VERSION 5.8 ;
BUSBITCHARS "[]" ;
DIVIDERCHAR "/" ;
UNITS
    DATABASE MICRONS 1000 ;
END UNITS

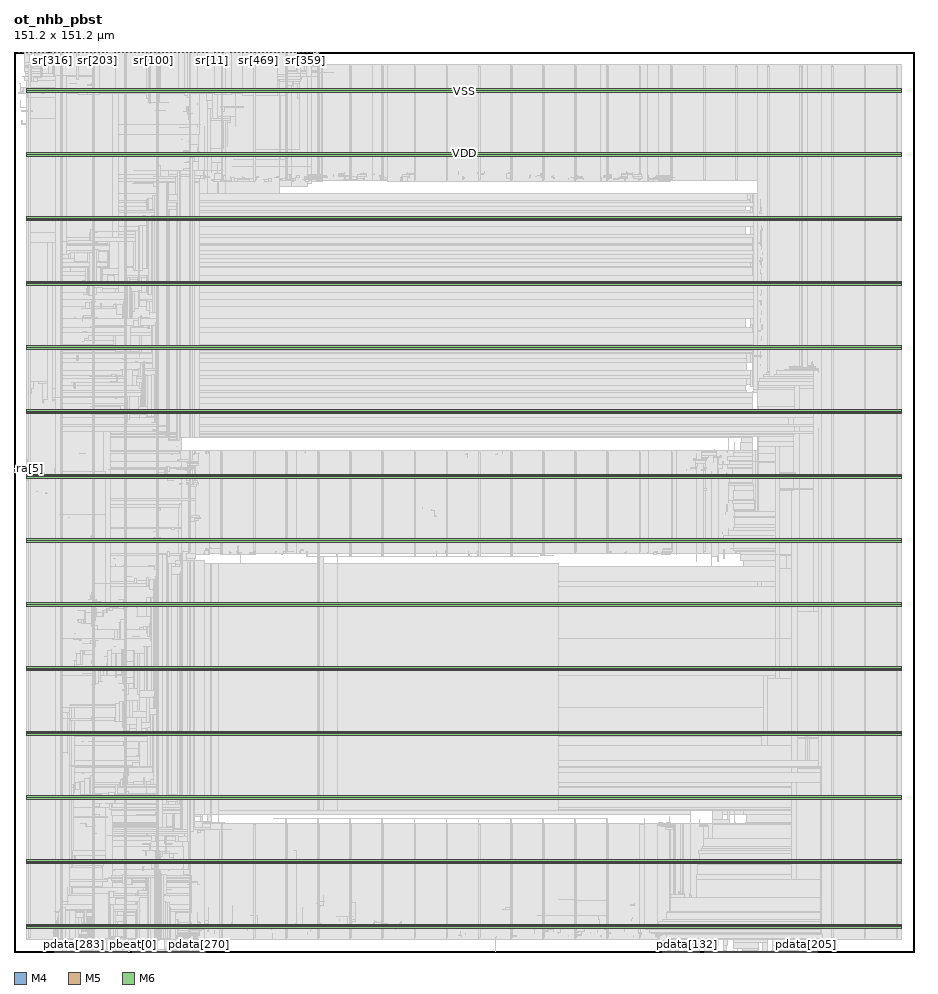
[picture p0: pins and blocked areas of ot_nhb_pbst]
MACRO ot_nhb_pbst
  FOREIGN ot_nhb_pbst 0 0 ;
  CLASS BLOCK ;
  SIZE 151.2 BY 151.2 ;
  PIN clk
    DIRECTION INPUT ;
    USE SIGNAL ;
    PORT
      LAYER M4 ;
        RECT  0 80.592 0.084 80.616 ;
    END
  END clk
  PIN pbeat[0]
    DIRECTION INPUT ;
    USE SIGNAL ;
    PORT
      LAYER M5 ;
        RECT  19.92 0 19.944 0.084 ;
    END
  END pbeat[0]
  PIN pbeat[1]
    DIRECTION INPUT ;
    USE SIGNAL ;
    PORT
      LAYER M5 ;
        RECT  20.016 0 20.04 0.084 ;
    END
  END pbeat[1]
  PIN pbeat[2]
    DIRECTION INPUT ;
    USE SIGNAL ;
    PORT
      LAYER M5 ;
        RECT  20.112 0 20.136 0.084 ;
    END
  END pbeat[2]
  PIN pbeat[3]
    DIRECTION INPUT ;
    USE SIGNAL ;
    PORT
      LAYER M5 ;
        RECT  20.208 0 20.232 0.084 ;
    END
  END pbeat[3]
  PIN pbeat[4]
    DIRECTION INPUT ;
    USE SIGNAL ;
    PORT
      LAYER M5 ;
        RECT  20.304 0 20.328 0.084 ;
    END
  END pbeat[4]
  PIN pbeat[5]
    DIRECTION INPUT ;
    USE SIGNAL ;
    PORT
      LAYER M5 ;
        RECT  20.4 0 20.424 0.084 ;
    END
  END pbeat[5]
  PIN pdata[0]
    DIRECTION INPUT ;
    USE SIGNAL ;
    PORT
      LAYER M5 ;
        RECT  20.496 0 20.52 0.084 ;
    END
  END pdata[0]
  PIN pdata[100]
    DIRECTION INPUT ;
    USE SIGNAL ;
    PORT
      LAYER M5 ;
        RECT  23.952 0 23.976 0.084 ;
    END
  END pdata[100]
  PIN pdata[101]
    DIRECTION INPUT ;
    USE SIGNAL ;
    PORT
      LAYER M5 ;
        RECT  24.048 0 24.072 0.084 ;
    END
  END pdata[101]
  PIN pdata[102]
    DIRECTION INPUT ;
    USE SIGNAL ;
    PORT
      LAYER M5 ;
        RECT  24.144 0 24.168 0.084 ;
    END
  END pdata[102]
  PIN pdata[103]
    DIRECTION INPUT ;
    USE SIGNAL ;
    PORT
      LAYER M5 ;
        RECT  24.24 0 24.264 0.084 ;
    END
  END pdata[103]
  PIN pdata[104]
    DIRECTION INPUT ;
    USE SIGNAL ;
    PORT
      LAYER M5 ;
        RECT  24.336 0 24.36 0.084 ;
    END
  END pdata[104]
  PIN pdata[105]
    DIRECTION INPUT ;
    USE SIGNAL ;
    PORT
      LAYER M5 ;
        RECT  24.432 0 24.456 0.084 ;
    END
  END pdata[105]
  PIN pdata[106]
    DIRECTION INPUT ;
    USE SIGNAL ;
    PORT
      LAYER M5 ;
        RECT  24.528 0 24.552 0.084 ;
    END
  END pdata[106]
  PIN pdata[107]
    DIRECTION INPUT ;
    USE SIGNAL ;
    PORT
      LAYER M5 ;
        RECT  24.624 0 24.648 0.084 ;
    END
  END pdata[107]
  PIN pdata[108]
    DIRECTION INPUT ;
    USE SIGNAL ;
    PORT
      LAYER M5 ;
        RECT  24.72 0 24.744 0.084 ;
    END
  END pdata[108]
  PIN pdata[109]
    DIRECTION INPUT ;
    USE SIGNAL ;
    PORT
      LAYER M5 ;
        RECT  24.816 0 24.84 0.084 ;
    END
  END pdata[109]
  PIN pdata[10]
    DIRECTION INPUT ;
    USE SIGNAL ;
    PORT
      LAYER M5 ;
        RECT  21.456 0 21.48 0.084 ;
    END
  END pdata[10]
  PIN pdata[110]
    DIRECTION INPUT ;
    USE SIGNAL ;
    PORT
      LAYER M5 ;
        RECT  24.912 0 24.936 0.084 ;
    END
  END pdata[110]
  PIN pdata[111]
    DIRECTION INPUT ;
    USE SIGNAL ;
    PORT
      LAYER M5 ;
        RECT  25.008 0 25.032 0.084 ;
    END
  END pdata[111]
  PIN pdata[112]
    DIRECTION INPUT ;
    USE SIGNAL ;
    PORT
      LAYER M5 ;
        RECT  25.104 0 25.128 0.084 ;
    END
  END pdata[112]
  PIN pdata[113]
    DIRECTION INPUT ;
    USE SIGNAL ;
    PORT
      LAYER M5 ;
        RECT  25.2 0 25.224 0.084 ;
    END
  END pdata[113]
  PIN pdata[114]
    DIRECTION INPUT ;
    USE SIGNAL ;
    PORT
      LAYER M5 ;
        RECT  25.296 0 25.32 0.084 ;
    END
  END pdata[114]
  PIN pdata[115]
    DIRECTION INPUT ;
    USE SIGNAL ;
    PORT
      LAYER M5 ;
        RECT  25.392 0 25.416 0.084 ;
    END
  END pdata[115]
  PIN pdata[116]
    DIRECTION INPUT ;
    USE SIGNAL ;
    PORT
      LAYER M5 ;
        RECT  25.488 0 25.512 0.084 ;
    END
  END pdata[116]
  PIN pdata[117]
    DIRECTION INPUT ;
    USE SIGNAL ;
    PORT
      LAYER M5 ;
        RECT  25.584 0 25.608 0.084 ;
    END
  END pdata[117]
  PIN pdata[118]
    DIRECTION INPUT ;
    USE SIGNAL ;
    PORT
      LAYER M5 ;
        RECT  25.68 0 25.704 0.084 ;
    END
  END pdata[118]
  PIN pdata[119]
    DIRECTION INPUT ;
    USE SIGNAL ;
    PORT
      LAYER M5 ;
        RECT  25.776 0 25.8 0.084 ;
    END
  END pdata[119]
  PIN pdata[11]
    DIRECTION INPUT ;
    USE SIGNAL ;
    PORT
      LAYER M5 ;
        RECT  21.552 0 21.576 0.084 ;
    END
  END pdata[11]
  PIN pdata[120]
    DIRECTION INPUT ;
    USE SIGNAL ;
    PORT
      LAYER M5 ;
        RECT  25.872 0 25.896 0.084 ;
    END
  END pdata[120]
  PIN pdata[121]
    DIRECTION INPUT ;
    USE SIGNAL ;
    PORT
      LAYER M5 ;
        RECT  25.968 0 25.992 0.084 ;
    END
  END pdata[121]
  PIN pdata[122]
    DIRECTION INPUT ;
    USE SIGNAL ;
    PORT
      LAYER M5 ;
        RECT  112.08 0 112.104 0.084 ;
    END
  END pdata[122]
  PIN pdata[123]
    DIRECTION INPUT ;
    USE SIGNAL ;
    PORT
      LAYER M5 ;
        RECT  112.176 0 112.2 0.084 ;
    END
  END pdata[123]
  PIN pdata[124]
    DIRECTION INPUT ;
    USE SIGNAL ;
    PORT
      LAYER M5 ;
        RECT  112.272 0 112.296 0.084 ;
    END
  END pdata[124]
  PIN pdata[125]
    DIRECTION INPUT ;
    USE SIGNAL ;
    PORT
      LAYER M5 ;
        RECT  112.368 0 112.392 0.084 ;
    END
  END pdata[125]
  PIN pdata[126]
    DIRECTION INPUT ;
    USE SIGNAL ;
    PORT
      LAYER M5 ;
        RECT  112.464 0 112.488 0.084 ;
    END
  END pdata[126]
  PIN pdata[127]
    DIRECTION INPUT ;
    USE SIGNAL ;
    PORT
      LAYER M5 ;
        RECT  112.56 0 112.584 0.084 ;
    END
  END pdata[127]
  PIN pdata[128]
    DIRECTION INPUT ;
    USE SIGNAL ;
    PORT
      LAYER M5 ;
        RECT  112.656 0 112.68 0.084 ;
    END
  END pdata[128]
  PIN pdata[129]
    DIRECTION INPUT ;
    USE SIGNAL ;
    PORT
      LAYER M5 ;
        RECT  112.752 0 112.776 0.084 ;
    END
  END pdata[129]
  PIN pdata[12]
    DIRECTION INPUT ;
    USE SIGNAL ;
    PORT
      LAYER M5 ;
        RECT  21.648 0 21.672 0.084 ;
    END
  END pdata[12]
  PIN pdata[130]
    DIRECTION INPUT ;
    USE SIGNAL ;
    PORT
      LAYER M5 ;
        RECT  112.848 0 112.872 0.084 ;
    END
  END pdata[130]
  PIN pdata[131]
    DIRECTION INPUT ;
    USE SIGNAL ;
    PORT
      LAYER M5 ;
        RECT  112.944 0 112.968 0.084 ;
    END
  END pdata[131]
  PIN pdata[132]
    DIRECTION INPUT ;
    USE SIGNAL ;
    PORT
      LAYER M5 ;
        RECT  113.04 0 113.064 0.084 ;
    END
  END pdata[132]
  PIN pdata[133]
    DIRECTION INPUT ;
    USE SIGNAL ;
    PORT
      LAYER M5 ;
        RECT  113.136 0 113.16 0.084 ;
    END
  END pdata[133]
  PIN pdata[134]
    DIRECTION INPUT ;
    USE SIGNAL ;
    PORT
      LAYER M5 ;
        RECT  113.232 0 113.256 0.084 ;
    END
  END pdata[134]
  PIN pdata[135]
    DIRECTION INPUT ;
    USE SIGNAL ;
    PORT
      LAYER M5 ;
        RECT  113.328 0 113.352 0.084 ;
    END
  END pdata[135]
  PIN pdata[136]
    DIRECTION INPUT ;
    USE SIGNAL ;
    PORT
      LAYER M5 ;
        RECT  113.424 0 113.448 0.084 ;
    END
  END pdata[136]
  PIN pdata[137]
    DIRECTION INPUT ;
    USE SIGNAL ;
    PORT
      LAYER M5 ;
        RECT  113.52 0 113.544 0.084 ;
    END
  END pdata[137]
  PIN pdata[138]
    DIRECTION INPUT ;
    USE SIGNAL ;
    PORT
      LAYER M5 ;
        RECT  113.616 0 113.64 0.084 ;
    END
  END pdata[138]
  PIN pdata[139]
    DIRECTION INPUT ;
    USE SIGNAL ;
    PORT
      LAYER M5 ;
        RECT  113.712 0 113.736 0.084 ;
    END
  END pdata[139]
  PIN pdata[13]
    DIRECTION INPUT ;
    USE SIGNAL ;
    PORT
      LAYER M5 ;
        RECT  21.744 0 21.768 0.084 ;
    END
  END pdata[13]
  PIN pdata[140]
    DIRECTION INPUT ;
    USE SIGNAL ;
    PORT
      LAYER M5 ;
        RECT  113.808 0 113.832 0.084 ;
    END
  END pdata[140]
  PIN pdata[141]
    DIRECTION INPUT ;
    USE SIGNAL ;
    PORT
      LAYER M5 ;
        RECT  113.904 0 113.928 0.084 ;
    END
  END pdata[141]
  PIN pdata[142]
    DIRECTION INPUT ;
    USE SIGNAL ;
    PORT
      LAYER M5 ;
        RECT  114 0 114.024 0.084 ;
    END
  END pdata[142]
  PIN pdata[143]
    DIRECTION INPUT ;
    USE SIGNAL ;
    PORT
      LAYER M5 ;
        RECT  114.096 0 114.12 0.084 ;
    END
  END pdata[143]
  PIN pdata[144]
    DIRECTION INPUT ;
    USE SIGNAL ;
    PORT
      LAYER M5 ;
        RECT  114.192 0 114.216 0.084 ;
    END
  END pdata[144]
  PIN pdata[145]
    DIRECTION INPUT ;
    USE SIGNAL ;
    PORT
      LAYER M5 ;
        RECT  114.288 0 114.312 0.084 ;
    END
  END pdata[145]
  PIN pdata[146]
    DIRECTION INPUT ;
    USE SIGNAL ;
    PORT
      LAYER M5 ;
        RECT  114.384 0 114.408 0.084 ;
    END
  END pdata[146]
  PIN pdata[147]
    DIRECTION INPUT ;
    USE SIGNAL ;
    PORT
      LAYER M5 ;
        RECT  114.48 0 114.504 0.084 ;
    END
  END pdata[147]
  PIN pdata[148]
    DIRECTION INPUT ;
    USE SIGNAL ;
    PORT
      LAYER M5 ;
        RECT  114.576 0 114.6 0.084 ;
    END
  END pdata[148]
  PIN pdata[149]
    DIRECTION INPUT ;
    USE SIGNAL ;
    PORT
      LAYER M5 ;
        RECT  114.672 0 114.696 0.084 ;
    END
  END pdata[149]
  PIN pdata[14]
    DIRECTION INPUT ;
    USE SIGNAL ;
    PORT
      LAYER M5 ;
        RECT  21.84 0 21.864 0.084 ;
    END
  END pdata[14]
  PIN pdata[150]
    DIRECTION INPUT ;
    USE SIGNAL ;
    PORT
      LAYER M5 ;
        RECT  114.768 0 114.792 0.084 ;
    END
  END pdata[150]
  PIN pdata[151]
    DIRECTION INPUT ;
    USE SIGNAL ;
    PORT
      LAYER M5 ;
        RECT  114.864 0 114.888 0.084 ;
    END
  END pdata[151]
  PIN pdata[152]
    DIRECTION INPUT ;
    USE SIGNAL ;
    PORT
      LAYER M5 ;
        RECT  114.96 0 114.984 0.084 ;
    END
  END pdata[152]
  PIN pdata[153]
    DIRECTION INPUT ;
    USE SIGNAL ;
    PORT
      LAYER M5 ;
        RECT  115.056 0 115.08 0.084 ;
    END
  END pdata[153]
  PIN pdata[154]
    DIRECTION INPUT ;
    USE SIGNAL ;
    PORT
      LAYER M5 ;
        RECT  118.992 0 119.016 0.084 ;
    END
  END pdata[154]
  PIN pdata[155]
    DIRECTION INPUT ;
    USE SIGNAL ;
    PORT
      LAYER M5 ;
        RECT  119.088 0 119.112 0.084 ;
    END
  END pdata[155]
  PIN pdata[156]
    DIRECTION INPUT ;
    USE SIGNAL ;
    PORT
      LAYER M5 ;
        RECT  119.184 0 119.208 0.084 ;
    END
  END pdata[156]
  PIN pdata[157]
    DIRECTION INPUT ;
    USE SIGNAL ;
    PORT
      LAYER M5 ;
        RECT  119.28 0 119.304 0.084 ;
    END
  END pdata[157]
  PIN pdata[158]
    DIRECTION INPUT ;
    USE SIGNAL ;
    PORT
      LAYER M5 ;
        RECT  119.376 0 119.4 0.084 ;
    END
  END pdata[158]
  PIN pdata[159]
    DIRECTION INPUT ;
    USE SIGNAL ;
    PORT
      LAYER M5 ;
        RECT  119.472 0 119.496 0.084 ;
    END
  END pdata[159]
  PIN pdata[15]
    DIRECTION INPUT ;
    USE SIGNAL ;
    PORT
      LAYER M5 ;
        RECT  21.936 0 21.96 0.084 ;
    END
  END pdata[15]
  PIN pdata[160]
    DIRECTION INPUT ;
    USE SIGNAL ;
    PORT
      LAYER M5 ;
        RECT  119.568 0 119.592 0.084 ;
    END
  END pdata[160]
  PIN pdata[161]
    DIRECTION INPUT ;
    USE SIGNAL ;
    PORT
      LAYER M5 ;
        RECT  119.664 0 119.688 0.084 ;
    END
  END pdata[161]
  PIN pdata[162]
    DIRECTION INPUT ;
    USE SIGNAL ;
    PORT
      LAYER M5 ;
        RECT  119.76 0 119.784 0.084 ;
    END
  END pdata[162]
  PIN pdata[163]
    DIRECTION INPUT ;
    USE SIGNAL ;
    PORT
      LAYER M5 ;
        RECT  119.856 0 119.88 0.084 ;
    END
  END pdata[163]
  PIN pdata[164]
    DIRECTION INPUT ;
    USE SIGNAL ;
    PORT
      LAYER M5 ;
        RECT  119.952 0 119.976 0.084 ;
    END
  END pdata[164]
  PIN pdata[165]
    DIRECTION INPUT ;
    USE SIGNAL ;
    PORT
      LAYER M5 ;
        RECT  120.048 0 120.072 0.084 ;
    END
  END pdata[165]
  PIN pdata[166]
    DIRECTION INPUT ;
    USE SIGNAL ;
    PORT
      LAYER M5 ;
        RECT  120.144 0 120.168 0.084 ;
    END
  END pdata[166]
  PIN pdata[167]
    DIRECTION INPUT ;
    USE SIGNAL ;
    PORT
      LAYER M5 ;
        RECT  120.24 0 120.264 0.084 ;
    END
  END pdata[167]
  PIN pdata[168]
    DIRECTION INPUT ;
    USE SIGNAL ;
    PORT
      LAYER M5 ;
        RECT  120.336 0 120.36 0.084 ;
    END
  END pdata[168]
  PIN pdata[169]
    DIRECTION INPUT ;
    USE SIGNAL ;
    PORT
      LAYER M5 ;
        RECT  120.432 0 120.456 0.084 ;
    END
  END pdata[169]
  PIN pdata[16]
    DIRECTION INPUT ;
    USE SIGNAL ;
    PORT
      LAYER M5 ;
        RECT  22.032 0 22.056 0.084 ;
    END
  END pdata[16]
  PIN pdata[170]
    DIRECTION INPUT ;
    USE SIGNAL ;
    PORT
      LAYER M5 ;
        RECT  120.528 0 120.552 0.084 ;
    END
  END pdata[170]
  PIN pdata[171]
    DIRECTION INPUT ;
    USE SIGNAL ;
    PORT
      LAYER M5 ;
        RECT  120.624 0 120.648 0.084 ;
    END
  END pdata[171]
  PIN pdata[172]
    DIRECTION INPUT ;
    USE SIGNAL ;
    PORT
      LAYER M5 ;
        RECT  120.72 0 120.744 0.084 ;
    END
  END pdata[172]
  PIN pdata[173]
    DIRECTION INPUT ;
    USE SIGNAL ;
    PORT
      LAYER M5 ;
        RECT  120.816 0 120.84 0.084 ;
    END
  END pdata[173]
  PIN pdata[174]
    DIRECTION INPUT ;
    USE SIGNAL ;
    PORT
      LAYER M5 ;
        RECT  120.912 0 120.936 0.084 ;
    END
  END pdata[174]
  PIN pdata[175]
    DIRECTION INPUT ;
    USE SIGNAL ;
    PORT
      LAYER M5 ;
        RECT  121.008 0 121.032 0.084 ;
    END
  END pdata[175]
  PIN pdata[176]
    DIRECTION INPUT ;
    USE SIGNAL ;
    PORT
      LAYER M5 ;
        RECT  121.104 0 121.128 0.084 ;
    END
  END pdata[176]
  PIN pdata[177]
    DIRECTION INPUT ;
    USE SIGNAL ;
    PORT
      LAYER M5 ;
        RECT  121.2 0 121.224 0.084 ;
    END
  END pdata[177]
  PIN pdata[178]
    DIRECTION INPUT ;
    USE SIGNAL ;
    PORT
      LAYER M5 ;
        RECT  121.296 0 121.32 0.084 ;
    END
  END pdata[178]
  PIN pdata[179]
    DIRECTION INPUT ;
    USE SIGNAL ;
    PORT
      LAYER M5 ;
        RECT  121.392 0 121.416 0.084 ;
    END
  END pdata[179]
  PIN pdata[17]
    DIRECTION INPUT ;
    USE SIGNAL ;
    PORT
      LAYER M5 ;
        RECT  22.128 0 22.152 0.084 ;
    END
  END pdata[17]
  PIN pdata[180]
    DIRECTION INPUT ;
    USE SIGNAL ;
    PORT
      LAYER M5 ;
        RECT  121.488 0 121.512 0.084 ;
    END
  END pdata[180]
  PIN pdata[181]
    DIRECTION INPUT ;
    USE SIGNAL ;
    PORT
      LAYER M5 ;
        RECT  121.584 0 121.608 0.084 ;
    END
  END pdata[181]
  PIN pdata[182]
    DIRECTION INPUT ;
    USE SIGNAL ;
    PORT
      LAYER M5 ;
        RECT  121.68 0 121.704 0.084 ;
    END
  END pdata[182]
  PIN pdata[183]
    DIRECTION INPUT ;
    USE SIGNAL ;
    PORT
      LAYER M5 ;
        RECT  121.776 0 121.8 0.084 ;
    END
  END pdata[183]
  PIN pdata[184]
    DIRECTION INPUT ;
    USE SIGNAL ;
    PORT
      LAYER M5 ;
        RECT  121.872 0 121.896 0.084 ;
    END
  END pdata[184]
  PIN pdata[185]
    DIRECTION INPUT ;
    USE SIGNAL ;
    PORT
      LAYER M5 ;
        RECT  121.968 0 121.992 0.084 ;
    END
  END pdata[185]
  PIN pdata[186]
    DIRECTION INPUT ;
    USE SIGNAL ;
    PORT
      LAYER M5 ;
        RECT  131.28 0 131.304 0.084 ;
    END
  END pdata[186]
  PIN pdata[187]
    DIRECTION INPUT ;
    USE SIGNAL ;
    PORT
      LAYER M5 ;
        RECT  131.376 0 131.4 0.084 ;
    END
  END pdata[187]
  PIN pdata[188]
    DIRECTION INPUT ;
    USE SIGNAL ;
    PORT
      LAYER M5 ;
        RECT  131.472 0 131.496 0.084 ;
    END
  END pdata[188]
  PIN pdata[189]
    DIRECTION INPUT ;
    USE SIGNAL ;
    PORT
      LAYER M5 ;
        RECT  131.568 0 131.592 0.084 ;
    END
  END pdata[189]
  PIN pdata[18]
    DIRECTION INPUT ;
    USE SIGNAL ;
    PORT
      LAYER M5 ;
        RECT  22.224 0 22.248 0.084 ;
    END
  END pdata[18]
  PIN pdata[190]
    DIRECTION INPUT ;
    USE SIGNAL ;
    PORT
      LAYER M5 ;
        RECT  131.664 0 131.688 0.084 ;
    END
  END pdata[190]
  PIN pdata[191]
    DIRECTION INPUT ;
    USE SIGNAL ;
    PORT
      LAYER M5 ;
        RECT  131.76 0 131.784 0.084 ;
    END
  END pdata[191]
  PIN pdata[192]
    DIRECTION INPUT ;
    USE SIGNAL ;
    PORT
      LAYER M5 ;
        RECT  131.856 0 131.88 0.084 ;
    END
  END pdata[192]
  PIN pdata[193]
    DIRECTION INPUT ;
    USE SIGNAL ;
    PORT
      LAYER M5 ;
        RECT  131.952 0 131.976 0.084 ;
    END
  END pdata[193]
  PIN pdata[194]
    DIRECTION INPUT ;
    USE SIGNAL ;
    PORT
      LAYER M5 ;
        RECT  132.048 0 132.072 0.084 ;
    END
  END pdata[194]
  PIN pdata[195]
    DIRECTION INPUT ;
    USE SIGNAL ;
    PORT
      LAYER M5 ;
        RECT  132.144 0 132.168 0.084 ;
    END
  END pdata[195]
  PIN pdata[196]
    DIRECTION INPUT ;
    USE SIGNAL ;
    PORT
      LAYER M5 ;
        RECT  132.24 0 132.264 0.084 ;
    END
  END pdata[196]
  PIN pdata[197]
    DIRECTION INPUT ;
    USE SIGNAL ;
    PORT
      LAYER M5 ;
        RECT  132.336 0 132.36 0.084 ;
    END
  END pdata[197]
  PIN pdata[198]
    DIRECTION INPUT ;
    USE SIGNAL ;
    PORT
      LAYER M5 ;
        RECT  132.432 0 132.456 0.084 ;
    END
  END pdata[198]
  PIN pdata[199]
    DIRECTION INPUT ;
    USE SIGNAL ;
    PORT
      LAYER M5 ;
        RECT  132.528 0 132.552 0.084 ;
    END
  END pdata[199]
  PIN pdata[19]
    DIRECTION INPUT ;
    USE SIGNAL ;
    PORT
      LAYER M5 ;
        RECT  22.32 0 22.344 0.084 ;
    END
  END pdata[19]
  PIN pdata[1]
    DIRECTION INPUT ;
    USE SIGNAL ;
    PORT
      LAYER M5 ;
        RECT  20.592 0 20.616 0.084 ;
    END
  END pdata[1]
  PIN pdata[200]
    DIRECTION INPUT ;
    USE SIGNAL ;
    PORT
      LAYER M5 ;
        RECT  132.624 0 132.648 0.084 ;
    END
  END pdata[200]
  PIN pdata[201]
    DIRECTION INPUT ;
    USE SIGNAL ;
    PORT
      LAYER M5 ;
        RECT  132.72 0 132.744 0.084 ;
    END
  END pdata[201]
  PIN pdata[202]
    DIRECTION INPUT ;
    USE SIGNAL ;
    PORT
      LAYER M5 ;
        RECT  132.816 0 132.84 0.084 ;
    END
  END pdata[202]
  PIN pdata[203]
    DIRECTION INPUT ;
    USE SIGNAL ;
    PORT
      LAYER M5 ;
        RECT  132.912 0 132.936 0.084 ;
    END
  END pdata[203]
  PIN pdata[204]
    DIRECTION INPUT ;
    USE SIGNAL ;
    PORT
      LAYER M5 ;
        RECT  133.008 0 133.032 0.084 ;
    END
  END pdata[204]
  PIN pdata[205]
    DIRECTION INPUT ;
    USE SIGNAL ;
    PORT
      LAYER M5 ;
        RECT  133.104 0 133.128 0.084 ;
    END
  END pdata[205]
  PIN pdata[206]
    DIRECTION INPUT ;
    USE SIGNAL ;
    PORT
      LAYER M5 ;
        RECT  133.2 0 133.224 0.084 ;
    END
  END pdata[206]
  PIN pdata[207]
    DIRECTION INPUT ;
    USE SIGNAL ;
    PORT
      LAYER M5 ;
        RECT  133.296 0 133.32 0.084 ;
    END
  END pdata[207]
  PIN pdata[208]
    DIRECTION INPUT ;
    USE SIGNAL ;
    PORT
      LAYER M5 ;
        RECT  133.392 0 133.416 0.084 ;
    END
  END pdata[208]
  PIN pdata[209]
    DIRECTION INPUT ;
    USE SIGNAL ;
    PORT
      LAYER M5 ;
        RECT  133.488 0 133.512 0.084 ;
    END
  END pdata[209]
  PIN pdata[20]
    DIRECTION INPUT ;
    USE SIGNAL ;
    PORT
      LAYER M5 ;
        RECT  22.416 0 22.44 0.084 ;
    END
  END pdata[20]
  PIN pdata[210]
    DIRECTION INPUT ;
    USE SIGNAL ;
    PORT
      LAYER M5 ;
        RECT  133.584 0 133.608 0.084 ;
    END
  END pdata[210]
  PIN pdata[211]
    DIRECTION INPUT ;
    USE SIGNAL ;
    PORT
      LAYER M5 ;
        RECT  133.68 0 133.704 0.084 ;
    END
  END pdata[211]
  PIN pdata[212]
    DIRECTION INPUT ;
    USE SIGNAL ;
    PORT
      LAYER M5 ;
        RECT  133.776 0 133.8 0.084 ;
    END
  END pdata[212]
  PIN pdata[213]
    DIRECTION INPUT ;
    USE SIGNAL ;
    PORT
      LAYER M5 ;
        RECT  133.872 0 133.896 0.084 ;
    END
  END pdata[213]
  PIN pdata[214]
    DIRECTION INPUT ;
    USE SIGNAL ;
    PORT
      LAYER M5 ;
        RECT  133.968 0 133.992 0.084 ;
    END
  END pdata[214]
  PIN pdata[215]
    DIRECTION INPUT ;
    USE SIGNAL ;
    PORT
      LAYER M5 ;
        RECT  134.064 0 134.088 0.084 ;
    END
  END pdata[215]
  PIN pdata[216]
    DIRECTION INPUT ;
    USE SIGNAL ;
    PORT
      LAYER M5 ;
        RECT  134.16 0 134.184 0.084 ;
    END
  END pdata[216]
  PIN pdata[217]
    DIRECTION INPUT ;
    USE SIGNAL ;
    PORT
      LAYER M5 ;
        RECT  134.256 0 134.28 0.084 ;
    END
  END pdata[217]
  PIN pdata[218]
    DIRECTION INPUT ;
    USE SIGNAL ;
    PORT
      LAYER M5 ;
        RECT  125.136 0 125.16 0.084 ;
    END
  END pdata[218]
  PIN pdata[219]
    DIRECTION INPUT ;
    USE SIGNAL ;
    PORT
      LAYER M5 ;
        RECT  125.232 0 125.256 0.084 ;
    END
  END pdata[219]
  PIN pdata[21]
    DIRECTION INPUT ;
    USE SIGNAL ;
    PORT
      LAYER M5 ;
        RECT  22.512 0 22.536 0.084 ;
    END
  END pdata[21]
  PIN pdata[220]
    DIRECTION INPUT ;
    USE SIGNAL ;
    PORT
      LAYER M5 ;
        RECT  125.328 0 125.352 0.084 ;
    END
  END pdata[220]
  PIN pdata[221]
    DIRECTION INPUT ;
    USE SIGNAL ;
    PORT
      LAYER M5 ;
        RECT  125.424 0 125.448 0.084 ;
    END
  END pdata[221]
  PIN pdata[222]
    DIRECTION INPUT ;
    USE SIGNAL ;
    PORT
      LAYER M5 ;
        RECT  125.52 0 125.544 0.084 ;
    END
  END pdata[222]
  PIN pdata[223]
    DIRECTION INPUT ;
    USE SIGNAL ;
    PORT
      LAYER M5 ;
        RECT  125.616 0 125.64 0.084 ;
    END
  END pdata[223]
  PIN pdata[224]
    DIRECTION INPUT ;
    USE SIGNAL ;
    PORT
      LAYER M5 ;
        RECT  125.712 0 125.736 0.084 ;
    END
  END pdata[224]
  PIN pdata[225]
    DIRECTION INPUT ;
    USE SIGNAL ;
    PORT
      LAYER M5 ;
        RECT  125.808 0 125.832 0.084 ;
    END
  END pdata[225]
  PIN pdata[226]
    DIRECTION INPUT ;
    USE SIGNAL ;
    PORT
      LAYER M5 ;
        RECT  125.904 0 125.928 0.084 ;
    END
  END pdata[226]
  PIN pdata[227]
    DIRECTION INPUT ;
    USE SIGNAL ;
    PORT
      LAYER M5 ;
        RECT  126 0 126.024 0.084 ;
    END
  END pdata[227]
  PIN pdata[228]
    DIRECTION INPUT ;
    USE SIGNAL ;
    PORT
      LAYER M5 ;
        RECT  126.096 0 126.12 0.084 ;
    END
  END pdata[228]
  PIN pdata[229]
    DIRECTION INPUT ;
    USE SIGNAL ;
    PORT
      LAYER M5 ;
        RECT  126.192 0 126.216 0.084 ;
    END
  END pdata[229]
  PIN pdata[22]
    DIRECTION INPUT ;
    USE SIGNAL ;
    PORT
      LAYER M5 ;
        RECT  22.608 0 22.632 0.084 ;
    END
  END pdata[22]
  PIN pdata[230]
    DIRECTION INPUT ;
    USE SIGNAL ;
    PORT
      LAYER M5 ;
        RECT  126.288 0 126.312 0.084 ;
    END
  END pdata[230]
  PIN pdata[231]
    DIRECTION INPUT ;
    USE SIGNAL ;
    PORT
      LAYER M5 ;
        RECT  126.384 0 126.408 0.084 ;
    END
  END pdata[231]
  PIN pdata[232]
    DIRECTION INPUT ;
    USE SIGNAL ;
    PORT
      LAYER M5 ;
        RECT  126.48 0 126.504 0.084 ;
    END
  END pdata[232]
  PIN pdata[233]
    DIRECTION INPUT ;
    USE SIGNAL ;
    PORT
      LAYER M5 ;
        RECT  126.576 0 126.6 0.084 ;
    END
  END pdata[233]
  PIN pdata[234]
    DIRECTION INPUT ;
    USE SIGNAL ;
    PORT
      LAYER M5 ;
        RECT  126.672 0 126.696 0.084 ;
    END
  END pdata[234]
  PIN pdata[235]
    DIRECTION INPUT ;
    USE SIGNAL ;
    PORT
      LAYER M5 ;
        RECT  126.768 0 126.792 0.084 ;
    END
  END pdata[235]
  PIN pdata[236]
    DIRECTION INPUT ;
    USE SIGNAL ;
    PORT
      LAYER M5 ;
        RECT  126.864 0 126.888 0.084 ;
    END
  END pdata[236]
  PIN pdata[237]
    DIRECTION INPUT ;
    USE SIGNAL ;
    PORT
      LAYER M5 ;
        RECT  126.96 0 126.984 0.084 ;
    END
  END pdata[237]
  PIN pdata[238]
    DIRECTION INPUT ;
    USE SIGNAL ;
    PORT
      LAYER M5 ;
        RECT  127.056 0 127.08 0.084 ;
    END
  END pdata[238]
  PIN pdata[239]
    DIRECTION INPUT ;
    USE SIGNAL ;
    PORT
      LAYER M5 ;
        RECT  127.152 0 127.176 0.084 ;
    END
  END pdata[239]
  PIN pdata[23]
    DIRECTION INPUT ;
    USE SIGNAL ;
    PORT
      LAYER M5 ;
        RECT  22.704 0 22.728 0.084 ;
    END
  END pdata[23]
  PIN pdata[240]
    DIRECTION INPUT ;
    USE SIGNAL ;
    PORT
      LAYER M5 ;
        RECT  127.248 0 127.272 0.084 ;
    END
  END pdata[240]
  PIN pdata[241]
    DIRECTION INPUT ;
    USE SIGNAL ;
    PORT
      LAYER M5 ;
        RECT  127.344 0 127.368 0.084 ;
    END
  END pdata[241]
  PIN pdata[242]
    DIRECTION INPUT ;
    USE SIGNAL ;
    PORT
      LAYER M5 ;
        RECT  127.44 0 127.464 0.084 ;
    END
  END pdata[242]
  PIN pdata[243]
    DIRECTION INPUT ;
    USE SIGNAL ;
    PORT
      LAYER M5 ;
        RECT  127.536 0 127.56 0.084 ;
    END
  END pdata[243]
  PIN pdata[244]
    DIRECTION INPUT ;
    USE SIGNAL ;
    PORT
      LAYER M5 ;
        RECT  127.632 0 127.656 0.084 ;
    END
  END pdata[244]
  PIN pdata[245]
    DIRECTION INPUT ;
    USE SIGNAL ;
    PORT
      LAYER M5 ;
        RECT  127.728 0 127.752 0.084 ;
    END
  END pdata[245]
  PIN pdata[246]
    DIRECTION INPUT ;
    USE SIGNAL ;
    PORT
      LAYER M5 ;
        RECT  127.824 0 127.848 0.084 ;
    END
  END pdata[246]
  PIN pdata[247]
    DIRECTION INPUT ;
    USE SIGNAL ;
    PORT
      LAYER M5 ;
        RECT  127.92 0 127.944 0.084 ;
    END
  END pdata[247]
  PIN pdata[248]
    DIRECTION INPUT ;
    USE SIGNAL ;
    PORT
      LAYER M5 ;
        RECT  128.016 0 128.04 0.084 ;
    END
  END pdata[248]
  PIN pdata[249]
    DIRECTION INPUT ;
    USE SIGNAL ;
    PORT
      LAYER M5 ;
        RECT  128.112 0 128.136 0.084 ;
    END
  END pdata[249]
  PIN pdata[24]
    DIRECTION INPUT ;
    USE SIGNAL ;
    PORT
      LAYER M5 ;
        RECT  22.8 0 22.824 0.084 ;
    END
  END pdata[24]
  PIN pdata[250]
    DIRECTION INPUT ;
    USE SIGNAL ;
    PORT
      LAYER M5 ;
        RECT  29.136 0 29.16 0.084 ;
    END
  END pdata[250]
  PIN pdata[251]
    DIRECTION INPUT ;
    USE SIGNAL ;
    PORT
      LAYER M5 ;
        RECT  29.232 0 29.256 0.084 ;
    END
  END pdata[251]
  PIN pdata[252]
    DIRECTION INPUT ;
    USE SIGNAL ;
    PORT
      LAYER M5 ;
        RECT  29.328 0 29.352 0.084 ;
    END
  END pdata[252]
  PIN pdata[253]
    DIRECTION INPUT ;
    USE SIGNAL ;
    PORT
      LAYER M5 ;
        RECT  29.424 0 29.448 0.084 ;
    END
  END pdata[253]
  PIN pdata[254]
    DIRECTION INPUT ;
    USE SIGNAL ;
    PORT
      LAYER M5 ;
        RECT  29.52 0 29.544 0.084 ;
    END
  END pdata[254]
  PIN pdata[255]
    DIRECTION INPUT ;
    USE SIGNAL ;
    PORT
      LAYER M5 ;
        RECT  29.616 0 29.64 0.084 ;
    END
  END pdata[255]
  PIN pdata[256]
    DIRECTION INPUT ;
    USE SIGNAL ;
    PORT
      LAYER M5 ;
        RECT  29.712 0 29.736 0.084 ;
    END
  END pdata[256]
  PIN pdata[257]
    DIRECTION INPUT ;
    USE SIGNAL ;
    PORT
      LAYER M5 ;
        RECT  29.808 0 29.832 0.084 ;
    END
  END pdata[257]
  PIN pdata[258]
    DIRECTION INPUT ;
    USE SIGNAL ;
    PORT
      LAYER M5 ;
        RECT  29.904 0 29.928 0.084 ;
    END
  END pdata[258]
  PIN pdata[259]
    DIRECTION INPUT ;
    USE SIGNAL ;
    PORT
      LAYER M5 ;
        RECT  30 0 30.024 0.084 ;
    END
  END pdata[259]
  PIN pdata[25]
    DIRECTION INPUT ;
    USE SIGNAL ;
    PORT
      LAYER M5 ;
        RECT  22.896 0 22.92 0.084 ;
    END
  END pdata[25]
  PIN pdata[260]
    DIRECTION INPUT ;
    USE SIGNAL ;
    PORT
      LAYER M5 ;
        RECT  30.096 0 30.12 0.084 ;
    END
  END pdata[260]
  PIN pdata[261]
    DIRECTION INPUT ;
    USE SIGNAL ;
    PORT
      LAYER M5 ;
        RECT  30.192 0 30.216 0.084 ;
    END
  END pdata[261]
  PIN pdata[262]
    DIRECTION INPUT ;
    USE SIGNAL ;
    PORT
      LAYER M5 ;
        RECT  30.288 0 30.312 0.084 ;
    END
  END pdata[262]
  PIN pdata[263]
    DIRECTION INPUT ;
    USE SIGNAL ;
    PORT
      LAYER M5 ;
        RECT  30.384 0 30.408 0.084 ;
    END
  END pdata[263]
  PIN pdata[264]
    DIRECTION INPUT ;
    USE SIGNAL ;
    PORT
      LAYER M5 ;
        RECT  30.48 0 30.504 0.084 ;
    END
  END pdata[264]
  PIN pdata[265]
    DIRECTION INPUT ;
    USE SIGNAL ;
    PORT
      LAYER M5 ;
        RECT  30.576 0 30.6 0.084 ;
    END
  END pdata[265]
  PIN pdata[266]
    DIRECTION INPUT ;
    USE SIGNAL ;
    PORT
      LAYER M5 ;
        RECT  30.672 0 30.696 0.084 ;
    END
  END pdata[266]
  PIN pdata[267]
    DIRECTION INPUT ;
    USE SIGNAL ;
    PORT
      LAYER M5 ;
        RECT  30.768 0 30.792 0.084 ;
    END
  END pdata[267]
  PIN pdata[268]
    DIRECTION INPUT ;
    USE SIGNAL ;
    PORT
      LAYER M5 ;
        RECT  30.864 0 30.888 0.084 ;
    END
  END pdata[268]
  PIN pdata[269]
    DIRECTION INPUT ;
    USE SIGNAL ;
    PORT
      LAYER M5 ;
        RECT  30.96 0 30.984 0.084 ;
    END
  END pdata[269]
  PIN pdata[26]
    DIRECTION INPUT ;
    USE SIGNAL ;
    PORT
      LAYER M5 ;
        RECT  13.008 0 13.032 0.084 ;
    END
  END pdata[26]
  PIN pdata[270]
    DIRECTION INPUT ;
    USE SIGNAL ;
    PORT
      LAYER M5 ;
        RECT  31.056 0 31.08 0.084 ;
    END
  END pdata[270]
  PIN pdata[271]
    DIRECTION INPUT ;
    USE SIGNAL ;
    PORT
      LAYER M5 ;
        RECT  31.152 0 31.176 0.084 ;
    END
  END pdata[271]
  PIN pdata[272]
    DIRECTION INPUT ;
    USE SIGNAL ;
    PORT
      LAYER M5 ;
        RECT  31.248 0 31.272 0.084 ;
    END
  END pdata[272]
  PIN pdata[273]
    DIRECTION INPUT ;
    USE SIGNAL ;
    PORT
      LAYER M5 ;
        RECT  31.344 0 31.368 0.084 ;
    END
  END pdata[273]
  PIN pdata[274]
    DIRECTION INPUT ;
    USE SIGNAL ;
    PORT
      LAYER M5 ;
        RECT  31.44 0 31.464 0.084 ;
    END
  END pdata[274]
  PIN pdata[275]
    DIRECTION INPUT ;
    USE SIGNAL ;
    PORT
      LAYER M5 ;
        RECT  31.536 0 31.56 0.084 ;
    END
  END pdata[275]
  PIN pdata[276]
    DIRECTION INPUT ;
    USE SIGNAL ;
    PORT
      LAYER M5 ;
        RECT  31.632 0 31.656 0.084 ;
    END
  END pdata[276]
  PIN pdata[277]
    DIRECTION INPUT ;
    USE SIGNAL ;
    PORT
      LAYER M5 ;
        RECT  31.728 0 31.752 0.084 ;
    END
  END pdata[277]
  PIN pdata[278]
    DIRECTION INPUT ;
    USE SIGNAL ;
    PORT
      LAYER M5 ;
        RECT  31.824 0 31.848 0.084 ;
    END
  END pdata[278]
  PIN pdata[279]
    DIRECTION INPUT ;
    USE SIGNAL ;
    PORT
      LAYER M5 ;
        RECT  31.92 0 31.944 0.084 ;
    END
  END pdata[279]
  PIN pdata[27]
    DIRECTION INPUT ;
    USE SIGNAL ;
    PORT
      LAYER M5 ;
        RECT  13.104 0 13.128 0.084 ;
    END
  END pdata[27]
  PIN pdata[280]
    DIRECTION INPUT ;
    USE SIGNAL ;
    PORT
      LAYER M5 ;
        RECT  32.016 0 32.04 0.084 ;
    END
  END pdata[280]
  PIN pdata[281]
    DIRECTION INPUT ;
    USE SIGNAL ;
    PORT
      LAYER M5 ;
        RECT  32.112 0 32.136 0.084 ;
    END
  END pdata[281]
  PIN pdata[282]
    DIRECTION INPUT ;
    USE SIGNAL ;
    PORT
      LAYER M5 ;
        RECT  9.936 0 9.96 0.084 ;
    END
  END pdata[282]
  PIN pdata[283]
    DIRECTION INPUT ;
    USE SIGNAL ;
    PORT
      LAYER M5 ;
        RECT  10.032 0 10.056 0.084 ;
    END
  END pdata[283]
  PIN pdata[284]
    DIRECTION INPUT ;
    USE SIGNAL ;
    PORT
      LAYER M5 ;
        RECT  10.128 0 10.152 0.084 ;
    END
  END pdata[284]
  PIN pdata[285]
    DIRECTION INPUT ;
    USE SIGNAL ;
    PORT
      LAYER M5 ;
        RECT  10.224 0 10.248 0.084 ;
    END
  END pdata[285]
  PIN pdata[286]
    DIRECTION INPUT ;
    USE SIGNAL ;
    PORT
      LAYER M5 ;
        RECT  10.32 0 10.344 0.084 ;
    END
  END pdata[286]
  PIN pdata[287]
    DIRECTION INPUT ;
    USE SIGNAL ;
    PORT
      LAYER M5 ;
        RECT  10.416 0 10.44 0.084 ;
    END
  END pdata[287]
  PIN pdata[288]
    DIRECTION INPUT ;
    USE SIGNAL ;
    PORT
      LAYER M5 ;
        RECT  10.512 0 10.536 0.084 ;
    END
  END pdata[288]
  PIN pdata[289]
    DIRECTION INPUT ;
    USE SIGNAL ;
    PORT
      LAYER M5 ;
        RECT  10.608 0 10.632 0.084 ;
    END
  END pdata[289]
  PIN pdata[28]
    DIRECTION INPUT ;
    USE SIGNAL ;
    PORT
      LAYER M5 ;
        RECT  13.2 0 13.224 0.084 ;
    END
  END pdata[28]
  PIN pdata[290]
    DIRECTION INPUT ;
    USE SIGNAL ;
    PORT
      LAYER M5 ;
        RECT  10.704 0 10.728 0.084 ;
    END
  END pdata[290]
  PIN pdata[291]
    DIRECTION INPUT ;
    USE SIGNAL ;
    PORT
      LAYER M5 ;
        RECT  10.8 0 10.824 0.084 ;
    END
  END pdata[291]
  PIN pdata[292]
    DIRECTION INPUT ;
    USE SIGNAL ;
    PORT
      LAYER M5 ;
        RECT  10.896 0 10.92 0.084 ;
    END
  END pdata[292]
  PIN pdata[293]
    DIRECTION INPUT ;
    USE SIGNAL ;
    PORT
      LAYER M5 ;
        RECT  10.992 0 11.016 0.084 ;
    END
  END pdata[293]
  PIN pdata[294]
    DIRECTION INPUT ;
    USE SIGNAL ;
    PORT
      LAYER M5 ;
        RECT  11.088 0 11.112 0.084 ;
    END
  END pdata[294]
  PIN pdata[295]
    DIRECTION INPUT ;
    USE SIGNAL ;
    PORT
      LAYER M5 ;
        RECT  11.184 0 11.208 0.084 ;
    END
  END pdata[295]
  PIN pdata[296]
    DIRECTION INPUT ;
    USE SIGNAL ;
    PORT
      LAYER M5 ;
        RECT  11.28 0 11.304 0.084 ;
    END
  END pdata[296]
  PIN pdata[297]
    DIRECTION INPUT ;
    USE SIGNAL ;
    PORT
      LAYER M5 ;
        RECT  11.376 0 11.4 0.084 ;
    END
  END pdata[297]
  PIN pdata[298]
    DIRECTION INPUT ;
    USE SIGNAL ;
    PORT
      LAYER M5 ;
        RECT  11.472 0 11.496 0.084 ;
    END
  END pdata[298]
  PIN pdata[299]
    DIRECTION INPUT ;
    USE SIGNAL ;
    PORT
      LAYER M5 ;
        RECT  11.568 0 11.592 0.084 ;
    END
  END pdata[299]
  PIN pdata[29]
    DIRECTION INPUT ;
    USE SIGNAL ;
    PORT
      LAYER M5 ;
        RECT  13.296 0 13.32 0.084 ;
    END
  END pdata[29]
  PIN pdata[2]
    DIRECTION INPUT ;
    USE SIGNAL ;
    PORT
      LAYER M5 ;
        RECT  20.688 0 20.712 0.084 ;
    END
  END pdata[2]
  PIN pdata[300]
    DIRECTION INPUT ;
    USE SIGNAL ;
    PORT
      LAYER M5 ;
        RECT  11.664 0 11.688 0.084 ;
    END
  END pdata[300]
  PIN pdata[301]
    DIRECTION INPUT ;
    USE SIGNAL ;
    PORT
      LAYER M5 ;
        RECT  11.76 0 11.784 0.084 ;
    END
  END pdata[301]
  PIN pdata[302]
    DIRECTION INPUT ;
    USE SIGNAL ;
    PORT
      LAYER M5 ;
        RECT  11.856 0 11.88 0.084 ;
    END
  END pdata[302]
  PIN pdata[303]
    DIRECTION INPUT ;
    USE SIGNAL ;
    PORT
      LAYER M5 ;
        RECT  11.952 0 11.976 0.084 ;
    END
  END pdata[303]
  PIN pdata[304]
    DIRECTION INPUT ;
    USE SIGNAL ;
    PORT
      LAYER M5 ;
        RECT  12.048 0 12.072 0.084 ;
    END
  END pdata[304]
  PIN pdata[305]
    DIRECTION INPUT ;
    USE SIGNAL ;
    PORT
      LAYER M5 ;
        RECT  12.144 0 12.168 0.084 ;
    END
  END pdata[305]
  PIN pdata[306]
    DIRECTION INPUT ;
    USE SIGNAL ;
    PORT
      LAYER M5 ;
        RECT  12.24 0 12.264 0.084 ;
    END
  END pdata[306]
  PIN pdata[307]
    DIRECTION INPUT ;
    USE SIGNAL ;
    PORT
      LAYER M5 ;
        RECT  12.336 0 12.36 0.084 ;
    END
  END pdata[307]
  PIN pdata[308]
    DIRECTION INPUT ;
    USE SIGNAL ;
    PORT
      LAYER M5 ;
        RECT  12.432 0 12.456 0.084 ;
    END
  END pdata[308]
  PIN pdata[309]
    DIRECTION INPUT ;
    USE SIGNAL ;
    PORT
      LAYER M5 ;
        RECT  12.528 0 12.552 0.084 ;
    END
  END pdata[309]
  PIN pdata[30]
    DIRECTION INPUT ;
    USE SIGNAL ;
    PORT
      LAYER M5 ;
        RECT  13.392 0 13.416 0.084 ;
    END
  END pdata[30]
  PIN pdata[310]
    DIRECTION INPUT ;
    USE SIGNAL ;
    PORT
      LAYER M5 ;
        RECT  12.624 0 12.648 0.084 ;
    END
  END pdata[310]
  PIN pdata[311]
    DIRECTION INPUT ;
    USE SIGNAL ;
    PORT
      LAYER M5 ;
        RECT  12.72 0 12.744 0.084 ;
    END
  END pdata[311]
  PIN pdata[312]
    DIRECTION INPUT ;
    USE SIGNAL ;
    PORT
      LAYER M5 ;
        RECT  12.816 0 12.84 0.084 ;
    END
  END pdata[312]
  PIN pdata[313]
    DIRECTION INPUT ;
    USE SIGNAL ;
    PORT
      LAYER M5 ;
        RECT  12.912 0 12.936 0.084 ;
    END
  END pdata[313]
  PIN pdata[314]
    DIRECTION INPUT ;
    USE SIGNAL ;
    PORT
      LAYER M5 ;
        RECT  16.08 0 16.104 0.084 ;
    END
  END pdata[314]
  PIN pdata[315]
    DIRECTION INPUT ;
    USE SIGNAL ;
    PORT
      LAYER M5 ;
        RECT  16.176 0 16.2 0.084 ;
    END
  END pdata[315]
  PIN pdata[316]
    DIRECTION INPUT ;
    USE SIGNAL ;
    PORT
      LAYER M5 ;
        RECT  16.272 0 16.296 0.084 ;
    END
  END pdata[316]
  PIN pdata[317]
    DIRECTION INPUT ;
    USE SIGNAL ;
    PORT
      LAYER M5 ;
        RECT  16.368 0 16.392 0.084 ;
    END
  END pdata[317]
  PIN pdata[318]
    DIRECTION INPUT ;
    USE SIGNAL ;
    PORT
      LAYER M5 ;
        RECT  16.464 0 16.488 0.084 ;
    END
  END pdata[318]
  PIN pdata[319]
    DIRECTION INPUT ;
    USE SIGNAL ;
    PORT
      LAYER M5 ;
        RECT  16.56 0 16.584 0.084 ;
    END
  END pdata[319]
  PIN pdata[31]
    DIRECTION INPUT ;
    USE SIGNAL ;
    PORT
      LAYER M5 ;
        RECT  13.488 0 13.512 0.084 ;
    END
  END pdata[31]
  PIN pdata[320]
    DIRECTION INPUT ;
    USE SIGNAL ;
    PORT
      LAYER M5 ;
        RECT  16.656 0 16.68 0.084 ;
    END
  END pdata[320]
  PIN pdata[321]
    DIRECTION INPUT ;
    USE SIGNAL ;
    PORT
      LAYER M5 ;
        RECT  16.752 0 16.776 0.084 ;
    END
  END pdata[321]
  PIN pdata[322]
    DIRECTION INPUT ;
    USE SIGNAL ;
    PORT
      LAYER M5 ;
        RECT  16.848 0 16.872 0.084 ;
    END
  END pdata[322]
  PIN pdata[323]
    DIRECTION INPUT ;
    USE SIGNAL ;
    PORT
      LAYER M5 ;
        RECT  16.944 0 16.968 0.084 ;
    END
  END pdata[323]
  PIN pdata[324]
    DIRECTION INPUT ;
    USE SIGNAL ;
    PORT
      LAYER M5 ;
        RECT  17.04 0 17.064 0.084 ;
    END
  END pdata[324]
  PIN pdata[325]
    DIRECTION INPUT ;
    USE SIGNAL ;
    PORT
      LAYER M5 ;
        RECT  17.136 0 17.16 0.084 ;
    END
  END pdata[325]
  PIN pdata[326]
    DIRECTION INPUT ;
    USE SIGNAL ;
    PORT
      LAYER M5 ;
        RECT  17.232 0 17.256 0.084 ;
    END
  END pdata[326]
  PIN pdata[327]
    DIRECTION INPUT ;
    USE SIGNAL ;
    PORT
      LAYER M5 ;
        RECT  17.328 0 17.352 0.084 ;
    END
  END pdata[327]
  PIN pdata[328]
    DIRECTION INPUT ;
    USE SIGNAL ;
    PORT
      LAYER M5 ;
        RECT  17.424 0 17.448 0.084 ;
    END
  END pdata[328]
  PIN pdata[329]
    DIRECTION INPUT ;
    USE SIGNAL ;
    PORT
      LAYER M5 ;
        RECT  17.52 0 17.544 0.084 ;
    END
  END pdata[329]
  PIN pdata[32]
    DIRECTION INPUT ;
    USE SIGNAL ;
    PORT
      LAYER M5 ;
        RECT  13.584 0 13.608 0.084 ;
    END
  END pdata[32]
  PIN pdata[330]
    DIRECTION INPUT ;
    USE SIGNAL ;
    PORT
      LAYER M5 ;
        RECT  17.616 0 17.64 0.084 ;
    END
  END pdata[330]
  PIN pdata[331]
    DIRECTION INPUT ;
    USE SIGNAL ;
    PORT
      LAYER M5 ;
        RECT  17.712 0 17.736 0.084 ;
    END
  END pdata[331]
  PIN pdata[332]
    DIRECTION INPUT ;
    USE SIGNAL ;
    PORT
      LAYER M5 ;
        RECT  17.808 0 17.832 0.084 ;
    END
  END pdata[332]
  PIN pdata[333]
    DIRECTION INPUT ;
    USE SIGNAL ;
    PORT
      LAYER M5 ;
        RECT  17.904 0 17.928 0.084 ;
    END
  END pdata[333]
  PIN pdata[334]
    DIRECTION INPUT ;
    USE SIGNAL ;
    PORT
      LAYER M5 ;
        RECT  18 0 18.024 0.084 ;
    END
  END pdata[334]
  PIN pdata[335]
    DIRECTION INPUT ;
    USE SIGNAL ;
    PORT
      LAYER M5 ;
        RECT  18.096 0 18.12 0.084 ;
    END
  END pdata[335]
  PIN pdata[336]
    DIRECTION INPUT ;
    USE SIGNAL ;
    PORT
      LAYER M5 ;
        RECT  18.192 0 18.216 0.084 ;
    END
  END pdata[336]
  PIN pdata[337]
    DIRECTION INPUT ;
    USE SIGNAL ;
    PORT
      LAYER M5 ;
        RECT  18.288 0 18.312 0.084 ;
    END
  END pdata[337]
  PIN pdata[338]
    DIRECTION INPUT ;
    USE SIGNAL ;
    PORT
      LAYER M5 ;
        RECT  18.384 0 18.408 0.084 ;
    END
  END pdata[338]
  PIN pdata[339]
    DIRECTION INPUT ;
    USE SIGNAL ;
    PORT
      LAYER M5 ;
        RECT  18.48 0 18.504 0.084 ;
    END
  END pdata[339]
  PIN pdata[33]
    DIRECTION INPUT ;
    USE SIGNAL ;
    PORT
      LAYER M5 ;
        RECT  13.68 0 13.704 0.084 ;
    END
  END pdata[33]
  PIN pdata[340]
    DIRECTION INPUT ;
    USE SIGNAL ;
    PORT
      LAYER M5 ;
        RECT  18.576 0 18.6 0.084 ;
    END
  END pdata[340]
  PIN pdata[341]
    DIRECTION INPUT ;
    USE SIGNAL ;
    PORT
      LAYER M5 ;
        RECT  18.672 0 18.696 0.084 ;
    END
  END pdata[341]
  PIN pdata[342]
    DIRECTION INPUT ;
    USE SIGNAL ;
    PORT
      LAYER M5 ;
        RECT  18.768 0 18.792 0.084 ;
    END
  END pdata[342]
  PIN pdata[343]
    DIRECTION INPUT ;
    USE SIGNAL ;
    PORT
      LAYER M5 ;
        RECT  18.864 0 18.888 0.084 ;
    END
  END pdata[343]
  PIN pdata[344]
    DIRECTION INPUT ;
    USE SIGNAL ;
    PORT
      LAYER M5 ;
        RECT  18.96 0 18.984 0.084 ;
    END
  END pdata[344]
  PIN pdata[345]
    DIRECTION INPUT ;
    USE SIGNAL ;
    PORT
      LAYER M5 ;
        RECT  19.056 0 19.08 0.084 ;
    END
  END pdata[345]
  PIN pdata[346]
    DIRECTION INPUT ;
    USE SIGNAL ;
    PORT
      LAYER M5 ;
        RECT  26.064 0 26.088 0.084 ;
    END
  END pdata[346]
  PIN pdata[347]
    DIRECTION INPUT ;
    USE SIGNAL ;
    PORT
      LAYER M5 ;
        RECT  26.16 0 26.184 0.084 ;
    END
  END pdata[347]
  PIN pdata[348]
    DIRECTION INPUT ;
    USE SIGNAL ;
    PORT
      LAYER M5 ;
        RECT  26.256 0 26.28 0.084 ;
    END
  END pdata[348]
  PIN pdata[349]
    DIRECTION INPUT ;
    USE SIGNAL ;
    PORT
      LAYER M5 ;
        RECT  26.352 0 26.376 0.084 ;
    END
  END pdata[349]
  PIN pdata[34]
    DIRECTION INPUT ;
    USE SIGNAL ;
    PORT
      LAYER M5 ;
        RECT  13.776 0 13.8 0.084 ;
    END
  END pdata[34]
  PIN pdata[350]
    DIRECTION INPUT ;
    USE SIGNAL ;
    PORT
      LAYER M5 ;
        RECT  26.448 0 26.472 0.084 ;
    END
  END pdata[350]
  PIN pdata[351]
    DIRECTION INPUT ;
    USE SIGNAL ;
    PORT
      LAYER M5 ;
        RECT  26.544 0 26.568 0.084 ;
    END
  END pdata[351]
  PIN pdata[352]
    DIRECTION INPUT ;
    USE SIGNAL ;
    PORT
      LAYER M5 ;
        RECT  26.64 0 26.664 0.084 ;
    END
  END pdata[352]
  PIN pdata[353]
    DIRECTION INPUT ;
    USE SIGNAL ;
    PORT
      LAYER M5 ;
        RECT  26.736 0 26.76 0.084 ;
    END
  END pdata[353]
  PIN pdata[354]
    DIRECTION INPUT ;
    USE SIGNAL ;
    PORT
      LAYER M5 ;
        RECT  26.832 0 26.856 0.084 ;
    END
  END pdata[354]
  PIN pdata[355]
    DIRECTION INPUT ;
    USE SIGNAL ;
    PORT
      LAYER M5 ;
        RECT  26.928 0 26.952 0.084 ;
    END
  END pdata[355]
  PIN pdata[356]
    DIRECTION INPUT ;
    USE SIGNAL ;
    PORT
      LAYER M5 ;
        RECT  27.024 0 27.048 0.084 ;
    END
  END pdata[356]
  PIN pdata[357]
    DIRECTION INPUT ;
    USE SIGNAL ;
    PORT
      LAYER M5 ;
        RECT  27.12 0 27.144 0.084 ;
    END
  END pdata[357]
  PIN pdata[358]
    DIRECTION INPUT ;
    USE SIGNAL ;
    PORT
      LAYER M5 ;
        RECT  27.216 0 27.24 0.084 ;
    END
  END pdata[358]
  PIN pdata[359]
    DIRECTION INPUT ;
    USE SIGNAL ;
    PORT
      LAYER M5 ;
        RECT  27.312 0 27.336 0.084 ;
    END
  END pdata[359]
  PIN pdata[35]
    DIRECTION INPUT ;
    USE SIGNAL ;
    PORT
      LAYER M5 ;
        RECT  13.872 0 13.896 0.084 ;
    END
  END pdata[35]
  PIN pdata[360]
    DIRECTION INPUT ;
    USE SIGNAL ;
    PORT
      LAYER M5 ;
        RECT  27.408 0 27.432 0.084 ;
    END
  END pdata[360]
  PIN pdata[361]
    DIRECTION INPUT ;
    USE SIGNAL ;
    PORT
      LAYER M5 ;
        RECT  27.504 0 27.528 0.084 ;
    END
  END pdata[361]
  PIN pdata[362]
    DIRECTION INPUT ;
    USE SIGNAL ;
    PORT
      LAYER M5 ;
        RECT  27.6 0 27.624 0.084 ;
    END
  END pdata[362]
  PIN pdata[363]
    DIRECTION INPUT ;
    USE SIGNAL ;
    PORT
      LAYER M5 ;
        RECT  27.696 0 27.72 0.084 ;
    END
  END pdata[363]
  PIN pdata[364]
    DIRECTION INPUT ;
    USE SIGNAL ;
    PORT
      LAYER M5 ;
        RECT  27.792 0 27.816 0.084 ;
    END
  END pdata[364]
  PIN pdata[365]
    DIRECTION INPUT ;
    USE SIGNAL ;
    PORT
      LAYER M5 ;
        RECT  27.888 0 27.912 0.084 ;
    END
  END pdata[365]
  PIN pdata[366]
    DIRECTION INPUT ;
    USE SIGNAL ;
    PORT
      LAYER M5 ;
        RECT  27.984 0 28.008 0.084 ;
    END
  END pdata[366]
  PIN pdata[367]
    DIRECTION INPUT ;
    USE SIGNAL ;
    PORT
      LAYER M5 ;
        RECT  28.08 0 28.104 0.084 ;
    END
  END pdata[367]
  PIN pdata[368]
    DIRECTION INPUT ;
    USE SIGNAL ;
    PORT
      LAYER M5 ;
        RECT  28.176 0 28.2 0.084 ;
    END
  END pdata[368]
  PIN pdata[369]
    DIRECTION INPUT ;
    USE SIGNAL ;
    PORT
      LAYER M5 ;
        RECT  28.272 0 28.296 0.084 ;
    END
  END pdata[369]
  PIN pdata[36]
    DIRECTION INPUT ;
    USE SIGNAL ;
    PORT
      LAYER M5 ;
        RECT  13.968 0 13.992 0.084 ;
    END
  END pdata[36]
  PIN pdata[370]
    DIRECTION INPUT ;
    USE SIGNAL ;
    PORT
      LAYER M5 ;
        RECT  28.368 0 28.392 0.084 ;
    END
  END pdata[370]
  PIN pdata[371]
    DIRECTION INPUT ;
    USE SIGNAL ;
    PORT
      LAYER M5 ;
        RECT  28.464 0 28.488 0.084 ;
    END
  END pdata[371]
  PIN pdata[372]
    DIRECTION INPUT ;
    USE SIGNAL ;
    PORT
      LAYER M5 ;
        RECT  28.56 0 28.584 0.084 ;
    END
  END pdata[372]
  PIN pdata[373]
    DIRECTION INPUT ;
    USE SIGNAL ;
    PORT
      LAYER M5 ;
        RECT  28.656 0 28.68 0.084 ;
    END
  END pdata[373]
  PIN pdata[374]
    DIRECTION INPUT ;
    USE SIGNAL ;
    PORT
      LAYER M5 ;
        RECT  28.752 0 28.776 0.084 ;
    END
  END pdata[374]
  PIN pdata[375]
    DIRECTION INPUT ;
    USE SIGNAL ;
    PORT
      LAYER M5 ;
        RECT  28.848 0 28.872 0.084 ;
    END
  END pdata[375]
  PIN pdata[376]
    DIRECTION INPUT ;
    USE SIGNAL ;
    PORT
      LAYER M5 ;
        RECT  28.944 0 28.968 0.084 ;
    END
  END pdata[376]
  PIN pdata[377]
    DIRECTION INPUT ;
    USE SIGNAL ;
    PORT
      LAYER M5 ;
        RECT  29.04 0 29.064 0.084 ;
    END
  END pdata[377]
  PIN pdata[378]
    DIRECTION INPUT ;
    USE SIGNAL ;
    PORT
      LAYER M5 ;
        RECT  109.008 0 109.032 0.084 ;
    END
  END pdata[378]
  PIN pdata[379]
    DIRECTION INPUT ;
    USE SIGNAL ;
    PORT
      LAYER M5 ;
        RECT  109.104 0 109.128 0.084 ;
    END
  END pdata[379]
  PIN pdata[37]
    DIRECTION INPUT ;
    USE SIGNAL ;
    PORT
      LAYER M5 ;
        RECT  14.064 0 14.088 0.084 ;
    END
  END pdata[37]
  PIN pdata[380]
    DIRECTION INPUT ;
    USE SIGNAL ;
    PORT
      LAYER M5 ;
        RECT  109.2 0 109.224 0.084 ;
    END
  END pdata[380]
  PIN pdata[381]
    DIRECTION INPUT ;
    USE SIGNAL ;
    PORT
      LAYER M5 ;
        RECT  109.296 0 109.32 0.084 ;
    END
  END pdata[381]
  PIN pdata[382]
    DIRECTION INPUT ;
    USE SIGNAL ;
    PORT
      LAYER M5 ;
        RECT  109.392 0 109.416 0.084 ;
    END
  END pdata[382]
  PIN pdata[383]
    DIRECTION INPUT ;
    USE SIGNAL ;
    PORT
      LAYER M5 ;
        RECT  109.488 0 109.512 0.084 ;
    END
  END pdata[383]
  PIN pdata[384]
    DIRECTION INPUT ;
    USE SIGNAL ;
    PORT
      LAYER M5 ;
        RECT  109.584 0 109.608 0.084 ;
    END
  END pdata[384]
  PIN pdata[385]
    DIRECTION INPUT ;
    USE SIGNAL ;
    PORT
      LAYER M5 ;
        RECT  109.68 0 109.704 0.084 ;
    END
  END pdata[385]
  PIN pdata[386]
    DIRECTION INPUT ;
    USE SIGNAL ;
    PORT
      LAYER M5 ;
        RECT  109.776 0 109.8 0.084 ;
    END
  END pdata[386]
  PIN pdata[387]
    DIRECTION INPUT ;
    USE SIGNAL ;
    PORT
      LAYER M5 ;
        RECT  109.872 0 109.896 0.084 ;
    END
  END pdata[387]
  PIN pdata[388]
    DIRECTION INPUT ;
    USE SIGNAL ;
    PORT
      LAYER M5 ;
        RECT  109.968 0 109.992 0.084 ;
    END
  END pdata[388]
  PIN pdata[389]
    DIRECTION INPUT ;
    USE SIGNAL ;
    PORT
      LAYER M5 ;
        RECT  110.064 0 110.088 0.084 ;
    END
  END pdata[389]
  PIN pdata[38]
    DIRECTION INPUT ;
    USE SIGNAL ;
    PORT
      LAYER M5 ;
        RECT  14.16 0 14.184 0.084 ;
    END
  END pdata[38]
  PIN pdata[390]
    DIRECTION INPUT ;
    USE SIGNAL ;
    PORT
      LAYER M5 ;
        RECT  110.16 0 110.184 0.084 ;
    END
  END pdata[390]
  PIN pdata[391]
    DIRECTION INPUT ;
    USE SIGNAL ;
    PORT
      LAYER M5 ;
        RECT  110.256 0 110.28 0.084 ;
    END
  END pdata[391]
  PIN pdata[392]
    DIRECTION INPUT ;
    USE SIGNAL ;
    PORT
      LAYER M5 ;
        RECT  110.352 0 110.376 0.084 ;
    END
  END pdata[392]
  PIN pdata[393]
    DIRECTION INPUT ;
    USE SIGNAL ;
    PORT
      LAYER M5 ;
        RECT  110.448 0 110.472 0.084 ;
    END
  END pdata[393]
  PIN pdata[394]
    DIRECTION INPUT ;
    USE SIGNAL ;
    PORT
      LAYER M5 ;
        RECT  110.544 0 110.568 0.084 ;
    END
  END pdata[394]
  PIN pdata[395]
    DIRECTION INPUT ;
    USE SIGNAL ;
    PORT
      LAYER M5 ;
        RECT  110.64 0 110.664 0.084 ;
    END
  END pdata[395]
  PIN pdata[396]
    DIRECTION INPUT ;
    USE SIGNAL ;
    PORT
      LAYER M5 ;
        RECT  110.736 0 110.76 0.084 ;
    END
  END pdata[396]
  PIN pdata[397]
    DIRECTION INPUT ;
    USE SIGNAL ;
    PORT
      LAYER M5 ;
        RECT  110.832 0 110.856 0.084 ;
    END
  END pdata[397]
  PIN pdata[398]
    DIRECTION INPUT ;
    USE SIGNAL ;
    PORT
      LAYER M5 ;
        RECT  110.928 0 110.952 0.084 ;
    END
  END pdata[398]
  PIN pdata[399]
    DIRECTION INPUT ;
    USE SIGNAL ;
    PORT
      LAYER M5 ;
        RECT  111.024 0 111.048 0.084 ;
    END
  END pdata[399]
  PIN pdata[39]
    DIRECTION INPUT ;
    USE SIGNAL ;
    PORT
      LAYER M5 ;
        RECT  14.256 0 14.28 0.084 ;
    END
  END pdata[39]
  PIN pdata[3]
    DIRECTION INPUT ;
    USE SIGNAL ;
    PORT
      LAYER M5 ;
        RECT  20.784 0 20.808 0.084 ;
    END
  END pdata[3]
  PIN pdata[400]
    DIRECTION INPUT ;
    USE SIGNAL ;
    PORT
      LAYER M5 ;
        RECT  111.12 0 111.144 0.084 ;
    END
  END pdata[400]
  PIN pdata[401]
    DIRECTION INPUT ;
    USE SIGNAL ;
    PORT
      LAYER M5 ;
        RECT  111.216 0 111.24 0.084 ;
    END
  END pdata[401]
  PIN pdata[402]
    DIRECTION INPUT ;
    USE SIGNAL ;
    PORT
      LAYER M5 ;
        RECT  111.312 0 111.336 0.084 ;
    END
  END pdata[402]
  PIN pdata[403]
    DIRECTION INPUT ;
    USE SIGNAL ;
    PORT
      LAYER M5 ;
        RECT  111.408 0 111.432 0.084 ;
    END
  END pdata[403]
  PIN pdata[404]
    DIRECTION INPUT ;
    USE SIGNAL ;
    PORT
      LAYER M5 ;
        RECT  111.504 0 111.528 0.084 ;
    END
  END pdata[404]
  PIN pdata[405]
    DIRECTION INPUT ;
    USE SIGNAL ;
    PORT
      LAYER M5 ;
        RECT  111.6 0 111.624 0.084 ;
    END
  END pdata[405]
  PIN pdata[406]
    DIRECTION INPUT ;
    USE SIGNAL ;
    PORT
      LAYER M5 ;
        RECT  111.696 0 111.72 0.084 ;
    END
  END pdata[406]
  PIN pdata[407]
    DIRECTION INPUT ;
    USE SIGNAL ;
    PORT
      LAYER M5 ;
        RECT  111.792 0 111.816 0.084 ;
    END
  END pdata[407]
  PIN pdata[408]
    DIRECTION INPUT ;
    USE SIGNAL ;
    PORT
      LAYER M5 ;
        RECT  111.888 0 111.912 0.084 ;
    END
  END pdata[408]
  PIN pdata[409]
    DIRECTION INPUT ;
    USE SIGNAL ;
    PORT
      LAYER M5 ;
        RECT  111.984 0 112.008 0.084 ;
    END
  END pdata[409]
  PIN pdata[40]
    DIRECTION INPUT ;
    USE SIGNAL ;
    PORT
      LAYER M5 ;
        RECT  14.352 0 14.376 0.084 ;
    END
  END pdata[40]
  PIN pdata[410]
    DIRECTION INPUT ;
    USE SIGNAL ;
    PORT
      LAYER M5 ;
        RECT  115.92 0 115.944 0.084 ;
    END
  END pdata[410]
  PIN pdata[411]
    DIRECTION INPUT ;
    USE SIGNAL ;
    PORT
      LAYER M5 ;
        RECT  116.016 0 116.04 0.084 ;
    END
  END pdata[411]
  PIN pdata[412]
    DIRECTION INPUT ;
    USE SIGNAL ;
    PORT
      LAYER M5 ;
        RECT  116.112 0 116.136 0.084 ;
    END
  END pdata[412]
  PIN pdata[413]
    DIRECTION INPUT ;
    USE SIGNAL ;
    PORT
      LAYER M5 ;
        RECT  116.208 0 116.232 0.084 ;
    END
  END pdata[413]
  PIN pdata[414]
    DIRECTION INPUT ;
    USE SIGNAL ;
    PORT
      LAYER M5 ;
        RECT  116.304 0 116.328 0.084 ;
    END
  END pdata[414]
  PIN pdata[415]
    DIRECTION INPUT ;
    USE SIGNAL ;
    PORT
      LAYER M5 ;
        RECT  116.4 0 116.424 0.084 ;
    END
  END pdata[415]
  PIN pdata[416]
    DIRECTION INPUT ;
    USE SIGNAL ;
    PORT
      LAYER M5 ;
        RECT  116.496 0 116.52 0.084 ;
    END
  END pdata[416]
  PIN pdata[417]
    DIRECTION INPUT ;
    USE SIGNAL ;
    PORT
      LAYER M5 ;
        RECT  116.592 0 116.616 0.084 ;
    END
  END pdata[417]
  PIN pdata[418]
    DIRECTION INPUT ;
    USE SIGNAL ;
    PORT
      LAYER M5 ;
        RECT  116.688 0 116.712 0.084 ;
    END
  END pdata[418]
  PIN pdata[419]
    DIRECTION INPUT ;
    USE SIGNAL ;
    PORT
      LAYER M5 ;
        RECT  116.784 0 116.808 0.084 ;
    END
  END pdata[419]
  PIN pdata[41]
    DIRECTION INPUT ;
    USE SIGNAL ;
    PORT
      LAYER M5 ;
        RECT  14.448 0 14.472 0.084 ;
    END
  END pdata[41]
  PIN pdata[420]
    DIRECTION INPUT ;
    USE SIGNAL ;
    PORT
      LAYER M5 ;
        RECT  116.88 0 116.904 0.084 ;
    END
  END pdata[420]
  PIN pdata[421]
    DIRECTION INPUT ;
    USE SIGNAL ;
    PORT
      LAYER M5 ;
        RECT  116.976 0 117 0.084 ;
    END
  END pdata[421]
  PIN pdata[422]
    DIRECTION INPUT ;
    USE SIGNAL ;
    PORT
      LAYER M5 ;
        RECT  117.072 0 117.096 0.084 ;
    END
  END pdata[422]
  PIN pdata[423]
    DIRECTION INPUT ;
    USE SIGNAL ;
    PORT
      LAYER M5 ;
        RECT  117.168 0 117.192 0.084 ;
    END
  END pdata[423]
  PIN pdata[424]
    DIRECTION INPUT ;
    USE SIGNAL ;
    PORT
      LAYER M5 ;
        RECT  117.264 0 117.288 0.084 ;
    END
  END pdata[424]
  PIN pdata[425]
    DIRECTION INPUT ;
    USE SIGNAL ;
    PORT
      LAYER M5 ;
        RECT  117.36 0 117.384 0.084 ;
    END
  END pdata[425]
  PIN pdata[426]
    DIRECTION INPUT ;
    USE SIGNAL ;
    PORT
      LAYER M5 ;
        RECT  117.456 0 117.48 0.084 ;
    END
  END pdata[426]
  PIN pdata[427]
    DIRECTION INPUT ;
    USE SIGNAL ;
    PORT
      LAYER M5 ;
        RECT  117.552 0 117.576 0.084 ;
    END
  END pdata[427]
  PIN pdata[428]
    DIRECTION INPUT ;
    USE SIGNAL ;
    PORT
      LAYER M5 ;
        RECT  117.648 0 117.672 0.084 ;
    END
  END pdata[428]
  PIN pdata[429]
    DIRECTION INPUT ;
    USE SIGNAL ;
    PORT
      LAYER M5 ;
        RECT  117.744 0 117.768 0.084 ;
    END
  END pdata[429]
  PIN pdata[42]
    DIRECTION INPUT ;
    USE SIGNAL ;
    PORT
      LAYER M5 ;
        RECT  14.544 0 14.568 0.084 ;
    END
  END pdata[42]
  PIN pdata[430]
    DIRECTION INPUT ;
    USE SIGNAL ;
    PORT
      LAYER M5 ;
        RECT  117.84 0 117.864 0.084 ;
    END
  END pdata[430]
  PIN pdata[431]
    DIRECTION INPUT ;
    USE SIGNAL ;
    PORT
      LAYER M5 ;
        RECT  117.936 0 117.96 0.084 ;
    END
  END pdata[431]
  PIN pdata[432]
    DIRECTION INPUT ;
    USE SIGNAL ;
    PORT
      LAYER M5 ;
        RECT  118.032 0 118.056 0.084 ;
    END
  END pdata[432]
  PIN pdata[433]
    DIRECTION INPUT ;
    USE SIGNAL ;
    PORT
      LAYER M5 ;
        RECT  118.128 0 118.152 0.084 ;
    END
  END pdata[433]
  PIN pdata[434]
    DIRECTION INPUT ;
    USE SIGNAL ;
    PORT
      LAYER M5 ;
        RECT  118.224 0 118.248 0.084 ;
    END
  END pdata[434]
  PIN pdata[435]
    DIRECTION INPUT ;
    USE SIGNAL ;
    PORT
      LAYER M5 ;
        RECT  118.32 0 118.344 0.084 ;
    END
  END pdata[435]
  PIN pdata[436]
    DIRECTION INPUT ;
    USE SIGNAL ;
    PORT
      LAYER M5 ;
        RECT  118.416 0 118.44 0.084 ;
    END
  END pdata[436]
  PIN pdata[437]
    DIRECTION INPUT ;
    USE SIGNAL ;
    PORT
      LAYER M5 ;
        RECT  118.512 0 118.536 0.084 ;
    END
  END pdata[437]
  PIN pdata[438]
    DIRECTION INPUT ;
    USE SIGNAL ;
    PORT
      LAYER M5 ;
        RECT  118.608 0 118.632 0.084 ;
    END
  END pdata[438]
  PIN pdata[439]
    DIRECTION INPUT ;
    USE SIGNAL ;
    PORT
      LAYER M5 ;
        RECT  118.704 0 118.728 0.084 ;
    END
  END pdata[439]
  PIN pdata[43]
    DIRECTION INPUT ;
    USE SIGNAL ;
    PORT
      LAYER M5 ;
        RECT  14.64 0 14.664 0.084 ;
    END
  END pdata[43]
  PIN pdata[440]
    DIRECTION INPUT ;
    USE SIGNAL ;
    PORT
      LAYER M5 ;
        RECT  118.8 0 118.824 0.084 ;
    END
  END pdata[440]
  PIN pdata[441]
    DIRECTION INPUT ;
    USE SIGNAL ;
    PORT
      LAYER M5 ;
        RECT  118.896 0 118.92 0.084 ;
    END
  END pdata[441]
  PIN pdata[442]
    DIRECTION INPUT ;
    USE SIGNAL ;
    PORT
      LAYER M5 ;
        RECT  122.064 0 122.088 0.084 ;
    END
  END pdata[442]
  PIN pdata[443]
    DIRECTION INPUT ;
    USE SIGNAL ;
    PORT
      LAYER M5 ;
        RECT  122.16 0 122.184 0.084 ;
    END
  END pdata[443]
  PIN pdata[444]
    DIRECTION INPUT ;
    USE SIGNAL ;
    PORT
      LAYER M5 ;
        RECT  122.256 0 122.28 0.084 ;
    END
  END pdata[444]
  PIN pdata[445]
    DIRECTION INPUT ;
    USE SIGNAL ;
    PORT
      LAYER M5 ;
        RECT  122.352 0 122.376 0.084 ;
    END
  END pdata[445]
  PIN pdata[446]
    DIRECTION INPUT ;
    USE SIGNAL ;
    PORT
      LAYER M5 ;
        RECT  122.448 0 122.472 0.084 ;
    END
  END pdata[446]
  PIN pdata[447]
    DIRECTION INPUT ;
    USE SIGNAL ;
    PORT
      LAYER M5 ;
        RECT  122.544 0 122.568 0.084 ;
    END
  END pdata[447]
  PIN pdata[448]
    DIRECTION INPUT ;
    USE SIGNAL ;
    PORT
      LAYER M5 ;
        RECT  122.64 0 122.664 0.084 ;
    END
  END pdata[448]
  PIN pdata[449]
    DIRECTION INPUT ;
    USE SIGNAL ;
    PORT
      LAYER M5 ;
        RECT  122.736 0 122.76 0.084 ;
    END
  END pdata[449]
  PIN pdata[44]
    DIRECTION INPUT ;
    USE SIGNAL ;
    PORT
      LAYER M5 ;
        RECT  14.736 0 14.76 0.084 ;
    END
  END pdata[44]
  PIN pdata[450]
    DIRECTION INPUT ;
    USE SIGNAL ;
    PORT
      LAYER M5 ;
        RECT  122.832 0 122.856 0.084 ;
    END
  END pdata[450]
  PIN pdata[451]
    DIRECTION INPUT ;
    USE SIGNAL ;
    PORT
      LAYER M5 ;
        RECT  122.928 0 122.952 0.084 ;
    END
  END pdata[451]
  PIN pdata[452]
    DIRECTION INPUT ;
    USE SIGNAL ;
    PORT
      LAYER M5 ;
        RECT  123.024 0 123.048 0.084 ;
    END
  END pdata[452]
  PIN pdata[453]
    DIRECTION INPUT ;
    USE SIGNAL ;
    PORT
      LAYER M5 ;
        RECT  123.12 0 123.144 0.084 ;
    END
  END pdata[453]
  PIN pdata[454]
    DIRECTION INPUT ;
    USE SIGNAL ;
    PORT
      LAYER M5 ;
        RECT  123.216 0 123.24 0.084 ;
    END
  END pdata[454]
  PIN pdata[455]
    DIRECTION INPUT ;
    USE SIGNAL ;
    PORT
      LAYER M5 ;
        RECT  123.312 0 123.336 0.084 ;
    END
  END pdata[455]
  PIN pdata[456]
    DIRECTION INPUT ;
    USE SIGNAL ;
    PORT
      LAYER M5 ;
        RECT  123.408 0 123.432 0.084 ;
    END
  END pdata[456]
  PIN pdata[457]
    DIRECTION INPUT ;
    USE SIGNAL ;
    PORT
      LAYER M5 ;
        RECT  123.504 0 123.528 0.084 ;
    END
  END pdata[457]
  PIN pdata[458]
    DIRECTION INPUT ;
    USE SIGNAL ;
    PORT
      LAYER M5 ;
        RECT  123.6 0 123.624 0.084 ;
    END
  END pdata[458]
  PIN pdata[459]
    DIRECTION INPUT ;
    USE SIGNAL ;
    PORT
      LAYER M5 ;
        RECT  123.696 0 123.72 0.084 ;
    END
  END pdata[459]
  PIN pdata[45]
    DIRECTION INPUT ;
    USE SIGNAL ;
    PORT
      LAYER M5 ;
        RECT  14.832 0 14.856 0.084 ;
    END
  END pdata[45]
  PIN pdata[460]
    DIRECTION INPUT ;
    USE SIGNAL ;
    PORT
      LAYER M5 ;
        RECT  123.792 0 123.816 0.084 ;
    END
  END pdata[460]
  PIN pdata[461]
    DIRECTION INPUT ;
    USE SIGNAL ;
    PORT
      LAYER M5 ;
        RECT  123.888 0 123.912 0.084 ;
    END
  END pdata[461]
  PIN pdata[462]
    DIRECTION INPUT ;
    USE SIGNAL ;
    PORT
      LAYER M5 ;
        RECT  123.984 0 124.008 0.084 ;
    END
  END pdata[462]
  PIN pdata[463]
    DIRECTION INPUT ;
    USE SIGNAL ;
    PORT
      LAYER M5 ;
        RECT  124.08 0 124.104 0.084 ;
    END
  END pdata[463]
  PIN pdata[464]
    DIRECTION INPUT ;
    USE SIGNAL ;
    PORT
      LAYER M5 ;
        RECT  124.176 0 124.2 0.084 ;
    END
  END pdata[464]
  PIN pdata[465]
    DIRECTION INPUT ;
    USE SIGNAL ;
    PORT
      LAYER M5 ;
        RECT  124.272 0 124.296 0.084 ;
    END
  END pdata[465]
  PIN pdata[466]
    DIRECTION INPUT ;
    USE SIGNAL ;
    PORT
      LAYER M5 ;
        RECT  124.368 0 124.392 0.084 ;
    END
  END pdata[466]
  PIN pdata[467]
    DIRECTION INPUT ;
    USE SIGNAL ;
    PORT
      LAYER M5 ;
        RECT  124.464 0 124.488 0.084 ;
    END
  END pdata[467]
  PIN pdata[468]
    DIRECTION INPUT ;
    USE SIGNAL ;
    PORT
      LAYER M5 ;
        RECT  124.56 0 124.584 0.084 ;
    END
  END pdata[468]
  PIN pdata[469]
    DIRECTION INPUT ;
    USE SIGNAL ;
    PORT
      LAYER M5 ;
        RECT  124.656 0 124.68 0.084 ;
    END
  END pdata[469]
  PIN pdata[46]
    DIRECTION INPUT ;
    USE SIGNAL ;
    PORT
      LAYER M5 ;
        RECT  14.928 0 14.952 0.084 ;
    END
  END pdata[46]
  PIN pdata[470]
    DIRECTION INPUT ;
    USE SIGNAL ;
    PORT
      LAYER M5 ;
        RECT  124.752 0 124.776 0.084 ;
    END
  END pdata[470]
  PIN pdata[471]
    DIRECTION INPUT ;
    USE SIGNAL ;
    PORT
      LAYER M5 ;
        RECT  124.848 0 124.872 0.084 ;
    END
  END pdata[471]
  PIN pdata[472]
    DIRECTION INPUT ;
    USE SIGNAL ;
    PORT
      LAYER M5 ;
        RECT  124.944 0 124.968 0.084 ;
    END
  END pdata[472]
  PIN pdata[473]
    DIRECTION INPUT ;
    USE SIGNAL ;
    PORT
      LAYER M5 ;
        RECT  125.04 0 125.064 0.084 ;
    END
  END pdata[473]
  PIN pdata[474]
    DIRECTION INPUT ;
    USE SIGNAL ;
    PORT
      LAYER M5 ;
        RECT  128.208 0 128.232 0.084 ;
    END
  END pdata[474]
  PIN pdata[475]
    DIRECTION INPUT ;
    USE SIGNAL ;
    PORT
      LAYER M5 ;
        RECT  128.304 0 128.328 0.084 ;
    END
  END pdata[475]
  PIN pdata[476]
    DIRECTION INPUT ;
    USE SIGNAL ;
    PORT
      LAYER M5 ;
        RECT  128.4 0 128.424 0.084 ;
    END
  END pdata[476]
  PIN pdata[477]
    DIRECTION INPUT ;
    USE SIGNAL ;
    PORT
      LAYER M5 ;
        RECT  128.496 0 128.52 0.084 ;
    END
  END pdata[477]
  PIN pdata[478]
    DIRECTION INPUT ;
    USE SIGNAL ;
    PORT
      LAYER M5 ;
        RECT  128.592 0 128.616 0.084 ;
    END
  END pdata[478]
  PIN pdata[479]
    DIRECTION INPUT ;
    USE SIGNAL ;
    PORT
      LAYER M5 ;
        RECT  128.688 0 128.712 0.084 ;
    END
  END pdata[479]
  PIN pdata[47]
    DIRECTION INPUT ;
    USE SIGNAL ;
    PORT
      LAYER M5 ;
        RECT  15.024 0 15.048 0.084 ;
    END
  END pdata[47]
  PIN pdata[480]
    DIRECTION INPUT ;
    USE SIGNAL ;
    PORT
      LAYER M5 ;
        RECT  128.784 0 128.808 0.084 ;
    END
  END pdata[480]
  PIN pdata[481]
    DIRECTION INPUT ;
    USE SIGNAL ;
    PORT
      LAYER M5 ;
        RECT  128.88 0 128.904 0.084 ;
    END
  END pdata[481]
  PIN pdata[482]
    DIRECTION INPUT ;
    USE SIGNAL ;
    PORT
      LAYER M5 ;
        RECT  128.976 0 129 0.084 ;
    END
  END pdata[482]
  PIN pdata[483]
    DIRECTION INPUT ;
    USE SIGNAL ;
    PORT
      LAYER M5 ;
        RECT  129.072 0 129.096 0.084 ;
    END
  END pdata[483]
  PIN pdata[484]
    DIRECTION INPUT ;
    USE SIGNAL ;
    PORT
      LAYER M5 ;
        RECT  129.168 0 129.192 0.084 ;
    END
  END pdata[484]
  PIN pdata[485]
    DIRECTION INPUT ;
    USE SIGNAL ;
    PORT
      LAYER M5 ;
        RECT  129.264 0 129.288 0.084 ;
    END
  END pdata[485]
  PIN pdata[486]
    DIRECTION INPUT ;
    USE SIGNAL ;
    PORT
      LAYER M5 ;
        RECT  129.36 0 129.384 0.084 ;
    END
  END pdata[486]
  PIN pdata[487]
    DIRECTION INPUT ;
    USE SIGNAL ;
    PORT
      LAYER M5 ;
        RECT  129.456 0 129.48 0.084 ;
    END
  END pdata[487]
  PIN pdata[488]
    DIRECTION INPUT ;
    USE SIGNAL ;
    PORT
      LAYER M5 ;
        RECT  129.552 0 129.576 0.084 ;
    END
  END pdata[488]
  PIN pdata[489]
    DIRECTION INPUT ;
    USE SIGNAL ;
    PORT
      LAYER M5 ;
        RECT  129.648 0 129.672 0.084 ;
    END
  END pdata[489]
  PIN pdata[48]
    DIRECTION INPUT ;
    USE SIGNAL ;
    PORT
      LAYER M5 ;
        RECT  15.12 0 15.144 0.084 ;
    END
  END pdata[48]
  PIN pdata[490]
    DIRECTION INPUT ;
    USE SIGNAL ;
    PORT
      LAYER M5 ;
        RECT  129.744 0 129.768 0.084 ;
    END
  END pdata[490]
  PIN pdata[491]
    DIRECTION INPUT ;
    USE SIGNAL ;
    PORT
      LAYER M5 ;
        RECT  129.84 0 129.864 0.084 ;
    END
  END pdata[491]
  PIN pdata[492]
    DIRECTION INPUT ;
    USE SIGNAL ;
    PORT
      LAYER M5 ;
        RECT  129.936 0 129.96 0.084 ;
    END
  END pdata[492]
  PIN pdata[493]
    DIRECTION INPUT ;
    USE SIGNAL ;
    PORT
      LAYER M5 ;
        RECT  130.032 0 130.056 0.084 ;
    END
  END pdata[493]
  PIN pdata[494]
    DIRECTION INPUT ;
    USE SIGNAL ;
    PORT
      LAYER M5 ;
        RECT  130.128 0 130.152 0.084 ;
    END
  END pdata[494]
  PIN pdata[495]
    DIRECTION INPUT ;
    USE SIGNAL ;
    PORT
      LAYER M5 ;
        RECT  130.224 0 130.248 0.084 ;
    END
  END pdata[495]
  PIN pdata[496]
    DIRECTION INPUT ;
    USE SIGNAL ;
    PORT
      LAYER M5 ;
        RECT  130.32 0 130.344 0.084 ;
    END
  END pdata[496]
  PIN pdata[497]
    DIRECTION INPUT ;
    USE SIGNAL ;
    PORT
      LAYER M5 ;
        RECT  130.416 0 130.44 0.084 ;
    END
  END pdata[497]
  PIN pdata[498]
    DIRECTION INPUT ;
    USE SIGNAL ;
    PORT
      LAYER M5 ;
        RECT  130.512 0 130.536 0.084 ;
    END
  END pdata[498]
  PIN pdata[499]
    DIRECTION INPUT ;
    USE SIGNAL ;
    PORT
      LAYER M5 ;
        RECT  130.608 0 130.632 0.084 ;
    END
  END pdata[499]
  PIN pdata[49]
    DIRECTION INPUT ;
    USE SIGNAL ;
    PORT
      LAYER M5 ;
        RECT  15.216 0 15.24 0.084 ;
    END
  END pdata[49]
  PIN pdata[4]
    DIRECTION INPUT ;
    USE SIGNAL ;
    PORT
      LAYER M5 ;
        RECT  20.88 0 20.904 0.084 ;
    END
  END pdata[4]
  PIN pdata[500]
    DIRECTION INPUT ;
    USE SIGNAL ;
    PORT
      LAYER M5 ;
        RECT  130.704 0 130.728 0.084 ;
    END
  END pdata[500]
  PIN pdata[501]
    DIRECTION INPUT ;
    USE SIGNAL ;
    PORT
      LAYER M5 ;
        RECT  130.8 0 130.824 0.084 ;
    END
  END pdata[501]
  PIN pdata[502]
    DIRECTION INPUT ;
    USE SIGNAL ;
    PORT
      LAYER M5 ;
        RECT  130.896 0 130.92 0.084 ;
    END
  END pdata[502]
  PIN pdata[503]
    DIRECTION INPUT ;
    USE SIGNAL ;
    PORT
      LAYER M5 ;
        RECT  130.992 0 131.016 0.084 ;
    END
  END pdata[503]
  PIN pdata[504]
    DIRECTION INPUT ;
    USE SIGNAL ;
    PORT
      LAYER M5 ;
        RECT  131.088 0 131.112 0.084 ;
    END
  END pdata[504]
  PIN pdata[505]
    DIRECTION INPUT ;
    USE SIGNAL ;
    PORT
      LAYER M5 ;
        RECT  131.184 0 131.208 0.084 ;
    END
  END pdata[505]
  PIN pdata[506]
    DIRECTION INPUT ;
    USE SIGNAL ;
    PORT
      LAYER M5 ;
        RECT  134.352 0 134.376 0.084 ;
    END
  END pdata[506]
  PIN pdata[507]
    DIRECTION INPUT ;
    USE SIGNAL ;
    PORT
      LAYER M5 ;
        RECT  134.448 0 134.472 0.084 ;
    END
  END pdata[507]
  PIN pdata[508]
    DIRECTION INPUT ;
    USE SIGNAL ;
    PORT
      LAYER M5 ;
        RECT  134.544 0 134.568 0.084 ;
    END
  END pdata[508]
  PIN pdata[509]
    DIRECTION INPUT ;
    USE SIGNAL ;
    PORT
      LAYER M5 ;
        RECT  134.64 0 134.664 0.084 ;
    END
  END pdata[509]
  PIN pdata[50]
    DIRECTION INPUT ;
    USE SIGNAL ;
    PORT
      LAYER M5 ;
        RECT  15.312 0 15.336 0.084 ;
    END
  END pdata[50]
  PIN pdata[510]
    DIRECTION INPUT ;
    USE SIGNAL ;
    PORT
      LAYER M5 ;
        RECT  134.736 0 134.76 0.084 ;
    END
  END pdata[510]
  PIN pdata[511]
    DIRECTION INPUT ;
    USE SIGNAL ;
    PORT
      LAYER M5 ;
        RECT  134.832 0 134.856 0.084 ;
    END
  END pdata[511]
  PIN pdata[51]
    DIRECTION INPUT ;
    USE SIGNAL ;
    PORT
      LAYER M5 ;
        RECT  15.408 0 15.432 0.084 ;
    END
  END pdata[51]
  PIN pdata[52]
    DIRECTION INPUT ;
    USE SIGNAL ;
    PORT
      LAYER M5 ;
        RECT  15.504 0 15.528 0.084 ;
    END
  END pdata[52]
  PIN pdata[53]
    DIRECTION INPUT ;
    USE SIGNAL ;
    PORT
      LAYER M5 ;
        RECT  15.6 0 15.624 0.084 ;
    END
  END pdata[53]
  PIN pdata[54]
    DIRECTION INPUT ;
    USE SIGNAL ;
    PORT
      LAYER M5 ;
        RECT  15.696 0 15.72 0.084 ;
    END
  END pdata[54]
  PIN pdata[55]
    DIRECTION INPUT ;
    USE SIGNAL ;
    PORT
      LAYER M5 ;
        RECT  15.792 0 15.816 0.084 ;
    END
  END pdata[55]
  PIN pdata[56]
    DIRECTION INPUT ;
    USE SIGNAL ;
    PORT
      LAYER M5 ;
        RECT  15.888 0 15.912 0.084 ;
    END
  END pdata[56]
  PIN pdata[57]
    DIRECTION INPUT ;
    USE SIGNAL ;
    PORT
      LAYER M5 ;
        RECT  15.984 0 16.008 0.084 ;
    END
  END pdata[57]
  PIN pdata[58]
    DIRECTION INPUT ;
    USE SIGNAL ;
    PORT
      LAYER M5 ;
        RECT  6.864 0 6.888 0.084 ;
    END
  END pdata[58]
  PIN pdata[59]
    DIRECTION INPUT ;
    USE SIGNAL ;
    PORT
      LAYER M5 ;
        RECT  6.96 0 6.984 0.084 ;
    END
  END pdata[59]
  PIN pdata[5]
    DIRECTION INPUT ;
    USE SIGNAL ;
    PORT
      LAYER M5 ;
        RECT  20.976 0 21 0.084 ;
    END
  END pdata[5]
  PIN pdata[60]
    DIRECTION INPUT ;
    USE SIGNAL ;
    PORT
      LAYER M5 ;
        RECT  7.056 0 7.08 0.084 ;
    END
  END pdata[60]
  PIN pdata[61]
    DIRECTION INPUT ;
    USE SIGNAL ;
    PORT
      LAYER M5 ;
        RECT  7.152 0 7.176 0.084 ;
    END
  END pdata[61]
  PIN pdata[62]
    DIRECTION INPUT ;
    USE SIGNAL ;
    PORT
      LAYER M5 ;
        RECT  7.248 0 7.272 0.084 ;
    END
  END pdata[62]
  PIN pdata[63]
    DIRECTION INPUT ;
    USE SIGNAL ;
    PORT
      LAYER M5 ;
        RECT  7.344 0 7.368 0.084 ;
    END
  END pdata[63]
  PIN pdata[64]
    DIRECTION INPUT ;
    USE SIGNAL ;
    PORT
      LAYER M5 ;
        RECT  7.44 0 7.464 0.084 ;
    END
  END pdata[64]
  PIN pdata[65]
    DIRECTION INPUT ;
    USE SIGNAL ;
    PORT
      LAYER M5 ;
        RECT  7.536 0 7.56 0.084 ;
    END
  END pdata[65]
  PIN pdata[66]
    DIRECTION INPUT ;
    USE SIGNAL ;
    PORT
      LAYER M5 ;
        RECT  7.632 0 7.656 0.084 ;
    END
  END pdata[66]
  PIN pdata[67]
    DIRECTION INPUT ;
    USE SIGNAL ;
    PORT
      LAYER M5 ;
        RECT  7.728 0 7.752 0.084 ;
    END
  END pdata[67]
  PIN pdata[68]
    DIRECTION INPUT ;
    USE SIGNAL ;
    PORT
      LAYER M5 ;
        RECT  7.824 0 7.848 0.084 ;
    END
  END pdata[68]
  PIN pdata[69]
    DIRECTION INPUT ;
    USE SIGNAL ;
    PORT
      LAYER M5 ;
        RECT  7.92 0 7.944 0.084 ;
    END
  END pdata[69]
  PIN pdata[6]
    DIRECTION INPUT ;
    USE SIGNAL ;
    PORT
      LAYER M5 ;
        RECT  21.072 0 21.096 0.084 ;
    END
  END pdata[6]
  PIN pdata[70]
    DIRECTION INPUT ;
    USE SIGNAL ;
    PORT
      LAYER M5 ;
        RECT  8.016 0 8.04 0.084 ;
    END
  END pdata[70]
  PIN pdata[71]
    DIRECTION INPUT ;
    USE SIGNAL ;
    PORT
      LAYER M5 ;
        RECT  8.112 0 8.136 0.084 ;
    END
  END pdata[71]
  PIN pdata[72]
    DIRECTION INPUT ;
    USE SIGNAL ;
    PORT
      LAYER M5 ;
        RECT  8.208 0 8.232 0.084 ;
    END
  END pdata[72]
  PIN pdata[73]
    DIRECTION INPUT ;
    USE SIGNAL ;
    PORT
      LAYER M5 ;
        RECT  8.304 0 8.328 0.084 ;
    END
  END pdata[73]
  PIN pdata[74]
    DIRECTION INPUT ;
    USE SIGNAL ;
    PORT
      LAYER M5 ;
        RECT  8.4 0 8.424 0.084 ;
    END
  END pdata[74]
  PIN pdata[75]
    DIRECTION INPUT ;
    USE SIGNAL ;
    PORT
      LAYER M5 ;
        RECT  8.496 0 8.52 0.084 ;
    END
  END pdata[75]
  PIN pdata[76]
    DIRECTION INPUT ;
    USE SIGNAL ;
    PORT
      LAYER M5 ;
        RECT  8.592 0 8.616 0.084 ;
    END
  END pdata[76]
  PIN pdata[77]
    DIRECTION INPUT ;
    USE SIGNAL ;
    PORT
      LAYER M5 ;
        RECT  8.688 0 8.712 0.084 ;
    END
  END pdata[77]
  PIN pdata[78]
    DIRECTION INPUT ;
    USE SIGNAL ;
    PORT
      LAYER M5 ;
        RECT  8.784 0 8.808 0.084 ;
    END
  END pdata[78]
  PIN pdata[79]
    DIRECTION INPUT ;
    USE SIGNAL ;
    PORT
      LAYER M5 ;
        RECT  8.88 0 8.904 0.084 ;
    END
  END pdata[79]
  PIN pdata[7]
    DIRECTION INPUT ;
    USE SIGNAL ;
    PORT
      LAYER M5 ;
        RECT  21.168 0 21.192 0.084 ;
    END
  END pdata[7]
  PIN pdata[80]
    DIRECTION INPUT ;
    USE SIGNAL ;
    PORT
      LAYER M5 ;
        RECT  8.976 0 9 0.084 ;
    END
  END pdata[80]
  PIN pdata[81]
    DIRECTION INPUT ;
    USE SIGNAL ;
    PORT
      LAYER M5 ;
        RECT  9.072 0 9.096 0.084 ;
    END
  END pdata[81]
  PIN pdata[82]
    DIRECTION INPUT ;
    USE SIGNAL ;
    PORT
      LAYER M5 ;
        RECT  9.168 0 9.192 0.084 ;
    END
  END pdata[82]
  PIN pdata[83]
    DIRECTION INPUT ;
    USE SIGNAL ;
    PORT
      LAYER M5 ;
        RECT  9.264 0 9.288 0.084 ;
    END
  END pdata[83]
  PIN pdata[84]
    DIRECTION INPUT ;
    USE SIGNAL ;
    PORT
      LAYER M5 ;
        RECT  9.36 0 9.384 0.084 ;
    END
  END pdata[84]
  PIN pdata[85]
    DIRECTION INPUT ;
    USE SIGNAL ;
    PORT
      LAYER M5 ;
        RECT  9.456 0 9.48 0.084 ;
    END
  END pdata[85]
  PIN pdata[86]
    DIRECTION INPUT ;
    USE SIGNAL ;
    PORT
      LAYER M5 ;
        RECT  9.552 0 9.576 0.084 ;
    END
  END pdata[86]
  PIN pdata[87]
    DIRECTION INPUT ;
    USE SIGNAL ;
    PORT
      LAYER M5 ;
        RECT  9.648 0 9.672 0.084 ;
    END
  END pdata[87]
  PIN pdata[88]
    DIRECTION INPUT ;
    USE SIGNAL ;
    PORT
      LAYER M5 ;
        RECT  9.744 0 9.768 0.084 ;
    END
  END pdata[88]
  PIN pdata[89]
    DIRECTION INPUT ;
    USE SIGNAL ;
    PORT
      LAYER M5 ;
        RECT  9.84 0 9.864 0.084 ;
    END
  END pdata[89]
  PIN pdata[8]
    DIRECTION INPUT ;
    USE SIGNAL ;
    PORT
      LAYER M5 ;
        RECT  21.264 0 21.288 0.084 ;
    END
  END pdata[8]
  PIN pdata[90]
    DIRECTION INPUT ;
    USE SIGNAL ;
    PORT
      LAYER M5 ;
        RECT  22.992 0 23.016 0.084 ;
    END
  END pdata[90]
  PIN pdata[91]
    DIRECTION INPUT ;
    USE SIGNAL ;
    PORT
      LAYER M5 ;
        RECT  23.088 0 23.112 0.084 ;
    END
  END pdata[91]
  PIN pdata[92]
    DIRECTION INPUT ;
    USE SIGNAL ;
    PORT
      LAYER M5 ;
        RECT  23.184 0 23.208 0.084 ;
    END
  END pdata[92]
  PIN pdata[93]
    DIRECTION INPUT ;
    USE SIGNAL ;
    PORT
      LAYER M5 ;
        RECT  23.28 0 23.304 0.084 ;
    END
  END pdata[93]
  PIN pdata[94]
    DIRECTION INPUT ;
    USE SIGNAL ;
    PORT
      LAYER M5 ;
        RECT  23.376 0 23.4 0.084 ;
    END
  END pdata[94]
  PIN pdata[95]
    DIRECTION INPUT ;
    USE SIGNAL ;
    PORT
      LAYER M5 ;
        RECT  23.472 0 23.496 0.084 ;
    END
  END pdata[95]
  PIN pdata[96]
    DIRECTION INPUT ;
    USE SIGNAL ;
    PORT
      LAYER M5 ;
        RECT  23.568 0 23.592 0.084 ;
    END
  END pdata[96]
  PIN pdata[97]
    DIRECTION INPUT ;
    USE SIGNAL ;
    PORT
      LAYER M5 ;
        RECT  23.664 0 23.688 0.084 ;
    END
  END pdata[97]
  PIN pdata[98]
    DIRECTION INPUT ;
    USE SIGNAL ;
    PORT
      LAYER M5 ;
        RECT  23.76 0 23.784 0.084 ;
    END
  END pdata[98]
  PIN pdata[99]
    DIRECTION INPUT ;
    USE SIGNAL ;
    PORT
      LAYER M5 ;
        RECT  23.856 0 23.88 0.084 ;
    END
  END pdata[99]
  PIN pdata[9]
    DIRECTION INPUT ;
    USE SIGNAL ;
    PORT
      LAYER M5 ;
        RECT  21.36 0 21.384 0.084 ;
    END
  END pdata[9]
  PIN pgi
    DIRECTION INPUT ;
    USE SIGNAL ;
    PORT
      LAYER M5 ;
        RECT  134.928 0 134.952 0.084 ;
    END
  END pgi
  PIN pv
    DIRECTION INPUT ;
    USE SIGNAL ;
    PORT
      LAYER M5 ;
        RECT  135.024 0 135.048 0.084 ;
    END
  END pv
  PIN ra[0]
    DIRECTION INPUT ;
    USE SIGNAL ;
    PORT
      LAYER M4 ;
        RECT  0 80.688 0.084 80.712 ;
    END
  END ra[0]
  PIN ra[1]
    DIRECTION INPUT ;
    USE SIGNAL ;
    PORT
      LAYER M4 ;
        RECT  0 80.784 0.084 80.808 ;
    END
  END ra[1]
  PIN ra[2]
    DIRECTION INPUT ;
    USE SIGNAL ;
    PORT
      LAYER M4 ;
        RECT  0 80.88 0.084 80.904 ;
    END
  END ra[2]
  PIN ra[3]
    DIRECTION INPUT ;
    USE SIGNAL ;
    PORT
      LAYER M4 ;
        RECT  0 80.976 0.084 81 ;
    END
  END ra[3]
  PIN ra[4]
    DIRECTION INPUT ;
    USE SIGNAL ;
    PORT
      LAYER M4 ;
        RECT  0 81.072 0.084 81.096 ;
    END
  END ra[4]
  PIN ra[5]
    DIRECTION INPUT ;
    USE SIGNAL ;
    PORT
      LAYER M4 ;
        RECT  0 81.168 0.084 81.192 ;
    END
  END ra[5]
  PIN rst_n
    DIRECTION INPUT ;
    USE SIGNAL ;
    PORT
      LAYER M4 ;
        RECT  0 81.264 0.084 81.288 ;
    END
  END rst_n
  PIN sr[0]
    DIRECTION OUTPUT ;
    USE SIGNAL ;
    PORT
      LAYER M5 ;
        RECT  32.208 151.116 32.232 151.2 ;
    END
  END sr[0]
  PIN sr[100]
    DIRECTION OUTPUT ;
    USE SIGNAL ;
    PORT
      LAYER M5 ;
        RECT  23.376 151.116 23.4 151.2 ;
    END
  END sr[100]
  PIN sr[101]
    DIRECTION OUTPUT ;
    USE SIGNAL ;
    PORT
      LAYER M5 ;
        RECT  23.472 151.116 23.496 151.2 ;
    END
  END sr[101]
  PIN sr[102]
    DIRECTION OUTPUT ;
    USE SIGNAL ;
    PORT
      LAYER M5 ;
        RECT  23.568 151.116 23.592 151.2 ;
    END
  END sr[102]
  PIN sr[103]
    DIRECTION OUTPUT ;
    USE SIGNAL ;
    PORT
      LAYER M5 ;
        RECT  23.664 151.116 23.688 151.2 ;
    END
  END sr[103]
  PIN sr[104]
    DIRECTION OUTPUT ;
    USE SIGNAL ;
    PORT
      LAYER M5 ;
        RECT  23.76 151.116 23.784 151.2 ;
    END
  END sr[104]
  PIN sr[105]
    DIRECTION OUTPUT ;
    USE SIGNAL ;
    PORT
      LAYER M5 ;
        RECT  23.856 151.116 23.88 151.2 ;
    END
  END sr[105]
  PIN sr[106]
    DIRECTION OUTPUT ;
    USE SIGNAL ;
    PORT
      LAYER M5 ;
        RECT  23.952 151.116 23.976 151.2 ;
    END
  END sr[106]
  PIN sr[107]
    DIRECTION OUTPUT ;
    USE SIGNAL ;
    PORT
      LAYER M5 ;
        RECT  24.048 151.116 24.072 151.2 ;
    END
  END sr[107]
  PIN sr[108]
    DIRECTION OUTPUT ;
    USE SIGNAL ;
    PORT
      LAYER M5 ;
        RECT  24.144 151.116 24.168 151.2 ;
    END
  END sr[108]
  PIN sr[109]
    DIRECTION OUTPUT ;
    USE SIGNAL ;
    PORT
      LAYER M5 ;
        RECT  24.24 151.116 24.264 151.2 ;
    END
  END sr[109]
  PIN sr[10]
    DIRECTION OUTPUT ;
    USE SIGNAL ;
    PORT
      LAYER M5 ;
        RECT  33.168 151.116 33.192 151.2 ;
    END
  END sr[10]
  PIN sr[110]
    DIRECTION OUTPUT ;
    USE SIGNAL ;
    PORT
      LAYER M5 ;
        RECT  24.336 151.116 24.36 151.2 ;
    END
  END sr[110]
  PIN sr[111]
    DIRECTION OUTPUT ;
    USE SIGNAL ;
    PORT
      LAYER M5 ;
        RECT  24.432 151.116 24.456 151.2 ;
    END
  END sr[111]
  PIN sr[112]
    DIRECTION OUTPUT ;
    USE SIGNAL ;
    PORT
      LAYER M5 ;
        RECT  24.528 151.116 24.552 151.2 ;
    END
  END sr[112]
  PIN sr[113]
    DIRECTION OUTPUT ;
    USE SIGNAL ;
    PORT
      LAYER M5 ;
        RECT  24.624 151.116 24.648 151.2 ;
    END
  END sr[113]
  PIN sr[114]
    DIRECTION OUTPUT ;
    USE SIGNAL ;
    PORT
      LAYER M5 ;
        RECT  24.72 151.116 24.744 151.2 ;
    END
  END sr[114]
  PIN sr[115]
    DIRECTION OUTPUT ;
    USE SIGNAL ;
    PORT
      LAYER M5 ;
        RECT  24.816 151.116 24.84 151.2 ;
    END
  END sr[115]
  PIN sr[116]
    DIRECTION OUTPUT ;
    USE SIGNAL ;
    PORT
      LAYER M5 ;
        RECT  24.912 151.116 24.936 151.2 ;
    END
  END sr[116]
  PIN sr[117]
    DIRECTION OUTPUT ;
    USE SIGNAL ;
    PORT
      LAYER M5 ;
        RECT  25.008 151.116 25.032 151.2 ;
    END
  END sr[117]
  PIN sr[118]
    DIRECTION OUTPUT ;
    USE SIGNAL ;
    PORT
      LAYER M5 ;
        RECT  25.104 151.116 25.128 151.2 ;
    END
  END sr[118]
  PIN sr[119]
    DIRECTION OUTPUT ;
    USE SIGNAL ;
    PORT
      LAYER M5 ;
        RECT  25.2 151.116 25.224 151.2 ;
    END
  END sr[119]
  PIN sr[11]
    DIRECTION OUTPUT ;
    USE SIGNAL ;
    PORT
      LAYER M5 ;
        RECT  33.264 151.116 33.288 151.2 ;
    END
  END sr[11]
  PIN sr[120]
    DIRECTION OUTPUT ;
    USE SIGNAL ;
    PORT
      LAYER M5 ;
        RECT  25.296 151.116 25.32 151.2 ;
    END
  END sr[120]
  PIN sr[121]
    DIRECTION OUTPUT ;
    USE SIGNAL ;
    PORT
      LAYER M5 ;
        RECT  25.392 151.116 25.416 151.2 ;
    END
  END sr[121]
  PIN sr[122]
    DIRECTION OUTPUT ;
    USE SIGNAL ;
    PORT
      LAYER M5 ;
        RECT  25.488 151.116 25.512 151.2 ;
    END
  END sr[122]
  PIN sr[123]
    DIRECTION OUTPUT ;
    USE SIGNAL ;
    PORT
      LAYER M5 ;
        RECT  25.584 151.116 25.608 151.2 ;
    END
  END sr[123]
  PIN sr[124]
    DIRECTION OUTPUT ;
    USE SIGNAL ;
    PORT
      LAYER M5 ;
        RECT  25.68 151.116 25.704 151.2 ;
    END
  END sr[124]
  PIN sr[125]
    DIRECTION OUTPUT ;
    USE SIGNAL ;
    PORT
      LAYER M5 ;
        RECT  25.776 151.116 25.8 151.2 ;
    END
  END sr[125]
  PIN sr[126]
    DIRECTION OUTPUT ;
    USE SIGNAL ;
    PORT
      LAYER M5 ;
        RECT  25.872 151.116 25.896 151.2 ;
    END
  END sr[126]
  PIN sr[127]
    DIRECTION OUTPUT ;
    USE SIGNAL ;
    PORT
      LAYER M5 ;
        RECT  25.968 151.116 25.992 151.2 ;
    END
  END sr[127]
  PIN sr[128]
    DIRECTION OUTPUT ;
    USE SIGNAL ;
    PORT
      LAYER M5 ;
        RECT  16.848 151.116 16.872 151.2 ;
    END
  END sr[128]
  PIN sr[129]
    DIRECTION OUTPUT ;
    USE SIGNAL ;
    PORT
      LAYER M5 ;
        RECT  16.944 151.116 16.968 151.2 ;
    END
  END sr[129]
  PIN sr[12]
    DIRECTION OUTPUT ;
    USE SIGNAL ;
    PORT
      LAYER M5 ;
        RECT  33.36 151.116 33.384 151.2 ;
    END
  END sr[12]
  PIN sr[130]
    DIRECTION OUTPUT ;
    USE SIGNAL ;
    PORT
      LAYER M5 ;
        RECT  17.04 151.116 17.064 151.2 ;
    END
  END sr[130]
  PIN sr[131]
    DIRECTION OUTPUT ;
    USE SIGNAL ;
    PORT
      LAYER M5 ;
        RECT  17.136 151.116 17.16 151.2 ;
    END
  END sr[131]
  PIN sr[132]
    DIRECTION OUTPUT ;
    USE SIGNAL ;
    PORT
      LAYER M5 ;
        RECT  17.232 151.116 17.256 151.2 ;
    END
  END sr[132]
  PIN sr[133]
    DIRECTION OUTPUT ;
    USE SIGNAL ;
    PORT
      LAYER M5 ;
        RECT  17.328 151.116 17.352 151.2 ;
    END
  END sr[133]
  PIN sr[134]
    DIRECTION OUTPUT ;
    USE SIGNAL ;
    PORT
      LAYER M5 ;
        RECT  17.424 151.116 17.448 151.2 ;
    END
  END sr[134]
  PIN sr[135]
    DIRECTION OUTPUT ;
    USE SIGNAL ;
    PORT
      LAYER M5 ;
        RECT  17.52 151.116 17.544 151.2 ;
    END
  END sr[135]
  PIN sr[136]
    DIRECTION OUTPUT ;
    USE SIGNAL ;
    PORT
      LAYER M5 ;
        RECT  17.616 151.116 17.64 151.2 ;
    END
  END sr[136]
  PIN sr[137]
    DIRECTION OUTPUT ;
    USE SIGNAL ;
    PORT
      LAYER M5 ;
        RECT  17.712 151.116 17.736 151.2 ;
    END
  END sr[137]
  PIN sr[138]
    DIRECTION OUTPUT ;
    USE SIGNAL ;
    PORT
      LAYER M5 ;
        RECT  17.808 151.116 17.832 151.2 ;
    END
  END sr[138]
  PIN sr[139]
    DIRECTION OUTPUT ;
    USE SIGNAL ;
    PORT
      LAYER M5 ;
        RECT  17.904 151.116 17.928 151.2 ;
    END
  END sr[139]
  PIN sr[13]
    DIRECTION OUTPUT ;
    USE SIGNAL ;
    PORT
      LAYER M5 ;
        RECT  33.456 151.116 33.48 151.2 ;
    END
  END sr[13]
  PIN sr[140]
    DIRECTION OUTPUT ;
    USE SIGNAL ;
    PORT
      LAYER M5 ;
        RECT  18 151.116 18.024 151.2 ;
    END
  END sr[140]
  PIN sr[141]
    DIRECTION OUTPUT ;
    USE SIGNAL ;
    PORT
      LAYER M5 ;
        RECT  18.096 151.116 18.12 151.2 ;
    END
  END sr[141]
  PIN sr[142]
    DIRECTION OUTPUT ;
    USE SIGNAL ;
    PORT
      LAYER M5 ;
        RECT  18.192 151.116 18.216 151.2 ;
    END
  END sr[142]
  PIN sr[143]
    DIRECTION OUTPUT ;
    USE SIGNAL ;
    PORT
      LAYER M5 ;
        RECT  18.288 151.116 18.312 151.2 ;
    END
  END sr[143]
  PIN sr[144]
    DIRECTION OUTPUT ;
    USE SIGNAL ;
    PORT
      LAYER M5 ;
        RECT  18.384 151.116 18.408 151.2 ;
    END
  END sr[144]
  PIN sr[145]
    DIRECTION OUTPUT ;
    USE SIGNAL ;
    PORT
      LAYER M5 ;
        RECT  18.48 151.116 18.504 151.2 ;
    END
  END sr[145]
  PIN sr[146]
    DIRECTION OUTPUT ;
    USE SIGNAL ;
    PORT
      LAYER M5 ;
        RECT  18.576 151.116 18.6 151.2 ;
    END
  END sr[146]
  PIN sr[147]
    DIRECTION OUTPUT ;
    USE SIGNAL ;
    PORT
      LAYER M5 ;
        RECT  18.672 151.116 18.696 151.2 ;
    END
  END sr[147]
  PIN sr[148]
    DIRECTION OUTPUT ;
    USE SIGNAL ;
    PORT
      LAYER M5 ;
        RECT  18.768 151.116 18.792 151.2 ;
    END
  END sr[148]
  PIN sr[149]
    DIRECTION OUTPUT ;
    USE SIGNAL ;
    PORT
      LAYER M5 ;
        RECT  18.864 151.116 18.888 151.2 ;
    END
  END sr[149]
  PIN sr[14]
    DIRECTION OUTPUT ;
    USE SIGNAL ;
    PORT
      LAYER M5 ;
        RECT  33.552 151.116 33.576 151.2 ;
    END
  END sr[14]
  PIN sr[150]
    DIRECTION OUTPUT ;
    USE SIGNAL ;
    PORT
      LAYER M5 ;
        RECT  18.96 151.116 18.984 151.2 ;
    END
  END sr[150]
  PIN sr[151]
    DIRECTION OUTPUT ;
    USE SIGNAL ;
    PORT
      LAYER M5 ;
        RECT  19.056 151.116 19.08 151.2 ;
    END
  END sr[151]
  PIN sr[152]
    DIRECTION OUTPUT ;
    USE SIGNAL ;
    PORT
      LAYER M5 ;
        RECT  19.152 151.116 19.176 151.2 ;
    END
  END sr[152]
  PIN sr[153]
    DIRECTION OUTPUT ;
    USE SIGNAL ;
    PORT
      LAYER M5 ;
        RECT  19.248 151.116 19.272 151.2 ;
    END
  END sr[153]
  PIN sr[154]
    DIRECTION OUTPUT ;
    USE SIGNAL ;
    PORT
      LAYER M5 ;
        RECT  19.344 151.116 19.368 151.2 ;
    END
  END sr[154]
  PIN sr[155]
    DIRECTION OUTPUT ;
    USE SIGNAL ;
    PORT
      LAYER M5 ;
        RECT  19.44 151.116 19.464 151.2 ;
    END
  END sr[155]
  PIN sr[156]
    DIRECTION OUTPUT ;
    USE SIGNAL ;
    PORT
      LAYER M5 ;
        RECT  19.536 151.116 19.56 151.2 ;
    END
  END sr[156]
  PIN sr[157]
    DIRECTION OUTPUT ;
    USE SIGNAL ;
    PORT
      LAYER M5 ;
        RECT  19.632 151.116 19.656 151.2 ;
    END
  END sr[157]
  PIN sr[158]
    DIRECTION OUTPUT ;
    USE SIGNAL ;
    PORT
      LAYER M5 ;
        RECT  19.728 151.116 19.752 151.2 ;
    END
  END sr[158]
  PIN sr[159]
    DIRECTION OUTPUT ;
    USE SIGNAL ;
    PORT
      LAYER M5 ;
        RECT  19.824 151.116 19.848 151.2 ;
    END
  END sr[159]
  PIN sr[15]
    DIRECTION OUTPUT ;
    USE SIGNAL ;
    PORT
      LAYER M5 ;
        RECT  33.648 151.116 33.672 151.2 ;
    END
  END sr[15]
  PIN sr[160]
    DIRECTION OUTPUT ;
    USE SIGNAL ;
    PORT
      LAYER M5 ;
        RECT  26.064 151.116 26.088 151.2 ;
    END
  END sr[160]
  PIN sr[161]
    DIRECTION OUTPUT ;
    USE SIGNAL ;
    PORT
      LAYER M5 ;
        RECT  26.16 151.116 26.184 151.2 ;
    END
  END sr[161]
  PIN sr[162]
    DIRECTION OUTPUT ;
    USE SIGNAL ;
    PORT
      LAYER M5 ;
        RECT  26.256 151.116 26.28 151.2 ;
    END
  END sr[162]
  PIN sr[163]
    DIRECTION OUTPUT ;
    USE SIGNAL ;
    PORT
      LAYER M5 ;
        RECT  26.352 151.116 26.376 151.2 ;
    END
  END sr[163]
  PIN sr[164]
    DIRECTION OUTPUT ;
    USE SIGNAL ;
    PORT
      LAYER M5 ;
        RECT  26.448 151.116 26.472 151.2 ;
    END
  END sr[164]
  PIN sr[165]
    DIRECTION OUTPUT ;
    USE SIGNAL ;
    PORT
      LAYER M5 ;
        RECT  26.544 151.116 26.568 151.2 ;
    END
  END sr[165]
  PIN sr[166]
    DIRECTION OUTPUT ;
    USE SIGNAL ;
    PORT
      LAYER M5 ;
        RECT  26.64 151.116 26.664 151.2 ;
    END
  END sr[166]
  PIN sr[167]
    DIRECTION OUTPUT ;
    USE SIGNAL ;
    PORT
      LAYER M5 ;
        RECT  26.736 151.116 26.76 151.2 ;
    END
  END sr[167]
  PIN sr[168]
    DIRECTION OUTPUT ;
    USE SIGNAL ;
    PORT
      LAYER M5 ;
        RECT  26.832 151.116 26.856 151.2 ;
    END
  END sr[168]
  PIN sr[169]
    DIRECTION OUTPUT ;
    USE SIGNAL ;
    PORT
      LAYER M5 ;
        RECT  26.928 151.116 26.952 151.2 ;
    END
  END sr[169]
  PIN sr[16]
    DIRECTION OUTPUT ;
    USE SIGNAL ;
    PORT
      LAYER M5 ;
        RECT  33.744 151.116 33.768 151.2 ;
    END
  END sr[16]
  PIN sr[170]
    DIRECTION OUTPUT ;
    USE SIGNAL ;
    PORT
      LAYER M5 ;
        RECT  27.024 151.116 27.048 151.2 ;
    END
  END sr[170]
  PIN sr[171]
    DIRECTION OUTPUT ;
    USE SIGNAL ;
    PORT
      LAYER M5 ;
        RECT  27.12 151.116 27.144 151.2 ;
    END
  END sr[171]
  PIN sr[172]
    DIRECTION OUTPUT ;
    USE SIGNAL ;
    PORT
      LAYER M5 ;
        RECT  27.216 151.116 27.24 151.2 ;
    END
  END sr[172]
  PIN sr[173]
    DIRECTION OUTPUT ;
    USE SIGNAL ;
    PORT
      LAYER M5 ;
        RECT  27.312 151.116 27.336 151.2 ;
    END
  END sr[173]
  PIN sr[174]
    DIRECTION OUTPUT ;
    USE SIGNAL ;
    PORT
      LAYER M5 ;
        RECT  27.408 151.116 27.432 151.2 ;
    END
  END sr[174]
  PIN sr[175]
    DIRECTION OUTPUT ;
    USE SIGNAL ;
    PORT
      LAYER M5 ;
        RECT  27.504 151.116 27.528 151.2 ;
    END
  END sr[175]
  PIN sr[176]
    DIRECTION OUTPUT ;
    USE SIGNAL ;
    PORT
      LAYER M5 ;
        RECT  27.6 151.116 27.624 151.2 ;
    END
  END sr[176]
  PIN sr[177]
    DIRECTION OUTPUT ;
    USE SIGNAL ;
    PORT
      LAYER M5 ;
        RECT  27.696 151.116 27.72 151.2 ;
    END
  END sr[177]
  PIN sr[178]
    DIRECTION OUTPUT ;
    USE SIGNAL ;
    PORT
      LAYER M5 ;
        RECT  27.792 151.116 27.816 151.2 ;
    END
  END sr[178]
  PIN sr[179]
    DIRECTION OUTPUT ;
    USE SIGNAL ;
    PORT
      LAYER M5 ;
        RECT  27.888 151.116 27.912 151.2 ;
    END
  END sr[179]
  PIN sr[17]
    DIRECTION OUTPUT ;
    USE SIGNAL ;
    PORT
      LAYER M5 ;
        RECT  33.84 151.116 33.864 151.2 ;
    END
  END sr[17]
  PIN sr[180]
    DIRECTION OUTPUT ;
    USE SIGNAL ;
    PORT
      LAYER M5 ;
        RECT  27.984 151.116 28.008 151.2 ;
    END
  END sr[180]
  PIN sr[181]
    DIRECTION OUTPUT ;
    USE SIGNAL ;
    PORT
      LAYER M5 ;
        RECT  28.08 151.116 28.104 151.2 ;
    END
  END sr[181]
  PIN sr[182]
    DIRECTION OUTPUT ;
    USE SIGNAL ;
    PORT
      LAYER M5 ;
        RECT  28.176 151.116 28.2 151.2 ;
    END
  END sr[182]
  PIN sr[183]
    DIRECTION OUTPUT ;
    USE SIGNAL ;
    PORT
      LAYER M5 ;
        RECT  28.272 151.116 28.296 151.2 ;
    END
  END sr[183]
  PIN sr[184]
    DIRECTION OUTPUT ;
    USE SIGNAL ;
    PORT
      LAYER M5 ;
        RECT  28.368 151.116 28.392 151.2 ;
    END
  END sr[184]
  PIN sr[185]
    DIRECTION OUTPUT ;
    USE SIGNAL ;
    PORT
      LAYER M5 ;
        RECT  28.464 151.116 28.488 151.2 ;
    END
  END sr[185]
  PIN sr[186]
    DIRECTION OUTPUT ;
    USE SIGNAL ;
    PORT
      LAYER M5 ;
        RECT  28.56 151.116 28.584 151.2 ;
    END
  END sr[186]
  PIN sr[187]
    DIRECTION OUTPUT ;
    USE SIGNAL ;
    PORT
      LAYER M5 ;
        RECT  28.656 151.116 28.68 151.2 ;
    END
  END sr[187]
  PIN sr[188]
    DIRECTION OUTPUT ;
    USE SIGNAL ;
    PORT
      LAYER M5 ;
        RECT  28.752 151.116 28.776 151.2 ;
    END
  END sr[188]
  PIN sr[189]
    DIRECTION OUTPUT ;
    USE SIGNAL ;
    PORT
      LAYER M5 ;
        RECT  28.848 151.116 28.872 151.2 ;
    END
  END sr[189]
  PIN sr[18]
    DIRECTION OUTPUT ;
    USE SIGNAL ;
    PORT
      LAYER M5 ;
        RECT  33.936 151.116 33.96 151.2 ;
    END
  END sr[18]
  PIN sr[190]
    DIRECTION OUTPUT ;
    USE SIGNAL ;
    PORT
      LAYER M5 ;
        RECT  28.944 151.116 28.968 151.2 ;
    END
  END sr[190]
  PIN sr[191]
    DIRECTION OUTPUT ;
    USE SIGNAL ;
    PORT
      LAYER M5 ;
        RECT  29.04 151.116 29.064 151.2 ;
    END
  END sr[191]
  PIN sr[192]
    DIRECTION OUTPUT ;
    USE SIGNAL ;
    PORT
      LAYER M5 ;
        RECT  13.008 151.116 13.032 151.2 ;
    END
  END sr[192]
  PIN sr[193]
    DIRECTION OUTPUT ;
    USE SIGNAL ;
    PORT
      LAYER M5 ;
        RECT  13.104 151.116 13.128 151.2 ;
    END
  END sr[193]
  PIN sr[194]
    DIRECTION OUTPUT ;
    USE SIGNAL ;
    PORT
      LAYER M5 ;
        RECT  13.2 151.116 13.224 151.2 ;
    END
  END sr[194]
  PIN sr[195]
    DIRECTION OUTPUT ;
    USE SIGNAL ;
    PORT
      LAYER M5 ;
        RECT  13.296 151.116 13.32 151.2 ;
    END
  END sr[195]
  PIN sr[196]
    DIRECTION OUTPUT ;
    USE SIGNAL ;
    PORT
      LAYER M5 ;
        RECT  13.392 151.116 13.416 151.2 ;
    END
  END sr[196]
  PIN sr[197]
    DIRECTION OUTPUT ;
    USE SIGNAL ;
    PORT
      LAYER M5 ;
        RECT  13.488 151.116 13.512 151.2 ;
    END
  END sr[197]
  PIN sr[198]
    DIRECTION OUTPUT ;
    USE SIGNAL ;
    PORT
      LAYER M5 ;
        RECT  13.584 151.116 13.608 151.2 ;
    END
  END sr[198]
  PIN sr[199]
    DIRECTION OUTPUT ;
    USE SIGNAL ;
    PORT
      LAYER M5 ;
        RECT  13.68 151.116 13.704 151.2 ;
    END
  END sr[199]
  PIN sr[19]
    DIRECTION OUTPUT ;
    USE SIGNAL ;
    PORT
      LAYER M5 ;
        RECT  34.032 151.116 34.056 151.2 ;
    END
  END sr[19]
  PIN sr[1]
    DIRECTION OUTPUT ;
    USE SIGNAL ;
    PORT
      LAYER M5 ;
        RECT  32.304 151.116 32.328 151.2 ;
    END
  END sr[1]
  PIN sr[200]
    DIRECTION OUTPUT ;
    USE SIGNAL ;
    PORT
      LAYER M5 ;
        RECT  13.776 151.116 13.8 151.2 ;
    END
  END sr[200]
  PIN sr[201]
    DIRECTION OUTPUT ;
    USE SIGNAL ;
    PORT
      LAYER M5 ;
        RECT  13.872 151.116 13.896 151.2 ;
    END
  END sr[201]
  PIN sr[202]
    DIRECTION OUTPUT ;
    USE SIGNAL ;
    PORT
      LAYER M5 ;
        RECT  13.968 151.116 13.992 151.2 ;
    END
  END sr[202]
  PIN sr[203]
    DIRECTION OUTPUT ;
    USE SIGNAL ;
    PORT
      LAYER M5 ;
        RECT  14.064 151.116 14.088 151.2 ;
    END
  END sr[203]
  PIN sr[204]
    DIRECTION OUTPUT ;
    USE SIGNAL ;
    PORT
      LAYER M5 ;
        RECT  14.16 151.116 14.184 151.2 ;
    END
  END sr[204]
  PIN sr[205]
    DIRECTION OUTPUT ;
    USE SIGNAL ;
    PORT
      LAYER M5 ;
        RECT  14.256 151.116 14.28 151.2 ;
    END
  END sr[205]
  PIN sr[206]
    DIRECTION OUTPUT ;
    USE SIGNAL ;
    PORT
      LAYER M5 ;
        RECT  14.352 151.116 14.376 151.2 ;
    END
  END sr[206]
  PIN sr[207]
    DIRECTION OUTPUT ;
    USE SIGNAL ;
    PORT
      LAYER M5 ;
        RECT  14.448 151.116 14.472 151.2 ;
    END
  END sr[207]
  PIN sr[208]
    DIRECTION OUTPUT ;
    USE SIGNAL ;
    PORT
      LAYER M5 ;
        RECT  14.544 151.116 14.568 151.2 ;
    END
  END sr[208]
  PIN sr[209]
    DIRECTION OUTPUT ;
    USE SIGNAL ;
    PORT
      LAYER M5 ;
        RECT  14.64 151.116 14.664 151.2 ;
    END
  END sr[209]
  PIN sr[20]
    DIRECTION OUTPUT ;
    USE SIGNAL ;
    PORT
      LAYER M5 ;
        RECT  34.128 151.116 34.152 151.2 ;
    END
  END sr[20]
  PIN sr[210]
    DIRECTION OUTPUT ;
    USE SIGNAL ;
    PORT
      LAYER M5 ;
        RECT  14.736 151.116 14.76 151.2 ;
    END
  END sr[210]
  PIN sr[211]
    DIRECTION OUTPUT ;
    USE SIGNAL ;
    PORT
      LAYER M5 ;
        RECT  14.832 151.116 14.856 151.2 ;
    END
  END sr[211]
  PIN sr[212]
    DIRECTION OUTPUT ;
    USE SIGNAL ;
    PORT
      LAYER M5 ;
        RECT  14.928 151.116 14.952 151.2 ;
    END
  END sr[212]
  PIN sr[213]
    DIRECTION OUTPUT ;
    USE SIGNAL ;
    PORT
      LAYER M5 ;
        RECT  15.024 151.116 15.048 151.2 ;
    END
  END sr[213]
  PIN sr[214]
    DIRECTION OUTPUT ;
    USE SIGNAL ;
    PORT
      LAYER M5 ;
        RECT  15.12 151.116 15.144 151.2 ;
    END
  END sr[214]
  PIN sr[215]
    DIRECTION OUTPUT ;
    USE SIGNAL ;
    PORT
      LAYER M5 ;
        RECT  15.216 151.116 15.24 151.2 ;
    END
  END sr[215]
  PIN sr[216]
    DIRECTION OUTPUT ;
    USE SIGNAL ;
    PORT
      LAYER M5 ;
        RECT  15.312 151.116 15.336 151.2 ;
    END
  END sr[216]
  PIN sr[217]
    DIRECTION OUTPUT ;
    USE SIGNAL ;
    PORT
      LAYER M5 ;
        RECT  15.408 151.116 15.432 151.2 ;
    END
  END sr[217]
  PIN sr[218]
    DIRECTION OUTPUT ;
    USE SIGNAL ;
    PORT
      LAYER M5 ;
        RECT  15.504 151.116 15.528 151.2 ;
    END
  END sr[218]
  PIN sr[219]
    DIRECTION OUTPUT ;
    USE SIGNAL ;
    PORT
      LAYER M5 ;
        RECT  15.6 151.116 15.624 151.2 ;
    END
  END sr[219]
  PIN sr[21]
    DIRECTION OUTPUT ;
    USE SIGNAL ;
    PORT
      LAYER M5 ;
        RECT  34.224 151.116 34.248 151.2 ;
    END
  END sr[21]
  PIN sr[220]
    DIRECTION OUTPUT ;
    USE SIGNAL ;
    PORT
      LAYER M5 ;
        RECT  15.696 151.116 15.72 151.2 ;
    END
  END sr[220]
  PIN sr[221]
    DIRECTION OUTPUT ;
    USE SIGNAL ;
    PORT
      LAYER M5 ;
        RECT  15.792 151.116 15.816 151.2 ;
    END
  END sr[221]
  PIN sr[222]
    DIRECTION OUTPUT ;
    USE SIGNAL ;
    PORT
      LAYER M5 ;
        RECT  15.888 151.116 15.912 151.2 ;
    END
  END sr[222]
  PIN sr[223]
    DIRECTION OUTPUT ;
    USE SIGNAL ;
    PORT
      LAYER M5 ;
        RECT  15.984 151.116 16.008 151.2 ;
    END
  END sr[223]
  PIN sr[224]
    DIRECTION OUTPUT ;
    USE SIGNAL ;
    PORT
      LAYER M5 ;
        RECT  9.936 151.116 9.96 151.2 ;
    END
  END sr[224]
  PIN sr[225]
    DIRECTION OUTPUT ;
    USE SIGNAL ;
    PORT
      LAYER M5 ;
        RECT  10.032 151.116 10.056 151.2 ;
    END
  END sr[225]
  PIN sr[226]
    DIRECTION OUTPUT ;
    USE SIGNAL ;
    PORT
      LAYER M5 ;
        RECT  10.128 151.116 10.152 151.2 ;
    END
  END sr[226]
  PIN sr[227]
    DIRECTION OUTPUT ;
    USE SIGNAL ;
    PORT
      LAYER M5 ;
        RECT  10.224 151.116 10.248 151.2 ;
    END
  END sr[227]
  PIN sr[228]
    DIRECTION OUTPUT ;
    USE SIGNAL ;
    PORT
      LAYER M5 ;
        RECT  10.32 151.116 10.344 151.2 ;
    END
  END sr[228]
  PIN sr[229]
    DIRECTION OUTPUT ;
    USE SIGNAL ;
    PORT
      LAYER M5 ;
        RECT  10.416 151.116 10.44 151.2 ;
    END
  END sr[229]
  PIN sr[22]
    DIRECTION OUTPUT ;
    USE SIGNAL ;
    PORT
      LAYER M5 ;
        RECT  34.32 151.116 34.344 151.2 ;
    END
  END sr[22]
  PIN sr[230]
    DIRECTION OUTPUT ;
    USE SIGNAL ;
    PORT
      LAYER M5 ;
        RECT  10.512 151.116 10.536 151.2 ;
    END
  END sr[230]
  PIN sr[231]
    DIRECTION OUTPUT ;
    USE SIGNAL ;
    PORT
      LAYER M5 ;
        RECT  10.608 151.116 10.632 151.2 ;
    END
  END sr[231]
  PIN sr[232]
    DIRECTION OUTPUT ;
    USE SIGNAL ;
    PORT
      LAYER M5 ;
        RECT  10.704 151.116 10.728 151.2 ;
    END
  END sr[232]
  PIN sr[233]
    DIRECTION OUTPUT ;
    USE SIGNAL ;
    PORT
      LAYER M5 ;
        RECT  10.8 151.116 10.824 151.2 ;
    END
  END sr[233]
  PIN sr[234]
    DIRECTION OUTPUT ;
    USE SIGNAL ;
    PORT
      LAYER M5 ;
        RECT  10.896 151.116 10.92 151.2 ;
    END
  END sr[234]
  PIN sr[235]
    DIRECTION OUTPUT ;
    USE SIGNAL ;
    PORT
      LAYER M5 ;
        RECT  10.992 151.116 11.016 151.2 ;
    END
  END sr[235]
  PIN sr[236]
    DIRECTION OUTPUT ;
    USE SIGNAL ;
    PORT
      LAYER M5 ;
        RECT  11.088 151.116 11.112 151.2 ;
    END
  END sr[236]
  PIN sr[237]
    DIRECTION OUTPUT ;
    USE SIGNAL ;
    PORT
      LAYER M5 ;
        RECT  11.184 151.116 11.208 151.2 ;
    END
  END sr[237]
  PIN sr[238]
    DIRECTION OUTPUT ;
    USE SIGNAL ;
    PORT
      LAYER M5 ;
        RECT  11.28 151.116 11.304 151.2 ;
    END
  END sr[238]
  PIN sr[239]
    DIRECTION OUTPUT ;
    USE SIGNAL ;
    PORT
      LAYER M5 ;
        RECT  11.376 151.116 11.4 151.2 ;
    END
  END sr[239]
  PIN sr[23]
    DIRECTION OUTPUT ;
    USE SIGNAL ;
    PORT
      LAYER M5 ;
        RECT  34.416 151.116 34.44 151.2 ;
    END
  END sr[23]
  PIN sr[240]
    DIRECTION OUTPUT ;
    USE SIGNAL ;
    PORT
      LAYER M5 ;
        RECT  11.472 151.116 11.496 151.2 ;
    END
  END sr[240]
  PIN sr[241]
    DIRECTION OUTPUT ;
    USE SIGNAL ;
    PORT
      LAYER M5 ;
        RECT  11.568 151.116 11.592 151.2 ;
    END
  END sr[241]
  PIN sr[242]
    DIRECTION OUTPUT ;
    USE SIGNAL ;
    PORT
      LAYER M5 ;
        RECT  11.664 151.116 11.688 151.2 ;
    END
  END sr[242]
  PIN sr[243]
    DIRECTION OUTPUT ;
    USE SIGNAL ;
    PORT
      LAYER M5 ;
        RECT  11.76 151.116 11.784 151.2 ;
    END
  END sr[243]
  PIN sr[244]
    DIRECTION OUTPUT ;
    USE SIGNAL ;
    PORT
      LAYER M5 ;
        RECT  11.856 151.116 11.88 151.2 ;
    END
  END sr[244]
  PIN sr[245]
    DIRECTION OUTPUT ;
    USE SIGNAL ;
    PORT
      LAYER M5 ;
        RECT  11.952 151.116 11.976 151.2 ;
    END
  END sr[245]
  PIN sr[246]
    DIRECTION OUTPUT ;
    USE SIGNAL ;
    PORT
      LAYER M5 ;
        RECT  12.048 151.116 12.072 151.2 ;
    END
  END sr[246]
  PIN sr[247]
    DIRECTION OUTPUT ;
    USE SIGNAL ;
    PORT
      LAYER M5 ;
        RECT  12.144 151.116 12.168 151.2 ;
    END
  END sr[247]
  PIN sr[248]
    DIRECTION OUTPUT ;
    USE SIGNAL ;
    PORT
      LAYER M5 ;
        RECT  12.24 151.116 12.264 151.2 ;
    END
  END sr[248]
  PIN sr[249]
    DIRECTION OUTPUT ;
    USE SIGNAL ;
    PORT
      LAYER M5 ;
        RECT  12.336 151.116 12.36 151.2 ;
    END
  END sr[249]
  PIN sr[24]
    DIRECTION OUTPUT ;
    USE SIGNAL ;
    PORT
      LAYER M5 ;
        RECT  34.512 151.116 34.536 151.2 ;
    END
  END sr[24]
  PIN sr[250]
    DIRECTION OUTPUT ;
    USE SIGNAL ;
    PORT
      LAYER M5 ;
        RECT  12.432 151.116 12.456 151.2 ;
    END
  END sr[250]
  PIN sr[251]
    DIRECTION OUTPUT ;
    USE SIGNAL ;
    PORT
      LAYER M5 ;
        RECT  12.528 151.116 12.552 151.2 ;
    END
  END sr[251]
  PIN sr[252]
    DIRECTION OUTPUT ;
    USE SIGNAL ;
    PORT
      LAYER M5 ;
        RECT  12.624 151.116 12.648 151.2 ;
    END
  END sr[252]
  PIN sr[253]
    DIRECTION OUTPUT ;
    USE SIGNAL ;
    PORT
      LAYER M5 ;
        RECT  12.72 151.116 12.744 151.2 ;
    END
  END sr[253]
  PIN sr[254]
    DIRECTION OUTPUT ;
    USE SIGNAL ;
    PORT
      LAYER M5 ;
        RECT  12.816 151.116 12.84 151.2 ;
    END
  END sr[254]
  PIN sr[255]
    DIRECTION OUTPUT ;
    USE SIGNAL ;
    PORT
      LAYER M5 ;
        RECT  12.912 151.116 12.936 151.2 ;
    END
  END sr[255]
  PIN sr[256]
    DIRECTION OUTPUT ;
    USE SIGNAL ;
    PORT
      LAYER M5 ;
        RECT  6.864 151.116 6.888 151.2 ;
    END
  END sr[256]
  PIN sr[257]
    DIRECTION OUTPUT ;
    USE SIGNAL ;
    PORT
      LAYER M5 ;
        RECT  6.96 151.116 6.984 151.2 ;
    END
  END sr[257]
  PIN sr[258]
    DIRECTION OUTPUT ;
    USE SIGNAL ;
    PORT
      LAYER M5 ;
        RECT  7.056 151.116 7.08 151.2 ;
    END
  END sr[258]
  PIN sr[259]
    DIRECTION OUTPUT ;
    USE SIGNAL ;
    PORT
      LAYER M5 ;
        RECT  7.152 151.116 7.176 151.2 ;
    END
  END sr[259]
  PIN sr[25]
    DIRECTION OUTPUT ;
    USE SIGNAL ;
    PORT
      LAYER M5 ;
        RECT  34.608 151.116 34.632 151.2 ;
    END
  END sr[25]
  PIN sr[260]
    DIRECTION OUTPUT ;
    USE SIGNAL ;
    PORT
      LAYER M5 ;
        RECT  7.248 151.116 7.272 151.2 ;
    END
  END sr[260]
  PIN sr[261]
    DIRECTION OUTPUT ;
    USE SIGNAL ;
    PORT
      LAYER M5 ;
        RECT  7.344 151.116 7.368 151.2 ;
    END
  END sr[261]
  PIN sr[262]
    DIRECTION OUTPUT ;
    USE SIGNAL ;
    PORT
      LAYER M5 ;
        RECT  7.44 151.116 7.464 151.2 ;
    END
  END sr[262]
  PIN sr[263]
    DIRECTION OUTPUT ;
    USE SIGNAL ;
    PORT
      LAYER M5 ;
        RECT  7.536 151.116 7.56 151.2 ;
    END
  END sr[263]
  PIN sr[264]
    DIRECTION OUTPUT ;
    USE SIGNAL ;
    PORT
      LAYER M5 ;
        RECT  7.632 151.116 7.656 151.2 ;
    END
  END sr[264]
  PIN sr[265]
    DIRECTION OUTPUT ;
    USE SIGNAL ;
    PORT
      LAYER M5 ;
        RECT  7.728 151.116 7.752 151.2 ;
    END
  END sr[265]
  PIN sr[266]
    DIRECTION OUTPUT ;
    USE SIGNAL ;
    PORT
      LAYER M5 ;
        RECT  7.824 151.116 7.848 151.2 ;
    END
  END sr[266]
  PIN sr[267]
    DIRECTION OUTPUT ;
    USE SIGNAL ;
    PORT
      LAYER M5 ;
        RECT  7.92 151.116 7.944 151.2 ;
    END
  END sr[267]
  PIN sr[268]
    DIRECTION OUTPUT ;
    USE SIGNAL ;
    PORT
      LAYER M5 ;
        RECT  8.016 151.116 8.04 151.2 ;
    END
  END sr[268]
  PIN sr[269]
    DIRECTION OUTPUT ;
    USE SIGNAL ;
    PORT
      LAYER M5 ;
        RECT  8.112 151.116 8.136 151.2 ;
    END
  END sr[269]
  PIN sr[26]
    DIRECTION OUTPUT ;
    USE SIGNAL ;
    PORT
      LAYER M5 ;
        RECT  34.704 151.116 34.728 151.2 ;
    END
  END sr[26]
  PIN sr[270]
    DIRECTION OUTPUT ;
    USE SIGNAL ;
    PORT
      LAYER M5 ;
        RECT  8.208 151.116 8.232 151.2 ;
    END
  END sr[270]
  PIN sr[271]
    DIRECTION OUTPUT ;
    USE SIGNAL ;
    PORT
      LAYER M5 ;
        RECT  8.304 151.116 8.328 151.2 ;
    END
  END sr[271]
  PIN sr[272]
    DIRECTION OUTPUT ;
    USE SIGNAL ;
    PORT
      LAYER M5 ;
        RECT  8.4 151.116 8.424 151.2 ;
    END
  END sr[272]
  PIN sr[273]
    DIRECTION OUTPUT ;
    USE SIGNAL ;
    PORT
      LAYER M5 ;
        RECT  8.496 151.116 8.52 151.2 ;
    END
  END sr[273]
  PIN sr[274]
    DIRECTION OUTPUT ;
    USE SIGNAL ;
    PORT
      LAYER M5 ;
        RECT  8.592 151.116 8.616 151.2 ;
    END
  END sr[274]
  PIN sr[275]
    DIRECTION OUTPUT ;
    USE SIGNAL ;
    PORT
      LAYER M5 ;
        RECT  8.688 151.116 8.712 151.2 ;
    END
  END sr[275]
  PIN sr[276]
    DIRECTION OUTPUT ;
    USE SIGNAL ;
    PORT
      LAYER M5 ;
        RECT  8.784 151.116 8.808 151.2 ;
    END
  END sr[276]
  PIN sr[277]
    DIRECTION OUTPUT ;
    USE SIGNAL ;
    PORT
      LAYER M5 ;
        RECT  8.88 151.116 8.904 151.2 ;
    END
  END sr[277]
  PIN sr[278]
    DIRECTION OUTPUT ;
    USE SIGNAL ;
    PORT
      LAYER M5 ;
        RECT  8.976 151.116 9 151.2 ;
    END
  END sr[278]
  PIN sr[279]
    DIRECTION OUTPUT ;
    USE SIGNAL ;
    PORT
      LAYER M5 ;
        RECT  9.072 151.116 9.096 151.2 ;
    END
  END sr[279]
  PIN sr[27]
    DIRECTION OUTPUT ;
    USE SIGNAL ;
    PORT
      LAYER M5 ;
        RECT  34.8 151.116 34.824 151.2 ;
    END
  END sr[27]
  PIN sr[280]
    DIRECTION OUTPUT ;
    USE SIGNAL ;
    PORT
      LAYER M5 ;
        RECT  9.168 151.116 9.192 151.2 ;
    END
  END sr[280]
  PIN sr[281]
    DIRECTION OUTPUT ;
    USE SIGNAL ;
    PORT
      LAYER M5 ;
        RECT  9.264 151.116 9.288 151.2 ;
    END
  END sr[281]
  PIN sr[282]
    DIRECTION OUTPUT ;
    USE SIGNAL ;
    PORT
      LAYER M5 ;
        RECT  9.36 151.116 9.384 151.2 ;
    END
  END sr[282]
  PIN sr[283]
    DIRECTION OUTPUT ;
    USE SIGNAL ;
    PORT
      LAYER M5 ;
        RECT  9.456 151.116 9.48 151.2 ;
    END
  END sr[283]
  PIN sr[284]
    DIRECTION OUTPUT ;
    USE SIGNAL ;
    PORT
      LAYER M5 ;
        RECT  9.552 151.116 9.576 151.2 ;
    END
  END sr[284]
  PIN sr[285]
    DIRECTION OUTPUT ;
    USE SIGNAL ;
    PORT
      LAYER M5 ;
        RECT  9.648 151.116 9.672 151.2 ;
    END
  END sr[285]
  PIN sr[286]
    DIRECTION OUTPUT ;
    USE SIGNAL ;
    PORT
      LAYER M5 ;
        RECT  9.744 151.116 9.768 151.2 ;
    END
  END sr[286]
  PIN sr[287]
    DIRECTION OUTPUT ;
    USE SIGNAL ;
    PORT
      LAYER M5 ;
        RECT  9.84 151.116 9.864 151.2 ;
    END
  END sr[287]
  PIN sr[288]
    DIRECTION OUTPUT ;
    USE SIGNAL ;
    PORT
      LAYER M5 ;
        RECT  3.792 151.116 3.816 151.2 ;
    END
  END sr[288]
  PIN sr[289]
    DIRECTION OUTPUT ;
    USE SIGNAL ;
    PORT
      LAYER M5 ;
        RECT  3.888 151.116 3.912 151.2 ;
    END
  END sr[289]
  PIN sr[28]
    DIRECTION OUTPUT ;
    USE SIGNAL ;
    PORT
      LAYER M5 ;
        RECT  34.896 151.116 34.92 151.2 ;
    END
  END sr[28]
  PIN sr[290]
    DIRECTION OUTPUT ;
    USE SIGNAL ;
    PORT
      LAYER M5 ;
        RECT  3.984 151.116 4.008 151.2 ;
    END
  END sr[290]
  PIN sr[291]
    DIRECTION OUTPUT ;
    USE SIGNAL ;
    PORT
      LAYER M5 ;
        RECT  4.08 151.116 4.104 151.2 ;
    END
  END sr[291]
  PIN sr[292]
    DIRECTION OUTPUT ;
    USE SIGNAL ;
    PORT
      LAYER M5 ;
        RECT  4.176 151.116 4.2 151.2 ;
    END
  END sr[292]
  PIN sr[293]
    DIRECTION OUTPUT ;
    USE SIGNAL ;
    PORT
      LAYER M5 ;
        RECT  4.272 151.116 4.296 151.2 ;
    END
  END sr[293]
  PIN sr[294]
    DIRECTION OUTPUT ;
    USE SIGNAL ;
    PORT
      LAYER M5 ;
        RECT  4.368 151.116 4.392 151.2 ;
    END
  END sr[294]
  PIN sr[295]
    DIRECTION OUTPUT ;
    USE SIGNAL ;
    PORT
      LAYER M5 ;
        RECT  4.464 151.116 4.488 151.2 ;
    END
  END sr[295]
  PIN sr[296]
    DIRECTION OUTPUT ;
    USE SIGNAL ;
    PORT
      LAYER M5 ;
        RECT  4.56 151.116 4.584 151.2 ;
    END
  END sr[296]
  PIN sr[297]
    DIRECTION OUTPUT ;
    USE SIGNAL ;
    PORT
      LAYER M5 ;
        RECT  4.656 151.116 4.68 151.2 ;
    END
  END sr[297]
  PIN sr[298]
    DIRECTION OUTPUT ;
    USE SIGNAL ;
    PORT
      LAYER M5 ;
        RECT  4.752 151.116 4.776 151.2 ;
    END
  END sr[298]
  PIN sr[299]
    DIRECTION OUTPUT ;
    USE SIGNAL ;
    PORT
      LAYER M5 ;
        RECT  4.848 151.116 4.872 151.2 ;
    END
  END sr[299]
  PIN sr[29]
    DIRECTION OUTPUT ;
    USE SIGNAL ;
    PORT
      LAYER M5 ;
        RECT  34.992 151.116 35.016 151.2 ;
    END
  END sr[29]
  PIN sr[2]
    DIRECTION OUTPUT ;
    USE SIGNAL ;
    PORT
      LAYER M5 ;
        RECT  32.4 151.116 32.424 151.2 ;
    END
  END sr[2]
  PIN sr[300]
    DIRECTION OUTPUT ;
    USE SIGNAL ;
    PORT
      LAYER M5 ;
        RECT  4.944 151.116 4.968 151.2 ;
    END
  END sr[300]
  PIN sr[301]
    DIRECTION OUTPUT ;
    USE SIGNAL ;
    PORT
      LAYER M5 ;
        RECT  5.04 151.116 5.064 151.2 ;
    END
  END sr[301]
  PIN sr[302]
    DIRECTION OUTPUT ;
    USE SIGNAL ;
    PORT
      LAYER M5 ;
        RECT  5.136 151.116 5.16 151.2 ;
    END
  END sr[302]
  PIN sr[303]
    DIRECTION OUTPUT ;
    USE SIGNAL ;
    PORT
      LAYER M5 ;
        RECT  5.232 151.116 5.256 151.2 ;
    END
  END sr[303]
  PIN sr[304]
    DIRECTION OUTPUT ;
    USE SIGNAL ;
    PORT
      LAYER M5 ;
        RECT  5.328 151.116 5.352 151.2 ;
    END
  END sr[304]
  PIN sr[305]
    DIRECTION OUTPUT ;
    USE SIGNAL ;
    PORT
      LAYER M5 ;
        RECT  5.424 151.116 5.448 151.2 ;
    END
  END sr[305]
  PIN sr[306]
    DIRECTION OUTPUT ;
    USE SIGNAL ;
    PORT
      LAYER M5 ;
        RECT  5.52 151.116 5.544 151.2 ;
    END
  END sr[306]
  PIN sr[307]
    DIRECTION OUTPUT ;
    USE SIGNAL ;
    PORT
      LAYER M5 ;
        RECT  5.616 151.116 5.64 151.2 ;
    END
  END sr[307]
  PIN sr[308]
    DIRECTION OUTPUT ;
    USE SIGNAL ;
    PORT
      LAYER M5 ;
        RECT  5.712 151.116 5.736 151.2 ;
    END
  END sr[308]
  PIN sr[309]
    DIRECTION OUTPUT ;
    USE SIGNAL ;
    PORT
      LAYER M5 ;
        RECT  5.808 151.116 5.832 151.2 ;
    END
  END sr[309]
  PIN sr[30]
    DIRECTION OUTPUT ;
    USE SIGNAL ;
    PORT
      LAYER M5 ;
        RECT  35.088 151.116 35.112 151.2 ;
    END
  END sr[30]
  PIN sr[310]
    DIRECTION OUTPUT ;
    USE SIGNAL ;
    PORT
      LAYER M5 ;
        RECT  5.904 151.116 5.928 151.2 ;
    END
  END sr[310]
  PIN sr[311]
    DIRECTION OUTPUT ;
    USE SIGNAL ;
    PORT
      LAYER M5 ;
        RECT  6 151.116 6.024 151.2 ;
    END
  END sr[311]
  PIN sr[312]
    DIRECTION OUTPUT ;
    USE SIGNAL ;
    PORT
      LAYER M5 ;
        RECT  6.096 151.116 6.12 151.2 ;
    END
  END sr[312]
  PIN sr[313]
    DIRECTION OUTPUT ;
    USE SIGNAL ;
    PORT
      LAYER M5 ;
        RECT  6.192 151.116 6.216 151.2 ;
    END
  END sr[313]
  PIN sr[314]
    DIRECTION OUTPUT ;
    USE SIGNAL ;
    PORT
      LAYER M5 ;
        RECT  6.288 151.116 6.312 151.2 ;
    END
  END sr[314]
  PIN sr[315]
    DIRECTION OUTPUT ;
    USE SIGNAL ;
    PORT
      LAYER M5 ;
        RECT  6.384 151.116 6.408 151.2 ;
    END
  END sr[315]
  PIN sr[316]
    DIRECTION OUTPUT ;
    USE SIGNAL ;
    PORT
      LAYER M5 ;
        RECT  6.48 151.116 6.504 151.2 ;
    END
  END sr[316]
  PIN sr[317]
    DIRECTION OUTPUT ;
    USE SIGNAL ;
    PORT
      LAYER M5 ;
        RECT  6.576 151.116 6.6 151.2 ;
    END
  END sr[317]
  PIN sr[318]
    DIRECTION OUTPUT ;
    USE SIGNAL ;
    PORT
      LAYER M5 ;
        RECT  6.672 151.116 6.696 151.2 ;
    END
  END sr[318]
  PIN sr[319]
    DIRECTION OUTPUT ;
    USE SIGNAL ;
    PORT
      LAYER M5 ;
        RECT  6.768 151.116 6.792 151.2 ;
    END
  END sr[319]
  PIN sr[31]
    DIRECTION OUTPUT ;
    USE SIGNAL ;
    PORT
      LAYER M5 ;
        RECT  35.184 151.116 35.208 151.2 ;
    END
  END sr[31]
  PIN sr[320]
    DIRECTION OUTPUT ;
    USE SIGNAL ;
    PORT
      LAYER M5 ;
        RECT  0.72 151.116 0.744 151.2 ;
    END
  END sr[320]
  PIN sr[321]
    DIRECTION OUTPUT ;
    USE SIGNAL ;
    PORT
      LAYER M5 ;
        RECT  0.816 151.116 0.84 151.2 ;
    END
  END sr[321]
  PIN sr[322]
    DIRECTION OUTPUT ;
    USE SIGNAL ;
    PORT
      LAYER M5 ;
        RECT  0.912 151.116 0.936 151.2 ;
    END
  END sr[322]
  PIN sr[323]
    DIRECTION OUTPUT ;
    USE SIGNAL ;
    PORT
      LAYER M5 ;
        RECT  1.008 151.116 1.032 151.2 ;
    END
  END sr[323]
  PIN sr[324]
    DIRECTION OUTPUT ;
    USE SIGNAL ;
    PORT
      LAYER M5 ;
        RECT  1.104 151.116 1.128 151.2 ;
    END
  END sr[324]
  PIN sr[325]
    DIRECTION OUTPUT ;
    USE SIGNAL ;
    PORT
      LAYER M5 ;
        RECT  1.2 151.116 1.224 151.2 ;
    END
  END sr[325]
  PIN sr[326]
    DIRECTION OUTPUT ;
    USE SIGNAL ;
    PORT
      LAYER M5 ;
        RECT  1.296 151.116 1.32 151.2 ;
    END
  END sr[326]
  PIN sr[327]
    DIRECTION OUTPUT ;
    USE SIGNAL ;
    PORT
      LAYER M5 ;
        RECT  1.392 151.116 1.416 151.2 ;
    END
  END sr[327]
  PIN sr[328]
    DIRECTION OUTPUT ;
    USE SIGNAL ;
    PORT
      LAYER M5 ;
        RECT  1.488 151.116 1.512 151.2 ;
    END
  END sr[328]
  PIN sr[329]
    DIRECTION OUTPUT ;
    USE SIGNAL ;
    PORT
      LAYER M5 ;
        RECT  1.584 151.116 1.608 151.2 ;
    END
  END sr[329]
  PIN sr[32]
    DIRECTION OUTPUT ;
    USE SIGNAL ;
    PORT
      LAYER M5 ;
        RECT  29.136 151.116 29.16 151.2 ;
    END
  END sr[32]
  PIN sr[330]
    DIRECTION OUTPUT ;
    USE SIGNAL ;
    PORT
      LAYER M5 ;
        RECT  1.68 151.116 1.704 151.2 ;
    END
  END sr[330]
  PIN sr[331]
    DIRECTION OUTPUT ;
    USE SIGNAL ;
    PORT
      LAYER M5 ;
        RECT  1.776 151.116 1.8 151.2 ;
    END
  END sr[331]
  PIN sr[332]
    DIRECTION OUTPUT ;
    USE SIGNAL ;
    PORT
      LAYER M5 ;
        RECT  1.872 151.116 1.896 151.2 ;
    END
  END sr[332]
  PIN sr[333]
    DIRECTION OUTPUT ;
    USE SIGNAL ;
    PORT
      LAYER M5 ;
        RECT  1.968 151.116 1.992 151.2 ;
    END
  END sr[333]
  PIN sr[334]
    DIRECTION OUTPUT ;
    USE SIGNAL ;
    PORT
      LAYER M5 ;
        RECT  2.064 151.116 2.088 151.2 ;
    END
  END sr[334]
  PIN sr[335]
    DIRECTION OUTPUT ;
    USE SIGNAL ;
    PORT
      LAYER M5 ;
        RECT  2.16 151.116 2.184 151.2 ;
    END
  END sr[335]
  PIN sr[336]
    DIRECTION OUTPUT ;
    USE SIGNAL ;
    PORT
      LAYER M5 ;
        RECT  2.256 151.116 2.28 151.2 ;
    END
  END sr[336]
  PIN sr[337]
    DIRECTION OUTPUT ;
    USE SIGNAL ;
    PORT
      LAYER M5 ;
        RECT  2.352 151.116 2.376 151.2 ;
    END
  END sr[337]
  PIN sr[338]
    DIRECTION OUTPUT ;
    USE SIGNAL ;
    PORT
      LAYER M5 ;
        RECT  2.448 151.116 2.472 151.2 ;
    END
  END sr[338]
  PIN sr[339]
    DIRECTION OUTPUT ;
    USE SIGNAL ;
    PORT
      LAYER M5 ;
        RECT  2.544 151.116 2.568 151.2 ;
    END
  END sr[339]
  PIN sr[33]
    DIRECTION OUTPUT ;
    USE SIGNAL ;
    PORT
      LAYER M5 ;
        RECT  29.232 151.116 29.256 151.2 ;
    END
  END sr[33]
  PIN sr[340]
    DIRECTION OUTPUT ;
    USE SIGNAL ;
    PORT
      LAYER M5 ;
        RECT  2.64 151.116 2.664 151.2 ;
    END
  END sr[340]
  PIN sr[341]
    DIRECTION OUTPUT ;
    USE SIGNAL ;
    PORT
      LAYER M5 ;
        RECT  2.736 151.116 2.76 151.2 ;
    END
  END sr[341]
  PIN sr[342]
    DIRECTION OUTPUT ;
    USE SIGNAL ;
    PORT
      LAYER M5 ;
        RECT  2.832 151.116 2.856 151.2 ;
    END
  END sr[342]
  PIN sr[343]
    DIRECTION OUTPUT ;
    USE SIGNAL ;
    PORT
      LAYER M5 ;
        RECT  2.928 151.116 2.952 151.2 ;
    END
  END sr[343]
  PIN sr[344]
    DIRECTION OUTPUT ;
    USE SIGNAL ;
    PORT
      LAYER M5 ;
        RECT  3.024 151.116 3.048 151.2 ;
    END
  END sr[344]
  PIN sr[345]
    DIRECTION OUTPUT ;
    USE SIGNAL ;
    PORT
      LAYER M5 ;
        RECT  3.12 151.116 3.144 151.2 ;
    END
  END sr[345]
  PIN sr[346]
    DIRECTION OUTPUT ;
    USE SIGNAL ;
    PORT
      LAYER M5 ;
        RECT  3.216 151.116 3.24 151.2 ;
    END
  END sr[346]
  PIN sr[347]
    DIRECTION OUTPUT ;
    USE SIGNAL ;
    PORT
      LAYER M5 ;
        RECT  3.312 151.116 3.336 151.2 ;
    END
  END sr[347]
  PIN sr[348]
    DIRECTION OUTPUT ;
    USE SIGNAL ;
    PORT
      LAYER M5 ;
        RECT  3.408 151.116 3.432 151.2 ;
    END
  END sr[348]
  PIN sr[349]
    DIRECTION OUTPUT ;
    USE SIGNAL ;
    PORT
      LAYER M5 ;
        RECT  3.504 151.116 3.528 151.2 ;
    END
  END sr[349]
  PIN sr[34]
    DIRECTION OUTPUT ;
    USE SIGNAL ;
    PORT
      LAYER M5 ;
        RECT  29.328 151.116 29.352 151.2 ;
    END
  END sr[34]
  PIN sr[350]
    DIRECTION OUTPUT ;
    USE SIGNAL ;
    PORT
      LAYER M5 ;
        RECT  3.6 151.116 3.624 151.2 ;
    END
  END sr[350]
  PIN sr[351]
    DIRECTION OUTPUT ;
    USE SIGNAL ;
    PORT
      LAYER M5 ;
        RECT  3.696 151.116 3.72 151.2 ;
    END
  END sr[351]
  PIN sr[352]
    DIRECTION OUTPUT ;
    USE SIGNAL ;
    PORT
      LAYER M5 ;
        RECT  48.336 151.116 48.36 151.2 ;
    END
  END sr[352]
  PIN sr[353]
    DIRECTION OUTPUT ;
    USE SIGNAL ;
    PORT
      LAYER M5 ;
        RECT  48.432 151.116 48.456 151.2 ;
    END
  END sr[353]
  PIN sr[354]
    DIRECTION OUTPUT ;
    USE SIGNAL ;
    PORT
      LAYER M5 ;
        RECT  48.528 151.116 48.552 151.2 ;
    END
  END sr[354]
  PIN sr[355]
    DIRECTION OUTPUT ;
    USE SIGNAL ;
    PORT
      LAYER M5 ;
        RECT  48.624 151.116 48.648 151.2 ;
    END
  END sr[355]
  PIN sr[356]
    DIRECTION OUTPUT ;
    USE SIGNAL ;
    PORT
      LAYER M5 ;
        RECT  48.72 151.116 48.744 151.2 ;
    END
  END sr[356]
  PIN sr[357]
    DIRECTION OUTPUT ;
    USE SIGNAL ;
    PORT
      LAYER M5 ;
        RECT  48.816 151.116 48.84 151.2 ;
    END
  END sr[357]
  PIN sr[358]
    DIRECTION OUTPUT ;
    USE SIGNAL ;
    PORT
      LAYER M5 ;
        RECT  48.912 151.116 48.936 151.2 ;
    END
  END sr[358]
  PIN sr[359]
    DIRECTION OUTPUT ;
    USE SIGNAL ;
    PORT
      LAYER M5 ;
        RECT  49.008 151.116 49.032 151.2 ;
    END
  END sr[359]
  PIN sr[35]
    DIRECTION OUTPUT ;
    USE SIGNAL ;
    PORT
      LAYER M5 ;
        RECT  29.424 151.116 29.448 151.2 ;
    END
  END sr[35]
  PIN sr[360]
    DIRECTION OUTPUT ;
    USE SIGNAL ;
    PORT
      LAYER M5 ;
        RECT  49.104 151.116 49.128 151.2 ;
    END
  END sr[360]
  PIN sr[361]
    DIRECTION OUTPUT ;
    USE SIGNAL ;
    PORT
      LAYER M5 ;
        RECT  49.2 151.116 49.224 151.2 ;
    END
  END sr[361]
  PIN sr[362]
    DIRECTION OUTPUT ;
    USE SIGNAL ;
    PORT
      LAYER M5 ;
        RECT  49.296 151.116 49.32 151.2 ;
    END
  END sr[362]
  PIN sr[363]
    DIRECTION OUTPUT ;
    USE SIGNAL ;
    PORT
      LAYER M5 ;
        RECT  49.392 151.116 49.416 151.2 ;
    END
  END sr[363]
  PIN sr[364]
    DIRECTION OUTPUT ;
    USE SIGNAL ;
    PORT
      LAYER M5 ;
        RECT  49.488 151.116 49.512 151.2 ;
    END
  END sr[364]
  PIN sr[365]
    DIRECTION OUTPUT ;
    USE SIGNAL ;
    PORT
      LAYER M5 ;
        RECT  49.584 151.116 49.608 151.2 ;
    END
  END sr[365]
  PIN sr[366]
    DIRECTION OUTPUT ;
    USE SIGNAL ;
    PORT
      LAYER M5 ;
        RECT  49.68 151.116 49.704 151.2 ;
    END
  END sr[366]
  PIN sr[367]
    DIRECTION OUTPUT ;
    USE SIGNAL ;
    PORT
      LAYER M5 ;
        RECT  49.776 151.116 49.8 151.2 ;
    END
  END sr[367]
  PIN sr[368]
    DIRECTION OUTPUT ;
    USE SIGNAL ;
    PORT
      LAYER M5 ;
        RECT  49.872 151.116 49.896 151.2 ;
    END
  END sr[368]
  PIN sr[369]
    DIRECTION OUTPUT ;
    USE SIGNAL ;
    PORT
      LAYER M5 ;
        RECT  49.968 151.116 49.992 151.2 ;
    END
  END sr[369]
  PIN sr[36]
    DIRECTION OUTPUT ;
    USE SIGNAL ;
    PORT
      LAYER M5 ;
        RECT  29.52 151.116 29.544 151.2 ;
    END
  END sr[36]
  PIN sr[370]
    DIRECTION OUTPUT ;
    USE SIGNAL ;
    PORT
      LAYER M5 ;
        RECT  50.064 151.116 50.088 151.2 ;
    END
  END sr[370]
  PIN sr[371]
    DIRECTION OUTPUT ;
    USE SIGNAL ;
    PORT
      LAYER M5 ;
        RECT  50.16 151.116 50.184 151.2 ;
    END
  END sr[371]
  PIN sr[372]
    DIRECTION OUTPUT ;
    USE SIGNAL ;
    PORT
      LAYER M5 ;
        RECT  50.256 151.116 50.28 151.2 ;
    END
  END sr[372]
  PIN sr[373]
    DIRECTION OUTPUT ;
    USE SIGNAL ;
    PORT
      LAYER M5 ;
        RECT  50.352 151.116 50.376 151.2 ;
    END
  END sr[373]
  PIN sr[374]
    DIRECTION OUTPUT ;
    USE SIGNAL ;
    PORT
      LAYER M5 ;
        RECT  50.448 151.116 50.472 151.2 ;
    END
  END sr[374]
  PIN sr[375]
    DIRECTION OUTPUT ;
    USE SIGNAL ;
    PORT
      LAYER M5 ;
        RECT  50.544 151.116 50.568 151.2 ;
    END
  END sr[375]
  PIN sr[376]
    DIRECTION OUTPUT ;
    USE SIGNAL ;
    PORT
      LAYER M5 ;
        RECT  50.64 151.116 50.664 151.2 ;
    END
  END sr[376]
  PIN sr[377]
    DIRECTION OUTPUT ;
    USE SIGNAL ;
    PORT
      LAYER M5 ;
        RECT  50.736 151.116 50.76 151.2 ;
    END
  END sr[377]
  PIN sr[378]
    DIRECTION OUTPUT ;
    USE SIGNAL ;
    PORT
      LAYER M5 ;
        RECT  50.832 151.116 50.856 151.2 ;
    END
  END sr[378]
  PIN sr[379]
    DIRECTION OUTPUT ;
    USE SIGNAL ;
    PORT
      LAYER M5 ;
        RECT  50.928 151.116 50.952 151.2 ;
    END
  END sr[379]
  PIN sr[37]
    DIRECTION OUTPUT ;
    USE SIGNAL ;
    PORT
      LAYER M5 ;
        RECT  29.616 151.116 29.64 151.2 ;
    END
  END sr[37]
  PIN sr[380]
    DIRECTION OUTPUT ;
    USE SIGNAL ;
    PORT
      LAYER M5 ;
        RECT  51.024 151.116 51.048 151.2 ;
    END
  END sr[380]
  PIN sr[381]
    DIRECTION OUTPUT ;
    USE SIGNAL ;
    PORT
      LAYER M5 ;
        RECT  51.12 151.116 51.144 151.2 ;
    END
  END sr[381]
  PIN sr[382]
    DIRECTION OUTPUT ;
    USE SIGNAL ;
    PORT
      LAYER M5 ;
        RECT  51.216 151.116 51.24 151.2 ;
    END
  END sr[382]
  PIN sr[383]
    DIRECTION OUTPUT ;
    USE SIGNAL ;
    PORT
      LAYER M5 ;
        RECT  51.312 151.116 51.336 151.2 ;
    END
  END sr[383]
  PIN sr[384]
    DIRECTION OUTPUT ;
    USE SIGNAL ;
    PORT
      LAYER M5 ;
        RECT  45.264 151.116 45.288 151.2 ;
    END
  END sr[384]
  PIN sr[385]
    DIRECTION OUTPUT ;
    USE SIGNAL ;
    PORT
      LAYER M5 ;
        RECT  45.36 151.116 45.384 151.2 ;
    END
  END sr[385]
  PIN sr[386]
    DIRECTION OUTPUT ;
    USE SIGNAL ;
    PORT
      LAYER M5 ;
        RECT  45.456 151.116 45.48 151.2 ;
    END
  END sr[386]
  PIN sr[387]
    DIRECTION OUTPUT ;
    USE SIGNAL ;
    PORT
      LAYER M5 ;
        RECT  45.552 151.116 45.576 151.2 ;
    END
  END sr[387]
  PIN sr[388]
    DIRECTION OUTPUT ;
    USE SIGNAL ;
    PORT
      LAYER M5 ;
        RECT  45.648 151.116 45.672 151.2 ;
    END
  END sr[388]
  PIN sr[389]
    DIRECTION OUTPUT ;
    USE SIGNAL ;
    PORT
      LAYER M5 ;
        RECT  45.744 151.116 45.768 151.2 ;
    END
  END sr[389]
  PIN sr[38]
    DIRECTION OUTPUT ;
    USE SIGNAL ;
    PORT
      LAYER M5 ;
        RECT  29.712 151.116 29.736 151.2 ;
    END
  END sr[38]
  PIN sr[390]
    DIRECTION OUTPUT ;
    USE SIGNAL ;
    PORT
      LAYER M5 ;
        RECT  45.84 151.116 45.864 151.2 ;
    END
  END sr[390]
  PIN sr[391]
    DIRECTION OUTPUT ;
    USE SIGNAL ;
    PORT
      LAYER M5 ;
        RECT  45.936 151.116 45.96 151.2 ;
    END
  END sr[391]
  PIN sr[392]
    DIRECTION OUTPUT ;
    USE SIGNAL ;
    PORT
      LAYER M5 ;
        RECT  46.032 151.116 46.056 151.2 ;
    END
  END sr[392]
  PIN sr[393]
    DIRECTION OUTPUT ;
    USE SIGNAL ;
    PORT
      LAYER M5 ;
        RECT  46.128 151.116 46.152 151.2 ;
    END
  END sr[393]
  PIN sr[394]
    DIRECTION OUTPUT ;
    USE SIGNAL ;
    PORT
      LAYER M5 ;
        RECT  46.224 151.116 46.248 151.2 ;
    END
  END sr[394]
  PIN sr[395]
    DIRECTION OUTPUT ;
    USE SIGNAL ;
    PORT
      LAYER M5 ;
        RECT  46.32 151.116 46.344 151.2 ;
    END
  END sr[395]
  PIN sr[396]
    DIRECTION OUTPUT ;
    USE SIGNAL ;
    PORT
      LAYER M5 ;
        RECT  46.416 151.116 46.44 151.2 ;
    END
  END sr[396]
  PIN sr[397]
    DIRECTION OUTPUT ;
    USE SIGNAL ;
    PORT
      LAYER M5 ;
        RECT  46.512 151.116 46.536 151.2 ;
    END
  END sr[397]
  PIN sr[398]
    DIRECTION OUTPUT ;
    USE SIGNAL ;
    PORT
      LAYER M5 ;
        RECT  46.608 151.116 46.632 151.2 ;
    END
  END sr[398]
  PIN sr[399]
    DIRECTION OUTPUT ;
    USE SIGNAL ;
    PORT
      LAYER M5 ;
        RECT  46.704 151.116 46.728 151.2 ;
    END
  END sr[399]
  PIN sr[39]
    DIRECTION OUTPUT ;
    USE SIGNAL ;
    PORT
      LAYER M5 ;
        RECT  29.808 151.116 29.832 151.2 ;
    END
  END sr[39]
  PIN sr[3]
    DIRECTION OUTPUT ;
    USE SIGNAL ;
    PORT
      LAYER M5 ;
        RECT  32.496 151.116 32.52 151.2 ;
    END
  END sr[3]
  PIN sr[400]
    DIRECTION OUTPUT ;
    USE SIGNAL ;
    PORT
      LAYER M5 ;
        RECT  46.8 151.116 46.824 151.2 ;
    END
  END sr[400]
  PIN sr[401]
    DIRECTION OUTPUT ;
    USE SIGNAL ;
    PORT
      LAYER M5 ;
        RECT  46.896 151.116 46.92 151.2 ;
    END
  END sr[401]
  PIN sr[402]
    DIRECTION OUTPUT ;
    USE SIGNAL ;
    PORT
      LAYER M5 ;
        RECT  46.992 151.116 47.016 151.2 ;
    END
  END sr[402]
  PIN sr[403]
    DIRECTION OUTPUT ;
    USE SIGNAL ;
    PORT
      LAYER M5 ;
        RECT  47.088 151.116 47.112 151.2 ;
    END
  END sr[403]
  PIN sr[404]
    DIRECTION OUTPUT ;
    USE SIGNAL ;
    PORT
      LAYER M5 ;
        RECT  47.184 151.116 47.208 151.2 ;
    END
  END sr[404]
  PIN sr[405]
    DIRECTION OUTPUT ;
    USE SIGNAL ;
    PORT
      LAYER M5 ;
        RECT  47.28 151.116 47.304 151.2 ;
    END
  END sr[405]
  PIN sr[406]
    DIRECTION OUTPUT ;
    USE SIGNAL ;
    PORT
      LAYER M5 ;
        RECT  47.376 151.116 47.4 151.2 ;
    END
  END sr[406]
  PIN sr[407]
    DIRECTION OUTPUT ;
    USE SIGNAL ;
    PORT
      LAYER M5 ;
        RECT  47.472 151.116 47.496 151.2 ;
    END
  END sr[407]
  PIN sr[408]
    DIRECTION OUTPUT ;
    USE SIGNAL ;
    PORT
      LAYER M5 ;
        RECT  47.568 151.116 47.592 151.2 ;
    END
  END sr[408]
  PIN sr[409]
    DIRECTION OUTPUT ;
    USE SIGNAL ;
    PORT
      LAYER M5 ;
        RECT  47.664 151.116 47.688 151.2 ;
    END
  END sr[409]
  PIN sr[40]
    DIRECTION OUTPUT ;
    USE SIGNAL ;
    PORT
      LAYER M5 ;
        RECT  29.904 151.116 29.928 151.2 ;
    END
  END sr[40]
  PIN sr[410]
    DIRECTION OUTPUT ;
    USE SIGNAL ;
    PORT
      LAYER M5 ;
        RECT  47.76 151.116 47.784 151.2 ;
    END
  END sr[410]
  PIN sr[411]
    DIRECTION OUTPUT ;
    USE SIGNAL ;
    PORT
      LAYER M5 ;
        RECT  47.856 151.116 47.88 151.2 ;
    END
  END sr[411]
  PIN sr[412]
    DIRECTION OUTPUT ;
    USE SIGNAL ;
    PORT
      LAYER M5 ;
        RECT  47.952 151.116 47.976 151.2 ;
    END
  END sr[412]
  PIN sr[413]
    DIRECTION OUTPUT ;
    USE SIGNAL ;
    PORT
      LAYER M5 ;
        RECT  48.048 151.116 48.072 151.2 ;
    END
  END sr[413]
  PIN sr[414]
    DIRECTION OUTPUT ;
    USE SIGNAL ;
    PORT
      LAYER M5 ;
        RECT  48.144 151.116 48.168 151.2 ;
    END
  END sr[414]
  PIN sr[415]
    DIRECTION OUTPUT ;
    USE SIGNAL ;
    PORT
      LAYER M5 ;
        RECT  48.24 151.116 48.264 151.2 ;
    END
  END sr[415]
  PIN sr[416]
    DIRECTION OUTPUT ;
    USE SIGNAL ;
    PORT
      LAYER M5 ;
        RECT  42.192 151.116 42.216 151.2 ;
    END
  END sr[416]
  PIN sr[417]
    DIRECTION OUTPUT ;
    USE SIGNAL ;
    PORT
      LAYER M5 ;
        RECT  42.288 151.116 42.312 151.2 ;
    END
  END sr[417]
  PIN sr[418]
    DIRECTION OUTPUT ;
    USE SIGNAL ;
    PORT
      LAYER M5 ;
        RECT  42.384 151.116 42.408 151.2 ;
    END
  END sr[418]
  PIN sr[419]
    DIRECTION OUTPUT ;
    USE SIGNAL ;
    PORT
      LAYER M5 ;
        RECT  42.48 151.116 42.504 151.2 ;
    END
  END sr[419]
  PIN sr[41]
    DIRECTION OUTPUT ;
    USE SIGNAL ;
    PORT
      LAYER M5 ;
        RECT  30 151.116 30.024 151.2 ;
    END
  END sr[41]
  PIN sr[420]
    DIRECTION OUTPUT ;
    USE SIGNAL ;
    PORT
      LAYER M5 ;
        RECT  42.576 151.116 42.6 151.2 ;
    END
  END sr[420]
  PIN sr[421]
    DIRECTION OUTPUT ;
    USE SIGNAL ;
    PORT
      LAYER M5 ;
        RECT  42.672 151.116 42.696 151.2 ;
    END
  END sr[421]
  PIN sr[422]
    DIRECTION OUTPUT ;
    USE SIGNAL ;
    PORT
      LAYER M5 ;
        RECT  42.768 151.116 42.792 151.2 ;
    END
  END sr[422]
  PIN sr[423]
    DIRECTION OUTPUT ;
    USE SIGNAL ;
    PORT
      LAYER M5 ;
        RECT  42.864 151.116 42.888 151.2 ;
    END
  END sr[423]
  PIN sr[424]
    DIRECTION OUTPUT ;
    USE SIGNAL ;
    PORT
      LAYER M5 ;
        RECT  42.96 151.116 42.984 151.2 ;
    END
  END sr[424]
  PIN sr[425]
    DIRECTION OUTPUT ;
    USE SIGNAL ;
    PORT
      LAYER M5 ;
        RECT  43.056 151.116 43.08 151.2 ;
    END
  END sr[425]
  PIN sr[426]
    DIRECTION OUTPUT ;
    USE SIGNAL ;
    PORT
      LAYER M5 ;
        RECT  43.152 151.116 43.176 151.2 ;
    END
  END sr[426]
  PIN sr[427]
    DIRECTION OUTPUT ;
    USE SIGNAL ;
    PORT
      LAYER M5 ;
        RECT  43.248 151.116 43.272 151.2 ;
    END
  END sr[427]
  PIN sr[428]
    DIRECTION OUTPUT ;
    USE SIGNAL ;
    PORT
      LAYER M5 ;
        RECT  43.344 151.116 43.368 151.2 ;
    END
  END sr[428]
  PIN sr[429]
    DIRECTION OUTPUT ;
    USE SIGNAL ;
    PORT
      LAYER M5 ;
        RECT  43.44 151.116 43.464 151.2 ;
    END
  END sr[429]
  PIN sr[42]
    DIRECTION OUTPUT ;
    USE SIGNAL ;
    PORT
      LAYER M5 ;
        RECT  30.096 151.116 30.12 151.2 ;
    END
  END sr[42]
  PIN sr[430]
    DIRECTION OUTPUT ;
    USE SIGNAL ;
    PORT
      LAYER M5 ;
        RECT  43.536 151.116 43.56 151.2 ;
    END
  END sr[430]
  PIN sr[431]
    DIRECTION OUTPUT ;
    USE SIGNAL ;
    PORT
      LAYER M5 ;
        RECT  43.632 151.116 43.656 151.2 ;
    END
  END sr[431]
  PIN sr[432]
    DIRECTION OUTPUT ;
    USE SIGNAL ;
    PORT
      LAYER M5 ;
        RECT  43.728 151.116 43.752 151.2 ;
    END
  END sr[432]
  PIN sr[433]
    DIRECTION OUTPUT ;
    USE SIGNAL ;
    PORT
      LAYER M5 ;
        RECT  43.824 151.116 43.848 151.2 ;
    END
  END sr[433]
  PIN sr[434]
    DIRECTION OUTPUT ;
    USE SIGNAL ;
    PORT
      LAYER M5 ;
        RECT  43.92 151.116 43.944 151.2 ;
    END
  END sr[434]
  PIN sr[435]
    DIRECTION OUTPUT ;
    USE SIGNAL ;
    PORT
      LAYER M5 ;
        RECT  44.016 151.116 44.04 151.2 ;
    END
  END sr[435]
  PIN sr[436]
    DIRECTION OUTPUT ;
    USE SIGNAL ;
    PORT
      LAYER M5 ;
        RECT  44.112 151.116 44.136 151.2 ;
    END
  END sr[436]
  PIN sr[437]
    DIRECTION OUTPUT ;
    USE SIGNAL ;
    PORT
      LAYER M5 ;
        RECT  44.208 151.116 44.232 151.2 ;
    END
  END sr[437]
  PIN sr[438]
    DIRECTION OUTPUT ;
    USE SIGNAL ;
    PORT
      LAYER M5 ;
        RECT  44.304 151.116 44.328 151.2 ;
    END
  END sr[438]
  PIN sr[439]
    DIRECTION OUTPUT ;
    USE SIGNAL ;
    PORT
      LAYER M5 ;
        RECT  44.4 151.116 44.424 151.2 ;
    END
  END sr[439]
  PIN sr[43]
    DIRECTION OUTPUT ;
    USE SIGNAL ;
    PORT
      LAYER M5 ;
        RECT  30.192 151.116 30.216 151.2 ;
    END
  END sr[43]
  PIN sr[440]
    DIRECTION OUTPUT ;
    USE SIGNAL ;
    PORT
      LAYER M5 ;
        RECT  44.496 151.116 44.52 151.2 ;
    END
  END sr[440]
  PIN sr[441]
    DIRECTION OUTPUT ;
    USE SIGNAL ;
    PORT
      LAYER M5 ;
        RECT  44.592 151.116 44.616 151.2 ;
    END
  END sr[441]
  PIN sr[442]
    DIRECTION OUTPUT ;
    USE SIGNAL ;
    PORT
      LAYER M5 ;
        RECT  44.688 151.116 44.712 151.2 ;
    END
  END sr[442]
  PIN sr[443]
    DIRECTION OUTPUT ;
    USE SIGNAL ;
    PORT
      LAYER M5 ;
        RECT  44.784 151.116 44.808 151.2 ;
    END
  END sr[443]
  PIN sr[444]
    DIRECTION OUTPUT ;
    USE SIGNAL ;
    PORT
      LAYER M5 ;
        RECT  44.88 151.116 44.904 151.2 ;
    END
  END sr[444]
  PIN sr[445]
    DIRECTION OUTPUT ;
    USE SIGNAL ;
    PORT
      LAYER M5 ;
        RECT  44.976 151.116 45 151.2 ;
    END
  END sr[445]
  PIN sr[446]
    DIRECTION OUTPUT ;
    USE SIGNAL ;
    PORT
      LAYER M5 ;
        RECT  45.072 151.116 45.096 151.2 ;
    END
  END sr[446]
  PIN sr[447]
    DIRECTION OUTPUT ;
    USE SIGNAL ;
    PORT
      LAYER M5 ;
        RECT  45.168 151.116 45.192 151.2 ;
    END
  END sr[447]
  PIN sr[448]
    DIRECTION OUTPUT ;
    USE SIGNAL ;
    PORT
      LAYER M5 ;
        RECT  39.12 151.116 39.144 151.2 ;
    END
  END sr[448]
  PIN sr[449]
    DIRECTION OUTPUT ;
    USE SIGNAL ;
    PORT
      LAYER M5 ;
        RECT  39.216 151.116 39.24 151.2 ;
    END
  END sr[449]
  PIN sr[44]
    DIRECTION OUTPUT ;
    USE SIGNAL ;
    PORT
      LAYER M5 ;
        RECT  30.288 151.116 30.312 151.2 ;
    END
  END sr[44]
  PIN sr[450]
    DIRECTION OUTPUT ;
    USE SIGNAL ;
    PORT
      LAYER M5 ;
        RECT  39.312 151.116 39.336 151.2 ;
    END
  END sr[450]
  PIN sr[451]
    DIRECTION OUTPUT ;
    USE SIGNAL ;
    PORT
      LAYER M5 ;
        RECT  39.408 151.116 39.432 151.2 ;
    END
  END sr[451]
  PIN sr[452]
    DIRECTION OUTPUT ;
    USE SIGNAL ;
    PORT
      LAYER M5 ;
        RECT  39.504 151.116 39.528 151.2 ;
    END
  END sr[452]
  PIN sr[453]
    DIRECTION OUTPUT ;
    USE SIGNAL ;
    PORT
      LAYER M5 ;
        RECT  39.6 151.116 39.624 151.2 ;
    END
  END sr[453]
  PIN sr[454]
    DIRECTION OUTPUT ;
    USE SIGNAL ;
    PORT
      LAYER M5 ;
        RECT  39.696 151.116 39.72 151.2 ;
    END
  END sr[454]
  PIN sr[455]
    DIRECTION OUTPUT ;
    USE SIGNAL ;
    PORT
      LAYER M5 ;
        RECT  39.792 151.116 39.816 151.2 ;
    END
  END sr[455]
  PIN sr[456]
    DIRECTION OUTPUT ;
    USE SIGNAL ;
    PORT
      LAYER M5 ;
        RECT  39.888 151.116 39.912 151.2 ;
    END
  END sr[456]
  PIN sr[457]
    DIRECTION OUTPUT ;
    USE SIGNAL ;
    PORT
      LAYER M5 ;
        RECT  39.984 151.116 40.008 151.2 ;
    END
  END sr[457]
  PIN sr[458]
    DIRECTION OUTPUT ;
    USE SIGNAL ;
    PORT
      LAYER M5 ;
        RECT  40.08 151.116 40.104 151.2 ;
    END
  END sr[458]
  PIN sr[459]
    DIRECTION OUTPUT ;
    USE SIGNAL ;
    PORT
      LAYER M5 ;
        RECT  40.176 151.116 40.2 151.2 ;
    END
  END sr[459]
  PIN sr[45]
    DIRECTION OUTPUT ;
    USE SIGNAL ;
    PORT
      LAYER M5 ;
        RECT  30.384 151.116 30.408 151.2 ;
    END
  END sr[45]
  PIN sr[460]
    DIRECTION OUTPUT ;
    USE SIGNAL ;
    PORT
      LAYER M5 ;
        RECT  40.272 151.116 40.296 151.2 ;
    END
  END sr[460]
  PIN sr[461]
    DIRECTION OUTPUT ;
    USE SIGNAL ;
    PORT
      LAYER M5 ;
        RECT  40.368 151.116 40.392 151.2 ;
    END
  END sr[461]
  PIN sr[462]
    DIRECTION OUTPUT ;
    USE SIGNAL ;
    PORT
      LAYER M5 ;
        RECT  40.464 151.116 40.488 151.2 ;
    END
  END sr[462]
  PIN sr[463]
    DIRECTION OUTPUT ;
    USE SIGNAL ;
    PORT
      LAYER M5 ;
        RECT  40.56 151.116 40.584 151.2 ;
    END
  END sr[463]
  PIN sr[464]
    DIRECTION OUTPUT ;
    USE SIGNAL ;
    PORT
      LAYER M5 ;
        RECT  40.656 151.116 40.68 151.2 ;
    END
  END sr[464]
  PIN sr[465]
    DIRECTION OUTPUT ;
    USE SIGNAL ;
    PORT
      LAYER M5 ;
        RECT  40.752 151.116 40.776 151.2 ;
    END
  END sr[465]
  PIN sr[466]
    DIRECTION OUTPUT ;
    USE SIGNAL ;
    PORT
      LAYER M5 ;
        RECT  40.848 151.116 40.872 151.2 ;
    END
  END sr[466]
  PIN sr[467]
    DIRECTION OUTPUT ;
    USE SIGNAL ;
    PORT
      LAYER M5 ;
        RECT  40.944 151.116 40.968 151.2 ;
    END
  END sr[467]
  PIN sr[468]
    DIRECTION OUTPUT ;
    USE SIGNAL ;
    PORT
      LAYER M5 ;
        RECT  41.04 151.116 41.064 151.2 ;
    END
  END sr[468]
  PIN sr[469]
    DIRECTION OUTPUT ;
    USE SIGNAL ;
    PORT
      LAYER M5 ;
        RECT  41.136 151.116 41.16 151.2 ;
    END
  END sr[469]
  PIN sr[46]
    DIRECTION OUTPUT ;
    USE SIGNAL ;
    PORT
      LAYER M5 ;
        RECT  30.48 151.116 30.504 151.2 ;
    END
  END sr[46]
  PIN sr[470]
    DIRECTION OUTPUT ;
    USE SIGNAL ;
    PORT
      LAYER M5 ;
        RECT  41.232 151.116 41.256 151.2 ;
    END
  END sr[470]
  PIN sr[471]
    DIRECTION OUTPUT ;
    USE SIGNAL ;
    PORT
      LAYER M5 ;
        RECT  41.328 151.116 41.352 151.2 ;
    END
  END sr[471]
  PIN sr[472]
    DIRECTION OUTPUT ;
    USE SIGNAL ;
    PORT
      LAYER M5 ;
        RECT  41.424 151.116 41.448 151.2 ;
    END
  END sr[472]
  PIN sr[473]
    DIRECTION OUTPUT ;
    USE SIGNAL ;
    PORT
      LAYER M5 ;
        RECT  41.52 151.116 41.544 151.2 ;
    END
  END sr[473]
  PIN sr[474]
    DIRECTION OUTPUT ;
    USE SIGNAL ;
    PORT
      LAYER M5 ;
        RECT  41.616 151.116 41.64 151.2 ;
    END
  END sr[474]
  PIN sr[475]
    DIRECTION OUTPUT ;
    USE SIGNAL ;
    PORT
      LAYER M5 ;
        RECT  41.712 151.116 41.736 151.2 ;
    END
  END sr[475]
  PIN sr[476]
    DIRECTION OUTPUT ;
    USE SIGNAL ;
    PORT
      LAYER M5 ;
        RECT  41.808 151.116 41.832 151.2 ;
    END
  END sr[476]
  PIN sr[477]
    DIRECTION OUTPUT ;
    USE SIGNAL ;
    PORT
      LAYER M5 ;
        RECT  41.904 151.116 41.928 151.2 ;
    END
  END sr[477]
  PIN sr[478]
    DIRECTION OUTPUT ;
    USE SIGNAL ;
    PORT
      LAYER M5 ;
        RECT  42 151.116 42.024 151.2 ;
    END
  END sr[478]
  PIN sr[479]
    DIRECTION OUTPUT ;
    USE SIGNAL ;
    PORT
      LAYER M5 ;
        RECT  42.096 151.116 42.12 151.2 ;
    END
  END sr[479]
  PIN sr[47]
    DIRECTION OUTPUT ;
    USE SIGNAL ;
    PORT
      LAYER M5 ;
        RECT  30.576 151.116 30.6 151.2 ;
    END
  END sr[47]
  PIN sr[480]
    DIRECTION OUTPUT ;
    USE SIGNAL ;
    PORT
      LAYER M5 ;
        RECT  36.048 151.116 36.072 151.2 ;
    END
  END sr[480]
  PIN sr[481]
    DIRECTION OUTPUT ;
    USE SIGNAL ;
    PORT
      LAYER M5 ;
        RECT  36.144 151.116 36.168 151.2 ;
    END
  END sr[481]
  PIN sr[482]
    DIRECTION OUTPUT ;
    USE SIGNAL ;
    PORT
      LAYER M5 ;
        RECT  36.24 151.116 36.264 151.2 ;
    END
  END sr[482]
  PIN sr[483]
    DIRECTION OUTPUT ;
    USE SIGNAL ;
    PORT
      LAYER M5 ;
        RECT  36.336 151.116 36.36 151.2 ;
    END
  END sr[483]
  PIN sr[484]
    DIRECTION OUTPUT ;
    USE SIGNAL ;
    PORT
      LAYER M5 ;
        RECT  36.432 151.116 36.456 151.2 ;
    END
  END sr[484]
  PIN sr[485]
    DIRECTION OUTPUT ;
    USE SIGNAL ;
    PORT
      LAYER M5 ;
        RECT  36.528 151.116 36.552 151.2 ;
    END
  END sr[485]
  PIN sr[486]
    DIRECTION OUTPUT ;
    USE SIGNAL ;
    PORT
      LAYER M5 ;
        RECT  36.624 151.116 36.648 151.2 ;
    END
  END sr[486]
  PIN sr[487]
    DIRECTION OUTPUT ;
    USE SIGNAL ;
    PORT
      LAYER M5 ;
        RECT  36.72 151.116 36.744 151.2 ;
    END
  END sr[487]
  PIN sr[488]
    DIRECTION OUTPUT ;
    USE SIGNAL ;
    PORT
      LAYER M5 ;
        RECT  36.816 151.116 36.84 151.2 ;
    END
  END sr[488]
  PIN sr[489]
    DIRECTION OUTPUT ;
    USE SIGNAL ;
    PORT
      LAYER M5 ;
        RECT  36.912 151.116 36.936 151.2 ;
    END
  END sr[489]
  PIN sr[48]
    DIRECTION OUTPUT ;
    USE SIGNAL ;
    PORT
      LAYER M5 ;
        RECT  30.672 151.116 30.696 151.2 ;
    END
  END sr[48]
  PIN sr[490]
    DIRECTION OUTPUT ;
    USE SIGNAL ;
    PORT
      LAYER M5 ;
        RECT  37.008 151.116 37.032 151.2 ;
    END
  END sr[490]
  PIN sr[491]
    DIRECTION OUTPUT ;
    USE SIGNAL ;
    PORT
      LAYER M5 ;
        RECT  37.104 151.116 37.128 151.2 ;
    END
  END sr[491]
  PIN sr[492]
    DIRECTION OUTPUT ;
    USE SIGNAL ;
    PORT
      LAYER M5 ;
        RECT  37.2 151.116 37.224 151.2 ;
    END
  END sr[492]
  PIN sr[493]
    DIRECTION OUTPUT ;
    USE SIGNAL ;
    PORT
      LAYER M5 ;
        RECT  37.296 151.116 37.32 151.2 ;
    END
  END sr[493]
  PIN sr[494]
    DIRECTION OUTPUT ;
    USE SIGNAL ;
    PORT
      LAYER M5 ;
        RECT  37.392 151.116 37.416 151.2 ;
    END
  END sr[494]
  PIN sr[495]
    DIRECTION OUTPUT ;
    USE SIGNAL ;
    PORT
      LAYER M5 ;
        RECT  37.488 151.116 37.512 151.2 ;
    END
  END sr[495]
  PIN sr[496]
    DIRECTION OUTPUT ;
    USE SIGNAL ;
    PORT
      LAYER M5 ;
        RECT  37.584 151.116 37.608 151.2 ;
    END
  END sr[496]
  PIN sr[497]
    DIRECTION OUTPUT ;
    USE SIGNAL ;
    PORT
      LAYER M5 ;
        RECT  37.68 151.116 37.704 151.2 ;
    END
  END sr[497]
  PIN sr[498]
    DIRECTION OUTPUT ;
    USE SIGNAL ;
    PORT
      LAYER M5 ;
        RECT  37.776 151.116 37.8 151.2 ;
    END
  END sr[498]
  PIN sr[499]
    DIRECTION OUTPUT ;
    USE SIGNAL ;
    PORT
      LAYER M5 ;
        RECT  37.872 151.116 37.896 151.2 ;
    END
  END sr[499]
  PIN sr[49]
    DIRECTION OUTPUT ;
    USE SIGNAL ;
    PORT
      LAYER M5 ;
        RECT  30.768 151.116 30.792 151.2 ;
    END
  END sr[49]
  PIN sr[4]
    DIRECTION OUTPUT ;
    USE SIGNAL ;
    PORT
      LAYER M5 ;
        RECT  32.592 151.116 32.616 151.2 ;
    END
  END sr[4]
  PIN sr[500]
    DIRECTION OUTPUT ;
    USE SIGNAL ;
    PORT
      LAYER M5 ;
        RECT  37.968 151.116 37.992 151.2 ;
    END
  END sr[500]
  PIN sr[501]
    DIRECTION OUTPUT ;
    USE SIGNAL ;
    PORT
      LAYER M5 ;
        RECT  38.064 151.116 38.088 151.2 ;
    END
  END sr[501]
  PIN sr[502]
    DIRECTION OUTPUT ;
    USE SIGNAL ;
    PORT
      LAYER M5 ;
        RECT  38.16 151.116 38.184 151.2 ;
    END
  END sr[502]
  PIN sr[503]
    DIRECTION OUTPUT ;
    USE SIGNAL ;
    PORT
      LAYER M5 ;
        RECT  38.256 151.116 38.28 151.2 ;
    END
  END sr[503]
  PIN sr[504]
    DIRECTION OUTPUT ;
    USE SIGNAL ;
    PORT
      LAYER M5 ;
        RECT  38.352 151.116 38.376 151.2 ;
    END
  END sr[504]
  PIN sr[505]
    DIRECTION OUTPUT ;
    USE SIGNAL ;
    PORT
      LAYER M5 ;
        RECT  38.448 151.116 38.472 151.2 ;
    END
  END sr[505]
  PIN sr[506]
    DIRECTION OUTPUT ;
    USE SIGNAL ;
    PORT
      LAYER M5 ;
        RECT  38.544 151.116 38.568 151.2 ;
    END
  END sr[506]
  PIN sr[507]
    DIRECTION OUTPUT ;
    USE SIGNAL ;
    PORT
      LAYER M5 ;
        RECT  38.64 151.116 38.664 151.2 ;
    END
  END sr[507]
  PIN sr[508]
    DIRECTION OUTPUT ;
    USE SIGNAL ;
    PORT
      LAYER M5 ;
        RECT  38.736 151.116 38.76 151.2 ;
    END
  END sr[508]
  PIN sr[509]
    DIRECTION OUTPUT ;
    USE SIGNAL ;
    PORT
      LAYER M5 ;
        RECT  38.832 151.116 38.856 151.2 ;
    END
  END sr[509]
  PIN sr[50]
    DIRECTION OUTPUT ;
    USE SIGNAL ;
    PORT
      LAYER M5 ;
        RECT  30.864 151.116 30.888 151.2 ;
    END
  END sr[50]
  PIN sr[510]
    DIRECTION OUTPUT ;
    USE SIGNAL ;
    PORT
      LAYER M5 ;
        RECT  38.928 151.116 38.952 151.2 ;
    END
  END sr[510]
  PIN sr[511]
    DIRECTION OUTPUT ;
    USE SIGNAL ;
    PORT
      LAYER M5 ;
        RECT  39.024 151.116 39.048 151.2 ;
    END
  END sr[511]
  PIN sr[51]
    DIRECTION OUTPUT ;
    USE SIGNAL ;
    PORT
      LAYER M5 ;
        RECT  30.96 151.116 30.984 151.2 ;
    END
  END sr[51]
  PIN sr[52]
    DIRECTION OUTPUT ;
    USE SIGNAL ;
    PORT
      LAYER M5 ;
        RECT  31.056 151.116 31.08 151.2 ;
    END
  END sr[52]
  PIN sr[53]
    DIRECTION OUTPUT ;
    USE SIGNAL ;
    PORT
      LAYER M5 ;
        RECT  31.152 151.116 31.176 151.2 ;
    END
  END sr[53]
  PIN sr[54]
    DIRECTION OUTPUT ;
    USE SIGNAL ;
    PORT
      LAYER M5 ;
        RECT  31.248 151.116 31.272 151.2 ;
    END
  END sr[54]
  PIN sr[55]
    DIRECTION OUTPUT ;
    USE SIGNAL ;
    PORT
      LAYER M5 ;
        RECT  31.344 151.116 31.368 151.2 ;
    END
  END sr[55]
  PIN sr[56]
    DIRECTION OUTPUT ;
    USE SIGNAL ;
    PORT
      LAYER M5 ;
        RECT  31.44 151.116 31.464 151.2 ;
    END
  END sr[56]
  PIN sr[57]
    DIRECTION OUTPUT ;
    USE SIGNAL ;
    PORT
      LAYER M5 ;
        RECT  31.536 151.116 31.56 151.2 ;
    END
  END sr[57]
  PIN sr[58]
    DIRECTION OUTPUT ;
    USE SIGNAL ;
    PORT
      LAYER M5 ;
        RECT  31.632 151.116 31.656 151.2 ;
    END
  END sr[58]
  PIN sr[59]
    DIRECTION OUTPUT ;
    USE SIGNAL ;
    PORT
      LAYER M5 ;
        RECT  31.728 151.116 31.752 151.2 ;
    END
  END sr[59]
  PIN sr[5]
    DIRECTION OUTPUT ;
    USE SIGNAL ;
    PORT
      LAYER M5 ;
        RECT  32.688 151.116 32.712 151.2 ;
    END
  END sr[5]
  PIN sr[60]
    DIRECTION OUTPUT ;
    USE SIGNAL ;
    PORT
      LAYER M5 ;
        RECT  31.824 151.116 31.848 151.2 ;
    END
  END sr[60]
  PIN sr[61]
    DIRECTION OUTPUT ;
    USE SIGNAL ;
    PORT
      LAYER M5 ;
        RECT  31.92 151.116 31.944 151.2 ;
    END
  END sr[61]
  PIN sr[62]
    DIRECTION OUTPUT ;
    USE SIGNAL ;
    PORT
      LAYER M5 ;
        RECT  32.016 151.116 32.04 151.2 ;
    END
  END sr[62]
  PIN sr[63]
    DIRECTION OUTPUT ;
    USE SIGNAL ;
    PORT
      LAYER M5 ;
        RECT  32.112 151.116 32.136 151.2 ;
    END
  END sr[63]
  PIN sr[64]
    DIRECTION OUTPUT ;
    USE SIGNAL ;
    PORT
      LAYER M5 ;
        RECT  19.92 151.116 19.944 151.2 ;
    END
  END sr[64]
  PIN sr[65]
    DIRECTION OUTPUT ;
    USE SIGNAL ;
    PORT
      LAYER M5 ;
        RECT  20.016 151.116 20.04 151.2 ;
    END
  END sr[65]
  PIN sr[66]
    DIRECTION OUTPUT ;
    USE SIGNAL ;
    PORT
      LAYER M5 ;
        RECT  20.112 151.116 20.136 151.2 ;
    END
  END sr[66]
  PIN sr[67]
    DIRECTION OUTPUT ;
    USE SIGNAL ;
    PORT
      LAYER M5 ;
        RECT  20.208 151.116 20.232 151.2 ;
    END
  END sr[67]
  PIN sr[68]
    DIRECTION OUTPUT ;
    USE SIGNAL ;
    PORT
      LAYER M5 ;
        RECT  20.304 151.116 20.328 151.2 ;
    END
  END sr[68]
  PIN sr[69]
    DIRECTION OUTPUT ;
    USE SIGNAL ;
    PORT
      LAYER M5 ;
        RECT  20.4 151.116 20.424 151.2 ;
    END
  END sr[69]
  PIN sr[6]
    DIRECTION OUTPUT ;
    USE SIGNAL ;
    PORT
      LAYER M5 ;
        RECT  32.784 151.116 32.808 151.2 ;
    END
  END sr[6]
  PIN sr[70]
    DIRECTION OUTPUT ;
    USE SIGNAL ;
    PORT
      LAYER M5 ;
        RECT  20.496 151.116 20.52 151.2 ;
    END
  END sr[70]
  PIN sr[71]
    DIRECTION OUTPUT ;
    USE SIGNAL ;
    PORT
      LAYER M5 ;
        RECT  20.592 151.116 20.616 151.2 ;
    END
  END sr[71]
  PIN sr[72]
    DIRECTION OUTPUT ;
    USE SIGNAL ;
    PORT
      LAYER M5 ;
        RECT  20.688 151.116 20.712 151.2 ;
    END
  END sr[72]
  PIN sr[73]
    DIRECTION OUTPUT ;
    USE SIGNAL ;
    PORT
      LAYER M5 ;
        RECT  20.784 151.116 20.808 151.2 ;
    END
  END sr[73]
  PIN sr[74]
    DIRECTION OUTPUT ;
    USE SIGNAL ;
    PORT
      LAYER M5 ;
        RECT  20.88 151.116 20.904 151.2 ;
    END
  END sr[74]
  PIN sr[75]
    DIRECTION OUTPUT ;
    USE SIGNAL ;
    PORT
      LAYER M5 ;
        RECT  20.976 151.116 21 151.2 ;
    END
  END sr[75]
  PIN sr[76]
    DIRECTION OUTPUT ;
    USE SIGNAL ;
    PORT
      LAYER M5 ;
        RECT  21.072 151.116 21.096 151.2 ;
    END
  END sr[76]
  PIN sr[77]
    DIRECTION OUTPUT ;
    USE SIGNAL ;
    PORT
      LAYER M5 ;
        RECT  21.168 151.116 21.192 151.2 ;
    END
  END sr[77]
  PIN sr[78]
    DIRECTION OUTPUT ;
    USE SIGNAL ;
    PORT
      LAYER M5 ;
        RECT  21.264 151.116 21.288 151.2 ;
    END
  END sr[78]
  PIN sr[79]
    DIRECTION OUTPUT ;
    USE SIGNAL ;
    PORT
      LAYER M5 ;
        RECT  21.36 151.116 21.384 151.2 ;
    END
  END sr[79]
  PIN sr[7]
    DIRECTION OUTPUT ;
    USE SIGNAL ;
    PORT
      LAYER M5 ;
        RECT  32.88 151.116 32.904 151.2 ;
    END
  END sr[7]
  PIN sr[80]
    DIRECTION OUTPUT ;
    USE SIGNAL ;
    PORT
      LAYER M5 ;
        RECT  21.456 151.116 21.48 151.2 ;
    END
  END sr[80]
  PIN sr[81]
    DIRECTION OUTPUT ;
    USE SIGNAL ;
    PORT
      LAYER M5 ;
        RECT  21.552 151.116 21.576 151.2 ;
    END
  END sr[81]
  PIN sr[82]
    DIRECTION OUTPUT ;
    USE SIGNAL ;
    PORT
      LAYER M5 ;
        RECT  21.648 151.116 21.672 151.2 ;
    END
  END sr[82]
  PIN sr[83]
    DIRECTION OUTPUT ;
    USE SIGNAL ;
    PORT
      LAYER M5 ;
        RECT  21.744 151.116 21.768 151.2 ;
    END
  END sr[83]
  PIN sr[84]
    DIRECTION OUTPUT ;
    USE SIGNAL ;
    PORT
      LAYER M5 ;
        RECT  21.84 151.116 21.864 151.2 ;
    END
  END sr[84]
  PIN sr[85]
    DIRECTION OUTPUT ;
    USE SIGNAL ;
    PORT
      LAYER M5 ;
        RECT  21.936 151.116 21.96 151.2 ;
    END
  END sr[85]
  PIN sr[86]
    DIRECTION OUTPUT ;
    USE SIGNAL ;
    PORT
      LAYER M5 ;
        RECT  22.032 151.116 22.056 151.2 ;
    END
  END sr[86]
  PIN sr[87]
    DIRECTION OUTPUT ;
    USE SIGNAL ;
    PORT
      LAYER M5 ;
        RECT  22.128 151.116 22.152 151.2 ;
    END
  END sr[87]
  PIN sr[88]
    DIRECTION OUTPUT ;
    USE SIGNAL ;
    PORT
      LAYER M5 ;
        RECT  22.224 151.116 22.248 151.2 ;
    END
  END sr[88]
  PIN sr[89]
    DIRECTION OUTPUT ;
    USE SIGNAL ;
    PORT
      LAYER M5 ;
        RECT  22.32 151.116 22.344 151.2 ;
    END
  END sr[89]
  PIN sr[8]
    DIRECTION OUTPUT ;
    USE SIGNAL ;
    PORT
      LAYER M5 ;
        RECT  32.976 151.116 33 151.2 ;
    END
  END sr[8]
  PIN sr[90]
    DIRECTION OUTPUT ;
    USE SIGNAL ;
    PORT
      LAYER M5 ;
        RECT  22.416 151.116 22.44 151.2 ;
    END
  END sr[90]
  PIN sr[91]
    DIRECTION OUTPUT ;
    USE SIGNAL ;
    PORT
      LAYER M5 ;
        RECT  22.512 151.116 22.536 151.2 ;
    END
  END sr[91]
  PIN sr[92]
    DIRECTION OUTPUT ;
    USE SIGNAL ;
    PORT
      LAYER M5 ;
        RECT  22.608 151.116 22.632 151.2 ;
    END
  END sr[92]
  PIN sr[93]
    DIRECTION OUTPUT ;
    USE SIGNAL ;
    PORT
      LAYER M5 ;
        RECT  22.704 151.116 22.728 151.2 ;
    END
  END sr[93]
  PIN sr[94]
    DIRECTION OUTPUT ;
    USE SIGNAL ;
    PORT
      LAYER M5 ;
        RECT  22.8 151.116 22.824 151.2 ;
    END
  END sr[94]
  PIN sr[95]
    DIRECTION OUTPUT ;
    USE SIGNAL ;
    PORT
      LAYER M5 ;
        RECT  22.896 151.116 22.92 151.2 ;
    END
  END sr[95]
  PIN sr[96]
    DIRECTION OUTPUT ;
    USE SIGNAL ;
    PORT
      LAYER M5 ;
        RECT  22.992 151.116 23.016 151.2 ;
    END
  END sr[96]
  PIN sr[97]
    DIRECTION OUTPUT ;
    USE SIGNAL ;
    PORT
      LAYER M5 ;
        RECT  23.088 151.116 23.112 151.2 ;
    END
  END sr[97]
  PIN sr[98]
    DIRECTION OUTPUT ;
    USE SIGNAL ;
    PORT
      LAYER M5 ;
        RECT  23.184 151.116 23.208 151.2 ;
    END
  END sr[98]
  PIN sr[99]
    DIRECTION OUTPUT ;
    USE SIGNAL ;
    PORT
      LAYER M5 ;
        RECT  23.28 151.116 23.304 151.2 ;
    END
  END sr[99]
  PIN sr[9]
    DIRECTION OUTPUT ;
    USE SIGNAL ;
    PORT
      LAYER M5 ;
        RECT  33.072 151.116 33.096 151.2 ;
    END
  END sr[9]
  PIN VDD
    DIRECTION INOUT ;
    USE POWER ;
    PORT
      LAYER M6 ;
        RECT  2.16 144.8 149.04 145.088 ;
        RECT  2.16 134 149.04 134.288 ;
        RECT  2.16 123.2 149.04 123.488 ;
        RECT  2.16 112.4 149.04 112.688 ;
        RECT  2.16 101.6 149.04 101.888 ;
        RECT  2.16 90.8 149.04 91.088 ;
        RECT  2.16 80 149.04 80.288 ;
        RECT  2.16 69.2 149.04 69.488 ;
        RECT  2.16 58.4 149.04 58.688 ;
        RECT  2.16 47.6 149.04 47.888 ;
        RECT  2.16 36.8 149.04 37.088 ;
        RECT  2.16 26 149.04 26.288 ;
        RECT  2.16 15.2 149.04 15.488 ;
        RECT  2.16 4.4 149.04 4.688 ;
    END
  END VDD
  PIN VSS
    DIRECTION INOUT ;
    USE GROUND ;
    PORT
      LAYER M6 ;
        RECT  2.16 144.416 149.04 144.704 ;
        RECT  2.16 133.616 149.04 133.904 ;
        RECT  2.16 122.816 149.04 123.104 ;
        RECT  2.16 112.016 149.04 112.304 ;
        RECT  2.16 101.216 149.04 101.504 ;
        RECT  2.16 90.416 149.04 90.704 ;
        RECT  2.16 79.616 149.04 79.904 ;
        RECT  2.16 68.816 149.04 69.104 ;
        RECT  2.16 58.016 149.04 58.304 ;
        RECT  2.16 47.216 149.04 47.504 ;
        RECT  2.16 36.416 149.04 36.704 ;
        RECT  2.16 25.616 149.04 25.904 ;
        RECT  2.16 14.816 149.04 15.104 ;
        RECT  2.16 4.016 149.04 4.304 ;
    END
  END VSS
  OBS
    LAYER RVTN ;
     RECT  2.16 2.16 149.04 2.295 ;
     RECT  2.16 2.565 149.04 2.835 ;
     RECT  2.16 3.105 149.04 3.375 ;
     RECT  2.16 3.645 149.04 3.915 ;
     RECT  2.16 4.185 149.04 4.455 ;
     RECT  2.16 4.725 149.04 4.995 ;
     RECT  2.16 5.265 149.04 5.535 ;
     RECT  2.16 5.805 149.04 6.075 ;
     RECT  2.16 6.345 149.04 6.615 ;
     RECT  2.16 6.885 149.04 7.155 ;
     RECT  2.16 7.425 149.04 7.695 ;
     RECT  2.16 7.965 149.04 8.235 ;
     RECT  2.16 8.505 149.04 8.775 ;
     RECT  2.16 9.045 149.04 9.315 ;
     RECT  2.16 9.585 149.04 9.855 ;
     RECT  2.16 10.125 149.04 10.395 ;
     RECT  2.16 10.665 149.04 10.935 ;
     RECT  2.16 11.205 149.04 11.475 ;
     RECT  2.16 11.745 149.04 12.015 ;
     RECT  2.16 12.285 149.04 12.555 ;
     RECT  2.16 12.825 149.04 13.095 ;
     RECT  2.16 13.365 149.04 13.635 ;
     RECT  2.16 13.905 149.04 14.175 ;
     RECT  2.16 14.445 149.04 14.715 ;
     RECT  2.16 14.985 149.04 15.255 ;
     RECT  2.16 15.525 149.04 15.795 ;
     RECT  2.16 16.065 149.04 16.335 ;
     RECT  2.16 16.605 149.04 16.875 ;
     RECT  2.16 17.145 149.04 17.415 ;
     RECT  2.16 17.685 149.04 17.955 ;
     RECT  2.16 18.225 149.04 18.495 ;
     RECT  2.16 18.765 149.04 19.035 ;
     RECT  2.16 19.305 149.04 19.575 ;
     RECT  2.16 19.845 149.04 20.115 ;
     RECT  2.16 20.385 149.04 20.655 ;
     RECT  2.16 20.925 149.04 21.195 ;
     RECT  2.16 21.465 149.04 21.6 ;
     RECT  2.16 21.6 26.028 21.735 ;
     RECT  124.956 21.6 149.04 21.735 ;
     RECT  2.16 22.005 26.028 22.275 ;
     RECT  124.956 22.005 149.04 22.275 ;
     RECT  2.16 22.545 26.028 22.815 ;
     RECT  124.956 22.545 149.04 22.815 ;
     RECT  2.16 23.085 26.028 23.355 ;
     RECT  124.956 23.085 149.04 23.355 ;
     RECT  2.16 23.625 26.028 23.895 ;
     RECT  124.956 23.625 149.04 23.895 ;
     RECT  2.16 24.165 26.028 24.435 ;
     RECT  124.956 24.165 149.04 24.435 ;
     RECT  2.16 24.705 26.028 24.975 ;
     RECT  124.956 24.705 149.04 24.975 ;
     RECT  2.16 25.245 26.028 25.515 ;
     RECT  124.956 25.245 149.04 25.515 ;
     RECT  2.16 25.785 26.028 26.055 ;
     RECT  124.956 25.785 149.04 26.055 ;
     RECT  2.16 26.325 26.028 26.595 ;
     RECT  124.956 26.325 149.04 26.595 ;
     RECT  2.16 26.865 26.028 27.135 ;
     RECT  124.956 26.865 149.04 27.135 ;
     RECT  2.16 27.405 26.028 27.675 ;
     RECT  124.956 27.405 149.04 27.675 ;
     RECT  2.16 27.945 26.028 28.215 ;
     RECT  124.956 27.945 149.04 28.215 ;
     RECT  2.16 28.485 26.028 28.755 ;
     RECT  124.956 28.485 149.04 28.755 ;
     RECT  2.16 29.025 26.028 29.295 ;
     RECT  124.956 29.025 149.04 29.295 ;
     RECT  2.16 29.565 26.028 29.835 ;
     RECT  124.956 29.565 149.04 29.835 ;
     RECT  2.16 30.105 26.028 30.375 ;
     RECT  124.956 30.105 149.04 30.375 ;
     RECT  2.16 30.645 26.028 30.915 ;
     RECT  124.956 30.645 149.04 30.915 ;
     RECT  2.16 31.185 26.028 31.455 ;
     RECT  124.956 31.185 149.04 31.455 ;
     RECT  2.16 31.725 26.028 31.995 ;
     RECT  124.956 31.725 149.04 31.995 ;
     RECT  2.16 32.265 26.028 32.535 ;
     RECT  124.956 32.265 149.04 32.535 ;
     RECT  2.16 32.805 26.028 33.075 ;
     RECT  124.956 32.805 149.04 33.075 ;
     RECT  2.16 33.345 26.028 33.615 ;
     RECT  124.956 33.345 149.04 33.615 ;
     RECT  2.16 33.885 26.028 34.155 ;
     RECT  124.956 33.885 149.04 34.155 ;
     RECT  2.16 34.425 26.028 34.695 ;
     RECT  124.956 34.425 149.04 34.695 ;
     RECT  2.16 34.965 26.028 35.235 ;
     RECT  124.956 34.965 149.04 35.235 ;
     RECT  2.16 35.505 26.028 35.775 ;
     RECT  124.956 35.505 149.04 35.775 ;
     RECT  2.16 36.045 26.028 36.315 ;
     RECT  124.956 36.045 149.04 36.315 ;
     RECT  2.16 36.585 26.028 36.855 ;
     RECT  124.956 36.585 149.04 36.855 ;
     RECT  2.16 37.125 26.028 37.395 ;
     RECT  124.956 37.125 149.04 37.395 ;
     RECT  2.16 37.665 26.028 37.935 ;
     RECT  124.956 37.665 149.04 37.935 ;
     RECT  2.16 38.205 26.028 38.475 ;
     RECT  124.956 38.205 149.04 38.475 ;
     RECT  2.16 38.745 26.028 39.015 ;
     RECT  124.956 38.745 149.04 39.015 ;
     RECT  2.16 39.285 26.028 39.555 ;
     RECT  124.956 39.285 149.04 39.555 ;
     RECT  2.16 39.825 26.028 40.095 ;
     RECT  124.956 39.825 149.04 40.095 ;
     RECT  2.16 40.365 26.028 40.635 ;
     RECT  124.956 40.365 149.04 40.635 ;
     RECT  2.16 40.905 26.028 41.175 ;
     RECT  124.956 40.905 149.04 41.175 ;
     RECT  2.16 41.445 26.028 41.715 ;
     RECT  124.956 41.445 149.04 41.715 ;
     RECT  2.16 41.985 26.028 42.255 ;
     RECT  124.956 41.985 149.04 42.255 ;
     RECT  2.16 42.525 26.028 42.795 ;
     RECT  124.956 42.525 149.04 42.795 ;
     RECT  2.16 43.065 26.028 43.335 ;
     RECT  124.956 43.065 149.04 43.335 ;
     RECT  2.16 43.605 26.028 43.875 ;
     RECT  124.956 43.605 149.04 43.875 ;
     RECT  2.16 44.145 26.028 44.415 ;
     RECT  124.956 44.145 149.04 44.415 ;
     RECT  2.16 44.685 26.028 44.955 ;
     RECT  124.956 44.685 149.04 44.955 ;
     RECT  2.16 45.225 26.028 45.495 ;
     RECT  124.956 45.225 149.04 45.495 ;
     RECT  2.16 45.765 26.028 46.035 ;
     RECT  124.956 45.765 149.04 46.035 ;
     RECT  2.16 46.305 26.028 46.575 ;
     RECT  124.956 46.305 149.04 46.575 ;
     RECT  2.16 46.845 26.028 47.115 ;
     RECT  124.956 46.845 149.04 47.115 ;
     RECT  2.16 47.385 26.028 47.655 ;
     RECT  124.956 47.385 149.04 47.655 ;
     RECT  2.16 47.925 26.028 48.195 ;
     RECT  124.956 47.925 149.04 48.195 ;
     RECT  2.16 48.465 26.028 48.735 ;
     RECT  124.956 48.465 149.04 48.735 ;
     RECT  2.16 49.005 26.028 49.275 ;
     RECT  124.956 49.005 149.04 49.275 ;
     RECT  2.16 49.545 26.028 49.815 ;
     RECT  124.956 49.545 149.04 49.815 ;
     RECT  2.16 50.085 26.028 50.355 ;
     RECT  124.956 50.085 149.04 50.355 ;
     RECT  2.16 50.625 26.028 50.895 ;
     RECT  124.956 50.625 149.04 50.895 ;
     RECT  2.16 51.165 26.028 51.435 ;
     RECT  124.956 51.165 149.04 51.435 ;
     RECT  2.16 51.705 26.028 51.975 ;
     RECT  124.956 51.705 149.04 51.975 ;
     RECT  2.16 52.245 26.028 52.515 ;
     RECT  124.956 52.245 149.04 52.515 ;
     RECT  2.16 52.785 26.028 53.055 ;
     RECT  124.956 52.785 149.04 53.055 ;
     RECT  2.16 53.325 26.028 53.595 ;
     RECT  124.956 53.325 149.04 53.595 ;
     RECT  2.16 53.865 26.028 54.135 ;
     RECT  124.956 53.865 149.04 54.135 ;
     RECT  2.16 54.405 26.028 54.675 ;
     RECT  124.956 54.405 149.04 54.675 ;
     RECT  2.16 54.945 26.028 55.215 ;
     RECT  124.956 54.945 149.04 55.215 ;
     RECT  2.16 55.485 26.028 55.755 ;
     RECT  124.956 55.485 149.04 55.755 ;
     RECT  2.16 56.025 26.028 56.295 ;
     RECT  124.956 56.025 149.04 56.295 ;
     RECT  2.16 56.565 26.028 56.835 ;
     RECT  124.956 56.565 149.04 56.835 ;
     RECT  2.16 57.105 26.028 57.375 ;
     RECT  124.956 57.105 149.04 57.375 ;
     RECT  2.16 57.645 26.028 57.915 ;
     RECT  124.956 57.645 149.04 57.915 ;
     RECT  2.16 58.185 26.028 58.455 ;
     RECT  124.956 58.185 149.04 58.455 ;
     RECT  2.16 58.725 26.028 58.995 ;
     RECT  124.956 58.725 149.04 58.995 ;
     RECT  2.16 59.265 26.028 59.535 ;
     RECT  124.956 59.265 149.04 59.535 ;
     RECT  2.16 59.805 26.028 60.075 ;
     RECT  124.956 59.805 149.04 60.075 ;
     RECT  2.16 60.345 26.028 60.615 ;
     RECT  124.956 60.345 149.04 60.615 ;
     RECT  2.16 60.885 26.028 61.155 ;
     RECT  124.956 60.885 149.04 61.155 ;
     RECT  2.16 61.425 26.028 61.695 ;
     RECT  124.956 61.425 149.04 61.695 ;
     RECT  2.16 61.965 26.028 62.235 ;
     RECT  124.956 61.965 149.04 62.235 ;
     RECT  2.16 62.505 26.028 62.775 ;
     RECT  124.956 62.505 149.04 62.775 ;
     RECT  2.16 63.045 26.028 63.315 ;
     RECT  124.956 63.045 149.04 63.315 ;
     RECT  2.16 63.585 26.028 63.855 ;
     RECT  124.956 63.585 149.04 63.855 ;
     RECT  2.16 64.125 26.028 64.395 ;
     RECT  124.956 64.125 149.04 64.395 ;
     RECT  2.16 64.665 26.028 64.935 ;
     RECT  124.956 64.665 149.04 64.935 ;
     RECT  2.16 65.205 26.028 65.475 ;
     RECT  124.956 65.205 149.04 65.475 ;
     RECT  2.16 65.745 26.028 66.015 ;
     RECT  124.956 65.745 149.04 66.015 ;
     RECT  2.16 66.285 26.028 66.555 ;
     RECT  124.956 66.285 149.04 66.555 ;
     RECT  2.16 66.825 26.028 66.96 ;
     RECT  124.956 66.825 149.04 66.96 ;
     RECT  2.16 66.96 149.04 67.095 ;
     RECT  2.16 67.365 149.04 67.635 ;
     RECT  2.16 67.905 149.04 68.175 ;
     RECT  2.16 68.445 149.04 68.715 ;
     RECT  2.16 68.985 149.04 69.255 ;
     RECT  2.16 69.525 149.04 69.795 ;
     RECT  2.16 70.065 149.04 70.335 ;
     RECT  2.16 70.605 149.04 70.875 ;
     RECT  2.16 71.145 149.04 71.415 ;
     RECT  2.16 71.685 149.04 71.955 ;
     RECT  2.16 72.225 149.04 72.495 ;
     RECT  2.16 72.765 149.04 73.035 ;
     RECT  2.16 73.305 149.04 73.575 ;
     RECT  2.16 73.845 149.04 74.115 ;
     RECT  2.16 74.385 149.04 74.655 ;
     RECT  2.16 74.925 149.04 75.195 ;
     RECT  2.16 75.465 149.04 75.735 ;
     RECT  2.16 76.005 149.04 76.275 ;
     RECT  2.16 76.545 149.04 76.815 ;
     RECT  2.16 77.085 149.04 77.355 ;
     RECT  2.16 77.625 149.04 77.895 ;
     RECT  2.16 78.165 149.04 78.435 ;
     RECT  2.16 78.705 149.04 78.975 ;
     RECT  2.16 79.245 149.04 79.515 ;
     RECT  2.16 79.785 149.04 80.055 ;
     RECT  2.16 80.325 149.04 80.595 ;
     RECT  2.16 80.865 149.04 81.135 ;
     RECT  2.16 81.405 149.04 81.675 ;
     RECT  2.16 81.945 149.04 82.215 ;
     RECT  2.16 82.485 149.04 82.755 ;
     RECT  2.16 83.025 149.04 83.295 ;
     RECT  2.16 83.565 149.04 83.835 ;
     RECT  2.16 84.105 149.04 84.24 ;
     RECT  2.16 84.24 26.028 84.375 ;
     RECT  124.956 84.24 149.04 84.375 ;
     RECT  2.16 84.645 26.028 84.915 ;
     RECT  124.956 84.645 149.04 84.915 ;
     RECT  2.16 85.185 26.028 85.455 ;
     RECT  124.956 85.185 149.04 85.455 ;
     RECT  2.16 85.725 26.028 85.995 ;
     RECT  124.956 85.725 149.04 85.995 ;
     RECT  2.16 86.265 26.028 86.535 ;
     RECT  124.956 86.265 149.04 86.535 ;
     RECT  2.16 86.805 26.028 87.075 ;
     RECT  124.956 86.805 149.04 87.075 ;
     RECT  2.16 87.345 26.028 87.615 ;
     RECT  124.956 87.345 149.04 87.615 ;
     RECT  2.16 87.885 26.028 88.155 ;
     RECT  124.956 87.885 149.04 88.155 ;
     RECT  2.16 88.425 26.028 88.695 ;
     RECT  124.956 88.425 149.04 88.695 ;
     RECT  2.16 88.965 26.028 89.235 ;
     RECT  124.956 88.965 149.04 89.235 ;
     RECT  2.16 89.505 26.028 89.775 ;
     RECT  124.956 89.505 149.04 89.775 ;
     RECT  2.16 90.045 26.028 90.315 ;
     RECT  124.956 90.045 149.04 90.315 ;
     RECT  2.16 90.585 26.028 90.855 ;
     RECT  124.956 90.585 149.04 90.855 ;
     RECT  2.16 91.125 26.028 91.395 ;
     RECT  124.956 91.125 149.04 91.395 ;
     RECT  2.16 91.665 26.028 91.935 ;
     RECT  124.956 91.665 149.04 91.935 ;
     RECT  2.16 92.205 26.028 92.475 ;
     RECT  124.956 92.205 149.04 92.475 ;
     RECT  2.16 92.745 26.028 93.015 ;
     RECT  124.956 92.745 149.04 93.015 ;
     RECT  2.16 93.285 26.028 93.555 ;
     RECT  124.956 93.285 149.04 93.555 ;
     RECT  2.16 93.825 26.028 94.095 ;
     RECT  124.956 93.825 149.04 94.095 ;
     RECT  2.16 94.365 26.028 94.635 ;
     RECT  124.956 94.365 149.04 94.635 ;
     RECT  2.16 94.905 26.028 95.175 ;
     RECT  124.956 94.905 149.04 95.175 ;
     RECT  2.16 95.445 26.028 95.715 ;
     RECT  124.956 95.445 149.04 95.715 ;
     RECT  2.16 95.985 26.028 96.255 ;
     RECT  124.956 95.985 149.04 96.255 ;
     RECT  2.16 96.525 26.028 96.795 ;
     RECT  124.956 96.525 149.04 96.795 ;
     RECT  2.16 97.065 26.028 97.335 ;
     RECT  124.956 97.065 149.04 97.335 ;
     RECT  2.16 97.605 26.028 97.875 ;
     RECT  124.956 97.605 149.04 97.875 ;
     RECT  2.16 98.145 26.028 98.415 ;
     RECT  124.956 98.145 149.04 98.415 ;
     RECT  2.16 98.685 26.028 98.955 ;
     RECT  124.956 98.685 149.04 98.955 ;
     RECT  2.16 99.225 26.028 99.495 ;
     RECT  124.956 99.225 149.04 99.495 ;
     RECT  2.16 99.765 26.028 100.035 ;
     RECT  124.956 99.765 149.04 100.035 ;
     RECT  2.16 100.305 26.028 100.575 ;
     RECT  124.956 100.305 149.04 100.575 ;
     RECT  2.16 100.845 26.028 101.115 ;
     RECT  124.956 100.845 149.04 101.115 ;
     RECT  2.16 101.385 26.028 101.655 ;
     RECT  124.956 101.385 149.04 101.655 ;
     RECT  2.16 101.925 26.028 102.195 ;
     RECT  124.956 101.925 149.04 102.195 ;
     RECT  2.16 102.465 26.028 102.735 ;
     RECT  124.956 102.465 149.04 102.735 ;
     RECT  2.16 103.005 26.028 103.275 ;
     RECT  124.956 103.005 149.04 103.275 ;
     RECT  2.16 103.545 26.028 103.815 ;
     RECT  124.956 103.545 149.04 103.815 ;
     RECT  2.16 104.085 26.028 104.355 ;
     RECT  124.956 104.085 149.04 104.355 ;
     RECT  2.16 104.625 26.028 104.895 ;
     RECT  124.956 104.625 149.04 104.895 ;
     RECT  2.16 105.165 26.028 105.435 ;
     RECT  124.956 105.165 149.04 105.435 ;
     RECT  2.16 105.705 26.028 105.975 ;
     RECT  124.956 105.705 149.04 105.975 ;
     RECT  2.16 106.245 26.028 106.515 ;
     RECT  124.956 106.245 149.04 106.515 ;
     RECT  2.16 106.785 26.028 107.055 ;
     RECT  124.956 106.785 149.04 107.055 ;
     RECT  2.16 107.325 26.028 107.595 ;
     RECT  124.956 107.325 149.04 107.595 ;
     RECT  2.16 107.865 26.028 108.135 ;
     RECT  124.956 107.865 149.04 108.135 ;
     RECT  2.16 108.405 26.028 108.675 ;
     RECT  124.956 108.405 149.04 108.675 ;
     RECT  2.16 108.945 26.028 109.215 ;
     RECT  124.956 108.945 149.04 109.215 ;
     RECT  2.16 109.485 26.028 109.755 ;
     RECT  124.956 109.485 149.04 109.755 ;
     RECT  2.16 110.025 26.028 110.295 ;
     RECT  124.956 110.025 149.04 110.295 ;
     RECT  2.16 110.565 26.028 110.835 ;
     RECT  124.956 110.565 149.04 110.835 ;
     RECT  2.16 111.105 26.028 111.375 ;
     RECT  124.956 111.105 149.04 111.375 ;
     RECT  2.16 111.645 26.028 111.915 ;
     RECT  124.956 111.645 149.04 111.915 ;
     RECT  2.16 112.185 26.028 112.455 ;
     RECT  124.956 112.185 149.04 112.455 ;
     RECT  2.16 112.725 26.028 112.995 ;
     RECT  124.956 112.725 149.04 112.995 ;
     RECT  2.16 113.265 26.028 113.535 ;
     RECT  124.956 113.265 149.04 113.535 ;
     RECT  2.16 113.805 26.028 114.075 ;
     RECT  124.956 113.805 149.04 114.075 ;
     RECT  2.16 114.345 26.028 114.615 ;
     RECT  124.956 114.345 149.04 114.615 ;
     RECT  2.16 114.885 26.028 115.155 ;
     RECT  124.956 114.885 149.04 115.155 ;
     RECT  2.16 115.425 26.028 115.695 ;
     RECT  124.956 115.425 149.04 115.695 ;
     RECT  2.16 115.965 26.028 116.235 ;
     RECT  124.956 115.965 149.04 116.235 ;
     RECT  2.16 116.505 26.028 116.775 ;
     RECT  124.956 116.505 149.04 116.775 ;
     RECT  2.16 117.045 26.028 117.315 ;
     RECT  124.956 117.045 149.04 117.315 ;
     RECT  2.16 117.585 26.028 117.855 ;
     RECT  124.956 117.585 149.04 117.855 ;
     RECT  2.16 118.125 26.028 118.395 ;
     RECT  124.956 118.125 149.04 118.395 ;
     RECT  2.16 118.665 26.028 118.935 ;
     RECT  124.956 118.665 149.04 118.935 ;
     RECT  2.16 119.205 26.028 119.475 ;
     RECT  124.956 119.205 149.04 119.475 ;
     RECT  2.16 119.745 26.028 120.015 ;
     RECT  124.956 119.745 149.04 120.015 ;
     RECT  2.16 120.285 26.028 120.555 ;
     RECT  124.956 120.285 149.04 120.555 ;
     RECT  2.16 120.825 26.028 121.095 ;
     RECT  124.956 120.825 149.04 121.095 ;
     RECT  2.16 121.365 26.028 121.635 ;
     RECT  124.956 121.365 149.04 121.635 ;
     RECT  2.16 121.905 26.028 122.175 ;
     RECT  124.956 121.905 149.04 122.175 ;
     RECT  2.16 122.445 26.028 122.715 ;
     RECT  124.956 122.445 149.04 122.715 ;
     RECT  2.16 122.985 26.028 123.255 ;
     RECT  124.956 122.985 149.04 123.255 ;
     RECT  2.16 123.525 26.028 123.795 ;
     RECT  124.956 123.525 149.04 123.795 ;
     RECT  2.16 124.065 26.028 124.335 ;
     RECT  124.956 124.065 149.04 124.335 ;
     RECT  2.16 124.605 26.028 124.875 ;
     RECT  124.956 124.605 149.04 124.875 ;
     RECT  2.16 125.145 26.028 125.415 ;
     RECT  124.956 125.145 149.04 125.415 ;
     RECT  2.16 125.685 26.028 125.955 ;
     RECT  124.956 125.685 149.04 125.955 ;
     RECT  2.16 126.225 26.028 126.495 ;
     RECT  124.956 126.225 149.04 126.495 ;
     RECT  2.16 126.765 26.028 127.035 ;
     RECT  124.956 126.765 149.04 127.035 ;
     RECT  2.16 127.305 26.028 127.575 ;
     RECT  124.956 127.305 149.04 127.575 ;
     RECT  2.16 127.845 26.028 128.115 ;
     RECT  124.956 127.845 149.04 128.115 ;
     RECT  2.16 128.385 26.028 128.655 ;
     RECT  124.956 128.385 149.04 128.655 ;
     RECT  2.16 128.925 26.028 129.195 ;
     RECT  124.956 128.925 149.04 129.195 ;
     RECT  2.16 129.465 26.028 129.6 ;
     RECT  124.956 129.465 149.04 129.6 ;
     RECT  2.16 129.6 149.04 129.735 ;
     RECT  2.16 130.005 149.04 130.275 ;
     RECT  2.16 130.545 149.04 130.815 ;
     RECT  2.16 131.085 149.04 131.355 ;
     RECT  2.16 131.625 149.04 131.895 ;
     RECT  2.16 132.165 149.04 132.435 ;
     RECT  2.16 132.705 149.04 132.975 ;
     RECT  2.16 133.245 149.04 133.515 ;
     RECT  2.16 133.785 149.04 134.055 ;
     RECT  2.16 134.325 149.04 134.595 ;
     RECT  2.16 134.865 149.04 135.135 ;
     RECT  2.16 135.405 149.04 135.675 ;
     RECT  2.16 135.945 149.04 136.215 ;
     RECT  2.16 136.485 149.04 136.755 ;
     RECT  2.16 137.025 149.04 137.295 ;
     RECT  2.16 137.565 149.04 137.835 ;
     RECT  2.16 138.105 149.04 138.375 ;
     RECT  2.16 138.645 149.04 138.915 ;
     RECT  2.16 139.185 149.04 139.455 ;
     RECT  2.16 139.725 149.04 139.995 ;
     RECT  2.16 140.265 149.04 140.535 ;
     RECT  2.16 140.805 149.04 141.075 ;
     RECT  2.16 141.345 149.04 141.615 ;
     RECT  2.16 141.885 149.04 142.155 ;
     RECT  2.16 142.425 149.04 142.695 ;
     RECT  2.16 142.965 149.04 143.235 ;
     RECT  2.16 143.505 149.04 143.775 ;
     RECT  2.16 144.045 149.04 144.315 ;
     RECT  2.16 144.585 149.04 144.855 ;
     RECT  2.16 145.125 149.04 145.395 ;
     RECT  2.16 145.665 149.04 145.935 ;
     RECT  2.16 146.205 149.04 146.475 ;
     RECT  2.16 146.745 149.04 147.015 ;
     RECT  2.16 147.285 149.04 147.555 ;
     RECT  2.16 147.825 149.04 148.095 ;
     RECT  2.16 148.365 149.04 148.635 ;
     RECT  2.16 148.905 149.04 149.04 ;
    LAYER RVTP ;
     RECT  2.16 2.295 149.04 2.565 ;
     RECT  2.16 2.835 149.04 3.105 ;
     RECT  2.16 3.375 149.04 3.645 ;
     RECT  2.16 3.915 149.04 4.185 ;
     RECT  2.16 4.455 149.04 4.725 ;
     RECT  2.16 4.995 149.04 5.265 ;
     RECT  2.16 5.535 149.04 5.805 ;
     RECT  2.16 6.075 149.04 6.345 ;
     RECT  2.16 6.615 149.04 6.885 ;
     RECT  2.16 7.155 149.04 7.425 ;
     RECT  2.16 7.695 149.04 7.965 ;
     RECT  2.16 8.235 149.04 8.505 ;
     RECT  2.16 8.775 149.04 9.045 ;
     RECT  2.16 9.315 149.04 9.585 ;
     RECT  2.16 9.855 149.04 10.125 ;
     RECT  2.16 10.395 149.04 10.665 ;
     RECT  2.16 10.935 149.04 11.205 ;
     RECT  2.16 11.475 149.04 11.745 ;
     RECT  2.16 12.015 149.04 12.285 ;
     RECT  2.16 12.555 149.04 12.825 ;
     RECT  2.16 13.095 149.04 13.365 ;
     RECT  2.16 13.635 149.04 13.905 ;
     RECT  2.16 14.175 149.04 14.445 ;
     RECT  2.16 14.715 149.04 14.985 ;
     RECT  2.16 15.255 149.04 15.525 ;
     RECT  2.16 15.795 149.04 16.065 ;
     RECT  2.16 16.335 149.04 16.605 ;
     RECT  2.16 16.875 149.04 17.145 ;
     RECT  2.16 17.415 149.04 17.685 ;
     RECT  2.16 17.955 149.04 18.225 ;
     RECT  2.16 18.495 149.04 18.765 ;
     RECT  2.16 19.035 149.04 19.305 ;
     RECT  2.16 19.575 149.04 19.845 ;
     RECT  2.16 20.115 149.04 20.385 ;
     RECT  2.16 20.655 149.04 20.925 ;
     RECT  2.16 21.195 149.04 21.465 ;
     RECT  2.16 21.735 26.028 22.005 ;
     RECT  124.956 21.735 149.04 22.005 ;
     RECT  2.16 22.275 26.028 22.545 ;
     RECT  124.956 22.275 149.04 22.545 ;
     RECT  2.16 22.815 26.028 23.085 ;
     RECT  124.956 22.815 149.04 23.085 ;
     RECT  2.16 23.355 26.028 23.625 ;
     RECT  124.956 23.355 149.04 23.625 ;
     RECT  2.16 23.895 26.028 24.165 ;
     RECT  124.956 23.895 149.04 24.165 ;
     RECT  2.16 24.435 26.028 24.705 ;
     RECT  124.956 24.435 149.04 24.705 ;
     RECT  2.16 24.975 26.028 25.245 ;
     RECT  124.956 24.975 149.04 25.245 ;
     RECT  2.16 25.515 26.028 25.785 ;
     RECT  124.956 25.515 149.04 25.785 ;
     RECT  2.16 26.055 26.028 26.325 ;
     RECT  124.956 26.055 149.04 26.325 ;
     RECT  2.16 26.595 26.028 26.865 ;
     RECT  124.956 26.595 149.04 26.865 ;
     RECT  2.16 27.135 26.028 27.405 ;
     RECT  124.956 27.135 149.04 27.405 ;
     RECT  2.16 27.675 26.028 27.945 ;
     RECT  124.956 27.675 149.04 27.945 ;
     RECT  2.16 28.215 26.028 28.485 ;
     RECT  124.956 28.215 149.04 28.485 ;
     RECT  2.16 28.755 26.028 29.025 ;
     RECT  124.956 28.755 149.04 29.025 ;
     RECT  2.16 29.295 26.028 29.565 ;
     RECT  124.956 29.295 149.04 29.565 ;
     RECT  2.16 29.835 26.028 30.105 ;
     RECT  124.956 29.835 149.04 30.105 ;
     RECT  2.16 30.375 26.028 30.645 ;
     RECT  124.956 30.375 149.04 30.645 ;
     RECT  2.16 30.915 26.028 31.185 ;
     RECT  124.956 30.915 149.04 31.185 ;
     RECT  2.16 31.455 26.028 31.725 ;
     RECT  124.956 31.455 149.04 31.725 ;
     RECT  2.16 31.995 26.028 32.265 ;
     RECT  124.956 31.995 149.04 32.265 ;
     RECT  2.16 32.535 26.028 32.805 ;
     RECT  124.956 32.535 149.04 32.805 ;
     RECT  2.16 33.075 26.028 33.345 ;
     RECT  124.956 33.075 149.04 33.345 ;
     RECT  2.16 33.615 26.028 33.885 ;
     RECT  124.956 33.615 149.04 33.885 ;
     RECT  2.16 34.155 26.028 34.425 ;
     RECT  124.956 34.155 149.04 34.425 ;
     RECT  2.16 34.695 26.028 34.965 ;
     RECT  124.956 34.695 149.04 34.965 ;
     RECT  2.16 35.235 26.028 35.505 ;
     RECT  124.956 35.235 149.04 35.505 ;
     RECT  2.16 35.775 26.028 36.045 ;
     RECT  124.956 35.775 149.04 36.045 ;
     RECT  2.16 36.315 26.028 36.585 ;
     RECT  124.956 36.315 149.04 36.585 ;
     RECT  2.16 36.855 26.028 37.125 ;
     RECT  124.956 36.855 149.04 37.125 ;
     RECT  2.16 37.395 26.028 37.665 ;
     RECT  124.956 37.395 149.04 37.665 ;
     RECT  2.16 37.935 26.028 38.205 ;
     RECT  124.956 37.935 149.04 38.205 ;
     RECT  2.16 38.475 26.028 38.745 ;
     RECT  124.956 38.475 149.04 38.745 ;
     RECT  2.16 39.015 26.028 39.285 ;
     RECT  124.956 39.015 149.04 39.285 ;
     RECT  2.16 39.555 26.028 39.825 ;
     RECT  124.956 39.555 149.04 39.825 ;
     RECT  2.16 40.095 26.028 40.365 ;
     RECT  124.956 40.095 149.04 40.365 ;
     RECT  2.16 40.635 26.028 40.905 ;
     RECT  124.956 40.635 149.04 40.905 ;
     RECT  2.16 41.175 26.028 41.445 ;
     RECT  124.956 41.175 149.04 41.445 ;
     RECT  2.16 41.715 26.028 41.985 ;
     RECT  124.956 41.715 149.04 41.985 ;
     RECT  2.16 42.255 26.028 42.525 ;
     RECT  124.956 42.255 149.04 42.525 ;
     RECT  2.16 42.795 26.028 43.065 ;
     RECT  124.956 42.795 149.04 43.065 ;
     RECT  2.16 43.335 26.028 43.605 ;
     RECT  124.956 43.335 149.04 43.605 ;
     RECT  2.16 43.875 26.028 44.145 ;
     RECT  124.956 43.875 149.04 44.145 ;
     RECT  2.16 44.415 26.028 44.685 ;
     RECT  124.956 44.415 149.04 44.685 ;
     RECT  2.16 44.955 26.028 45.225 ;
     RECT  124.956 44.955 149.04 45.225 ;
     RECT  2.16 45.495 26.028 45.765 ;
     RECT  124.956 45.495 149.04 45.765 ;
     RECT  2.16 46.035 26.028 46.305 ;
     RECT  124.956 46.035 149.04 46.305 ;
     RECT  2.16 46.575 26.028 46.845 ;
     RECT  124.956 46.575 149.04 46.845 ;
     RECT  2.16 47.115 26.028 47.385 ;
     RECT  124.956 47.115 149.04 47.385 ;
     RECT  2.16 47.655 26.028 47.925 ;
     RECT  124.956 47.655 149.04 47.925 ;
     RECT  2.16 48.195 26.028 48.465 ;
     RECT  124.956 48.195 149.04 48.465 ;
     RECT  2.16 48.735 26.028 49.005 ;
     RECT  124.956 48.735 149.04 49.005 ;
     RECT  2.16 49.275 26.028 49.545 ;
     RECT  124.956 49.275 149.04 49.545 ;
     RECT  2.16 49.815 26.028 50.085 ;
     RECT  124.956 49.815 149.04 50.085 ;
     RECT  2.16 50.355 26.028 50.625 ;
     RECT  124.956 50.355 149.04 50.625 ;
     RECT  2.16 50.895 26.028 51.165 ;
     RECT  124.956 50.895 149.04 51.165 ;
     RECT  2.16 51.435 26.028 51.705 ;
     RECT  124.956 51.435 149.04 51.705 ;
     RECT  2.16 51.975 26.028 52.245 ;
     RECT  124.956 51.975 149.04 52.245 ;
     RECT  2.16 52.515 26.028 52.785 ;
     RECT  124.956 52.515 149.04 52.785 ;
     RECT  2.16 53.055 26.028 53.325 ;
     RECT  124.956 53.055 149.04 53.325 ;
     RECT  2.16 53.595 26.028 53.865 ;
     RECT  124.956 53.595 149.04 53.865 ;
     RECT  2.16 54.135 26.028 54.405 ;
     RECT  124.956 54.135 149.04 54.405 ;
     RECT  2.16 54.675 26.028 54.945 ;
     RECT  124.956 54.675 149.04 54.945 ;
     RECT  2.16 55.215 26.028 55.485 ;
     RECT  124.956 55.215 149.04 55.485 ;
     RECT  2.16 55.755 26.028 56.025 ;
     RECT  124.956 55.755 149.04 56.025 ;
     RECT  2.16 56.295 26.028 56.565 ;
     RECT  124.956 56.295 149.04 56.565 ;
     RECT  2.16 56.835 26.028 57.105 ;
     RECT  124.956 56.835 149.04 57.105 ;
     RECT  2.16 57.375 26.028 57.645 ;
     RECT  124.956 57.375 149.04 57.645 ;
     RECT  2.16 57.915 26.028 58.185 ;
     RECT  124.956 57.915 149.04 58.185 ;
     RECT  2.16 58.455 26.028 58.725 ;
     RECT  124.956 58.455 149.04 58.725 ;
     RECT  2.16 58.995 26.028 59.265 ;
     RECT  124.956 58.995 149.04 59.265 ;
     RECT  2.16 59.535 26.028 59.805 ;
     RECT  124.956 59.535 149.04 59.805 ;
     RECT  2.16 60.075 26.028 60.345 ;
     RECT  124.956 60.075 149.04 60.345 ;
     RECT  2.16 60.615 26.028 60.885 ;
     RECT  124.956 60.615 149.04 60.885 ;
     RECT  2.16 61.155 26.028 61.425 ;
     RECT  124.956 61.155 149.04 61.425 ;
     RECT  2.16 61.695 26.028 61.965 ;
     RECT  124.956 61.695 149.04 61.965 ;
     RECT  2.16 62.235 26.028 62.505 ;
     RECT  124.956 62.235 149.04 62.505 ;
     RECT  2.16 62.775 26.028 63.045 ;
     RECT  124.956 62.775 149.04 63.045 ;
     RECT  2.16 63.315 26.028 63.585 ;
     RECT  124.956 63.315 149.04 63.585 ;
     RECT  2.16 63.855 26.028 64.125 ;
     RECT  124.956 63.855 149.04 64.125 ;
     RECT  2.16 64.395 26.028 64.665 ;
     RECT  124.956 64.395 149.04 64.665 ;
     RECT  2.16 64.935 26.028 65.205 ;
     RECT  124.956 64.935 149.04 65.205 ;
     RECT  2.16 65.475 26.028 65.745 ;
     RECT  124.956 65.475 149.04 65.745 ;
     RECT  2.16 66.015 26.028 66.285 ;
     RECT  124.956 66.015 149.04 66.285 ;
     RECT  2.16 66.555 26.028 66.825 ;
     RECT  124.956 66.555 149.04 66.825 ;
     RECT  2.16 67.095 149.04 67.365 ;
     RECT  2.16 67.635 149.04 67.905 ;
     RECT  2.16 68.175 149.04 68.445 ;
     RECT  2.16 68.715 149.04 68.985 ;
     RECT  2.16 69.255 149.04 69.525 ;
     RECT  2.16 69.795 149.04 70.065 ;
     RECT  2.16 70.335 149.04 70.605 ;
     RECT  2.16 70.875 149.04 71.145 ;
     RECT  2.16 71.415 149.04 71.685 ;
     RECT  2.16 71.955 149.04 72.225 ;
     RECT  2.16 72.495 149.04 72.765 ;
     RECT  2.16 73.035 149.04 73.305 ;
     RECT  2.16 73.575 149.04 73.845 ;
     RECT  2.16 74.115 149.04 74.385 ;
     RECT  2.16 74.655 149.04 74.925 ;
     RECT  2.16 75.195 149.04 75.465 ;
     RECT  2.16 75.735 149.04 76.005 ;
     RECT  2.16 76.275 149.04 76.545 ;
     RECT  2.16 76.815 149.04 77.085 ;
     RECT  2.16 77.355 149.04 77.625 ;
     RECT  2.16 77.895 149.04 78.165 ;
     RECT  2.16 78.435 149.04 78.705 ;
     RECT  2.16 78.975 149.04 79.245 ;
     RECT  2.16 79.515 149.04 79.785 ;
     RECT  2.16 80.055 149.04 80.325 ;
     RECT  2.16 80.595 149.04 80.865 ;
     RECT  2.16 81.135 149.04 81.405 ;
     RECT  2.16 81.675 149.04 81.945 ;
     RECT  2.16 82.215 149.04 82.485 ;
     RECT  2.16 82.755 149.04 83.025 ;
     RECT  2.16 83.295 149.04 83.565 ;
     RECT  2.16 83.835 149.04 84.105 ;
     RECT  2.16 84.375 26.028 84.645 ;
     RECT  124.956 84.375 149.04 84.645 ;
     RECT  2.16 84.915 26.028 85.185 ;
     RECT  124.956 84.915 149.04 85.185 ;
     RECT  2.16 85.455 26.028 85.725 ;
     RECT  124.956 85.455 149.04 85.725 ;
     RECT  2.16 85.995 26.028 86.265 ;
     RECT  124.956 85.995 149.04 86.265 ;
     RECT  2.16 86.535 26.028 86.805 ;
     RECT  124.956 86.535 149.04 86.805 ;
     RECT  2.16 87.075 26.028 87.345 ;
     RECT  124.956 87.075 149.04 87.345 ;
     RECT  2.16 87.615 26.028 87.885 ;
     RECT  124.956 87.615 149.04 87.885 ;
     RECT  2.16 88.155 26.028 88.425 ;
     RECT  124.956 88.155 149.04 88.425 ;
     RECT  2.16 88.695 26.028 88.965 ;
     RECT  124.956 88.695 149.04 88.965 ;
     RECT  2.16 89.235 26.028 89.505 ;
     RECT  124.956 89.235 149.04 89.505 ;
     RECT  2.16 89.775 26.028 90.045 ;
     RECT  124.956 89.775 149.04 90.045 ;
     RECT  2.16 90.315 26.028 90.585 ;
     RECT  124.956 90.315 149.04 90.585 ;
     RECT  2.16 90.855 26.028 91.125 ;
     RECT  124.956 90.855 149.04 91.125 ;
     RECT  2.16 91.395 26.028 91.665 ;
     RECT  124.956 91.395 149.04 91.665 ;
     RECT  2.16 91.935 26.028 92.205 ;
     RECT  124.956 91.935 149.04 92.205 ;
     RECT  2.16 92.475 26.028 92.745 ;
     RECT  124.956 92.475 149.04 92.745 ;
     RECT  2.16 93.015 26.028 93.285 ;
     RECT  124.956 93.015 149.04 93.285 ;
     RECT  2.16 93.555 26.028 93.825 ;
     RECT  124.956 93.555 149.04 93.825 ;
     RECT  2.16 94.095 26.028 94.365 ;
     RECT  124.956 94.095 149.04 94.365 ;
     RECT  2.16 94.635 26.028 94.905 ;
     RECT  124.956 94.635 149.04 94.905 ;
     RECT  2.16 95.175 26.028 95.445 ;
     RECT  124.956 95.175 149.04 95.445 ;
     RECT  2.16 95.715 26.028 95.985 ;
     RECT  124.956 95.715 149.04 95.985 ;
     RECT  2.16 96.255 26.028 96.525 ;
     RECT  124.956 96.255 149.04 96.525 ;
     RECT  2.16 96.795 26.028 97.065 ;
     RECT  124.956 96.795 149.04 97.065 ;
     RECT  2.16 97.335 26.028 97.605 ;
     RECT  124.956 97.335 149.04 97.605 ;
     RECT  2.16 97.875 26.028 98.145 ;
     RECT  124.956 97.875 149.04 98.145 ;
     RECT  2.16 98.415 26.028 98.685 ;
     RECT  124.956 98.415 149.04 98.685 ;
     RECT  2.16 98.955 26.028 99.225 ;
     RECT  124.956 98.955 149.04 99.225 ;
     RECT  2.16 99.495 26.028 99.765 ;
     RECT  124.956 99.495 149.04 99.765 ;
     RECT  2.16 100.035 26.028 100.305 ;
     RECT  124.956 100.035 149.04 100.305 ;
     RECT  2.16 100.575 26.028 100.845 ;
     RECT  124.956 100.575 149.04 100.845 ;
     RECT  2.16 101.115 26.028 101.385 ;
     RECT  124.956 101.115 149.04 101.385 ;
     RECT  2.16 101.655 26.028 101.925 ;
     RECT  124.956 101.655 149.04 101.925 ;
     RECT  2.16 102.195 26.028 102.465 ;
     RECT  124.956 102.195 149.04 102.465 ;
     RECT  2.16 102.735 26.028 103.005 ;
     RECT  124.956 102.735 149.04 103.005 ;
     RECT  2.16 103.275 26.028 103.545 ;
     RECT  124.956 103.275 149.04 103.545 ;
     RECT  2.16 103.815 26.028 104.085 ;
     RECT  124.956 103.815 149.04 104.085 ;
     RECT  2.16 104.355 26.028 104.625 ;
     RECT  124.956 104.355 149.04 104.625 ;
     RECT  2.16 104.895 26.028 105.165 ;
     RECT  124.956 104.895 149.04 105.165 ;
     RECT  2.16 105.435 26.028 105.705 ;
     RECT  124.956 105.435 149.04 105.705 ;
     RECT  2.16 105.975 26.028 106.245 ;
     RECT  124.956 105.975 149.04 106.245 ;
     RECT  2.16 106.515 26.028 106.785 ;
     RECT  124.956 106.515 149.04 106.785 ;
     RECT  2.16 107.055 26.028 107.325 ;
     RECT  124.956 107.055 149.04 107.325 ;
     RECT  2.16 107.595 26.028 107.865 ;
     RECT  124.956 107.595 149.04 107.865 ;
     RECT  2.16 108.135 26.028 108.405 ;
     RECT  124.956 108.135 149.04 108.405 ;
     RECT  2.16 108.675 26.028 108.945 ;
     RECT  124.956 108.675 149.04 108.945 ;
     RECT  2.16 109.215 26.028 109.485 ;
     RECT  124.956 109.215 149.04 109.485 ;
     RECT  2.16 109.755 26.028 110.025 ;
     RECT  124.956 109.755 149.04 110.025 ;
     RECT  2.16 110.295 26.028 110.565 ;
     RECT  124.956 110.295 149.04 110.565 ;
     RECT  2.16 110.835 26.028 111.105 ;
     RECT  124.956 110.835 149.04 111.105 ;
     RECT  2.16 111.375 26.028 111.645 ;
     RECT  124.956 111.375 149.04 111.645 ;
     RECT  2.16 111.915 26.028 112.185 ;
     RECT  124.956 111.915 149.04 112.185 ;
     RECT  2.16 112.455 26.028 112.725 ;
     RECT  124.956 112.455 149.04 112.725 ;
     RECT  2.16 112.995 26.028 113.265 ;
     RECT  124.956 112.995 149.04 113.265 ;
     RECT  2.16 113.535 26.028 113.805 ;
     RECT  124.956 113.535 149.04 113.805 ;
     RECT  2.16 114.075 26.028 114.345 ;
     RECT  124.956 114.075 149.04 114.345 ;
     RECT  2.16 114.615 26.028 114.885 ;
     RECT  124.956 114.615 149.04 114.885 ;
     RECT  2.16 115.155 26.028 115.425 ;
     RECT  124.956 115.155 149.04 115.425 ;
     RECT  2.16 115.695 26.028 115.965 ;
     RECT  124.956 115.695 149.04 115.965 ;
     RECT  2.16 116.235 26.028 116.505 ;
     RECT  124.956 116.235 149.04 116.505 ;
     RECT  2.16 116.775 26.028 117.045 ;
     RECT  124.956 116.775 149.04 117.045 ;
     RECT  2.16 117.315 26.028 117.585 ;
     RECT  124.956 117.315 149.04 117.585 ;
     RECT  2.16 117.855 26.028 118.125 ;
     RECT  124.956 117.855 149.04 118.125 ;
     RECT  2.16 118.395 26.028 118.665 ;
     RECT  124.956 118.395 149.04 118.665 ;
     RECT  2.16 118.935 26.028 119.205 ;
     RECT  124.956 118.935 149.04 119.205 ;
     RECT  2.16 119.475 26.028 119.745 ;
     RECT  124.956 119.475 149.04 119.745 ;
     RECT  2.16 120.015 26.028 120.285 ;
     RECT  124.956 120.015 149.04 120.285 ;
     RECT  2.16 120.555 26.028 120.825 ;
     RECT  124.956 120.555 149.04 120.825 ;
     RECT  2.16 121.095 26.028 121.365 ;
     RECT  124.956 121.095 149.04 121.365 ;
     RECT  2.16 121.635 26.028 121.905 ;
     RECT  124.956 121.635 149.04 121.905 ;
     RECT  2.16 122.175 26.028 122.445 ;
     RECT  124.956 122.175 149.04 122.445 ;
     RECT  2.16 122.715 26.028 122.985 ;
     RECT  124.956 122.715 149.04 122.985 ;
     RECT  2.16 123.255 26.028 123.525 ;
     RECT  124.956 123.255 149.04 123.525 ;
     RECT  2.16 123.795 26.028 124.065 ;
     RECT  124.956 123.795 149.04 124.065 ;
     RECT  2.16 124.335 26.028 124.605 ;
     RECT  124.956 124.335 149.04 124.605 ;
     RECT  2.16 124.875 26.028 125.145 ;
     RECT  124.956 124.875 149.04 125.145 ;
     RECT  2.16 125.415 26.028 125.685 ;
     RECT  124.956 125.415 149.04 125.685 ;
     RECT  2.16 125.955 26.028 126.225 ;
     RECT  124.956 125.955 149.04 126.225 ;
     RECT  2.16 126.495 26.028 126.765 ;
     RECT  124.956 126.495 149.04 126.765 ;
     RECT  2.16 127.035 26.028 127.305 ;
     RECT  124.956 127.035 149.04 127.305 ;
     RECT  2.16 127.575 26.028 127.845 ;
     RECT  124.956 127.575 149.04 127.845 ;
     RECT  2.16 128.115 26.028 128.385 ;
     RECT  124.956 128.115 149.04 128.385 ;
     RECT  2.16 128.655 26.028 128.925 ;
     RECT  124.956 128.655 149.04 128.925 ;
     RECT  2.16 129.195 26.028 129.465 ;
     RECT  124.956 129.195 149.04 129.465 ;
     RECT  2.16 129.735 149.04 130.005 ;
     RECT  2.16 130.275 149.04 130.545 ;
     RECT  2.16 130.815 149.04 131.085 ;
     RECT  2.16 131.355 149.04 131.625 ;
     RECT  2.16 131.895 149.04 132.165 ;
     RECT  2.16 132.435 149.04 132.705 ;
     RECT  2.16 132.975 149.04 133.245 ;
     RECT  2.16 133.515 149.04 133.785 ;
     RECT  2.16 134.055 149.04 134.325 ;
     RECT  2.16 134.595 149.04 134.865 ;
     RECT  2.16 135.135 149.04 135.405 ;
     RECT  2.16 135.675 149.04 135.945 ;
     RECT  2.16 136.215 149.04 136.485 ;
     RECT  2.16 136.755 149.04 137.025 ;
     RECT  2.16 137.295 149.04 137.565 ;
     RECT  2.16 137.835 149.04 138.105 ;
     RECT  2.16 138.375 149.04 138.645 ;
     RECT  2.16 138.915 149.04 139.185 ;
     RECT  2.16 139.455 149.04 139.725 ;
     RECT  2.16 139.995 149.04 140.265 ;
     RECT  2.16 140.535 149.04 140.805 ;
     RECT  2.16 141.075 149.04 141.345 ;
     RECT  2.16 141.615 149.04 141.885 ;
     RECT  2.16 142.155 149.04 142.425 ;
     RECT  2.16 142.695 149.04 142.965 ;
     RECT  2.16 143.235 149.04 143.505 ;
     RECT  2.16 143.775 149.04 144.045 ;
     RECT  2.16 144.315 149.04 144.585 ;
     RECT  2.16 144.855 149.04 145.125 ;
     RECT  2.16 145.395 149.04 145.665 ;
     RECT  2.16 145.935 149.04 146.205 ;
     RECT  2.16 146.475 149.04 146.745 ;
     RECT  2.16 147.015 149.04 147.285 ;
     RECT  2.16 147.555 149.04 147.825 ;
     RECT  2.16 148.095 149.04 148.365 ;
     RECT  2.16 148.635 149.04 148.905 ;
    LAYER M1 ;
     RECT  2.16 2.151 149.04 21.609 ;
     RECT  28.08 23.76 122.904 64.824 ;
     RECT  2.16 21.609 26.028 66.951 ;
     RECT  124.956 21.609 149.04 66.951 ;
     RECT  2.16 66.951 149.04 84.249 ;
     RECT  28.08 86.4 122.904 127.464 ;
     RECT  2.16 84.249 26.028 129.591 ;
     RECT  124.956 84.249 149.04 129.591 ;
     RECT  2.16 129.591 149.04 149.049 ;
    LAYER M2 ;
     RECT  1.111 144.216 1.687 144.234 ;
     RECT  1.795 147.906 1.975 147.924 ;
     RECT  1.327 139.086 2.16 139.104 ;
     RECT  1.111 141.894 2.16 141.912 ;
     RECT  1.687 144.216 2.16 145.224 ;
     RECT  1.687 146.376 2.16 146.394 ;
     RECT  1.975 147.726 2.16 147.924 ;
     RECT  2.083 148.716 2.16 148.734 ;
     RECT  2.16 2.151 6.979 149.049 ;
     RECT  6.979 2.106 7.979 149.049 ;
     RECT  7.979 2.151 9.283 149.049 ;
     RECT  9.283 2.151 9.643 149.166 ;
     RECT  9.427 150.876 10.219 150.894 ;
     RECT  10.219 150.876 10.355 151.164 ;
     RECT  9.643 2.151 10.715 149.202 ;
     RECT  10.715 2.151 10.967 149.166 ;
     RECT  10.867 150.336 11.075 150.354 ;
     RECT  10.355 151.146 11.083 151.164 ;
     RECT  11.083 150.462 11.255 151.164 ;
     RECT  10.967 2.151 12.451 149.094 ;
     RECT  11.255 151.146 14.251 151.164 ;
     RECT  14.251 151.074 16.223 151.164 ;
     RECT  12.451 2.151 17.635 149.166 ;
     RECT  17.635 2.151 17.707 149.634 ;
     RECT  17.707 2.106 18.959 149.634 ;
     RECT  16.223 151.146 19.219 151.164 ;
     RECT  19.219 151.11 19.651 151.164 ;
     RECT  18.959 2.151 19.903 149.634 ;
     RECT  19.903 2.151 20.083 149.742 ;
     RECT  19.651 150.498 20.083 151.164 ;
     RECT  20.083 2.151 20.183 151.164 ;
     RECT  20.183 2.151 20.299 149.742 ;
     RECT  20.299 2.106 20.903 149.742 ;
     RECT  20.183 151.11 24.223 151.164 ;
     RECT  24.223 150.804 24.575 151.164 ;
     RECT  20.903 2.151 26.028 149.742 ;
     RECT  26.028 24.066 26.123 25.704 ;
     RECT  26.028 26.676 26.123 61.344 ;
     RECT  26.028 99.936 26.123 119.304 ;
     RECT  26.028 123.156 26.123 124.83 ;
     RECT  26.123 26.676 26.159 60.264 ;
     RECT  26.159 26.676 26.195 55.674 ;
     RECT  26.028 85.77 26.195 85.824 ;
     RECT  26.028 62.28 26.231 64.692 ;
     RECT  26.123 116.946 26.231 119.304 ;
     RECT  26.028 65.484 26.303 65.574 ;
     RECT  26.303 65.556 26.375 65.574 ;
     RECT  26.231 116.946 26.447 117.81 ;
     RECT  26.123 99.936 26.519 116.154 ;
     RECT  26.159 56.574 26.555 60.264 ;
     RECT  26.123 24.066 26.627 25.308 ;
     RECT  26.028 66.726 26.663 84.249 ;
     RECT  26.028 86.661 26.735 99.144 ;
     RECT  26.195 34.236 26.771 55.674 ;
     RECT  26.519 99.936 26.771 111.474 ;
     RECT  26.231 118.836 26.771 119.304 ;
     RECT  26.028 126.666 26.771 149.742 ;
     RECT  26.555 56.574 26.807 60.174 ;
     RECT  26.735 87.246 26.807 99.144 ;
     RECT  26.447 116.946 26.807 117.774 ;
     RECT  26.028 121.266 26.807 122.004 ;
     RECT  26.807 56.574 26.843 59.832 ;
     RECT  26.195 26.676 26.879 33.372 ;
     RECT  26.771 34.236 26.879 42.624 ;
     RECT  26.771 104.634 27.023 111.474 ;
     RECT  26.807 88.434 27.059 99.144 ;
     RECT  26.231 63.756 27.067 64.692 ;
     RECT  26.843 56.574 27.131 59.022 ;
     RECT  27.023 104.634 27.167 110.484 ;
     RECT  27.067 63.756 27.175 64.998 ;
     RECT  26.519 112.536 27.175 116.154 ;
     RECT  26.807 116.946 27.175 117.414 ;
     RECT  26.627 24.642 27.203 25.308 ;
     RECT  27.023 111.312 27.203 111.474 ;
     RECT  26.879 28.53 27.239 33.372 ;
     RECT  26.879 35.946 27.275 42.624 ;
     RECT  26.771 43.506 27.275 55.674 ;
     RECT  27.239 28.53 27.311 30.474 ;
     RECT  27.275 35.946 27.311 36.81 ;
     RECT  27.275 43.506 27.311 52.884 ;
     RECT  27.275 37.71 27.347 42.624 ;
     RECT  27.311 43.776 27.347 52.884 ;
     RECT  27.059 98.424 27.347 99.144 ;
     RECT  26.771 118.836 27.347 118.854 ;
     RECT  26.167 0.531 27.463 0.549 ;
     RECT  26.807 121.446 27.463 122.004 ;
     RECT  26.123 123.156 27.463 124.056 ;
     RECT  26.028 120.258 27.535 120.276 ;
     RECT  27.463 121.446 27.535 124.056 ;
     RECT  26.663 66.951 27.607 84.249 ;
     RECT  27.131 56.646 27.679 59.022 ;
     RECT  26.843 59.814 27.679 59.832 ;
     RECT  27.175 63.756 27.715 65.619 ;
     RECT  27.607 66.636 27.715 84.249 ;
     RECT  27.203 24.642 27.751 24.804 ;
     RECT  27.275 53.766 27.931 55.674 ;
     RECT  27.679 56.646 27.931 59.832 ;
     RECT  26.195 85.77 28.067 85.788 ;
     RECT  26.028 22.716 28.08 23.112 ;
     RECT  27.751 24.561 28.08 24.804 ;
     RECT  26.879 26.676 28.08 27.594 ;
     RECT  27.311 28.53 28.08 29.484 ;
     RECT  27.311 30.312 28.08 30.474 ;
     RECT  27.239 31.428 28.08 33.372 ;
     RECT  26.879 34.236 28.08 35.064 ;
     RECT  27.311 36.09 28.08 36.81 ;
     RECT  27.347 37.71 28.08 41.472 ;
     RECT  27.347 42.606 28.08 42.624 ;
     RECT  27.347 44.316 28.08 45.558 ;
     RECT  27.347 46.476 28.08 52.884 ;
     RECT  27.931 53.766 28.08 59.832 ;
     RECT  26.123 61.164 28.08 61.344 ;
     RECT  26.231 62.28 28.08 62.874 ;
     RECT  27.715 63.756 28.08 84.249 ;
     RECT  26.807 87.588 28.08 87.606 ;
     RECT  27.059 88.434 28.08 97.596 ;
     RECT  27.347 98.424 28.08 98.91 ;
     RECT  26.771 99.972 28.08 103.734 ;
     RECT  27.167 104.634 28.08 110.052 ;
     RECT  27.203 111.456 28.08 111.474 ;
     RECT  27.175 112.536 28.08 117.414 ;
     RECT  27.535 120.258 28.08 124.056 ;
     RECT  26.123 124.812 28.08 124.83 ;
     RECT  26.771 127.386 28.08 149.742 ;
     RECT  27.463 0.486 28.219 0.549 ;
     RECT  28.219 0.342 28.435 0.549 ;
     RECT  28.435 0.261 29.723 0.549 ;
     RECT  28.08 22.716 29.867 84.249 ;
     RECT  29.723 0.261 30.299 0.504 ;
     RECT  29.867 65.556 30.299 84.249 ;
     RECT  30.299 66.141 30.551 84.249 ;
     RECT  30.299 0.414 30.983 0.504 ;
     RECT  30.983 0.414 31.055 0.432 ;
     RECT  29.867 22.716 31.379 64.824 ;
     RECT  26.028 2.151 31.955 21.96 ;
     RECT  28.08 86.4 32.531 149.742 ;
     RECT  30.551 66.834 32.783 84.249 ;
     RECT  24.575 151.11 33.107 151.164 ;
     RECT  33.107 151.146 33.683 151.164 ;
     RECT  32.531 86.4 34.223 149.706 ;
     RECT  34.223 86.4 34.295 149.67 ;
     RECT  31.955 2.151 34.511 21.654 ;
     RECT  32.783 66.87 34.771 84.249 ;
     RECT  34.295 86.4 35.591 149.364 ;
     RECT  38.767 150.462 38.939 150.48 ;
     RECT  40.027 150.462 40.127 150.48 ;
     RECT  34.771 66.762 40.631 84.249 ;
     RECT  41.035 150.462 41.171 150.48 ;
     RECT  42.043 150.462 42.359 150.48 ;
     RECT  35.591 86.4 44.555 149.319 ;
     RECT  44.555 128.511 44.663 149.319 ;
     RECT  44.663 128.628 46.607 149.319 ;
     RECT  40.631 66.906 47.543 84.249 ;
     RECT  46.607 128.628 49.379 149.049 ;
     RECT  49.379 129.096 50.063 149.049 ;
     RECT  50.539 150.498 50.675 150.516 ;
     RECT  50.063 129.474 51.719 149.049 ;
     RECT  51.719 129.51 51.755 149.049 ;
     RECT  51.755 129.546 60.287 149.049 ;
     RECT  60.287 129.591 62.671 149.049 ;
     RECT  62.671 129.51 98.599 149.049 ;
     RECT  98.599 129.474 106.511 149.049 ;
     RECT  47.543 66.951 106.591 84.249 ;
     RECT  34.511 2.151 108.175 21.609 ;
     RECT  106.511 129.51 108.319 149.049 ;
     RECT  108.175 1.998 110.083 21.609 ;
     RECT  108.319 129.438 110.327 149.049 ;
     RECT  110.083 1.962 110.335 21.609 ;
     RECT  110.335 1.881 110.731 21.609 ;
     RECT  110.731 1.152 111.011 21.609 ;
     RECT  111.011 1.728 111.155 21.609 ;
     RECT  106.591 66.906 111.371 84.249 ;
     RECT  111.155 1.881 111.919 21.609 ;
     RECT  111.919 1.152 112.271 21.609 ;
     RECT  112.271 1.881 112.487 21.609 ;
     RECT  31.379 23.058 113.711 64.824 ;
     RECT  114.187 1.152 114.503 1.17 ;
     RECT  112.487 2.151 116.347 21.609 ;
     RECT  116.347 1.728 116.447 21.609 ;
     RECT  113.711 23.76 117.391 64.824 ;
     RECT  118.219 1.152 118.319 1.17 ;
     RECT  119.695 1.152 119.795 1.17 ;
     RECT  116.447 2.151 122.539 21.609 ;
     RECT  117.391 23.058 122.567 64.824 ;
     RECT  122.567 23.094 122.575 64.824 ;
     RECT  111.371 66.951 122.755 84.249 ;
     RECT  122.755 66.951 122.827 84.942 ;
     RECT  122.539 2.151 122.899 21.654 ;
     RECT  122.575 23.094 122.904 64.962 ;
     RECT  44.555 86.4 122.904 127.464 ;
     RECT  122.904 86.4 122.935 86.409 ;
     RECT  122.899 2.151 122.999 21.69 ;
     RECT  122.904 23.094 123.035 23.724 ;
     RECT  122.904 87.426 123.035 87.84 ;
     RECT  122.935 86.391 123.071 86.409 ;
     RECT  122.904 126.396 123.223 127.464 ;
     RECT  122.904 64.296 123.251 64.962 ;
     RECT  122.827 66.951 123.259 85.014 ;
     RECT  122.904 90.216 123.323 90.306 ;
     RECT  123.259 66.951 123.475 85.059 ;
     RECT  123.223 86.04 123.475 86.058 ;
     RECT  123.323 90.216 123.503 90.234 ;
     RECT  122.904 47.592 123.655 47.61 ;
     RECT  122.904 48.672 123.655 48.834 ;
     RECT  122.904 49.752 123.655 51.93 ;
     RECT  122.904 60.39 123.655 60.408 ;
     RECT  123.035 87.741 123.655 87.84 ;
     RECT  122.904 95.418 123.655 96.444 ;
     RECT  122.904 97.416 123.655 97.749 ;
     RECT  122.904 102.672 123.655 104.85 ;
     RECT  122.904 106.686 123.655 109.404 ;
     RECT  122.904 110.376 123.655 110.79 ;
     RECT  122.904 111.546 123.655 119.664 ;
     RECT  122.904 120.492 123.655 120.51 ;
     RECT  122.904 122.112 123.655 124.164 ;
     RECT  122.904 125.622 123.655 125.64 ;
     RECT  122.904 30.186 123.683 30.204 ;
     RECT  122.904 88.866 123.683 88.884 ;
     RECT  122.904 34.74 123.691 34.758 ;
     RECT  122.904 35.712 123.691 38.196 ;
     RECT  122.904 39.492 123.691 40.284 ;
     RECT  123.655 41.256 123.691 41.274 ;
     RECT  122.904 42.03 123.691 43.29 ;
     RECT  123.655 44.73 123.691 44.748 ;
     RECT  122.904 45.666 123.691 46.836 ;
     RECT  123.655 47.592 123.691 48.834 ;
     RECT  123.655 49.752 123.691 52.542 ;
     RECT  122.904 53.532 123.691 53.784 ;
     RECT  122.904 54.918 123.691 58.014 ;
     RECT  123.655 59.778 123.691 60.408 ;
     RECT  122.904 61.596 123.691 62.604 ;
     RECT  123.251 64.296 123.691 64.692 ;
     RECT  123.655 95.418 123.691 97.749 ;
     RECT  122.904 99.036 123.691 101.07 ;
     RECT  123.655 102.276 123.691 104.85 ;
     RECT  123.655 105.678 123.691 110.79 ;
     RECT  123.655 111.546 123.691 124.164 ;
     RECT  123.655 125.226 123.691 125.64 ;
     RECT  123.223 126.396 123.691 127.494 ;
     RECT  122.904 29.376 123.727 29.394 ;
     RECT  123.691 34.74 123.727 38.196 ;
     RECT  123.691 39.186 123.727 53.784 ;
     RECT  122.999 2.151 123.755 21.654 ;
     RECT  123.475 66.951 123.755 86.058 ;
     RECT  122.904 27.216 123.763 27.234 ;
     RECT  123.763 26.766 123.863 27.234 ;
     RECT  123.755 86.04 123.863 86.058 ;
     RECT  123.727 34.74 123.943 53.784 ;
     RECT  123.755 66.951 124.043 84.978 ;
     RECT  123.655 87.741 124.043 88.029 ;
     RECT  123.691 99.036 124.051 127.494 ;
     RECT  123.691 94.986 124.087 97.749 ;
     RECT  124.051 98.496 124.087 127.494 ;
     RECT  122.904 32.04 124.123 33.534 ;
     RECT  123.943 34.632 124.123 53.784 ;
     RECT  123.691 54.612 124.123 60.408 ;
     RECT  122.071 65.826 124.187 65.844 ;
     RECT  123.691 61.362 124.195 62.604 ;
     RECT  124.123 31.536 124.231 33.534 ;
     RECT  124.123 34.632 124.231 60.408 ;
     RECT  124.195 61.2 124.231 62.604 ;
     RECT  122.904 93.996 124.231 94.014 ;
     RECT  124.087 94.986 124.231 127.494 ;
     RECT  123.691 63.756 124.339 64.692 ;
     RECT  124.231 34.632 124.375 62.604 ;
     RECT  124.339 63.522 124.375 64.692 ;
     RECT  123.727 29.07 124.519 29.394 ;
     RECT  124.043 66.951 124.555 84.249 ;
     RECT  123.863 27.216 124.591 27.234 ;
     RECT  123.035 23.094 124.843 23.184 ;
     RECT  124.591 27.216 124.879 27.324 ;
     RECT  124.519 29.034 124.879 29.394 ;
     RECT  124.627 25.146 124.915 25.164 ;
     RECT  123.755 2.151 124.956 21.609 ;
     RECT  124.843 22.716 124.956 23.184 ;
     RECT  124.915 24.102 124.956 24.12 ;
     RECT  124.915 25.056 124.956 25.812 ;
     RECT  124.879 27.216 124.956 27.594 ;
     RECT  124.879 28.836 124.956 29.394 ;
     RECT  124.231 31.464 124.956 33.534 ;
     RECT  124.375 34.632 124.956 64.692 ;
     RECT  124.555 66.726 124.956 84.249 ;
     RECT  124.519 86.616 124.956 86.634 ;
     RECT  124.267 87.426 124.956 87.444 ;
     RECT  124.843 91.566 124.956 91.584 ;
     RECT  124.231 93.996 124.956 127.494 ;
     RECT  110.327 129.591 124.956 149.049 ;
     RECT  126.355 1.152 126.455 1.17 ;
     RECT  131.359 1.152 131.531 1.17 ;
     RECT  124.956 2.151 132.151 149.049 ;
     RECT  132.151 2.106 132.467 149.049 ;
     RECT  132.467 2.151 133.303 149.049 ;
     RECT  133.303 2.106 135.635 149.049 ;
     RECT  135.635 2.151 149.04 149.049 ;
    LAYER M3 ;
     RECT  9.864 0.091 9.882 0.139 ;
     RECT  10.8 0.091 10.818 0.139 ;
     RECT  16.956 0.091 16.974 0.139 ;
     RECT  18.252 0.091 18.486 0.139 ;
     RECT  19.296 0.091 19.314 0.139 ;
     RECT  20.772 0.091 21.114 0.139 ;
     RECT  21.888 0.091 23.994 0.139 ;
     RECT  119.268 0.091 119.502 0.139 ;
     RECT  122.328 0.091 122.634 0.139 ;
     RECT  123.408 0.091 123.606 0.139 ;
     RECT  127.332 0.091 127.962 0.139 ;
     RECT  128.772 0.091 130.95 0.139 ;
     RECT  131.724 0.091 131.742 0.139 ;
     RECT  132.516 0.091 133.038 0.139 ;
     RECT  133.812 0.091 133.83 0.139 ;
     RECT  135 0.043 135.018 0.173 ;
     RECT  109.764 0.091 110.25 0.221 ;
     RECT  12.06 0.091 12.87 0.235 ;
     RECT  16.956 0.139 17.514 0.235 ;
     RECT  29.7 0.139 29.718 0.235 ;
     RECT  119.268 0.139 119.718 0.235 ;
     RECT  29.7 0.235 29.754 0.256 ;
     RECT  30.636 0.091 31.158 0.256 ;
     RECT  29.7 0.256 31.158 0.269 ;
     RECT  27.288 0.091 27.306 0.283 ;
     RECT  122.328 0.139 123.606 0.283 ;
     RECT  124.344 0.091 125.01 0.283 ;
     RECT  120.816 0.091 120.834 0.317 ;
     RECT  127.332 0.139 131.742 0.317 ;
     RECT  16.884 0.235 17.514 0.331 ;
     RECT  18.252 0.139 19.314 0.331 ;
     RECT  28.44 0.256 28.458 0.337 ;
     RECT  26.784 0.283 27.306 0.413 ;
     RECT  28.224 0.337 28.458 0.427 ;
     RECT  29.7 0.269 31.05 0.437 ;
     RECT  28.224 0.427 28.854 0.475 ;
     RECT  29.7 0.437 30.978 0.475 ;
     RECT  27.108 0.413 27.306 0.481 ;
     RECT  28.08 0.475 28.854 0.481 ;
     RECT  29.664 0.475 30.978 0.509 ;
     RECT  11.952 0.235 12.87 0.523 ;
     RECT  13.752 0.283 13.77 0.523 ;
     RECT  20.772 0.139 23.994 0.523 ;
     RECT  110.196 0.221 110.25 0.523 ;
     RECT  111.132 0.091 111.69 0.523 ;
     RECT  112.68 0.091 115.11 0.523 ;
     RECT  121.572 0.091 121.59 0.523 ;
     RECT  25.2 0.091 25.974 0.526 ;
     RECT  29.7 0.509 30.798 0.554 ;
     RECT  110.196 0.523 111.69 0.571 ;
     RECT  112.464 0.523 115.11 0.571 ;
     RECT  115.956 0.091 117.594 0.571 ;
     RECT  120.888 0.523 121.59 0.571 ;
     RECT  122.328 0.283 125.01 0.571 ;
     RECT  29.736 0.554 30.798 0.653 ;
     RECT  110.196 0.571 115.11 1.003 ;
     RECT  20.772 0.523 24.174 1.099 ;
     RECT  127.404 0.317 131.742 1.099 ;
     RECT  132.516 0.139 133.83 1.099 ;
     RECT  115.956 0.571 118.242 1.147 ;
     RECT  119.268 0.235 119.754 1.147 ;
     RECT  120.888 0.571 125.01 1.675 ;
     RECT  125.748 0.091 126.594 1.675 ;
     RECT  20.592 1.099 24.174 2.011 ;
     RECT  27.108 0.481 28.854 2.011 ;
     RECT  29.736 0.653 29.754 2.011 ;
     RECT  8.208 0.091 8.802 2.101 ;
     RECT  20.592 2.011 24.39 2.101 ;
     RECT  127.404 1.099 133.83 2.101 ;
     RECT  134.568 0.571 134.586 2.101 ;
     RECT  115.956 1.147 118.314 2.107 ;
     RECT  119.268 1.147 119.79 2.107 ;
     RECT  7.956 2.101 8.802 2.143 ;
     RECT  109.728 1.003 115.11 2.143 ;
     RECT  115.956 2.107 119.79 2.143 ;
     RECT  120.888 1.675 126.594 2.143 ;
     RECT  127.404 2.101 135.63 2.143 ;
     RECT  25.2 0.526 26.19 2.155 ;
     RECT  9.864 0.139 10.818 2.191 ;
     RECT  11.952 0.523 13.77 2.191 ;
     RECT  15.48 0.091 16.038 2.191 ;
     RECT  16.884 0.331 19.314 2.191 ;
     RECT  20.304 2.101 24.39 2.191 ;
     RECT  25.2 2.155 26.334 2.191 ;
     RECT  27.108 2.011 29.754 2.191 ;
     RECT  30.636 0.653 30.798 2.191 ;
     RECT  120.888 2.143 135.63 2.191 ;
     RECT  25.2 2.191 29.754 2.227 ;
     RECT  30.564 2.191 30.798 2.227 ;
     RECT  34.815 2.143 34.905 2.227 ;
     RECT  108.18 1.993 108.198 2.227 ;
     RECT  109.728 2.143 119.79 2.227 ;
     RECT  109.584 2.227 119.79 2.251 ;
     RECT  9.864 2.191 13.77 2.263 ;
     RECT  15.48 2.191 24.39 2.263 ;
     RECT  108.108 2.227 108.198 2.263 ;
     RECT  32.076 2.191 32.094 2.291 ;
     RECT  6.984 2.101 7.002 2.299 ;
     RECT  7.815 2.143 8.802 2.299 ;
     RECT  9.864 2.263 24.39 2.299 ;
     RECT  25.2 2.227 30.798 2.299 ;
     RECT  109.584 2.251 119.97 2.299 ;
     RECT  120.888 2.191 135.774 2.299 ;
     RECT  80.928 0.043 80.946 2.363 ;
     RECT  6.948 2.299 30.798 2.371 ;
     RECT  34.56 2.227 34.905 2.399 ;
     RECT  2.415 2.143 2.505 2.413 ;
     RECT  34.815 2.399 34.905 2.413 ;
     RECT  40.215 2.143 40.305 2.413 ;
     RECT  45.615 2.143 45.705 2.413 ;
     RECT  51.015 2.143 51.105 2.413 ;
     RECT  56.415 2.143 56.505 2.413 ;
     RECT  61.815 2.143 61.905 2.413 ;
     RECT  67.215 2.143 67.305 2.413 ;
     RECT  72.615 2.143 72.705 2.413 ;
     RECT  78.015 2.143 78.105 2.413 ;
     RECT  83.415 2.143 83.505 2.413 ;
     RECT  88.815 2.143 88.905 2.413 ;
     RECT  94.215 2.143 94.305 2.413 ;
     RECT  99.615 2.143 99.705 2.413 ;
     RECT  105.015 2.143 105.105 2.413 ;
     RECT  137.415 2.143 137.505 2.413 ;
     RECT  142.815 2.143 142.905 2.413 ;
     RECT  148.215 2.143 148.305 2.413 ;
     RECT  81.108 2.371 81.126 2.561 ;
     RECT  6.876 2.371 30.798 2.605 ;
     RECT  83.415 2.413 83.697 2.641 ;
     RECT  94.215 2.413 94.497 2.641 ;
     RECT  108.108 2.263 108.45 2.641 ;
     RECT  6.66 2.605 30.798 2.731 ;
     RECT  94.215 2.641 94.662 2.731 ;
     RECT  107.712 2.641 108.45 2.731 ;
     RECT  75.096 2.641 75.114 2.759 ;
     RECT  83.415 2.641 84.366 2.759 ;
     RECT  104.004 2.371 104.022 2.795 ;
     RECT  6.66 2.731 30.87 2.803 ;
     RECT  93.168 2.641 93.186 2.831 ;
     RECT  98.604 2.641 98.622 2.831 ;
     RECT  74.916 2.803 75.078 2.861 ;
     RECT  94.215 2.731 95.31 2.911 ;
     RECT  105.015 2.413 105.297 2.911 ;
     RECT  107.712 2.731 108.81 2.911 ;
     RECT  109.584 2.299 135.774 2.911 ;
     RECT  6.66 2.803 31.086 2.923 ;
     RECT  107.712 2.911 135.774 2.939 ;
     RECT  43.344 2.191 43.362 3.065 ;
     RECT  75.888 2.911 75.906 3.101 ;
     RECT  105.015 2.911 105.354 3.109 ;
     RECT  6.624 2.923 31.086 3.181 ;
     RECT  99.615 2.413 99.897 3.181 ;
     RECT  104.904 3.109 105.354 3.181 ;
     RECT  107.712 2.939 135.486 3.181 ;
     RECT  91.44 3.109 91.458 3.271 ;
     RECT  107.172 3.181 135.486 3.271 ;
     RECT  96.876 3.109 96.894 3.299 ;
     RECT  6.624 3.181 31.23 3.307 ;
     RECT  91.44 3.271 91.746 3.307 ;
     RECT  49.32 3.001 49.338 3.335 ;
     RECT  99.615 3.181 100.17 3.335 ;
     RECT  104.904 3.181 105.462 3.335 ;
     RECT  6.552 3.307 31.23 3.341 ;
     RECT  91.296 3.307 91.746 3.341 ;
     RECT  88.815 2.413 89.097 3.451 ;
     RECT  94.215 2.911 95.418 3.451 ;
     RECT  75.06 2.861 75.078 3.479 ;
     RECT  32.58 3.379 32.706 3.569 ;
     RECT  88.815 3.451 89.73 3.569 ;
     RECT  90.648 3.451 90.666 3.569 ;
     RECT  33.624 3.181 33.642 3.605 ;
     RECT  49.752 3.379 49.77 3.605 ;
     RECT  88.815 3.569 89.586 3.629 ;
     RECT  98.064 3.271 98.082 3.677 ;
     RECT  6.66 3.341 31.23 3.685 ;
     RECT  99.615 3.335 99.897 3.721 ;
     RECT  106.74 3.271 135.486 3.721 ;
     RECT  6.66 3.685 31.482 3.749 ;
     RECT  90.504 3.721 90.63 3.773 ;
     RECT  106.02 3.721 135.486 3.839 ;
     RECT  6.804 3.749 31.482 3.847 ;
     RECT  39.168 3.541 39.186 3.875 ;
     RECT  49.968 3.721 49.986 3.875 ;
     RECT  87.408 3.145 87.426 3.875 ;
     RECT  43.272 3.811 43.29 3.911 ;
     RECT  91.728 3.341 91.746 3.911 ;
     RECT  94.215 3.451 95.814 3.911 ;
     RECT  106.02 3.839 107.55 3.965 ;
     RECT  47.016 3.931 47.034 3.983 ;
     RECT  48.276 3.919 48.294 3.991 ;
     RECT  51.015 2.413 51.297 3.991 ;
     RECT  99.18 3.721 99.897 3.991 ;
     RECT  50.256 3.991 51.297 4.109 ;
     RECT  70.524 3.991 70.542 4.109 ;
     RECT  104.904 3.335 105.297 4.109 ;
     RECT  34.815 2.413 35.097 4.117 ;
     RECT  48.096 3.991 48.33 4.145 ;
     RECT  106.02 3.965 106.866 4.145 ;
     RECT  6.804 3.847 31.914 4.157 ;
     RECT  36.216 3.991 36.234 4.217 ;
     RECT  94.215 3.911 95.526 4.217 ;
     RECT  51.015 4.109 51.297 4.225 ;
     RECT  95.436 4.217 95.454 4.253 ;
     RECT  34.815 4.117 35.262 4.261 ;
     RECT  40.215 2.413 40.497 4.261 ;
     RECT  51.015 4.225 51.354 4.261 ;
     RECT  102.6 3.451 102.618 4.289 ;
     RECT  50.256 4.109 50.274 4.301 ;
     RECT  6.84 4.157 31.914 4.379 ;
     RECT  34.815 4.261 35.406 4.379 ;
     RECT  48.312 4.145 48.33 4.379 ;
     RECT  81.072 4.261 81.09 4.379 ;
     RECT  106.02 4.145 106.758 4.379 ;
     RECT  6.84 4.379 31.302 4.415 ;
     RECT  33.48 4.261 33.498 4.415 ;
     RECT  90.612 3.773 90.63 4.415 ;
     RECT  98.208 3.991 99.897 4.415 ;
     RECT  106.02 4.379 106.65 4.415 ;
     RECT  80.856 4.459 80.874 4.493 ;
     RECT  105.015 4.109 105.297 4.531 ;
     RECT  45.615 2.413 45.897 4.555 ;
     RECT  90.072 4.507 90.09 4.559 ;
     RECT  6.948 4.415 29.934 4.649 ;
     RECT  45.615 4.555 46.458 4.649 ;
     RECT  64.116 3.811 64.134 4.649 ;
     RECT  30.708 4.415 31.302 4.685 ;
     RECT  36.432 4.261 36.45 4.685 ;
     RECT  63.972 4.651 63.99 4.685 ;
     RECT  70.668 4.117 70.686 4.685 ;
     RECT  98.316 4.415 99.897 4.685 ;
     RECT  61.815 2.413 62.097 4.729 ;
     RECT  51.015 4.261 51.462 4.795 ;
     RECT  32.688 3.569 32.706 4.801 ;
     RECT  47.232 4.729 47.25 4.801 ;
     RECT  64.764 4.729 64.782 4.801 ;
     RECT  47.232 4.801 47.394 4.829 ;
     RECT  51.015 4.795 51.534 4.829 ;
     RECT  61.815 4.729 62.73 4.829 ;
     RECT  64.764 4.801 64.926 4.829 ;
     RECT  6.948 4.649 29.754 4.919 ;
     RECT  30.78 4.685 31.302 4.919 ;
     RECT  36.612 4.801 36.63 4.919 ;
     RECT  64.908 4.829 64.926 4.919 ;
     RECT  60.552 4.927 60.57 4.939 ;
     RECT  60.552 4.939 60.894 4.973 ;
     RECT  30.78 4.919 31.194 4.991 ;
     RECT  56.415 2.413 56.697 5.071 ;
     RECT  60.588 4.973 60.894 5.099 ;
     RECT  30.78 4.991 31.158 5.117 ;
     RECT  64.98 5.071 64.998 5.117 ;
     RECT  108.288 3.839 135.486 5.189 ;
     RECT  60.588 5.099 60.606 5.357 ;
     RECT  32.076 4.801 32.706 5.369 ;
     RECT  98.316 4.685 98.334 5.419 ;
     RECT  98.172 5.419 98.334 5.431 ;
     RECT  98.172 5.431 98.406 5.459 ;
     RECT  103.716 5.341 103.734 5.459 ;
     RECT  56.415 5.071 57.294 5.467 ;
     RECT  108.864 5.189 135.486 5.495 ;
     RECT  55.98 5.467 57.294 5.501 ;
     RECT  54.72 5.305 54.738 5.531 ;
     RECT  98.388 5.459 98.406 5.531 ;
     RECT  103.824 5.611 103.986 5.729 ;
     RECT  103.824 5.729 103.842 5.765 ;
     RECT  40.215 4.261 40.842 6.125 ;
     RECT  30.78 5.117 30.798 6.575 ;
     RECT  109.584 5.495 135.486 6.683 ;
     RECT  6.948 4.919 29.697 6.691 ;
     RECT  109.584 6.683 135.45 6.719 ;
     RECT  6.948 6.691 29.79 6.763 ;
     RECT  6.804 6.763 29.79 6.809 ;
     RECT  109.764 6.719 135.45 6.845 ;
     RECT  7.632 6.809 29.79 7.115 ;
     RECT  82.152 7.087 82.17 7.133 ;
     RECT  82.512 7.231 82.53 7.421 ;
     RECT  32.688 5.369 32.706 7.457 ;
     RECT  75.78 7.429 75.798 7.469 ;
     RECT  48.384 4.531 48.402 7.529 ;
     RECT  51.015 4.829 51.297 7.699 ;
     RECT  51.015 7.699 51.498 7.735 ;
     RECT  36.72 5.071 36.738 7.799 ;
     RECT  103.644 7.861 104.274 7.901 ;
     RECT  7.815 7.115 29.79 7.925 ;
     RECT  104.256 7.901 104.274 8.159 ;
     RECT  56.415 5.501 57.294 8.339 ;
     RECT  51.015 7.735 52.038 8.429 ;
     RECT  52.02 8.429 52.038 8.491 ;
     RECT  52.02 8.491 52.074 8.537 ;
     RECT  99.615 4.685 99.897 8.671 ;
     RECT  99.504 8.671 99.897 8.717 ;
     RECT  110.268 6.845 135.45 9.077 ;
     RECT  113.472 9.077 135.45 9.239 ;
     RECT  52.02 8.537 52.038 9.419 ;
     RECT  113.472 9.239 113.886 9.509 ;
     RECT  8.928 7.925 29.79 9.545 ;
     RECT  110.268 9.077 112.662 9.653 ;
     RECT  111.672 9.653 112.662 9.779 ;
     RECT  113.472 9.509 113.706 9.779 ;
     RECT  9.72 9.545 29.79 9.815 ;
     RECT  111.672 9.779 112.554 9.815 ;
     RECT  112.5 9.815 112.554 9.851 ;
     RECT  112.536 9.851 112.554 9.923 ;
     RECT  111.672 9.815 111.762 10.085 ;
     RECT  111.744 10.085 111.762 10.229 ;
     RECT  9.828 9.815 29.79 10.859 ;
     RECT  8.928 9.545 8.946 10.895 ;
     RECT  9.828 10.859 15.57 10.895 ;
     RECT  9.828 10.895 14.922 11.011 ;
     RECT  16.488 10.859 29.79 11.749 ;
     RECT  30.852 11.323 30.87 11.749 ;
     RECT  16.488 11.749 30.87 11.777 ;
     RECT  16.488 11.777 30.15 11.885 ;
     RECT  9.324 11.011 14.922 11.911 ;
     RECT  16.488 11.885 29.79 11.947 ;
     RECT  114.732 9.239 135.45 12.119 ;
     RECT  9.324 11.911 15.642 12.245 ;
     RECT  16.416 11.947 29.79 12.361 ;
     RECT  15.84 12.361 29.79 12.515 ;
     RECT  16.344 12.515 29.79 12.785 ;
     RECT  114.732 12.119 130.698 13.055 ;
     RECT  16.488 12.785 29.697 13.937 ;
     RECT  9.324 12.245 14.922 14.135 ;
     RECT  9.828 14.135 14.922 14.521 ;
     RECT  114.768 13.055 130.698 14.639 ;
     RECT  9.828 14.521 14.994 14.791 ;
     RECT  114.876 14.639 130.698 14.819 ;
     RECT  9.828 14.791 15.318 15.215 ;
     RECT  9.9 15.215 15.318 16.267 ;
     RECT  115.092 14.819 130.698 16.537 ;
     RECT  9.756 16.267 15.318 16.973 ;
     RECT  114.948 16.537 130.698 17.105 ;
     RECT  47.376 4.829 47.394 17.117 ;
     RECT  115.416 17.105 130.698 17.375 ;
     RECT  16.488 13.937 28.458 17.645 ;
     RECT  115.632 17.375 130.698 17.645 ;
     RECT  16.488 17.645 28.278 18.811 ;
     RECT  115.815 17.645 130.698 19.139 ;
     RECT  16.488 18.811 28.386 19.339 ;
     RECT  16.488 19.339 28.602 19.921 ;
     RECT  29.34 13.937 29.697 19.921 ;
     RECT  30.852 19.921 30.87 20.047 ;
     RECT  30.852 20.047 30.942 20.119 ;
     RECT  16.488 19.921 29.697 20.191 ;
     RECT  16.488 20.191 29.79 20.299 ;
     RECT  30.852 20.119 31.302 20.389 ;
     RECT  110.268 9.653 110.79 20.539 ;
     RECT  16.488 20.299 29.862 20.551 ;
     RECT  30.852 20.389 31.806 20.551 ;
     RECT  109.476 20.539 110.79 20.893 ;
     RECT  16.488 20.551 33.066 20.965 ;
     RECT  16.488 20.965 33.21 21.001 ;
     RECT  115.815 19.139 116.658 21.091 ;
     RECT  109.44 20.893 110.79 21.115 ;
     RECT  108.684 21.115 110.79 21.119 ;
     RECT  108.684 21.119 110.697 21.163 ;
     RECT  115.164 21.091 116.658 21.191 ;
     RECT  16.488 21.001 33.318 21.235 ;
     RECT  108.612 21.163 110.697 21.259 ;
     RECT  16.488 21.235 33.714 21.271 ;
     RECT  34.815 4.379 35.097 21.271 ;
     RECT  16.488 21.271 35.097 21.347 ;
     RECT  40.215 6.125 40.497 21.347 ;
     RECT  45.615 4.649 45.897 21.347 ;
     RECT  51.015 8.429 51.297 21.347 ;
     RECT  56.415 8.339 56.697 21.347 ;
     RECT  61.815 4.829 62.097 21.347 ;
     RECT  67.215 2.413 67.497 21.347 ;
     RECT  72.615 2.413 72.897 21.347 ;
     RECT  78.015 2.413 78.297 21.347 ;
     RECT  83.415 2.759 83.697 21.347 ;
     RECT  88.815 3.629 89.097 21.347 ;
     RECT  94.215 4.217 94.497 21.347 ;
     RECT  99.615 8.717 99.897 21.347 ;
     RECT  105.015 4.531 105.858 21.347 ;
     RECT  108.144 21.259 110.697 21.347 ;
     RECT  115.164 21.191 116.097 21.347 ;
     RECT  117.396 19.139 130.698 21.347 ;
     RECT  122.04 21.347 130.698 21.389 ;
     RECT  108.144 21.347 110.505 21.425 ;
     RECT  122.112 21.389 130.698 21.425 ;
     RECT  108.324 21.425 110.505 21.533 ;
     RECT  30.384 21.347 35.097 21.541 ;
     RECT  117.396 21.347 121.305 21.581 ;
     RECT  122.328 21.425 130.698 21.581 ;
     RECT  16.488 21.347 29.505 21.617 ;
     RECT  40.215 21.347 40.305 21.617 ;
     RECT  45.615 21.347 45.705 21.617 ;
     RECT  51.015 21.347 51.105 21.617 ;
     RECT  56.415 21.347 56.505 21.617 ;
     RECT  61.815 21.347 61.905 21.617 ;
     RECT  67.215 21.347 67.305 21.617 ;
     RECT  72.615 21.347 72.705 21.617 ;
     RECT  78.015 21.347 78.105 21.617 ;
     RECT  83.415 21.347 83.505 21.617 ;
     RECT  88.815 21.347 88.905 21.617 ;
     RECT  94.215 21.347 94.305 21.617 ;
     RECT  99.615 21.347 99.705 21.617 ;
     RECT  105.015 21.347 105.105 21.617 ;
     RECT  109.62 21.533 110.505 21.617 ;
     RECT  115.164 21.347 115.905 21.617 ;
     RECT  121.032 21.581 121.305 21.617 ;
     RECT  30.384 21.541 35.334 21.659 ;
     RECT  122.544 21.581 130.698 21.659 ;
     RECT  16.488 21.617 29.07 21.677 ;
     RECT  31.356 21.659 35.334 21.677 ;
     RECT  108.324 21.533 108.882 21.677 ;
     RECT  109.62 21.617 110.286 21.677 ;
     RECT  122.904 21.659 130.698 21.695 ;
     RECT  121.032 21.617 121.194 21.725 ;
     RECT  31.356 21.677 33.138 21.965 ;
     RECT  117.396 21.581 120.258 22.253 ;
     RECT  115.164 21.617 115.182 22.301 ;
     RECT  105.84 21.347 105.858 22.493 ;
     RECT  10.008 16.973 15.318 22.621 ;
     RECT  10.008 22.621 15.642 22.739 ;
     RECT  31.356 21.965 31.734 22.739 ;
     RECT  110.16 21.677 110.178 22.829 ;
     RECT  16.488 21.677 28.35 22.891 ;
     RECT  122.976 21.695 130.698 23.053 ;
     RECT  16.416 22.891 28.35 23.76 ;
     RECT  30.384 21.659 30.402 23.76 ;
     RECT  31.716 22.739 31.734 23.76 ;
     RECT  32.58 21.965 33.138 23.76 ;
     RECT  34.272 21.677 34.29 23.76 ;
     RECT  113.688 9.779 113.706 23.76 ;
     RECT  117.396 22.253 119.034 23.76 ;
     RECT  119.916 22.253 120.258 23.76 ;
     RECT  121.032 21.725 121.05 23.76 ;
     RECT  122.544 23.053 130.698 23.76 ;
     RECT  16.416 23.76 130.698 23.947 ;
     RECT  10.008 22.739 15.354 24.241 ;
     RECT  16.164 23.947 130.698 24.241 ;
     RECT  10.008 24.241 130.698 25.675 ;
     RECT  131.472 12.119 135.45 25.675 ;
     RECT  10.008 25.675 135.45 25.805 ;
     RECT  10.008 25.805 130.698 27.595 ;
     RECT  9.72 27.595 130.698 27.869 ;
     RECT  10.224 27.869 130.698 28.507 ;
     RECT  131.472 25.805 135.45 28.507 ;
     RECT  10.224 28.507 135.45 30.125 ;
     RECT  131.652 30.125 135.45 30.847 ;
     RECT  10.224 30.125 130.698 30.955 ;
     RECT  131.616 30.847 135.45 30.955 ;
     RECT  10.224 30.955 135.45 31.109 ;
     RECT  10.224 31.109 135.126 32.099 ;
     RECT  7.815 7.925 8.097 33.583 ;
     RECT  9 33.313 9.018 33.583 ;
     RECT  10.224 32.099 130.698 34.619 ;
     RECT  126.468 34.619 130.698 34.733 ;
     RECT  131.688 32.099 132.93 35.899 ;
     RECT  133.704 32.099 135.126 35.899 ;
     RECT  131.688 35.899 135.126 35.969 ;
     RECT  10.224 34.619 125.55 36.283 ;
     RECT  126.615 34.733 130.698 36.391 ;
     RECT  10.152 36.283 125.55 36.475 ;
     RECT  10.152 36.475 125.622 36.661 ;
     RECT  131.688 35.969 132.93 36.751 ;
     RECT  133.704 35.969 135.126 36.751 ;
     RECT  10.152 36.661 125.658 36.859 ;
     RECT  10.152 36.859 125.73 36.931 ;
     RECT  126.504 36.391 130.698 36.959 ;
     RECT  10.152 36.931 125.766 37.021 ;
     RECT  7.815 33.583 9.018 40.261 ;
     RECT  7.815 40.261 9.378 41.107 ;
     RECT  10.152 37.021 125.874 41.107 ;
     RECT  126.615 36.959 130.698 45.959 ;
     RECT  7.815 41.107 125.874 46.381 ;
     RECT  126.615 45.959 127.89 46.381 ;
     RECT  7.815 46.381 127.89 52.591 ;
     RECT  128.628 45.959 130.698 52.591 ;
     RECT  7.815 52.591 130.698 52.637 ;
     RECT  131.688 36.751 135.126 57.173 ;
     RECT  7.815 52.637 127.89 58.559 ;
     RECT  16.272 58.559 127.89 61.457 ;
     RECT  16.272 61.457 124.866 62.311 ;
     RECT  125.604 61.457 127.89 62.311 ;
     RECT  128.628 52.637 130.698 64.355 ;
     RECT  16.272 62.311 127.89 64.824 ;
     RECT  29.34 64.824 29.862 65.551 ;
     RECT  29.34 65.551 30.294 65.596 ;
     RECT  29.304 65.596 30.294 65.611 ;
     RECT  122.58 64.824 127.89 65.821 ;
     RECT  29.052 65.611 30.294 66.136 ;
     RECT  117.108 64.824 117.126 66.379 ;
     RECT  118.26 65.611 118.278 66.379 ;
     RECT  16.272 64.824 27.846 66.631 ;
     RECT  128.628 64.355 129.834 66.631 ;
     RECT  130.68 64.355 130.698 66.631 ;
     RECT  54.288 64.824 54.306 66.715 ;
     RECT  88.488 66.667 88.506 66.715 ;
     RECT  122.076 65.821 127.89 66.715 ;
     RECT  128.628 66.631 130.698 66.715 ;
     RECT  122.076 66.715 130.698 66.749 ;
     RECT  38.088 64.824 38.106 66.829 ;
     RECT  32.76 66.829 32.778 66.901 ;
     RECT  34.776 66.757 34.794 66.901 ;
     RECT  40.608 66.757 40.626 66.901 ;
     RECT  111.276 66.715 111.294 66.901 ;
     RECT  106.596 66.901 106.614 66.907 ;
     RECT  16.272 66.631 27.918 66.929 ;
     RECT  34.776 66.901 34.974 66.929 ;
     RECT  40.536 66.901 40.626 66.929 ;
     RECT  39.708 66.715 39.726 66.943 ;
     RECT  40.536 66.929 40.59 66.943 ;
     RECT  45.036 66.715 45.054 66.943 ;
     RECT  50.94 64.824 50.958 66.943 ;
     RECT  88.488 66.715 88.578 66.943 ;
     RECT  108.792 66.715 110.25 66.943 ;
     RECT  29.052 66.136 30.546 67.019 ;
     RECT  45.036 66.943 45.705 67.019 ;
     RECT  50.94 66.943 51.105 67.019 ;
     RECT  54.18 66.715 54.306 67.019 ;
     RECT  88.488 66.943 88.905 67.019 ;
     RECT  111.276 66.901 111.366 67.019 ;
     RECT  36.144 66.829 36.162 67.027 ;
     RECT  37.548 66.829 38.106 67.027 ;
     RECT  39.708 66.943 40.59 67.027 ;
     RECT  99.615 66.943 99.705 67.027 ;
     RECT  102.636 67.003 102.654 67.055 ;
     RECT  106.344 66.907 106.614 67.055 ;
     RECT  107.496 66.715 107.874 67.055 ;
     RECT  108.792 66.943 110.505 67.055 ;
     RECT  72.615 66.943 72.705 67.063 ;
     RECT  36.144 67.027 36.45 67.085 ;
     RECT  39.564 67.027 40.59 67.085 ;
     RECT  106.56 67.055 106.614 67.091 ;
     RECT  37.476 67.027 38.106 67.099 ;
     RECT  47.52 66.901 47.538 67.127 ;
     RECT  70.704 67.063 70.722 67.163 ;
     RECT  37.476 67.099 38.286 67.171 ;
     RECT  99.615 67.027 100.278 67.171 ;
     RECT  107.604 67.055 107.874 67.171 ;
     RECT  37.404 67.171 38.286 67.199 ;
     RECT  42.768 67.099 42.786 67.199 ;
     RECT  34.815 66.929 34.974 67.213 ;
     RECT  45.288 67.019 45.705 67.213 ;
     RECT  51.015 67.019 51.105 67.213 ;
     RECT  56.415 66.943 56.505 67.213 ;
     RECT  61.815 66.943 61.905 67.213 ;
     RECT  67.215 66.943 67.305 67.213 ;
     RECT  72.468 67.063 72.705 67.213 ;
     RECT  78.015 66.943 78.105 67.213 ;
     RECT  83.415 66.943 83.505 67.213 ;
     RECT  88.815 67.019 88.905 67.213 ;
     RECT  94.215 66.943 94.305 67.213 ;
     RECT  105.015 66.943 105.105 67.213 ;
     RECT  108.9 67.055 110.505 67.213 ;
     RECT  115.815 66.943 115.905 67.213 ;
     RECT  121.215 66.943 121.305 67.213 ;
     RECT  122.076 66.749 127.89 67.213 ;
     RECT  99.615 67.171 100.458 67.229 ;
     RECT  78.015 67.213 78.297 67.243 ;
     RECT  49.212 66.379 49.23 67.261 ;
     RECT  43.992 67.171 44.01 67.277 ;
     RECT  102.816 67.171 102.834 67.277 ;
     RECT  106.56 67.091 106.578 67.277 ;
     RECT  107.604 67.171 108.09 67.277 ;
     RECT  108.9 67.213 110.697 67.277 ;
     RECT  49.14 67.261 49.23 67.289 ;
     RECT  70.992 67.243 71.01 67.289 ;
     RECT  76.392 66.955 76.41 67.289 ;
     RECT  77.904 67.243 78.297 67.289 ;
     RECT  36.144 67.085 36.162 67.325 ;
     RECT  37.404 67.199 37.71 67.325 ;
     RECT  45.288 67.213 45.897 67.325 ;
     RECT  48.024 67.171 48.078 67.325 ;
     RECT  49.14 67.289 49.158 67.361 ;
     RECT  31.932 66.955 31.95 67.397 ;
     RECT  32.688 66.901 32.778 67.405 ;
     RECT  40.215 67.085 40.59 67.433 ;
     RECT  48.06 67.325 48.078 67.441 ;
     RECT  121.215 67.213 127.89 67.441 ;
     RECT  28.512 67.243 28.53 67.469 ;
     RECT  72.468 67.213 72.897 67.469 ;
     RECT  32.148 67.405 32.778 67.559 ;
     RECT  48.06 67.441 48.582 67.559 ;
     RECT  119.268 66.139 119.286 67.559 ;
     RECT  48.564 67.559 48.582 67.595 ;
     RECT  108.936 67.277 110.697 67.595 ;
     RECT  32.652 67.559 32.778 67.711 ;
     RECT  120.852 67.441 127.89 67.711 ;
     RECT  109.116 67.595 110.697 67.757 ;
     RECT  109.116 67.757 109.134 67.805 ;
     RECT  110.088 67.757 110.697 67.805 ;
     RECT  32.652 67.711 32.958 67.829 ;
     RECT  120.348 67.711 127.89 67.829 ;
     RECT  37.476 67.325 37.71 67.865 ;
     RECT  32.94 67.829 32.958 67.973 ;
     RECT  37.512 67.865 37.71 68.099 ;
     RECT  37.692 68.099 37.71 68.243 ;
     RECT  131.688 57.173 134.262 68.819 ;
     RECT  117.108 66.379 118.278 69.061 ;
     RECT  117.108 69.061 118.674 69.179 ;
     RECT  119.628 68.917 119.646 69.295 ;
     RECT  119.484 69.295 119.646 69.331 ;
     RECT  119.124 69.331 119.646 69.547 ;
     RECT  120.852 67.829 127.89 69.547 ;
     RECT  119.124 69.547 127.89 69.899 ;
     RECT  119.124 69.899 119.142 69.989 ;
     RECT  119.088 70.375 119.106 70.529 ;
     RECT  120.096 69.899 127.89 70.835 ;
     RECT  119.988 70.951 120.006 71.069 ;
     RECT  16.272 66.929 27.702 71.221 ;
     RECT  16.272 71.221 28.062 71.261 ;
     RECT  120.852 70.835 127.89 71.261 ;
     RECT  121.032 71.261 127.89 71.879 ;
     RECT  29.304 67.019 30.546 72.571 ;
     RECT  29.304 72.571 31.014 72.841 ;
     RECT  29.304 72.841 31.194 72.907 ;
     RECT  121.068 71.879 127.89 72.955 ;
     RECT  29.304 72.907 31.338 72.959 ;
     RECT  71.028 73.195 71.046 73.229 ;
     RECT  120.852 72.955 127.89 73.229 ;
     RECT  29.304 72.959 31.194 73.301 ;
     RECT  70.704 73.309 70.722 73.421 ;
     RECT  7.815 58.559 15.318 73.471 ;
     RECT  7.668 73.471 15.318 73.565 ;
     RECT  119.592 73.531 119.61 73.769 ;
     RECT  120.996 73.229 127.89 74.075 ;
     RECT  120.996 74.075 124.326 74.107 ;
     RECT  70.164 74.107 70.182 74.309 ;
     RECT  120.816 74.107 124.326 74.309 ;
     RECT  16.272 71.261 27.702 74.623 ;
     RECT  68.609 74.459 68.641 74.668 ;
     RECT  68.616 74.668 68.634 74.669 ;
     RECT  119.772 73.921 119.862 74.971 ;
     RECT  119.772 74.971 119.934 75.119 ;
     RECT  16.272 74.623 27.738 75.199 ;
     RECT  120.852 74.309 124.326 75.271 ;
     RECT  16.272 75.199 28.062 75.775 ;
     RECT  29.304 73.301 30.546 75.775 ;
     RECT  119.952 75.499 119.97 75.835 ;
     RECT  120.708 75.271 124.326 75.835 ;
     RECT  119.952 75.835 124.326 75.929 ;
     RECT  120.852 75.929 124.326 76.001 ;
     RECT  119.952 75.929 120.042 76.073 ;
     RECT  16.272 75.775 30.546 76.157 ;
     RECT  5.364 76.987 5.382 77.279 ;
     RECT  3.816 77.323 3.834 77.325 ;
     RECT  3.813 77.325 3.837 77.352 ;
     RECT  3.816 77.352 3.834 77.357 ;
     RECT  120.852 76.001 124.218 77.459 ;
     RECT  115.815 67.213 116.097 77.515 ;
     RECT  128.628 66.749 130.698 77.515 ;
     RECT  128.628 77.515 130.986 77.701 ;
     RECT  132.015 68.819 134.262 77.701 ;
     RECT  115.815 77.515 116.298 77.819 ;
     RECT  128.628 77.701 134.262 77.855 ;
     RECT  29.304 76.157 30.546 78.241 ;
     RECT  119.952 76.073 119.97 78.331 ;
     RECT  120.996 77.459 124.218 78.331 ;
     RECT  29.304 78.241 30.69 78.511 ;
     RECT  29.124 78.511 31.05 78.619 ;
     RECT  119.952 78.331 124.218 78.665 ;
     RECT  119.952 78.665 124.146 78.899 ;
     RECT  28.98 78.619 31.05 78.935 ;
     RECT  28.98 78.935 30.87 79.205 ;
     RECT  2.415 2.413 2.697 79.285 ;
     RECT  28.98 79.205 30.402 79.285 ;
     RECT  2.34 79.285 2.697 79.321 ;
     RECT  2.304 79.321 2.697 79.519 ;
     RECT  2.304 79.519 3.87 79.591 ;
     RECT  5.688 79.447 5.706 79.591 ;
     RECT  16.272 76.157 28.062 79.591 ;
     RECT  28.944 79.285 30.402 79.591 ;
     RECT  117.108 69.179 118.278 79.681 ;
     RECT  2.304 79.591 4.554 79.717 ;
     RECT  5.508 79.591 5.706 79.745 ;
     RECT  117.108 79.681 118.962 79.745 ;
     RECT  2.304 79.717 4.734 79.753 ;
     RECT  5.508 79.745 5.526 79.753 ;
     RECT  2.304 79.753 5.526 79.781 ;
     RECT  120.132 78.899 124.146 79.819 ;
     RECT  125.064 74.075 127.89 79.819 ;
     RECT  2.304 79.781 5.166 80.123 ;
     RECT  119.952 79.819 127.89 80.221 ;
     RECT  16.272 79.591 30.402 80.249 ;
     RECT  119.7 80.221 127.89 80.249 ;
     RECT  2.304 80.123 3.834 80.285 ;
     RECT  16.272 80.249 30.33 80.285 ;
     RECT  118.26 79.745 118.962 80.285 ;
     RECT  120.636 80.249 127.89 80.285 ;
     RECT  119.7 80.249 119.826 80.381 ;
     RECT  128.628 77.855 130.914 80.401 ;
     RECT  2.304 80.285 3.186 80.555 ;
     RECT  4.716 80.123 5.166 80.555 ;
     RECT  119.7 80.381 119.718 80.555 ;
     RECT  128.628 80.401 131.274 80.555 ;
     RECT  4.716 80.555 4.734 80.627 ;
     RECT  117.108 79.745 117.126 80.663 ;
     RECT  7.815 73.565 15.318 80.699 ;
     RECT  6.804 80.563 6.822 80.761 ;
     RECT  6.768 80.761 6.822 80.897 ;
     RECT  115.815 77.819 116.097 80.923 ;
     RECT  3.996 80.941 4.014 81.059 ;
     RECT  112.896 80.923 112.914 81.059 ;
     RECT  115.524 80.923 116.097 81.059 ;
     RECT  114.624 65.563 114.642 81.067 ;
     RECT  120.636 80.285 124.146 81.163 ;
     RECT  16.272 80.285 29.97 81.211 ;
     RECT  113.652 81.067 113.67 81.211 ;
     RECT  114.48 81.067 114.642 81.211 ;
     RECT  115.815 81.059 116.097 81.211 ;
     RECT  118.26 80.285 118.278 81.211 ;
     RECT  6.804 80.897 6.822 81.239 ;
     RECT  16.272 81.211 30.258 81.329 ;
     RECT  113.652 81.211 114.642 81.329 ;
     RECT  29.088 81.329 30.258 81.337 ;
     RECT  113.652 81.329 113.67 81.365 ;
     RECT  115.815 81.211 116.334 81.365 ;
     RECT  119.916 81.163 124.146 81.365 ;
     RECT  2.304 80.555 2.934 81.445 ;
     RECT  3.672 81.409 3.69 81.445 ;
     RECT  29.088 81.337 30.33 81.481 ;
     RECT  114.48 81.329 114.642 81.481 ;
     RECT  2.304 81.445 3.69 81.509 ;
     RECT  2.304 81.509 3.51 81.599 ;
     RECT  29.088 81.481 30.474 81.751 ;
     RECT  118.26 81.211 118.998 81.835 ;
     RECT  119.916 81.365 124.11 81.835 ;
     RECT  118.26 81.835 124.11 81.869 ;
     RECT  29.088 81.751 30.978 81.985 ;
     RECT  114.48 81.481 114.858 81.985 ;
     RECT  115.815 81.365 116.154 81.985 ;
     RECT  3.492 81.599 3.51 82.139 ;
     RECT  29.088 81.985 31.05 82.139 ;
     RECT  125.064 80.285 127.89 82.171 ;
     RECT  29.088 82.139 30.978 82.291 ;
     RECT  16.272 81.329 28.062 82.381 ;
     RECT  28.944 82.291 30.978 82.381 ;
     RECT  119.052 81.869 119.214 82.409 ;
     RECT  120.168 81.869 124.11 82.411 ;
     RECT  124.92 82.171 127.89 82.411 ;
     RECT  119.052 82.409 119.07 82.445 ;
     RECT  120.168 82.411 127.89 82.445 ;
     RECT  114.48 81.985 116.154 82.561 ;
     RECT  114.48 82.561 116.298 82.651 ;
     RECT  120.168 82.445 124.11 82.651 ;
     RECT  2.304 81.599 2.697 82.715 ;
     RECT  114.228 82.651 116.298 82.751 ;
     RECT  115.488 82.751 116.298 82.831 ;
     RECT  114.228 82.751 114.606 82.949 ;
     RECT  115.488 82.831 116.478 83.065 ;
     RECT  118.26 81.869 118.278 83.065 ;
     RECT  115.488 83.065 116.586 83.101 ;
     RECT  117.432 82.291 117.45 83.101 ;
     RECT  118.26 83.065 118.782 83.101 ;
     RECT  119.88 82.651 124.11 83.219 ;
     RECT  117.432 83.101 118.782 83.255 ;
     RECT  115.488 83.101 116.658 83.371 ;
     RECT  117.432 83.255 118.026 83.371 ;
     RECT  118.764 83.255 118.782 83.399 ;
     RECT  76.104 83.101 76.122 83.515 ;
     RECT  75.78 83.515 76.122 83.561 ;
     RECT  16.272 82.381 30.978 83.731 ;
     RECT  125.064 82.445 127.89 83.731 ;
     RECT  16.272 83.731 31.122 83.759 ;
     RECT  81.18 83.563 81.198 83.759 ;
     RECT  114.588 82.949 114.606 83.759 ;
     RECT  31.104 83.759 31.122 83.789 ;
     RECT  76.104 83.561 76.122 83.789 ;
     RECT  16.272 83.759 30.186 83.795 ;
     RECT  32.58 83.731 32.598 83.803 ;
     RECT  120.852 83.219 124.11 83.903 ;
     RECT  115.488 83.371 118.026 83.939 ;
     RECT  48.924 83.947 48.942 83.948 ;
     RECT  34.815 67.213 35.097 83.987 ;
     RECT  40.215 67.433 40.497 83.987 ;
     RECT  45.615 67.325 45.897 83.987 ;
     RECT  51.015 67.213 51.297 83.987 ;
     RECT  56.415 67.213 56.697 83.987 ;
     RECT  61.815 67.213 62.097 83.987 ;
     RECT  67.215 67.213 67.497 83.987 ;
     RECT  72.615 67.469 72.897 83.987 ;
     RECT  78.015 67.289 78.297 83.987 ;
     RECT  83.415 67.213 83.697 83.987 ;
     RECT  88.815 67.213 89.097 83.987 ;
     RECT  94.215 67.213 94.497 83.987 ;
     RECT  99.615 67.229 99.897 83.987 ;
     RECT  105.015 67.213 105.297 83.987 ;
     RECT  110.415 67.805 110.697 83.987 ;
     RECT  16.272 83.795 30.006 84.029 ;
     RECT  32.256 83.803 32.598 84.029 ;
     RECT  115.488 83.939 117.99 84.029 ;
     RECT  16.272 84.029 29.934 84.065 ;
     RECT  115.488 84.029 115.905 84.065 ;
     RECT  116.712 84.029 116.73 84.065 ;
     RECT  117.612 84.029 117.99 84.065 ;
     RECT  48.917 83.948 48.949 84.067 ;
     RECT  119.844 83.911 119.862 84.109 ;
     RECT  121.068 83.903 124.11 84.173 ;
     RECT  119.664 84.109 119.862 84.181 ;
     RECT  82.044 83.707 82.062 84.209 ;
     RECT  119.664 84.181 120.078 84.209 ;
     RECT  16.272 84.065 28.494 84.221 ;
     RECT  29.415 84.065 29.934 84.221 ;
     RECT  32.58 84.029 32.598 84.221 ;
     RECT  49.104 84.181 49.122 84.221 ;
     RECT  29.415 84.221 29.505 84.257 ;
     RECT  34.815 83.987 34.905 84.257 ;
     RECT  40.215 83.987 40.305 84.257 ;
     RECT  45.615 83.987 45.705 84.257 ;
     RECT  51.015 83.987 51.105 84.257 ;
     RECT  56.415 83.987 56.505 84.257 ;
     RECT  61.815 83.987 61.905 84.257 ;
     RECT  67.215 83.987 67.305 84.257 ;
     RECT  72.615 83.987 72.705 84.257 ;
     RECT  78.015 83.987 78.105 84.257 ;
     RECT  83.415 83.987 83.505 84.257 ;
     RECT  88.815 83.987 88.905 84.257 ;
     RECT  94.215 83.987 94.305 84.257 ;
     RECT  99.615 83.987 99.705 84.257 ;
     RECT  105.015 83.987 105.105 84.257 ;
     RECT  110.415 83.987 110.505 84.257 ;
     RECT  115.815 84.065 115.905 84.257 ;
     RECT  121.068 84.173 121.305 84.257 ;
     RECT  117.612 84.065 117.63 84.413 ;
     RECT  125.028 83.731 127.89 84.991 ;
     RECT  128.628 80.555 130.95 84.991 ;
     RECT  121.068 84.257 121.086 85.517 ;
     RECT  122.076 84.173 124.11 85.517 ;
     RECT  125.028 84.991 130.95 85.801 ;
     RECT  16.272 84.221 28.062 86.4 ;
     RECT  120.06 84.209 120.078 86.4 ;
     RECT  122.148 85.517 124.11 86.4 ;
     RECT  16.272 86.4 124.11 86.611 ;
     RECT  125.028 85.801 131.022 86.611 ;
     RECT  16.272 86.611 131.022 86.881 ;
     RECT  16.272 86.881 131.202 87.151 ;
     RECT  132.015 77.855 134.262 87.151 ;
     RECT  7.815 80.699 15.066 87.385 ;
     RECT  16.272 87.151 134.262 87.385 ;
     RECT  7.815 87.385 134.262 87.413 ;
     RECT  135.108 57.173 135.126 87.917 ;
     RECT  7.815 87.413 131.058 88.231 ;
     RECT  132.015 87.413 134.262 88.231 ;
     RECT  7.815 88.231 134.262 88.541 ;
     RECT  7.815 88.541 130.194 89.851 ;
     RECT  131.004 88.541 134.262 89.851 ;
     RECT  7.815 89.851 134.262 90.581 ;
     RECT  7.815 90.581 131.058 90.749 ;
     RECT  125.064 90.749 131.058 91.561 ;
     RECT  7.815 90.749 124.11 92.189 ;
     RECT  5.004 92.101 5.022 92.371 ;
     RECT  6.516 92.407 6.534 92.641 ;
     RECT  4.788 92.371 5.022 92.749 ;
     RECT  6.516 92.641 6.894 92.785 ;
     RECT  7.815 92.189 124.074 93.149 ;
     RECT  2.415 82.715 2.697 93.829 ;
     RECT  7.815 93.149 124.002 93.917 ;
     RECT  123.984 93.917 124.002 94.205 ;
     RECT  7.815 93.917 123.102 94.397 ;
     RECT  124.848 91.561 131.058 94.441 ;
     RECT  124.236 94.441 131.058 94.493 ;
     RECT  124.236 94.493 124.254 94.589 ;
     RECT  6.516 92.785 6.93 94.631 ;
     RECT  132.015 90.581 134.262 94.639 ;
     RECT  2.415 93.829 2.898 94.711 ;
     RECT  125.1 94.493 131.058 94.865 ;
     RECT  123.696 94.939 123.714 95.009 ;
     RECT  125.136 94.865 131.058 95.107 ;
     RECT  7.815 94.397 122.904 95.179 ;
     RECT  125.136 95.107 131.094 95.179 ;
     RECT  132.015 94.639 134.334 95.179 ;
     RECT  4.788 92.749 5.67 95.449 ;
     RECT  125.136 95.179 134.334 95.837 ;
     RECT  2.415 94.711 3.33 95.881 ;
     RECT  4.176 95.449 5.67 95.881 ;
     RECT  125.208 95.837 134.334 96.287 ;
     RECT  124.236 95.521 124.254 96.317 ;
     RECT  7.815 95.179 123.102 96.421 ;
     RECT  125.928 96.287 134.334 96.755 ;
     RECT  7.815 96.421 123.714 96.827 ;
     RECT  125.928 96.755 126.897 97.025 ;
     RECT  127.764 96.755 134.334 97.085 ;
     RECT  126.468 97.025 126.897 97.277 ;
     RECT  126.54 97.277 126.897 97.565 ;
     RECT  128.16 97.085 134.334 97.645 ;
     RECT  135.18 97.411 135.198 97.645 ;
     RECT  128.16 97.645 135.198 97.661 ;
     RECT  7.815 96.827 123.678 97.681 ;
     RECT  128.16 97.661 128.286 97.709 ;
     RECT  129.42 97.661 135.198 97.709 ;
     RECT  7.815 97.681 124.254 97.754 ;
     RECT  129.492 97.709 135.198 97.799 ;
     RECT  129.492 97.799 129.51 97.835 ;
     RECT  128.268 97.709 128.286 97.907 ;
     RECT  130.284 97.799 135.198 97.915 ;
     RECT  130.284 97.915 135.234 98.069 ;
     RECT  130.284 98.069 135.162 98.105 ;
     RECT  130.284 98.105 134.586 98.249 ;
     RECT  130.284 98.249 132.462 98.339 ;
     RECT  130.284 98.339 130.302 98.375 ;
     RECT  132.015 98.339 132.354 98.375 ;
     RECT  133.308 98.249 134.586 98.375 ;
     RECT  131.112 98.339 131.202 98.429 ;
     RECT  133.308 98.375 134.298 98.447 ;
     RECT  124.092 97.754 124.254 98.491 ;
     RECT  131.184 98.429 131.202 98.519 ;
     RECT  133.416 98.447 134.298 98.609 ;
     RECT  125.46 98.491 125.478 98.621 ;
     RECT  133.956 98.609 134.298 98.645 ;
     RECT  124.056 98.491 124.254 98.717 ;
     RECT  133.956 98.645 134.19 98.987 ;
     RECT  7.815 97.754 122.994 99.031 ;
     RECT  134.064 98.987 134.19 99.149 ;
     RECT  134.064 99.149 134.082 99.185 ;
     RECT  124.092 98.717 124.254 99.197 ;
     RECT  124.092 99.197 124.218 99.293 ;
     RECT  124.128 99.293 124.218 99.485 ;
     RECT  7.815 99.031 123.102 99.697 ;
     RECT  124.272 99.931 124.29 99.967 ;
     RECT  125.388 99.661 125.406 99.967 ;
     RECT  124.272 99.967 125.406 100.039 ;
     RECT  124.272 100.039 125.586 100.157 ;
     RECT  125.388 100.157 125.586 100.229 ;
     RECT  124.272 100.157 124.29 100.301 ;
     RECT  7.815 99.697 123.138 100.507 ;
     RECT  7.815 100.507 124.254 100.733 ;
     RECT  125.388 100.229 125.406 100.841 ;
     RECT  7.815 100.733 124.146 101.075 ;
     RECT  125.532 100.987 125.55 101.075 ;
     RECT  125.568 101.275 125.586 101.309 ;
     RECT  7.815 101.075 122.904 101.851 ;
     RECT  123.66 101.075 124.146 101.851 ;
     RECT  7.815 101.851 124.146 102.043 ;
     RECT  125.568 102.811 125.586 103.469 ;
     RECT  7.815 102.043 124.254 104.081 ;
     RECT  125.316 104.161 125.334 104.251 ;
     RECT  125.136 104.251 125.334 104.387 ;
     RECT  125.532 104.593 125.55 104.635 ;
     RECT  7.815 104.081 124.146 104.855 ;
     RECT  125.532 104.635 125.802 105.395 ;
     RECT  123.66 104.855 124.146 105.499 ;
     RECT  125.424 105.781 125.442 105.907 ;
     RECT  125.352 105.907 125.442 105.935 ;
     RECT  7.815 104.855 122.904 106.459 ;
     RECT  123.66 105.499 124.254 106.459 ;
     RECT  125.352 105.935 125.37 106.475 ;
     RECT  125.568 107.035 125.586 107.789 ;
     RECT  7.815 106.459 124.254 108.473 ;
     RECT  125.568 108.679 125.586 108.715 ;
     RECT  125.352 108.715 125.586 109.255 ;
     RECT  125.244 109.255 125.586 109.409 ;
     RECT  7.815 108.473 124.182 109.627 ;
     RECT  125.388 110.335 125.406 110.395 ;
     RECT  125.388 110.395 125.586 110.489 ;
     RECT  125.532 110.489 125.586 110.795 ;
     RECT  7.815 109.627 124.254 110.867 ;
     RECT  125.568 110.795 125.586 111.335 ;
     RECT  7.815 110.867 124.182 111.931 ;
     RECT  125.244 112.081 125.262 112.217 ;
     RECT  7.815 111.931 124.254 113.639 ;
     RECT  125.568 112.795 125.586 113.729 ;
     RECT  125.532 113.851 125.55 113.947 ;
     RECT  125.424 113.947 125.55 114.035 ;
     RECT  125.424 114.035 125.442 114.313 ;
     RECT  125.352 114.313 125.442 114.611 ;
     RECT  7.815 113.639 124.146 114.961 ;
     RECT  7.815 114.961 124.254 115.133 ;
     RECT  125.532 114.961 125.55 115.501 ;
     RECT  7.815 115.133 123.786 115.867 ;
     RECT  125.352 115.501 125.55 116.041 ;
     RECT  125.208 116.041 125.55 116.155 ;
     RECT  125.208 116.155 125.802 116.195 ;
     RECT  125.352 116.195 125.802 116.429 ;
     RECT  7.815 115.867 124.146 116.573 ;
     RECT  125.352 116.429 125.37 116.735 ;
     RECT  8.82 116.573 124.146 117.115 ;
     RECT  125.712 117.211 125.73 117.509 ;
     RECT  8.82 117.115 124.254 117.887 ;
     RECT  125.532 117.979 125.55 118.459 ;
     RECT  125.532 118.459 125.586 118.589 ;
     RECT  8.82 117.887 124.146 118.741 ;
     RECT  125.532 118.589 125.55 118.741 ;
     RECT  8.82 118.741 124.182 118.843 ;
     RECT  8.82 118.843 124.254 119.039 ;
     RECT  125.46 118.741 125.55 119.056 ;
     RECT  2.415 95.881 5.67 119.173 ;
     RECT  6.516 94.631 6.894 119.173 ;
     RECT  124.884 119.056 125.55 119.273 ;
     RECT  125.352 119.273 125.55 119.669 ;
     RECT  8.82 119.039 124.146 120.011 ;
     RECT  17.496 120.011 124.146 120.091 ;
     RECT  125.424 119.669 125.55 120.091 ;
     RECT  125.424 120.091 125.586 120.209 ;
     RECT  17.496 120.091 124.254 120.515 ;
     RECT  125.424 120.209 125.55 120.631 ;
     RECT  2.415 119.173 6.894 120.793 ;
     RECT  125.388 120.631 125.55 121.243 ;
     RECT  125.388 121.243 125.694 121.289 ;
     RECT  125.532 121.289 125.694 121.595 ;
     RECT  17.496 120.515 122.904 121.915 ;
     RECT  123.66 120.515 124.254 121.915 ;
     RECT  125.532 121.595 125.55 122.135 ;
     RECT  17.496 121.915 124.254 122.981 ;
     RECT  125.352 123.997 125.37 124.105 ;
     RECT  125.316 124.105 125.37 124.123 ;
     RECT  17.568 122.981 124.254 124.253 ;
     RECT  125.316 124.123 125.55 124.331 ;
     RECT  17.568 124.253 123.75 124.541 ;
     RECT  125.388 124.331 125.55 124.951 ;
     RECT  123.66 124.541 123.75 125.083 ;
     RECT  125.388 124.951 125.586 125.105 ;
     RECT  17.568 124.541 122.904 125.275 ;
     RECT  123.66 125.083 124.254 125.275 ;
     RECT  17.568 125.275 124.254 125.951 ;
     RECT  17.568 125.951 123.75 126.329 ;
     RECT  125.388 125.105 125.406 126.419 ;
     RECT  17.568 126.329 123.246 127.464 ;
     RECT  123.228 127.464 123.246 127.499 ;
     RECT  30.6 128.236 30.618 128.251 ;
     RECT  44.532 127.464 44.55 128.506 ;
     RECT  49.356 128.623 49.374 129.091 ;
     RECT  17.568 127.464 29.358 129.403 ;
     RECT  30.168 128.251 31.194 129.403 ;
     RECT  108.504 129.403 110.106 129.433 ;
     RECT  35.748 129.403 36.846 129.451 ;
     RECT  43.164 129.403 43.182 129.451 ;
     RECT  108.324 129.433 110.322 129.451 ;
     RECT  46.944 129.403 46.962 129.469 ;
     RECT  46.836 129.469 46.962 129.505 ;
     RECT  51.696 129.469 51.714 129.505 ;
     RECT  33.444 129.403 34.002 129.541 ;
     RECT  34.74 129.403 34.758 129.541 ;
     RECT  46.8 129.505 46.962 129.541 ;
     RECT  44.532 128.506 44.658 129.547 ;
     RECT  33.444 129.541 34.794 129.583 ;
     RECT  35.568 129.451 37.026 129.583 ;
     RECT  38.664 129.403 39.726 129.583 ;
     RECT  40.572 129.403 40.59 129.583 ;
     RECT  44.532 129.547 45.126 129.583 ;
     RECT  46.152 129.541 46.962 129.583 ;
     RECT  51.696 129.505 51.75 129.583 ;
     RECT  104.868 129.541 104.886 129.583 ;
     RECT  108.252 129.451 110.322 129.583 ;
     RECT  51.015 129.583 51.75 129.595 ;
     RECT  37.764 129.403 37.782 129.631 ;
     RECT  38.664 129.583 40.59 129.631 ;
     RECT  49.356 129.091 50.058 129.631 ;
     RECT  102.744 129.547 102.762 129.631 ;
     RECT  106.488 129.469 106.506 129.631 ;
     RECT  106.488 129.631 106.65 129.643 ;
     RECT  42.084 129.403 42.102 129.659 ;
     RECT  61.815 129.583 61.905 129.667 ;
     RECT  33.444 129.583 37.026 129.691 ;
     RECT  42.984 129.451 43.182 129.691 ;
     RECT  104.868 129.583 105.105 129.691 ;
     RECT  33.228 129.691 37.026 129.695 ;
     RECT  48.816 129.631 50.058 129.703 ;
     RECT  98.604 129.469 98.622 129.703 ;
     RECT  106.416 129.643 106.65 129.703 ;
     RECT  107.424 129.631 107.442 129.703 ;
     RECT  33.228 129.695 35.097 129.731 ;
     RECT  42.948 129.691 43.182 129.731 ;
     RECT  58.716 129.667 58.734 129.739 ;
     RECT  61.776 129.667 61.905 129.739 ;
     RECT  65.304 129.631 65.322 129.739 ;
     RECT  42.984 129.731 43.182 129.775 ;
     RECT  48.816 129.703 50.094 129.775 ;
     RECT  50.868 129.595 51.75 129.775 ;
     RECT  94.215 129.583 94.305 129.775 ;
     RECT  100.836 129.739 100.854 129.775 ;
     RECT  44.532 129.583 46.962 129.803 ;
     RECT  36.324 129.695 37.026 129.811 ;
     RECT  37.764 129.631 40.59 129.811 ;
     RECT  60.264 129.541 60.282 129.811 ;
     RECT  61.704 129.739 61.905 129.811 ;
     RECT  100.836 129.775 101.142 129.811 ;
     RECT  106.416 129.703 107.442 129.811 ;
     RECT  108.252 129.583 110.505 129.811 ;
     RECT  41.868 129.775 41.886 129.821 ;
     RECT  56.415 129.583 56.505 129.853 ;
     RECT  61.632 129.811 61.905 129.853 ;
     RECT  62.676 129.505 62.694 129.853 ;
     RECT  67.215 129.583 67.305 129.853 ;
     RECT  72.615 129.583 72.705 129.853 ;
     RECT  78.015 129.583 78.105 129.853 ;
     RECT  83.415 129.583 83.505 129.853 ;
     RECT  88.815 129.583 88.905 129.853 ;
     RECT  99.615 129.583 99.705 129.853 ;
     RECT  104.868 129.691 105.138 129.853 ;
     RECT  106.416 129.811 110.505 129.853 ;
     RECT  115.815 129.583 115.905 129.853 ;
     RECT  121.215 129.583 121.305 129.853 ;
     RECT  36.324 129.811 40.662 129.869 ;
     RECT  48.816 129.775 51.75 129.869 ;
     RECT  17.568 129.403 31.194 129.901 ;
     RECT  32.004 129.739 32.022 129.901 ;
     RECT  95.688 129.775 95.706 129.901 ;
     RECT  100.728 129.811 101.538 129.901 ;
     RECT  102.6 129.631 102.762 129.901 ;
     RECT  104.868 129.853 105.297 129.901 ;
     RECT  42.984 129.775 43.29 129.929 ;
     RECT  60.192 129.811 60.282 129.929 ;
     RECT  93.168 129.775 93.186 129.929 ;
     RECT  95.328 129.901 95.706 129.929 ;
     RECT  57.744 129.739 57.762 129.937 ;
     RECT  17.568 129.901 32.022 129.965 ;
     RECT  36.324 129.869 37.602 129.965 ;
     RECT  43.128 129.929 43.29 129.965 ;
     RECT  44.532 129.803 46.494 129.965 ;
     RECT  47.268 129.901 47.286 129.965 ;
     RECT  95.328 129.929 95.562 129.965 ;
     RECT  100.728 129.901 102.762 129.965 ;
     RECT  106.416 129.853 110.697 129.965 ;
     RECT  48.852 129.869 51.75 129.973 ;
     RECT  57.636 129.937 57.762 129.973 ;
     RECT  58.716 129.739 58.806 129.973 ;
     RECT  99.615 129.853 99.897 129.973 ;
     RECT  101.52 129.965 102.762 129.973 ;
     RECT  38.412 129.869 40.662 130.001 ;
     RECT  75.42 129.739 75.438 130.009 ;
     RECT  83.415 129.853 83.697 130.009 ;
     RECT  90.612 129.973 90.63 130.009 ;
     RECT  39.6 130.001 40.662 130.013 ;
     RECT  104.796 129.901 105.354 130.027 ;
     RECT  32.004 129.965 32.022 130.045 ;
     RECT  66.168 129.541 66.186 130.045 ;
     RECT  86.652 129.973 86.67 130.045 ;
     RECT  88.815 129.853 89.097 130.045 ;
     RECT  94.215 129.775 94.554 130.045 ;
     RECT  99.615 129.973 100.35 130.045 ;
     RECT  36.324 129.965 37.026 130.073 ;
     RECT  47.304 129.973 47.322 130.073 ;
     RECT  48.852 129.973 51.858 130.075 ;
     RECT  40.215 130.013 40.662 130.081 ;
     RECT  44.532 129.965 44.658 130.081 ;
     RECT  86.652 130.045 86.742 130.081 ;
     RECT  90.612 130.009 90.738 130.081 ;
     RECT  107.424 129.965 110.697 130.081 ;
     RECT  36.396 130.073 37.026 130.109 ;
     RECT  90.54 130.081 90.738 130.109 ;
     RECT  98.604 129.703 98.694 130.109 ;
     RECT  106.416 129.965 106.686 130.109 ;
     RECT  90.54 130.109 90.702 130.123 ;
     RECT  99.504 130.045 100.35 130.123 ;
     RECT  36.396 130.109 36.522 130.157 ;
     RECT  48.852 130.075 51.894 130.171 ;
     RECT  65.196 129.739 65.322 130.171 ;
     RECT  93.492 130.045 94.554 130.171 ;
     RECT  95.328 129.965 95.454 130.171 ;
     RECT  38.412 130.001 38.646 130.199 ;
     RECT  43.704 130.081 44.658 130.199 ;
     RECT  61.632 129.853 62.694 130.199 ;
     RECT  75.42 130.009 75.618 130.199 ;
     RECT  93.492 130.171 95.454 130.199 ;
     RECT  101.52 129.973 103.122 130.199 ;
     RECT  107.424 130.081 111.006 130.199 ;
     RECT  65.016 130.171 65.322 130.205 ;
     RECT  48.852 130.171 52.578 130.207 ;
     RECT  88.632 130.045 89.097 130.207 ;
     RECT  104.112 130.027 105.57 130.207 ;
     RECT  36.396 130.157 36.414 130.235 ;
     RECT  38.412 130.199 38.43 130.235 ;
     RECT  40.215 130.081 41.058 130.235 ;
     RECT  48.852 130.207 52.686 130.235 ;
     RECT  75.42 130.199 75.438 130.235 ;
     RECT  90.252 130.123 90.702 130.235 ;
     RECT  94.215 130.199 95.454 130.235 ;
     RECT  104.04 130.207 105.57 130.235 ;
     RECT  49.356 130.235 52.686 130.253 ;
     RECT  87.624 130.207 87.642 130.253 ;
     RECT  104.04 130.235 105.39 130.253 ;
     RECT  44.064 130.199 44.658 130.271 ;
     RECT  98.964 130.123 100.35 130.271 ;
     RECT  107.784 130.199 110.697 130.271 ;
     RECT  61.632 130.199 62.097 130.279 ;
     RECT  32.004 130.045 32.814 130.307 ;
     RECT  107.82 130.271 110.697 130.307 ;
     RECT  55.548 129.631 55.638 130.315 ;
     RECT  56.415 129.853 56.697 130.315 ;
     RECT  57.636 129.973 58.806 130.315 ;
     RECT  32.04 130.307 32.814 130.343 ;
     RECT  90.54 130.235 90.702 130.343 ;
     RECT  94.215 130.235 95.346 130.343 ;
     RECT  101.916 130.199 103.122 130.343 ;
     RECT  56.415 130.315 58.806 130.349 ;
     RECT  55.224 130.315 55.638 130.351 ;
     RECT  56.415 130.349 56.697 130.351 ;
     RECT  57.636 130.349 58.806 130.351 ;
     RECT  65.196 130.205 65.322 130.351 ;
     RECT  66.168 130.045 66.402 130.351 ;
     RECT  88.596 130.207 89.097 130.351 ;
     RECT  104.04 130.253 105.354 130.351 ;
     RECT  106.416 130.109 106.65 130.351 ;
     RECT  61.416 130.279 62.097 130.379 ;
     RECT  94.215 130.343 94.662 130.379 ;
     RECT  107.856 130.307 110.697 130.379 ;
     RECT  88.416 130.351 89.097 130.441 ;
     RECT  88.38 130.441 89.097 130.459 ;
     RECT  32.04 130.343 32.13 130.469 ;
     RECT  47.448 130.075 47.898 130.469 ;
     RECT  49.356 130.253 52.47 130.469 ;
     RECT  86.652 130.081 86.778 130.469 ;
     RECT  90.684 130.343 90.702 130.469 ;
     RECT  98.964 130.271 100.314 130.469 ;
     RECT  106.344 130.351 106.65 130.469 ;
     RECT  108.324 130.379 110.697 130.469 ;
     RECT  47.448 130.469 47.466 130.493 ;
     RECT  54.504 130.351 56.697 130.505 ;
     RECT  87.912 130.459 89.097 130.505 ;
     RECT  108.864 130.469 109.242 130.505 ;
     RECT  45.615 129.965 46.494 130.541 ;
     RECT  49.356 130.469 51.822 130.541 ;
     RECT  86.76 130.469 86.778 130.541 ;
     RECT  88.38 130.505 89.097 130.541 ;
     RECT  103.896 130.351 105.354 130.541 ;
     RECT  102.096 130.343 103.122 130.555 ;
     RECT  103.896 130.541 103.914 130.555 ;
     RECT  65.196 130.351 66.474 130.577 ;
     RECT  99.615 130.469 100.314 130.577 ;
     RECT  106.344 130.469 106.362 130.577 ;
     RECT  65.88 130.577 66.474 130.585 ;
     RECT  67.215 129.853 67.497 130.585 ;
     RECT  17.568 129.965 31.266 130.613 ;
     RECT  53.64 130.351 53.658 130.613 ;
     RECT  102.096 130.555 103.914 130.613 ;
     RECT  78.015 129.853 78.297 130.621 ;
     RECT  45.615 130.541 46.35 130.649 ;
     RECT  50.796 130.541 51.822 130.649 ;
     RECT  54.504 130.505 55.566 130.649 ;
     RECT  57.636 130.351 59.166 130.649 ;
     RECT  104.796 130.541 105.354 130.649 ;
     RECT  54.504 130.649 55.458 130.739 ;
     RECT  58.284 130.649 59.166 130.739 ;
     RECT  60.516 130.555 60.534 130.739 ;
     RECT  61.74 130.379 62.097 130.739 ;
     RECT  65.88 130.585 67.497 130.739 ;
     RECT  102.096 130.613 103.878 130.739 ;
     RECT  104.94 130.649 105.354 130.739 ;
     RECT  78.015 130.621 78.822 130.775 ;
     RECT  82.8 130.009 83.697 130.775 ;
     RECT  88.416 130.541 89.097 130.775 ;
     RECT  102.096 130.739 103.086 130.775 ;
     RECT  54.504 130.739 54.522 130.811 ;
     RECT  58.716 130.739 59.166 130.811 ;
     RECT  102.672 130.775 103.086 130.811 ;
     RECT  78.015 130.775 78.297 130.819 ;
     RECT  33.696 129.731 35.097 130.847 ;
     RECT  65.88 130.739 66.042 130.847 ;
     RECT  105.015 130.739 105.354 130.847 ;
     RECT  74.736 130.621 74.754 130.855 ;
     RECT  58.716 130.811 58.734 130.883 ;
     RECT  66.024 130.847 66.042 130.883 ;
     RECT  74.664 130.855 74.754 130.883 ;
     RECT  88.74 130.775 89.097 130.883 ;
     RECT  77.832 130.819 78.297 130.919 ;
     RECT  55.44 130.739 55.458 131.009 ;
     RECT  83.016 130.775 83.697 131.009 ;
     RECT  102.888 130.811 103.086 131.009 ;
     RECT  103.86 130.739 103.878 131.009 ;
     RECT  74.664 130.883 74.682 131.045 ;
     RECT  79.092 130.855 79.11 131.045 ;
     RECT  102.888 131.009 102.906 131.045 ;
     RECT  33.12 130.891 33.138 132.601 ;
     RECT  34.164 130.847 35.097 132.601 ;
     RECT  44.532 130.271 44.658 133.147 ;
     RECT  33.12 132.601 35.097 133.681 ;
     RECT  33.012 133.681 35.097 135.031 ;
     RECT  17.568 130.613 31.05 137.335 ;
     RECT  32.04 130.469 32.058 138.605 ;
     RECT  17.568 137.335 31.194 138.991 ;
     RECT  35.892 135.301 35.91 139.351 ;
     RECT  33.012 135.031 35.154 139.657 ;
     RECT  35.892 139.351 36.342 139.657 ;
     RECT  1.332 139.081 1.35 139.661 ;
     RECT  33.012 139.657 36.342 139.955 ;
     RECT  2.415 120.793 6.93 140.071 ;
     RECT  34.164 139.955 36.342 140.305 ;
     RECT  37.188 138.721 37.206 140.305 ;
     RECT  33.012 139.955 33.39 141.655 ;
     RECT  32.76 141.655 33.39 141.781 ;
     RECT  1.116 141.889 1.134 143.069 ;
     RECT  32.508 141.781 33.39 143.131 ;
     RECT  47.88 134.779 47.898 143.311 ;
     RECT  2.376 140.071 6.93 143.509 ;
     RECT  45.615 130.649 45.897 143.947 ;
     RECT  8.82 120.011 16.47 144.235 ;
     RECT  17.568 138.991 31.23 144.235 ;
     RECT  8.82 144.235 31.23 144.275 ;
     RECT  34.164 140.305 37.206 144.283 ;
     RECT  44.532 133.147 44.694 144.319 ;
     RECT  43.92 144.319 44.694 144.331 ;
     RECT  42.768 144.283 42.786 144.347 ;
     RECT  43.812 144.331 44.694 144.379 ;
     RECT  45.612 143.947 45.897 144.379 ;
     RECT  1.116 144.211 1.134 144.481 ;
     RECT  2.304 143.509 6.93 144.481 ;
     RECT  17.568 144.275 31.23 144.517 ;
     RECT  32.256 143.131 33.39 144.517 ;
     RECT  43.812 144.379 45.897 144.625 ;
     RECT  17.568 144.517 33.39 144.653 ;
     RECT  34.164 144.283 37.638 144.661 ;
     RECT  41.868 144.235 41.886 144.751 ;
     RECT  41.868 144.751 42.534 144.779 ;
     RECT  34.164 144.661 37.746 144.959 ;
     RECT  42.372 144.779 42.534 145.049 ;
     RECT  42.516 145.049 42.534 145.085 ;
     RECT  43.812 144.625 46.026 145.165 ;
     RECT  1.116 144.481 6.93 145.277 ;
     RECT  40.215 130.235 40.497 145.387 ;
     RECT  40.215 145.387 40.662 145.399 ;
     RECT  39.672 145.399 40.662 145.435 ;
     RECT  38.916 145.291 38.934 145.561 ;
     RECT  46.944 145.471 46.962 145.579 ;
     RECT  43.308 145.165 46.026 145.627 ;
     RECT  46.836 145.579 46.962 145.627 ;
     RECT  34.452 144.959 37.746 145.705 ;
     RECT  38.844 145.561 38.934 145.705 ;
     RECT  34.452 145.705 38.934 145.741 ;
     RECT  39.672 145.435 41.094 145.741 ;
     RECT  43.308 145.627 46.962 145.903 ;
     RECT  47.7 143.311 47.898 145.903 ;
     RECT  1.116 145.277 1.134 145.949 ;
     RECT  41.832 145.939 41.85 145.975 ;
     RECT  41.832 145.975 42.318 146.101 ;
     RECT  41.832 146.101 42.498 146.129 ;
     RECT  34.452 145.741 41.094 146.173 ;
     RECT  43.308 145.903 47.898 146.203 ;
     RECT  34.452 146.173 41.202 146.281 ;
     RECT  41.94 146.129 42.498 146.281 ;
     RECT  43.308 146.203 48.15 146.281 ;
     RECT  2.415 145.277 6.93 146.371 ;
     RECT  41.94 146.281 48.15 146.551 ;
     RECT  34.2 146.281 41.202 146.939 ;
     RECT  41.94 146.551 48.258 147.019 ;
     RECT  1.692 146.371 6.93 147.053 ;
     RECT  8.82 144.275 16.47 147.055 ;
     RECT  17.64 144.653 33.39 147.055 ;
     RECT  41.94 147.019 48.474 147.067 ;
     RECT  49.356 130.541 50.058 147.067 ;
     RECT  34.452 146.939 41.202 147.091 ;
     RECT  41.94 147.067 50.058 147.091 ;
     RECT  8.82 147.055 33.39 147.209 ;
     RECT  14.22 147.209 33.39 147.353 ;
     RECT  14.688 147.353 33.39 147.587 ;
     RECT  51.015 130.649 51.297 147.595 ;
     RECT  1.98 147.053 6.93 147.631 ;
     RECT  7.815 116.573 8.097 147.631 ;
     RECT  34.452 147.091 50.058 147.643 ;
     RECT  50.868 147.595 51.297 147.643 ;
     RECT  8.82 147.209 13.497 147.659 ;
     RECT  14.688 147.587 16.542 147.869 ;
     RECT  8.892 147.659 13.497 147.893 ;
     RECT  1.98 147.631 8.097 147.901 ;
     RECT  17.64 147.587 33.39 147.901 ;
     RECT  34.452 147.643 51.297 147.901 ;
     RECT  17.64 147.901 51.297 148.019 ;
     RECT  14.688 147.869 15.462 148.157 ;
     RECT  14.688 148.157 14.922 148.163 ;
     RECT  17.64 148.019 33.354 148.289 ;
     RECT  14.868 148.163 14.922 148.397 ;
     RECT  16.524 147.869 16.542 148.603 ;
     RECT  17.64 148.289 33.102 148.603 ;
     RECT  1.8 147.901 8.097 148.631 ;
     RECT  34.164 148.019 51.297 148.685 ;
     RECT  1.8 148.631 6.102 148.703 ;
     RECT  6.948 148.631 8.097 148.733 ;
     RECT  1.8 148.703 5.778 148.739 ;
     RECT  9.18 147.893 13.497 148.787 ;
     RECT  34.704 148.685 51.297 148.787 ;
     RECT  56.415 130.505 56.697 148.787 ;
     RECT  61.815 130.739 62.097 148.787 ;
     RECT  67.215 130.739 67.497 148.787 ;
     RECT  72.615 129.853 72.897 148.787 ;
     RECT  78.015 130.919 78.297 148.787 ;
     RECT  83.415 131.009 83.697 148.787 ;
     RECT  88.815 130.883 89.097 148.787 ;
     RECT  94.215 130.379 94.497 148.787 ;
     RECT  99.615 130.577 99.897 148.787 ;
     RECT  105.015 130.847 105.297 148.787 ;
     RECT  110.415 130.469 110.697 148.787 ;
     RECT  115.815 129.853 116.097 148.787 ;
     RECT  121.215 129.853 121.497 148.787 ;
     RECT  126.615 97.565 126.897 148.787 ;
     RECT  132.015 98.375 132.297 148.787 ;
     RECT  137.415 2.413 137.697 148.787 ;
     RECT  142.815 2.413 143.097 148.787 ;
     RECT  148.215 2.413 148.497 148.787 ;
     RECT  34.704 148.787 51.174 148.865 ;
     RECT  7.524 148.733 8.097 148.901 ;
     RECT  16.524 148.603 33.102 148.901 ;
     RECT  14.868 148.397 14.886 148.909 ;
     RECT  1.8 148.739 5.742 148.937 ;
     RECT  7.815 148.901 8.097 148.981 ;
     RECT  9.18 148.787 13.41 148.981 ;
     RECT  7.815 148.981 13.41 149.057 ;
     RECT  56.415 148.787 56.505 149.057 ;
     RECT  61.815 148.787 61.905 149.057 ;
     RECT  67.215 148.787 67.305 149.057 ;
     RECT  72.615 148.787 72.705 149.057 ;
     RECT  78.015 148.787 78.105 149.057 ;
     RECT  83.415 148.787 83.505 149.057 ;
     RECT  88.815 148.787 88.905 149.057 ;
     RECT  94.215 148.787 94.305 149.057 ;
     RECT  99.615 148.787 99.705 149.057 ;
     RECT  105.015 148.787 105.105 149.057 ;
     RECT  110.415 148.787 110.505 149.057 ;
     RECT  115.815 148.787 115.905 149.057 ;
     RECT  121.215 148.787 121.305 149.057 ;
     RECT  126.615 148.787 126.705 149.057 ;
     RECT  132.015 148.787 132.105 149.057 ;
     RECT  137.415 148.787 137.505 149.057 ;
     RECT  142.815 148.787 142.905 149.057 ;
     RECT  148.215 148.787 148.305 149.057 ;
     RECT  7.992 149.057 13.41 149.135 ;
     RECT  7.992 149.135 12.474 149.171 ;
     RECT  17.064 148.901 33.102 149.243 ;
     RECT  7.992 149.171 12.33 149.261 ;
     RECT  17.064 149.243 32.814 149.324 ;
     RECT  1.8 148.937 5.49 149.357 ;
     RECT  19.224 149.324 32.814 149.357 ;
     RECT  49.752 148.865 51.174 149.357 ;
     RECT  27.324 149.357 32.814 149.369 ;
     RECT  34.704 148.865 48.942 149.369 ;
     RECT  17.064 149.324 18.27 149.639 ;
     RECT  17.064 149.639 17.19 149.645 ;
     RECT  27.324 149.369 30.222 149.645 ;
     RECT  34.272 149.647 34.29 149.683 ;
     RECT  14.22 148.909 14.886 149.707 ;
     RECT  15.624 149.515 15.642 149.707 ;
     RECT  14.22 149.707 15.642 149.741 ;
     RECT  14.22 149.741 15.534 149.837 ;
     RECT  35.532 149.369 48.942 149.933 ;
     RECT  16.452 150.043 16.47 150.139 ;
     RECT  16.344 150.139 16.47 150.173 ;
     RECT  19.224 149.357 26.37 150.221 ;
     RECT  16.344 150.173 16.362 150.317 ;
     RECT  19.224 150.221 25.218 150.365 ;
     RECT  8.676 149.261 12.33 150.413 ;
     RECT  27.324 149.645 29.898 150.427 ;
     RECT  3.384 149.357 5.49 150.461 ;
     RECT  35.568 149.933 48.87 150.461 ;
     RECT  49.752 149.357 50.958 150.461 ;
     RECT  35.568 150.461 43.002 150.485 ;
     RECT  22.176 150.365 25.218 150.509 ;
     RECT  31.356 149.369 32.814 150.509 ;
     RECT  35.568 150.485 38.79 150.509 ;
     RECT  39.564 150.485 43.002 150.509 ;
     RECT  44.028 150.461 48.87 150.509 ;
     RECT  49.752 150.461 50.67 150.509 ;
     RECT  50.364 150.509 50.67 150.521 ;
     RECT  8.892 150.413 12.33 150.557 ;
     RECT  27.324 150.427 30.114 150.557 ;
     RECT  34.2 149.683 34.29 150.557 ;
     RECT  39.78 150.509 41.346 150.557 ;
     RECT  46.08 150.509 48.87 150.557 ;
     RECT  18.216 149.639 18.27 150.605 ;
     RECT  32.04 150.509 32.814 150.605 ;
     RECT  35.568 150.509 37.35 150.605 ;
     RECT  38.124 150.509 38.61 150.605 ;
     RECT  39.996 150.557 41.166 150.605 ;
     RECT  42.156 150.509 43.002 150.605 ;
     RECT  44.208 150.509 45.09 150.605 ;
     RECT  47.376 150.557 47.574 150.605 ;
     RECT  14.22 149.837 15.174 150.653 ;
     RECT  36.432 150.605 37.35 150.653 ;
     RECT  44.244 150.605 44.874 150.653 ;
     RECT  48.564 150.557 48.87 150.653 ;
     RECT  26.064 150.221 26.37 150.701 ;
     RECT  48.744 150.653 48.87 150.701 ;
     RECT  37.26 150.653 37.35 150.749 ;
     RECT  44.244 150.653 44.262 150.749 ;
     RECT  19.224 150.365 21.402 150.763 ;
     RECT  32.04 150.605 32.058 150.797 ;
     RECT  48.744 150.701 48.762 150.797 ;
     RECT  11.088 150.557 12.33 150.845 ;
     RECT  32.796 150.605 32.814 150.845 ;
     RECT  14.256 150.653 15.174 150.859 ;
     RECT  11.304 150.845 12.33 150.893 ;
     RECT  18.828 150.763 21.402 150.893 ;
     RECT  22.176 150.509 25.038 150.893 ;
     RECT  8.892 150.557 10.35 150.899 ;
     RECT  35.496 150.811 35.514 150.907 ;
     RECT  3.384 150.461 5.382 150.941 ;
     RECT  8.892 150.899 10.278 150.941 ;
     RECT  22.176 150.893 24.93 150.941 ;
     RECT  50.364 150.521 50.418 150.941 ;
     RECT  27.324 150.557 29.934 150.955 ;
     RECT  4.464 150.941 5.382 150.989 ;
     RECT  23.652 150.941 24.93 150.989 ;
     RECT  36.432 150.653 36.45 150.989 ;
     RECT  37.332 150.749 37.35 150.989 ;
     RECT  42.192 150.605 43.002 150.989 ;
     RECT  6.84 150.091 6.858 151.003 ;
     RECT  8.892 150.941 10.242 151.037 ;
     RECT  17.568 150.667 17.586 151.037 ;
     RECT  35.28 150.907 35.514 151.037 ;
     RECT  40.356 150.605 41.166 151.037 ;
     RECT  42.192 150.989 42.21 151.037 ;
     RECT  50.364 150.941 50.382 151.037 ;
     RECT  14.256 150.859 15.642 151.051 ;
     RECT  1.8 149.357 2.574 151.085 ;
     RECT  3.384 150.941 3.402 151.085 ;
     RECT  4.68 150.989 5.382 151.085 ;
     RECT  8.892 151.037 8.91 151.085 ;
     RECT  9.828 151.037 10.242 151.085 ;
     RECT  11.376 150.893 12.33 151.085 ;
     RECT  14.256 151.051 16.218 151.085 ;
     RECT  18.828 150.893 19.854 151.085 ;
     RECT  20.7 150.893 21.402 151.085 ;
     RECT  22.176 150.941 22.698 151.085 ;
     RECT  23.652 150.989 24.174 151.085 ;
     RECT  24.912 150.989 24.93 151.085 ;
     RECT  26.568 150.955 29.934 151.085 ;
     RECT  42.984 150.989 43.002 151.085 ;
     RECT  46.548 150.557 46.566 151.085 ;
     RECT  14.256 151.085 14.274 151.097 ;
     RECT  16.2 151.085 16.218 151.097 ;
     RECT  6.84 151.003 7.578 151.133 ;
     RECT  19.224 151.085 19.242 151.133 ;
     RECT  22.68 151.085 22.698 151.133 ;
     RECT  29.232 151.085 29.25 151.133 ;
     RECT  33.084 151.003 33.678 151.133 ;
     RECT  47.376 150.605 47.394 151.133 ;
     RECT  10.224 151.085 10.242 151.169 ;
     RECT  33.66 151.133 33.678 151.169 ;
     RECT  6.84 151.133 6.858 151.181 ;
     RECT  12.204 151.085 12.33 151.181 ;
     RECT  27.684 151.085 27.702 151.181 ;
     RECT  30.78 151.051 30.798 151.181 ;
     RECT  35.424 151.037 35.442 151.181 ;
    LAYER M4 ;
     RECT  0.06 80.592 0.227 81.288 ;
     RECT  0.227 80.688 0.275 81.288 ;
     RECT  0.275 80.688 0.323 80.904 ;
     RECT  0.323 80.88 0.371 80.904 ;
     RECT  0.709 144.24 0.805 144.264 ;
     RECT  0.805 144.24 0.997 144.312 ;
     RECT  1.093 143.04 1.145 143.064 ;
     RECT  0.901 145.92 1.145 145.944 ;
     RECT  1.285 139.632 1.361 139.656 ;
     RECT  0.997 144.24 1.381 144.408 ;
     RECT  1.381 144.24 1.573 144.792 ;
     RECT  1.477 147.024 1.861 147.048 ;
     RECT  1.765 151.056 2.053 151.08 ;
     RECT  2.197 81.696 2.245 81.72 ;
     RECT  2.245 80.352 2.293 82.104 ;
     RECT  2.053 151.008 2.293 151.08 ;
     RECT  2.293 79.728 2.408 82.68 ;
     RECT  1.189 141.264 2.408 141.288 ;
     RECT  1.573 144.24 2.408 145.272 ;
     RECT  1.861 147.024 2.408 147.096 ;
     RECT  2.408 2.148 2.512 149.052 ;
     RECT  2.512 2.418 2.704 149.052 ;
     RECT  2.704 79.776 2.867 80.088 ;
     RECT  2.704 144.768 2.867 145.32 ;
     RECT  2.293 150.864 2.867 151.08 ;
     RECT  2.704 146.304 2.915 149.052 ;
     RECT  2.915 148.176 2.981 149.052 ;
     RECT  2.981 148.464 3.013 149.052 ;
     RECT  2.704 141.264 3.053 141.288 ;
     RECT  3.013 148.464 3.089 149.352 ;
     RECT  2.915 146.304 3.233 147.096 ;
     RECT  3.493 149.904 3.665 149.928 ;
     RECT  2.867 80.064 3.737 80.088 ;
     RECT  3.805 77.328 3.875 77.352 ;
     RECT  3.233 146.304 3.917 147 ;
     RECT  2.867 145.296 3.971 145.32 ;
     RECT  3.917 146.928 4.261 147 ;
     RECT  4.261 146.928 4.453 147.048 ;
     RECT  3.089 148.464 4.453 148.776 ;
     RECT  4.165 149.856 4.645 149.88 ;
     RECT  4.453 146.928 4.673 148.776 ;
     RECT  4.673 147.024 4.709 148.776 ;
     RECT  4.921 79.776 5.077 79.8 ;
     RECT  5.077 79.776 5.123 80.04 ;
     RECT  4.561 144.24 5.123 144.264 ;
     RECT  2.867 150.912 5.393 151.08 ;
     RECT  4.645 149.856 5.413 149.928 ;
     RECT  5.353 76.992 5.699 77.016 ;
     RECT  4.709 147.6 5.797 148.776 ;
     RECT  5.413 149.856 5.797 150.888 ;
     RECT  5.797 147.6 6.469 150.888 ;
     RECT  6.541 3.312 6.613 3.336 ;
     RECT  6.469 147.6 6.661 151.08 ;
     RECT  6.613 2.928 6.757 3.336 ;
     RECT  6.757 2.928 6.793 3.432 ;
     RECT  6.793 2.928 6.829 4.152 ;
     RECT  6.661 147.264 6.829 151.08 ;
     RECT  6.829 2.928 6.853 4.248 ;
     RECT  6.853 2.304 6.901 4.248 ;
     RECT  6.901 2.304 7.153 5.16 ;
     RECT  7.153 2.304 7.297 5.352 ;
     RECT  7.297 2.304 7.477 5.736 ;
     RECT  6.793 6.768 7.477 6.792 ;
     RECT  7.477 2.304 7.808 6.792 ;
     RECT  7.621 73.536 7.808 73.56 ;
     RECT  5.123 80.016 7.808 80.04 ;
     RECT  6.577 93.216 7.808 93.24 ;
     RECT  6.829 147.264 7.808 151.176 ;
     RECT  7.669 0.144 7.909 0.168 ;
     RECT  7.808 2.148 7.912 151.176 ;
     RECT  7.912 2.256 8.104 151.176 ;
     RECT  8.104 2.256 8.201 7.464 ;
     RECT  7.909 0.096 8.291 0.168 ;
     RECT  8.201 2.304 8.705 7.464 ;
     RECT  8.104 116.544 9.133 117.144 ;
     RECT  8.104 119.376 9.133 119.4 ;
     RECT  8.104 8.544 9.137 8.568 ;
     RECT  9.133 119.376 9.173 119.496 ;
     RECT  8.705 2.304 9.281 7.032 ;
     RECT  9.133 72.96 9.299 72.984 ;
     RECT  8.291 0.096 9.445 0.12 ;
     RECT  9.397 41.376 9.445 41.4 ;
     RECT  9.133 116.544 9.445 117.288 ;
     RECT  8.104 39.216 9.493 39.24 ;
     RECT  8.104 114.336 9.565 114.36 ;
     RECT  9.541 31.392 9.589 31.416 ;
     RECT  9.637 28.128 9.709 28.152 ;
     RECT  9.445 0.096 9.733 0.264 ;
     RECT  9.745 16.944 9.827 16.968 ;
     RECT  9.709 27.6 9.925 28.152 ;
     RECT  8.104 80.016 9.971 80.04 ;
     RECT  9.637 95.712 9.997 95.736 ;
     RECT  9.445 116.544 10.105 117.576 ;
     RECT  9.925 26.784 10.109 28.152 ;
     RECT  9.997 7.968 10.115 7.992 ;
     RECT  9.973 47.904 10.117 47.928 ;
     RECT  10.069 49.008 10.117 49.032 ;
     RECT  10.021 10.8 10.163 10.824 ;
     RECT  9.961 15.984 10.213 16.008 ;
     RECT  9.997 94.848 10.213 95.736 ;
     RECT  10.213 15.072 10.259 16.008 ;
     RECT  10.165 53.52 10.289 53.544 ;
     RECT  10.213 94.656 10.289 95.736 ;
     RECT  10.289 95.088 10.307 95.736 ;
     RECT  10.165 106.608 10.325 106.632 ;
     RECT  9.281 2.304 10.403 6.936 ;
     RECT  10.109 27.36 10.405 28.152 ;
     RECT  9.349 145.872 10.433 145.896 ;
     RECT  10.117 47.904 10.501 49.032 ;
     RECT  10.309 50.112 10.501 50.136 ;
     RECT  8.104 147.264 10.501 151.176 ;
     RECT  10.501 47.904 10.505 50.136 ;
     RECT  10.537 144.24 10.549 144.264 ;
     RECT  9.733 0.096 10.577 0.36 ;
     RECT  10.549 144.192 10.609 144.264 ;
     RECT  10.537 99.408 10.645 100.248 ;
     RECT  10.259 15.072 10.685 15.096 ;
     RECT  10.609 144.192 10.717 144.36 ;
     RECT  10.645 99.408 10.757 100.296 ;
     RECT  10.717 25.68 10.787 25.704 ;
     RECT  10.403 2.304 10.793 5.832 ;
     RECT  10.021 52.464 10.793 52.488 ;
     RECT  10.717 144.192 10.825 144.408 ;
     RECT  10.757 99.408 10.835 100.248 ;
     RECT  10.501 146.496 10.835 151.176 ;
     RECT  10.825 144.096 10.837 144.408 ;
     RECT  10.741 55.776 10.861 55.8 ;
     RECT  10.837 144.096 10.901 144.504 ;
     RECT  10.933 12.528 10.979 12.552 ;
     RECT  10.405 27.36 10.981 28.536 ;
     RECT  10.981 27.36 11.125 28.584 ;
     RECT  11.149 105.456 11.219 105.48 ;
     RECT  10.505 48.288 11.221 50.136 ;
     RECT  10.793 2.88 11.297 5.832 ;
     RECT  10.861 55.296 11.329 55.8 ;
     RECT  10.969 52.416 11.411 52.44 ;
     RECT  11.365 70.08 11.411 70.104 ;
     RECT  11.221 48.288 11.441 50.712 ;
     RECT  9.397 112.704 11.461 112.728 ;
     RECT  11.441 48.288 11.513 48.312 ;
     RECT  11.461 105.888 11.513 106.68 ;
     RECT  11.545 30 11.603 30.024 ;
     RECT  11.329 35.328 11.603 35.352 ;
     RECT  11.461 102.624 11.603 102.648 ;
     RECT  11.513 106.56 11.689 106.68 ;
     RECT  11.173 110.784 11.689 110.808 ;
     RECT  11.297 4.848 11.701 5.832 ;
     RECT  10.403 6.864 11.701 6.936 ;
     RECT  11.329 55.248 11.701 55.8 ;
     RECT  11.701 4.848 11.725 6.936 ;
     RECT  11.441 50.016 11.729 50.712 ;
     RECT  11.725 4.848 11.795 7.128 ;
     RECT  11.701 55.248 11.797 55.896 ;
     RECT  10.645 57.312 11.797 57.336 ;
     RECT  11.729 50.016 11.801 50.664 ;
     RECT  11.125 26.544 11.845 28.584 ;
     RECT  11.797 55.248 11.945 57.336 ;
     RECT  10.577 0.096 11.981 0.264 ;
     RECT  11.125 21.648 11.981 21.672 ;
     RECT  10.981 83.76 11.981 83.784 ;
     RECT  11.461 112.704 12.037 112.824 ;
     RECT  9.565 114.336 12.037 114.936 ;
     RECT  11.317 108.144 12.085 108.168 ;
     RECT  12.037 112.704 12.085 114.936 ;
     RECT  12.049 21.12 12.131 21.624 ;
     RECT  11.473 104.304 12.131 104.328 ;
     RECT  11.689 110.544 12.157 110.808 ;
     RECT  11.795 4.848 12.197 6.936 ;
     RECT  12.157 110.544 12.229 111.432 ;
     RECT  12.229 110.448 12.301 111.432 ;
     RECT  12.085 112.56 12.301 114.936 ;
     RECT  10.105 115.968 12.325 117.576 ;
     RECT  11.297 2.88 12.337 3.432 ;
     RECT  12.277 145.584 12.337 145.608 ;
     RECT  12.197 4.848 12.373 5.928 ;
     RECT  10.901 144.096 12.373 144.36 ;
     RECT  12.337 2.88 12.445 3.528 ;
     RECT  12.373 4.608 12.445 5.928 ;
     RECT  12.301 110.448 12.469 114.936 ;
     RECT  11.905 102.672 12.565 103.032 ;
     RECT  12.085 108.144 12.625 109.08 ;
     RECT  12.445 2.88 12.661 5.928 ;
     RECT  12.469 110.352 12.661 114.936 ;
     RECT  12.325 115.92 12.661 117.576 ;
     RECT  11.845 26.544 12.757 29.208 ;
     RECT  9.173 119.472 12.757 119.496 ;
     RECT  12.661 120.864 12.757 120.888 ;
     RECT  11.461 51.84 12.805 51.912 ;
     RECT  12.661 2.784 12.853 5.928 ;
     RECT  12.757 26.544 12.853 29.352 ;
     RECT  12.517 59.232 12.853 59.256 ;
     RECT  12.853 26.544 12.877 29.64 ;
     RECT  11.981 0.096 12.881 0.216 ;
     RECT  12.757 119.472 12.913 120.888 ;
     RECT  11.945 55.248 12.949 57.096 ;
     RECT  12.853 59.232 12.949 59.88 ;
     RECT  12.337 145.584 12.949 145.704 ;
     RECT  12.625 108.144 12.997 109.176 ;
     RECT  9.493 38.928 13.045 39.24 ;
     RECT  12.913 69.84 13.045 69.864 ;
     RECT  11.689 106.56 13.045 107.016 ;
     RECT  12.997 108.144 13.045 109.272 ;
     RECT  12.881 0.144 13.093 0.216 ;
     RECT  12.853 2.736 13.093 5.928 ;
     RECT  12.949 54.624 13.093 57.096 ;
     RECT  11.977 58.128 13.093 58.152 ;
     RECT  13.093 2.304 13.208 5.928 ;
     RECT  12.197 6.912 13.208 6.936 ;
     RECT  12.409 7.968 13.208 7.992 ;
     RECT  12.181 10.8 13.208 10.824 ;
     RECT  12.131 21.12 13.208 21.144 ;
     RECT  12.877 26.544 13.208 29.688 ;
     RECT  9.589 31.152 13.208 31.416 ;
     RECT  12.469 35.424 13.208 35.448 ;
     RECT  13.045 38.928 13.208 39.576 ;
     RECT  9.445 41.376 13.208 41.64 ;
     RECT  12.997 44.976 13.208 45 ;
     RECT  11.509 46.752 13.208 46.776 ;
     RECT  13.093 48.48 13.208 48.936 ;
     RECT  11.801 50.016 13.208 50.616 ;
     RECT  12.805 51.84 13.208 52.296 ;
     RECT  13.093 54.624 13.208 58.152 ;
     RECT  12.949 59.232 13.208 60.408 ;
     RECT  13.045 69.696 13.208 69.96 ;
     RECT  13.093 90.288 13.208 90.312 ;
     RECT  12.853 91.68 13.208 91.704 ;
     RECT  8.104 93.216 13.208 93.384 ;
     RECT  10.307 95.712 13.208 95.736 ;
     RECT  12.757 96.768 13.208 96.792 ;
     RECT  12.373 101.04 13.208 101.064 ;
     RECT  12.565 102.672 13.208 103.608 ;
     RECT  12.901 105.024 13.208 105.048 ;
     RECT  13.045 106.56 13.208 109.272 ;
     RECT  12.661 110.352 13.208 117.576 ;
     RECT  12.913 119.472 13.208 121.368 ;
     RECT  12.373 144.096 13.208 144.6 ;
     RECT  12.949 145.584 13.208 145.992 ;
     RECT  10.835 147.264 13.208 151.176 ;
     RECT  13.093 0.144 13.235 0.552 ;
     RECT  13.208 2.148 13.285 151.176 ;
     RECT  13.285 2.016 13.385 151.176 ;
     RECT  13.385 2.16 13.504 151.176 ;
     RECT  13.504 2.16 13.601 9.768 ;
     RECT  13.235 0.144 13.619 0.408 ;
     RECT  13.504 55.776 13.619 59.256 ;
     RECT  13.619 56.304 13.667 59.256 ;
     RECT  13.504 44.976 13.709 47.304 ;
     RECT  13.504 109.248 13.709 109.272 ;
     RECT  13.504 21.264 13.715 21.288 ;
     RECT  13.504 51.408 13.763 52.296 ;
     RECT  13.667 56.304 13.781 57.768 ;
     RECT  13.667 58.944 13.853 59.256 ;
     RECT  13.504 19.92 13.889 19.944 ;
     RECT  13.504 110.544 13.925 111.576 ;
     RECT  13.504 112.704 13.925 118.008 ;
     RECT  13.504 54.144 13.961 54.792 ;
     RECT  13.504 120.816 14.003 121.128 ;
     RECT  13.504 106.56 14.069 106.584 ;
     RECT  13.504 119.136 14.105 119.4 ;
     RECT  13.619 0.288 14.195 0.408 ;
     RECT  13.763 52.272 14.213 52.296 ;
     RECT  13.709 45.12 14.243 47.304 ;
     RECT  13.925 115.968 14.243 118.008 ;
     RECT  13.504 24.48 14.291 24.936 ;
     RECT  13.504 22.8 14.435 23.16 ;
     RECT  13.504 144.096 14.435 151.176 ;
     RECT  14.243 45.456 14.537 47.304 ;
     RECT  13.504 108.048 14.569 108.072 ;
     RECT  13.925 112.704 14.581 114.936 ;
     RECT  14.581 112.656 14.645 114.936 ;
     RECT  14.569 108.048 14.681 108.984 ;
     RECT  13.504 26.544 14.713 26.568 ;
     RECT  13.853 58.944 14.717 58.968 ;
     RECT  14.291 24.912 14.753 24.936 ;
     RECT  14.435 22.8 14.789 22.824 ;
     RECT  14.537 45.456 14.861 45.48 ;
     RECT  13.925 110.784 14.861 111.576 ;
     RECT  14.645 112.704 14.867 114.936 ;
     RECT  13.781 56.304 14.917 57.096 ;
     RECT  14.917 56.304 14.969 57.336 ;
     RECT  14.537 46.464 15.013 47.304 ;
     RECT  15.145 66.624 15.203 66.648 ;
     RECT  14.195 0.384 15.301 0.408 ;
     RECT  14.969 57.072 15.541 57.336 ;
     RECT  15.013 46.464 15.589 47.88 ;
     RECT  14.867 114.864 15.649 114.936 ;
     RECT  14.243 115.968 15.649 117.672 ;
     RECT  14.867 112.704 15.653 113.88 ;
     RECT  15.541 57.072 15.689 57.672 ;
     RECT  14.105 119.376 15.721 119.4 ;
     RECT  15.589 46.464 15.725 48.408 ;
     RECT  15.725 47.712 15.733 48.408 ;
     RECT  15.253 49.584 15.733 49.608 ;
     RECT  15.733 47.712 15.781 49.608 ;
     RECT  15.685 50.688 15.781 50.712 ;
     RECT  15.289 24.96 15.829 24.984 ;
     RECT  14.713 26.016 15.829 26.568 ;
     RECT  13.601 2.304 15.865 9.768 ;
     RECT  15.725 46.464 15.923 46.536 ;
     RECT  15.649 114.864 15.923 117.672 ;
     RECT  15.865 2.304 15.971 10.248 ;
     RECT  15.923 114.912 16.009 117.672 ;
     RECT  15.721 118.944 16.009 119.4 ;
     RECT  15.971 2.304 16.013 7.992 ;
     RECT  15.689 57.312 16.045 57.672 ;
     RECT  15.829 24.912 16.069 24.984 ;
     RECT  16.013 2.352 16.193 7.992 ;
     RECT  13.504 95.712 16.225 95.736 ;
     RECT  15.781 47.712 16.309 50.712 ;
     RECT  13.504 101.04 16.405 101.064 ;
     RECT  16.069 23.952 16.409 24.984 ;
     RECT  13.504 96.768 16.441 96.792 ;
     RECT  16.309 47.712 16.451 50.76 ;
     RECT  16.477 51.888 16.547 51.912 ;
     RECT  16.409 24.528 16.589 24.984 ;
     RECT  16.045 57.312 16.625 57.96 ;
     RECT  16.193 2.592 16.733 7.992 ;
     RECT  16.405 101.04 16.741 101.352 ;
     RECT  13.504 102.672 16.741 103.608 ;
     RECT  15.971 9.12 16.769 10.248 ;
     RECT  14.681 108.048 16.789 108.072 ;
     RECT  16.693 13.68 16.805 13.704 ;
     RECT  13.504 38.928 16.837 39.48 ;
     RECT  15.653 112.704 16.837 112.728 ;
     RECT  15.653 113.856 16.837 113.88 ;
     RECT  16.549 52.464 16.873 52.488 ;
     RECT  13.961 54.144 16.873 54.168 ;
     RECT  16.589 24.912 16.909 24.984 ;
     RECT  15.829 26.016 16.909 26.808 ;
     RECT  16.909 24.912 16.979 26.808 ;
     RECT  16.693 66.144 16.979 66.168 ;
     RECT  15.301 0.096 16.985 0.408 ;
     RECT  16.769 10.224 16.985 10.248 ;
     RECT  16.789 108.048 17.017 108.744 ;
     RECT  16.873 51.312 17.027 51.336 ;
     RECT  16.981 64.8 17.027 65.16 ;
     RECT  16.733 2.592 17.057 6.888 ;
     RECT  17.027 64.8 17.057 64.824 ;
     RECT  14.861 110.784 17.057 111.432 ;
     RECT  16.985 0.144 17.077 0.408 ;
     RECT  16.733 7.968 17.077 7.992 ;
     RECT  16.769 9.12 17.077 9.192 ;
     RECT  13.504 93.216 17.077 93.384 ;
     RECT  16.441 96.768 17.077 96.936 ;
     RECT  16.741 101.04 17.077 103.608 ;
     RECT  17.077 7.968 17.123 9.192 ;
     RECT  17.017 108.048 17.123 108.888 ;
     RECT  16.979 26.544 17.125 26.808 ;
     RECT  13.504 28.128 17.125 28.152 ;
     RECT  16.837 38.736 17.125 39.48 ;
     RECT  13.504 41.376 17.125 41.64 ;
     RECT  15.923 46.464 17.125 46.488 ;
     RECT  16.451 47.712 17.125 50.136 ;
     RECT  17.123 7.968 17.129 9.096 ;
     RECT  14.435 144.24 17.129 151.176 ;
     RECT  16.225 95.712 17.197 95.784 ;
     RECT  17.077 96.768 17.197 96.984 ;
     RECT  17.123 108.048 17.197 108.744 ;
     RECT  17.077 10.8 17.219 10.824 ;
     RECT  17.125 46.128 17.219 50.136 ;
     RECT  17.077 0.144 17.267 1.128 ;
     RECT  17.077 92.928 17.267 93.384 ;
     RECT  17.197 95.712 17.267 96.984 ;
     RECT  17.129 7.968 17.309 7.992 ;
     RECT  17.267 95.712 17.309 96.792 ;
     RECT  17.057 2.592 17.381 5.16 ;
     RECT  17.125 26.544 17.411 28.152 ;
     RECT  17.057 6.192 17.417 6.888 ;
     RECT  17.411 26.544 17.453 26.808 ;
     RECT  16.873 52.464 17.461 54.168 ;
     RECT  16.837 112.704 17.509 113.88 ;
     RECT  16.009 114.912 17.509 119.4 ;
     RECT  13.504 105.168 17.557 105.192 ;
     RECT  16.625 57.648 17.593 57.96 ;
     RECT  17.057 110.832 17.593 111.432 ;
     RECT  17.521 10.848 17.603 10.872 ;
     RECT  17.593 110.832 17.605 111.72 ;
     RECT  17.509 112.704 17.605 119.4 ;
     RECT  17.411 27.888 17.701 28.152 ;
     RECT  17.461 52.464 17.701 54.216 ;
     RECT  17.557 55.296 17.701 55.32 ;
     RECT  17.701 27.888 17.773 28.248 ;
     RECT  17.125 38.736 17.797 41.736 ;
     RECT  17.701 52.464 17.845 55.32 ;
     RECT  13.504 90.288 17.845 90.312 ;
     RECT  13.504 91.632 17.845 91.752 ;
     RECT  17.773 27.888 17.893 28.536 ;
     RECT  17.893 27.888 17.941 28.584 ;
     RECT  17.219 46.56 18.025 50.136 ;
     RECT  17.941 27.888 18.181 29.064 ;
     RECT  18.169 37.68 18.205 37.704 ;
     RECT  17.797 38.736 18.205 42.024 ;
     RECT  17.267 0.144 18.241 0.408 ;
     RECT  15.253 12.288 18.277 12.312 ;
     RECT  17.605 45.072 18.277 45.096 ;
     RECT  18.025 46.56 18.277 50.76 ;
     RECT  17.309 96.768 18.277 96.792 ;
     RECT  17.881 97.824 18.277 97.848 ;
     RECT  17.197 107.136 18.277 108.744 ;
     RECT  18.277 45.072 18.313 50.76 ;
     RECT  18.181 27.888 18.325 29.112 ;
     RECT  17.593 57.648 18.325 58.152 ;
     RECT  17.605 59.28 18.325 59.304 ;
     RECT  18.205 37.68 18.349 42.024 ;
     RECT  18.325 57.648 18.373 59.304 ;
     RECT  18.277 106.56 18.373 108.744 ;
     RECT  13.504 35.424 18.421 35.448 ;
     RECT  18.373 106.56 18.421 108.936 ;
     RECT  17.381 2.64 18.469 5.16 ;
     RECT  17.417 6.192 18.469 6.84 ;
     RECT  17.557 105.168 18.469 105.24 ;
     RECT  18.277 44.016 18.601 44.04 ;
     RECT  18.313 45.024 18.601 50.76 ;
     RECT  18.469 2.64 18.608 6.84 ;
     RECT  17.129 9.072 18.608 9.096 ;
     RECT  18.277 11.568 18.608 13.032 ;
     RECT  15.781 19.584 18.608 19.608 ;
     RECT  16.979 24.912 18.608 24.984 ;
     RECT  17.453 26.544 18.608 26.568 ;
     RECT  18.325 27.888 18.608 29.976 ;
     RECT  13.504 31.152 18.608 31.416 ;
     RECT  18.421 34.656 18.608 35.448 ;
     RECT  18.349 37.056 18.608 42.024 ;
     RECT  18.601 44.016 18.608 50.76 ;
     RECT  17.845 52.464 18.608 55.896 ;
     RECT  18.373 57.6 18.608 59.304 ;
     RECT  13.504 61.872 18.608 61.896 ;
     RECT  18.457 64.992 18.608 65.016 ;
     RECT  15.925 81.072 18.608 81.096 ;
     RECT  18.325 83.76 18.608 83.784 ;
     RECT  17.845 90.288 18.608 91.752 ;
     RECT  17.267 93.216 18.608 93.384 ;
     RECT  17.309 95.712 18.608 95.736 ;
     RECT  18.277 96.768 18.608 97.848 ;
     RECT  18.277 99.6 18.608 99.624 ;
     RECT  17.077 100.848 18.608 103.608 ;
     RECT  18.469 104.928 18.608 105.24 ;
     RECT  18.421 106.56 18.608 109.272 ;
     RECT  17.605 110.832 18.608 119.4 ;
     RECT  14.003 121.104 18.608 121.128 ;
     RECT  17.129 144.288 18.608 151.176 ;
     RECT  18.608 2.148 18.712 151.176 ;
     RECT  18.712 2.304 18.904 151.176 ;
     RECT  18.904 46.128 18.965 47.736 ;
     RECT  18.904 57.84 19.001 58.008 ;
     RECT  18.904 54.144 19.037 54.264 ;
     RECT  18.904 83.76 19.037 83.784 ;
     RECT  18.904 28.128 19.043 31.416 ;
     RECT  19.043 29.328 19.091 31.416 ;
     RECT  18.904 106.464 19.109 113.352 ;
     RECT  19.091 29.664 19.139 31.416 ;
     RECT  18.904 88.944 19.139 93.384 ;
     RECT  18.904 26.544 19.187 26.904 ;
     RECT  19.139 29.712 19.217 31.416 ;
     RECT  19.187 26.544 19.283 26.808 ;
     RECT  19.217 29.712 19.283 29.736 ;
     RECT  18.904 43.296 19.283 45.144 ;
     RECT  18.241 0.096 19.325 0.408 ;
     RECT  18.904 37.296 19.379 38.232 ;
     RECT  18.904 39.36 19.379 42.216 ;
     RECT  19.109 106.512 19.379 113.352 ;
     RECT  19.379 37.44 19.475 38.232 ;
     RECT  19.139 89.472 19.475 93.384 ;
     RECT  19.379 106.512 19.523 111.96 ;
     RECT  18.904 100.848 19.619 105.24 ;
     RECT  19.523 106.512 19.649 111.72 ;
     RECT  18.904 63.072 19.685 63.096 ;
     RECT  18.904 11.424 19.811 12.408 ;
     RECT  19.649 106.512 19.811 111.432 ;
     RECT  18.904 95.184 19.865 97.848 ;
     RECT  19.811 106.512 19.865 111.048 ;
     RECT  19.619 104.928 19.901 105.24 ;
     RECT  19.811 11.424 19.955 12.312 ;
     RECT  19.379 39.456 19.955 42.216 ;
     RECT  19.865 106.512 19.955 106.632 ;
     RECT  19.217 31.152 19.957 31.416 ;
     RECT  19.001 57.984 20.005 58.008 ;
     RECT  18.904 48.768 20.053 50.616 ;
     RECT  18.965 46.128 20.077 47.4 ;
     RECT  20.053 48.768 20.077 50.712 ;
     RECT  19.901 105.168 20.077 105.24 ;
     RECT  18.904 115.2 20.101 119.4 ;
     RECT  19.283 44.256 20.113 45.144 ;
     RECT  20.077 46.128 20.113 50.712 ;
     RECT  19.043 28.128 20.149 28.152 ;
     RECT  19.865 107.664 20.225 111.048 ;
     RECT  20.113 44.256 20.243 50.712 ;
     RECT  19.957 129.12 20.245 129.144 ;
     RECT  18.904 61.872 20.293 61.896 ;
     RECT  18.904 2.304 20.329 6.168 ;
     RECT  20.101 114.576 20.329 119.4 ;
     RECT  20.005 57.984 20.333 58.584 ;
     RECT  20.329 114.528 20.401 119.4 ;
     RECT  18.904 121.104 20.401 121.224 ;
     RECT  18.904 8.496 20.473 8.52 ;
     RECT  19.955 39.456 20.473 39.48 ;
     RECT  20.401 114.528 20.473 121.224 ;
     RECT  20.333 57.984 20.509 58.008 ;
     RECT  20.293 61.872 20.531 62.76 ;
     RECT  19.865 95.184 20.531 96.84 ;
     RECT  19.325 0.384 20.581 0.408 ;
     RECT  20.329 2.304 20.581 6.408 ;
     RECT  19.475 37.488 20.581 38.232 ;
     RECT  20.473 39.408 20.581 39.48 ;
     RECT  18.904 32.784 20.617 32.808 ;
     RECT  20.581 0.384 20.627 1.128 ;
     RECT  20.473 8.016 20.629 8.52 ;
     RECT  20.627 0.384 20.677 0.408 ;
     RECT  19.955 40.464 20.677 42.216 ;
     RECT  20.389 99.168 20.693 99.192 ;
     RECT  20.629 23.088 20.725 23.112 ;
     RECT  19.379 113.04 20.725 113.352 ;
     RECT  20.581 2.304 20.797 6.936 ;
     RECT  20.629 8.016 20.797 8.568 ;
     RECT  20.243 44.256 20.797 50.136 ;
     RECT  20.509 56.304 20.797 56.328 ;
     RECT  20.509 57.888 20.797 58.008 ;
     RECT  20.437 9.696 20.821 9.72 ;
     RECT  19.865 97.824 20.833 97.848 ;
     RECT  20.617 32.784 20.869 33.096 ;
     RECT  18.904 34.176 20.869 35.448 ;
     RECT  20.531 96.768 20.869 96.84 ;
     RECT  20.833 97.824 20.869 98.088 ;
     RECT  20.225 108.048 20.869 111.048 ;
     RECT  20.821 9.696 20.909 10.296 ;
     RECT  20.869 108.048 20.909 111.096 ;
     RECT  20.473 114.528 20.941 121.272 ;
     RECT  19.475 90.288 20.945 93.384 ;
     RECT  20.077 105.168 20.965 106.056 ;
     RECT  20.725 112.416 20.965 113.352 ;
     RECT  20.941 114.528 20.965 121.992 ;
     RECT  19.619 100.848 21.013 103.608 ;
     RECT  20.909 108.48 21.017 111.096 ;
     RECT  21.013 100.08 21.059 103.608 ;
     RECT  20.797 2.304 21.061 8.568 ;
     RECT  20.677 40.464 21.061 42.312 ;
     RECT  20.797 43.344 21.061 50.136 ;
     RECT  19.957 31.152 21.085 31.8 ;
     RECT  20.869 32.784 21.085 35.448 ;
     RECT  19.037 54.24 21.085 54.264 ;
     RECT  20.945 90.288 21.085 90.312 ;
     RECT  20.531 95.184 21.085 95.736 ;
     RECT  20.965 112.416 21.085 121.992 ;
     RECT  21.061 40.464 21.107 50.136 ;
     RECT  21.085 112.08 21.107 121.992 ;
     RECT  21.085 54.24 21.109 54.36 ;
     RECT  21.085 90 21.109 90.312 ;
     RECT  21.059 100.704 21.109 103.608 ;
     RECT  21.107 114.48 21.121 121.992 ;
     RECT  21.107 112.08 21.125 113.352 ;
     RECT  19.909 52.992 21.155 53.016 ;
     RECT  21.109 54.144 21.161 54.6 ;
     RECT  21.109 89.712 21.161 90.312 ;
     RECT  20.869 96.768 21.193 98.088 ;
     RECT  20.965 105.168 21.193 106.632 ;
     RECT  21.193 105.168 21.233 106.92 ;
     RECT  20.945 91.584 21.265 93.384 ;
     RECT  21.233 106.56 21.347 106.92 ;
     RECT  21.265 91.584 21.349 93.432 ;
     RECT  21.085 94.608 21.349 95.736 ;
     RECT  21.017 110.784 21.445 111.096 ;
     RECT  21.125 112.08 21.445 113.304 ;
     RECT  20.581 36.912 21.449 39.48 ;
     RECT  21.109 100.704 21.485 103.656 ;
     RECT  21.121 114.48 21.521 122.136 ;
     RECT  20.725 23.04 21.541 23.112 ;
     RECT  21.349 91.584 21.589 95.736 ;
     RECT  21.193 96.768 21.589 98.904 ;
     RECT  21.589 13.632 21.637 13.656 ;
     RECT  21.233 105.168 21.637 105.24 ;
     RECT  21.637 13.632 21.683 14.376 ;
     RECT  21.553 123.696 21.685 123.72 ;
     RECT  20.909 10.272 21.733 10.296 ;
     RECT  21.161 54.24 21.733 54.6 ;
     RECT  21.637 104.976 21.733 105.24 ;
     RECT  21.589 91.584 21.781 98.904 ;
     RECT  21.733 86.592 21.809 86.616 ;
     RECT  20.149 28.128 21.829 28.68 ;
     RECT  21.107 43.872 21.841 50.136 ;
     RECT  21.829 51.264 21.841 51.288 ;
     RECT  21.683 14.352 21.881 14.376 ;
     RECT  21.829 28.128 21.913 29.352 ;
     RECT  21.913 27.792 21.917 29.352 ;
     RECT  21.685 123.696 21.923 123.816 ;
     RECT  21.781 91.584 21.953 99.192 ;
     RECT  21.953 98.064 21.989 99.192 ;
     RECT  21.923 123.696 22.025 123.72 ;
     RECT  21.953 91.584 22.067 96.936 ;
     RECT  21.589 17.088 22.129 17.112 ;
     RECT  21.733 10.272 22.165 10.872 ;
     RECT  19.955 12.288 22.165 12.312 ;
     RECT  21.445 110.784 22.201 113.304 ;
     RECT  21.841 43.872 22.205 51.288 ;
     RECT  22.129 16.224 22.211 17.112 ;
     RECT  19.283 26.544 22.213 26.568 ;
     RECT  21.917 27.792 22.213 28.68 ;
     RECT  21.449 38.64 22.213 39.48 ;
     RECT  21.107 40.464 22.213 42.744 ;
     RECT  21.521 114.816 22.213 122.136 ;
     RECT  22.117 126 22.213 126.024 ;
     RECT  22.165 10.272 22.237 12.312 ;
     RECT  21.733 54.24 22.237 54.696 ;
     RECT  21.017 108.48 22.241 109.416 ;
     RECT  21.449 36.912 22.261 37.608 ;
     RECT  22.237 59.328 22.261 59.352 ;
     RECT  20.531 61.872 22.261 62.472 ;
     RECT  21.347 106.56 22.261 106.584 ;
     RECT  22.241 108.48 22.261 109.32 ;
     RECT  18.904 144.288 22.261 151.176 ;
     RECT  20.797 56.304 22.273 58.008 ;
     RECT  22.261 59.328 22.273 59.544 ;
     RECT  22.261 61.872 22.273 62.856 ;
     RECT  22.213 26.544 22.277 28.68 ;
     RECT  21.161 89.856 22.277 90.312 ;
     RECT  18.904 19.488 22.309 19.512 ;
     RECT  22.201 110.784 22.309 113.496 ;
     RECT  22.201 124.8 22.309 124.824 ;
     RECT  22.213 126 22.309 126.456 ;
     RECT  22.277 89.904 22.345 90.312 ;
     RECT  22.067 91.584 22.345 96.888 ;
     RECT  22.309 19.488 22.355 19.944 ;
     RECT  21.301 21.12 22.355 21.144 ;
     RECT  21.061 2.304 22.357 9.192 ;
     RECT  22.237 10.272 22.357 12.504 ;
     RECT  22.237 53.616 22.357 54.696 ;
     RECT  22.213 114.816 22.357 122.712 ;
     RECT  22.309 124.8 22.357 126.456 ;
     RECT  22.309 110.784 22.381 113.544 ;
     RECT  21.733 104.88 22.417 105.24 ;
     RECT  22.261 106.416 22.451 106.584 ;
     RECT  21.085 31.152 22.453 35.448 ;
     RECT  22.261 36.432 22.453 37.608 ;
     RECT  22.205 43.92 22.453 51.288 ;
     RECT  22.357 53.136 22.453 54.696 ;
     RECT  22.453 31.152 22.489 37.608 ;
     RECT  22.357 124.704 22.489 126.504 ;
     RECT  22.451 106.512 22.493 106.584 ;
     RECT  22.273 61.536 22.595 62.856 ;
     RECT  22.489 124.704 22.595 126.552 ;
     RECT  22.357 2.304 22.597 12.504 ;
     RECT  22.417 104.688 22.597 105.24 ;
     RECT  22.381 110.448 22.633 113.544 ;
     RECT  22.357 114.816 22.633 123.24 ;
     RECT  22.597 64.848 22.645 64.872 ;
     RECT  22.261 143.424 22.645 151.176 ;
     RECT  22.211 17.088 22.705 17.112 ;
     RECT  21.625 18.144 22.705 18.168 ;
     RECT  22.493 106.56 22.709 106.584 ;
     RECT  22.597 104.688 22.739 105.288 ;
     RECT  22.261 107.856 22.741 109.32 ;
     RECT  22.453 53.04 22.777 54.696 ;
     RECT  22.213 38.64 22.787 42.744 ;
     RECT  22.645 142.752 22.789 151.176 ;
     RECT  22.741 107.184 22.817 109.32 ;
     RECT  22.595 61.536 22.837 62.616 ;
     RECT  22.201 14.88 22.849 14.904 ;
     RECT  22.355 19.488 22.849 19.608 ;
     RECT  22.489 31.152 22.849 37.656 ;
     RECT  22.787 38.64 22.849 39.912 ;
     RECT  22.777 53.04 22.849 55.224 ;
     RECT  22.273 56.304 22.849 59.544 ;
     RECT  22.597 2.112 22.853 12.504 ;
     RECT  22.849 53.04 22.885 59.544 ;
     RECT  22.705 17.088 22.889 18.168 ;
     RECT  22.789 142.512 22.931 151.176 ;
     RECT  22.277 28.128 22.957 28.68 ;
     RECT  22.853 2.208 22.979 12.504 ;
     RECT  22.849 14.832 22.981 14.904 ;
     RECT  22.957 28.128 22.981 28.968 ;
     RECT  22.921 18.24 23.027 18.264 ;
     RECT  22.849 19.344 23.029 19.608 ;
     RECT  21.485 100.704 23.029 103.608 ;
     RECT  22.739 104.688 23.029 105.24 ;
     RECT  22.453 43.92 23.065 51.384 ;
     RECT  22.885 52.368 23.065 59.544 ;
     RECT  22.345 89.904 23.065 96.888 ;
     RECT  22.981 14.832 23.101 15.336 ;
     RECT  23.029 100.704 23.137 105.24 ;
     RECT  22.633 110.448 23.173 123.24 ;
     RECT  22.817 107.52 23.209 109.32 ;
     RECT  23.209 107.52 23.221 109.416 ;
     RECT  23.173 110.448 23.221 123.768 ;
     RECT  21.989 98.064 23.269 98.904 ;
     RECT  22.849 31.152 23.317 39.912 ;
     RECT  23.269 98.064 23.317 99.432 ;
     RECT  23.137 100.608 23.317 105.24 ;
     RECT  22.595 124.752 23.317 126.552 ;
     RECT  23.065 43.92 23.353 59.544 ;
     RECT  22.837 60.96 23.353 62.616 ;
     RECT  22.787 40.944 23.365 42.744 ;
     RECT  20.245 129.12 23.365 129.192 ;
     RECT  22.981 28.128 23.389 29.064 ;
     RECT  23.317 30.192 23.389 39.912 ;
     RECT  22.645 64.848 23.413 64.968 ;
     RECT  23.365 128.592 23.461 129.192 ;
     RECT  23.365 40.944 23.533 42.936 ;
     RECT  23.353 43.92 23.533 62.616 ;
     RECT  23.413 64.752 23.569 64.968 ;
     RECT  22.889 17.088 23.605 17.112 ;
     RECT  22.979 2.304 23.641 12.504 ;
     RECT  23.221 107.52 23.641 123.768 ;
     RECT  23.317 124.752 23.641 127.08 ;
     RECT  23.641 2.304 23.653 12.792 ;
     RECT  23.101 14.016 23.653 15.336 ;
     RECT  23.029 88.896 23.677 88.92 ;
     RECT  23.065 89.904 23.677 96.936 ;
     RECT  23.677 88.896 23.713 96.936 ;
     RECT  23.317 98.064 23.713 105.24 ;
     RECT  21.541 23.04 23.749 23.16 ;
     RECT  23.653 2.304 23.785 15.336 ;
     RECT  23.605 16.896 23.785 17.112 ;
     RECT  23.713 88.896 23.785 105.672 ;
     RECT  23.533 40.944 23.797 62.616 ;
     RECT  23.029 18.624 23.821 19.608 ;
     RECT  23.389 28.128 23.857 39.912 ;
     RECT  20.677 0.096 23.941 0.408 ;
     RECT  22.277 26.544 24.001 26.568 ;
     RECT  23.857 27.792 24.001 39.912 ;
     RECT  23.785 2.304 24.008 17.112 ;
     RECT  23.821 18.624 24.008 19.992 ;
     RECT  23.749 23.04 24.008 23.4 ;
     RECT  18.904 24.768 24.008 24.936 ;
     RECT  24.001 26.544 24.008 39.912 ;
     RECT  23.797 40.944 24.008 63.096 ;
     RECT  23.569 64.272 24.008 64.968 ;
     RECT  23.365 69.552 24.008 69.576 ;
     RECT  23.365 70.656 24.008 70.68 ;
     RECT  18.904 81.072 24.008 81.096 ;
     RECT  23.269 86.64 24.008 86.664 ;
     RECT  23.269 87.696 24.008 87.72 ;
     RECT  23.785 88.896 24.008 105.816 ;
     RECT  23.641 107.52 24.008 127.08 ;
     RECT  23.461 128.592 24.008 129.24 ;
     RECT  23.413 130.224 24.008 130.248 ;
     RECT  20.149 131.328 24.008 131.352 ;
     RECT  23.701 141.36 24.008 141.384 ;
     RECT  22.931 142.752 24.008 151.176 ;
     RECT  24.008 2.148 24.133 151.176 ;
     RECT  23.941 0.096 24.185 0.552 ;
     RECT  24.133 2.016 24.304 151.176 ;
     RECT  24.304 2.016 24.401 13.656 ;
     RECT  24.304 142.752 24.437 151.176 ;
     RECT  24.304 87.216 24.473 87.384 ;
     RECT  24.304 14.832 24.515 17.112 ;
     RECT  24.401 2.304 24.545 13.656 ;
     RECT  24.304 130.224 24.545 132.168 ;
     RECT  24.437 144.24 24.545 151.176 ;
     RECT  24.304 74.112 24.611 74.52 ;
     RECT  24.515 14.832 24.653 16.92 ;
     RECT  24.304 69.552 24.659 69.576 ;
     RECT  24.545 2.304 24.725 13.128 ;
     RECT  24.653 15.984 24.905 16.92 ;
     RECT  24.905 16.032 24.995 16.92 ;
     RECT  24.304 20.928 24.995 66.744 ;
     RECT  24.725 2.304 25.139 13.08 ;
     RECT  24.653 14.832 25.193 14.856 ;
     RECT  24.185 0.096 25.261 0.408 ;
     RECT  24.304 18.768 25.333 19.512 ;
     RECT  24.304 80.64 25.333 81.096 ;
     RECT  24.304 141.36 25.409 141.384 ;
     RECT  25.333 80.352 25.429 81.096 ;
     RECT  24.473 87.216 25.429 87.24 ;
     RECT  25.261 0.096 25.441 0.456 ;
     RECT  25.139 2.304 25.445 8.472 ;
     RECT  24.995 16.512 25.525 16.92 ;
     RECT  25.333 18.192 25.525 19.512 ;
     RECT  25.139 9.696 25.553 13.08 ;
     RECT  24.995 20.928 25.553 23.304 ;
     RECT  24.304 137.376 25.553 137.4 ;
     RECT  25.553 9.696 25.589 10.536 ;
     RECT  25.553 12.288 25.589 13.08 ;
     RECT  24.995 24.768 25.619 66.744 ;
     RECT  25.429 79.68 25.621 81.096 ;
     RECT  25.429 86.64 25.657 87.24 ;
     RECT  24.304 88.416 25.657 129.24 ;
     RECT  25.525 16.512 25.667 19.512 ;
     RECT  25.667 18 25.697 19.512 ;
     RECT  25.621 79.68 25.733 81.528 ;
     RECT  25.619 26.448 25.763 66.744 ;
     RECT  25.445 2.304 25.765 8.328 ;
     RECT  25.765 79.392 25.813 79.416 ;
     RECT  25.657 86.64 25.841 129.24 ;
     RECT  25.801 78.048 25.859 78.072 ;
     RECT  25.813 79.2 25.859 79.416 ;
     RECT  25.763 66.48 25.861 66.744 ;
     RECT  25.841 86.64 25.873 124.824 ;
     RECT  25.841 126.336 25.877 129.24 ;
     RECT  25.619 24.768 25.907 25.368 ;
     RECT  25.763 26.448 25.913 65.352 ;
     RECT  25.877 126.336 25.913 126.36 ;
     RECT  24.437 142.752 25.913 142.776 ;
     RECT  25.441 0.096 25.985 0.552 ;
     RECT  24.545 130.224 26.003 131.352 ;
     RECT  26.005 13.632 26.057 13.656 ;
     RECT  25.667 16.512 26.093 16.92 ;
     RECT  25.985 0.288 26.099 0.552 ;
     RECT  25.861 66.48 26.099 67.272 ;
     RECT  26.093 16.512 26.101 16.536 ;
     RECT  25.765 2.208 26.147 8.328 ;
     RECT  26.089 74.688 26.147 74.712 ;
     RECT  26.101 9.408 26.165 9.432 ;
     RECT  25.733 80.784 26.165 81.528 ;
     RECT  26.099 66.672 26.195 66.696 ;
     RECT  25.873 86.016 26.195 124.824 ;
     RECT  26.147 2.208 26.273 7.464 ;
     RECT  26.273 2.208 26.305 6.888 ;
     RECT  26.305 2.16 26.309 6.888 ;
     RECT  25.697 18 26.381 18.216 ;
     RECT  25.589 10.512 26.387 10.536 ;
     RECT  25.913 26.544 26.387 65.352 ;
     RECT  25.859 79.2 26.417 79.272 ;
     RECT  26.387 64.8 26.453 65.352 ;
     RECT  25.945 71.232 26.485 71.256 ;
     RECT  26.381 18.192 26.561 18.216 ;
     RECT  26.533 83.664 26.593 83.688 ;
     RECT  26.593 83.664 26.675 83.784 ;
     RECT  25.553 21.024 26.677 23.304 ;
     RECT  26.417 79.248 26.723 79.272 ;
     RECT  26.101 15.888 26.725 16.536 ;
     RECT  26.725 15.648 26.777 16.536 ;
     RECT  26.677 20.496 26.777 23.304 ;
     RECT  26.845 125.856 26.953 125.88 ;
     RECT  26.777 20.736 26.989 23.304 ;
     RECT  26.485 70.992 27.011 71.256 ;
     RECT  26.099 0.288 27.061 0.504 ;
     RECT  25.697 19.488 27.061 19.512 ;
     RECT  26.309 2.16 27.107 6.744 ;
     RECT  27.061 69.504 27.107 69.528 ;
     RECT  26.453 64.848 27.155 65.352 ;
     RECT  27.155 65.088 27.157 65.352 ;
     RECT  25.877 127.344 27.169 129.24 ;
     RECT  26.003 130.224 27.169 130.248 ;
     RECT  27.107 2.16 27.203 5.4 ;
     RECT  27.097 68.352 27.203 68.376 ;
     RECT  27.061 0.24 27.205 0.504 ;
     RECT  25.907 24.768 27.205 25.32 ;
     RECT  27.205 0.192 27.277 0.504 ;
     RECT  26.195 87.264 27.313 124.824 ;
     RECT  26.953 125.856 27.313 125.976 ;
     RECT  27.277 0.096 27.347 0.504 ;
     RECT  27.107 6.528 27.347 6.744 ;
     RECT  26.675 83.76 27.349 83.784 ;
     RECT  26.195 86.016 27.349 86.04 ;
     RECT  27.313 87.264 27.349 125.976 ;
     RECT  27.347 0.144 27.385 0.504 ;
     RECT  27.205 24.768 27.385 25.368 ;
     RECT  27.349 86.016 27.385 125.976 ;
     RECT  27.169 127.344 27.385 130.248 ;
     RECT  27.203 2.832 27.395 5.4 ;
     RECT  27.277 84.96 27.395 84.984 ;
     RECT  27.385 0.144 27.397 0.552 ;
     RECT  27.385 86.016 27.445 130.248 ;
     RECT  26.003 131.328 27.445 131.352 ;
     RECT  27.385 24.72 27.457 25.368 ;
     RECT  26.387 26.544 27.457 63.432 ;
     RECT  27.397 0.144 27.539 0.648 ;
     RECT  26.777 16.512 27.539 16.536 ;
     RECT  27.493 74.064 27.539 74.088 ;
     RECT  27.445 82.608 27.541 82.632 ;
     RECT  27.061 18.576 27.641 19.512 ;
     RECT  27.589 70.656 27.641 70.68 ;
     RECT  27.395 3.552 27.683 5.4 ;
     RECT  24.545 144.288 27.713 151.176 ;
     RECT  27.541 82.608 27.749 82.68 ;
     RECT  27.749 82.656 27.781 82.68 ;
     RECT  27.445 86.016 27.827 131.352 ;
     RECT  27.457 24.72 27.853 63.432 ;
     RECT  27.829 78.672 27.853 78.696 ;
     RECT  27.853 24.72 27.877 63.528 ;
     RECT  27.349 83.76 27.877 83.832 ;
     RECT  27.877 24.72 27.889 63.624 ;
     RECT  25.589 12.288 27.893 12.312 ;
     RECT  27.539 0.144 27.923 0.6 ;
     RECT  27.853 78.576 27.923 78.696 ;
     RECT  27.889 24.624 27.925 63.624 ;
     RECT  27.349 81.024 27.961 81.048 ;
     RECT  27.733 75.264 27.965 75.288 ;
     RECT  27.781 82.656 27.965 82.728 ;
     RECT  27.827 86.4 27.965 131.352 ;
     RECT  26.989 20.736 27.973 23.352 ;
     RECT  27.925 24.432 27.973 63.912 ;
     RECT  27.157 65.088 27.973 65.832 ;
     RECT  27.965 82.704 27.973 82.728 ;
     RECT  27.877 83.76 27.973 84.216 ;
     RECT  27.961 81.024 28.019 81.48 ;
     RECT  27.973 20.736 28.033 63.912 ;
     RECT  28.021 71.232 28.073 71.256 ;
     RECT  27.923 0.288 28.109 0.6 ;
     RECT  28.033 20.592 28.152 63.912 ;
     RECT  27.973 65.088 28.152 66.696 ;
     RECT  28.152 20.592 28.165 66.696 ;
     RECT  28.165 20.592 28.259 67.272 ;
     RECT  28.177 136.56 28.259 136.584 ;
     RECT  27.923 78.672 28.307 78.696 ;
     RECT  28.309 14.016 28.393 14.04 ;
     RECT  28.393 13.056 28.397 14.04 ;
     RECT  27.965 131.328 28.537 131.352 ;
     RECT  27.713 144.288 28.645 151.08 ;
     RECT  28.019 81.024 28.789 81.048 ;
     RECT  28.501 141.168 29.005 141.192 ;
     RECT  29.005 2.352 29.077 2.376 ;
     RECT  28.645 143.856 29.077 151.08 ;
     RECT  28.789 80.928 29.125 81.048 ;
     RECT  28.573 132.624 29.173 132.648 ;
     RECT  29.005 141.168 29.173 141.96 ;
     RECT  27.641 18.576 29.185 19.368 ;
     RECT  28.259 20.592 29.185 65.832 ;
     RECT  29.077 143.568 29.221 151.08 ;
     RECT  28.109 0.288 29.269 0.552 ;
     RECT  27.683 3.552 29.269 4.536 ;
     RECT  29.173 140.784 29.269 141.96 ;
     RECT  29.077 2.304 29.293 2.376 ;
     RECT  29.269 3.552 29.293 4.68 ;
     RECT  29.125 80.352 29.293 81.048 ;
     RECT  29.269 0.192 29.317 0.552 ;
     RECT  29.293 2.304 29.329 4.68 ;
     RECT  29.329 2.256 29.365 4.68 ;
     RECT  29.365 2.016 29.408 4.68 ;
     RECT  29.077 11.376 29.408 11.4 ;
     RECT  28.397 13.056 29.408 13.08 ;
     RECT  29.185 18.576 29.408 65.832 ;
     RECT  28.259 67.248 29.408 67.272 ;
     RECT  28.693 76.128 29.408 76.152 ;
     RECT  28.969 78.624 29.408 78.648 ;
     RECT  29.293 80.352 29.408 81.096 ;
     RECT  27.973 82.704 29.408 84.216 ;
     RECT  27.965 86.4 29.408 130.296 ;
     RECT  28.537 131.328 29.408 131.592 ;
     RECT  29.173 132.624 29.408 132.792 ;
     RECT  28.501 134.544 29.408 134.568 ;
     RECT  29.269 136.176 29.408 136.2 ;
     RECT  27.829 138.528 29.408 138.552 ;
     RECT  29.269 139.92 29.408 141.96 ;
     RECT  29.221 143.568 29.408 151.128 ;
     RECT  29.408 2.016 29.459 65.832 ;
     RECT  29.459 2.148 29.512 65.832 ;
     RECT  29.408 66.948 29.512 84.252 ;
     RECT  29.512 2.256 29.704 65.832 ;
     RECT  29.512 67.218 29.704 84.216 ;
     RECT  29.408 86.4 29.704 151.128 ;
     RECT  29.704 2.256 29.729 2.904 ;
     RECT  29.704 81.072 29.873 81.096 ;
     RECT  29.704 78.624 29.909 79.656 ;
     RECT  29.704 140.928 29.909 140.952 ;
     RECT  29.704 86.4 29.939 133.416 ;
     RECT  29.704 82.704 29.981 84.216 ;
     RECT  29.981 83.664 29.987 84.216 ;
     RECT  29.317 0.096 30.037 0.552 ;
     RECT  30.037 0.096 30.125 0.648 ;
     RECT  30.125 0.096 30.131 0.552 ;
     RECT  29.704 20.304 30.131 65.832 ;
     RECT  29.729 2.256 30.161 2.76 ;
     RECT  29.704 11.856 30.161 11.88 ;
     RECT  30.161 2.256 30.227 2.28 ;
     RECT  29.909 78.624 30.233 79.176 ;
     RECT  30.131 20.88 30.269 65.832 ;
     RECT  29.704 72.384 30.275 72.984 ;
     RECT  30.233 79.152 30.275 79.176 ;
     RECT  29.939 86.4 30.275 131.352 ;
     RECT  30.269 20.976 30.323 65.832 ;
     RECT  29.987 83.664 30.371 83.688 ;
     RECT  29.939 132.768 30.371 133.416 ;
     RECT  30.275 72.96 30.413 72.984 ;
     RECT  30.131 0.096 30.611 0.456 ;
     RECT  30.611 0.096 30.707 0.408 ;
     RECT  30.697 139.056 30.757 139.08 ;
     RECT  29.704 144.288 30.769 151.128 ;
     RECT  29.704 135.6 30.851 135.624 ;
     RECT  30.371 132.768 30.899 132.792 ;
     RECT  30.757 138.48 30.899 139.08 ;
     RECT  30.757 142.416 30.899 142.536 ;
     RECT  29.704 4.512 30.901 4.536 ;
     RECT  30.757 134.4 30.901 134.568 ;
     RECT  30.901 3.696 30.953 4.536 ;
     RECT  30.901 134.4 30.953 135.144 ;
     RECT  30.953 134.4 30.995 134.52 ;
     RECT  30.275 86.4 31.091 129.24 ;
     RECT  30.995 134.496 31.091 134.52 ;
     RECT  30.953 4.128 31.129 4.536 ;
     RECT  31.045 83.76 31.133 83.784 ;
     RECT  30.707 0.096 31.187 0.312 ;
     RECT  31.129 4.128 31.187 5.112 ;
     RECT  30.841 11.328 31.187 11.352 ;
     RECT  31.091 86.4 31.205 128.28 ;
     RECT  31.285 72.912 31.349 72.936 ;
     RECT  30.899 139.056 31.379 139.08 ;
     RECT  30.323 20.976 31.637 21.912 ;
     RECT  31.187 0.288 31.667 0.312 ;
     RECT  30.275 130.416 31.849 131.352 ;
     RECT  31.849 129.936 31.907 131.352 ;
     RECT  31.909 66.96 31.961 66.984 ;
     RECT  30.323 23.04 32.051 65.832 ;
     RECT  32.149 84.192 32.245 84.216 ;
     RECT  32.245 83.808 32.291 84.216 ;
     RECT  32.291 84.192 32.609 84.216 ;
     RECT  32.051 23.04 33.001 65.304 ;
     RECT  31.637 20.976 33.037 21.672 ;
     RECT  33.001 22.752 33.107 65.304 ;
     RECT  33.217 129.696 33.433 129.72 ;
     RECT  33.433 129.408 33.637 129.72 ;
     RECT  33.637 129.408 33.725 130.008 ;
     RECT  30.769 144.288 33.733 151.176 ;
     RECT  33.107 23.04 34.301 65.304 ;
     RECT  33.725 129.408 34.769 129.72 ;
     RECT  31.187 4.128 34.808 4.536 ;
     RECT  33.037 20.592 34.808 21.672 ;
     RECT  32.149 67.824 34.808 67.848 ;
     RECT  34.769 129.456 34.808 129.72 ;
     RECT  31.907 131.328 34.808 131.352 ;
     RECT  34.765 141.936 34.808 141.96 ;
     RECT  33.733 144.048 34.808 151.176 ;
     RECT  34.808 2.148 34.912 21.672 ;
     RECT  34.808 66.948 34.912 84.252 ;
     RECT  34.912 2.418 35.104 21.672 ;
     RECT  34.912 67.218 35.104 83.982 ;
     RECT  34.808 129.456 35.104 151.176 ;
     RECT  35.104 129.456 35.219 130.536 ;
     RECT  35.104 4.128 35.273 4.536 ;
     RECT  35.219 130.512 35.315 130.536 ;
     RECT  35.104 141.264 35.345 141.96 ;
     RECT  35.104 144.048 35.453 151.176 ;
     RECT  35.219 129.456 35.737 129.48 ;
     RECT  35.104 21.648 35.939 21.672 ;
     RECT  35.737 129.408 36.313 129.48 ;
     RECT  36.421 67.056 36.467 67.08 ;
     RECT  36.313 129.408 36.493 130.008 ;
     RECT  35.104 20.592 36.515 20.616 ;
     RECT  35.453 144.048 36.515 151.128 ;
     RECT  36.493 129.408 36.563 130.152 ;
     RECT  36.563 129.408 37.043 130.104 ;
     RECT  37.043 129.408 37.619 129.96 ;
     RECT  36.515 144.288 38.437 151.128 ;
     RECT  35.345 141.936 38.579 141.96 ;
     RECT  37.619 129.408 39.589 129.864 ;
     RECT  39.541 67.056 39.697 67.08 ;
     RECT  39.697 66.72 39.779 67.08 ;
     RECT  35.273 4.512 40.208 4.536 ;
     RECT  39.733 6.096 40.208 6.12 ;
     RECT  39.779 66.948 40.208 67.08 ;
     RECT  39.589 129.408 40.208 130.008 ;
     RECT  36.709 131.904 40.208 131.928 ;
     RECT  36.901 133.152 40.208 133.176 ;
     RECT  38.437 143.952 40.208 151.128 ;
     RECT  40.208 2.148 40.312 21.612 ;
     RECT  40.208 66.948 40.312 84.252 ;
     RECT  40.312 2.418 40.504 21.342 ;
     RECT  40.312 67.218 40.504 83.982 ;
     RECT  40.208 129.408 40.504 151.128 ;
     RECT  40.504 129.408 40.643 129.96 ;
     RECT  40.504 6.096 40.853 6.12 ;
     RECT  41.857 129.792 42.073 129.816 ;
     RECT  42.073 129.408 42.757 129.816 ;
     RECT  42.757 129.408 43.187 129.96 ;
     RECT  43.187 129.408 43.193 129.72 ;
     RECT  43.193 129.696 43.331 129.72 ;
     RECT  43.981 67.248 44.051 67.272 ;
     RECT  40.504 143.952 44.273 151.128 ;
     RECT  44.273 143.952 44.597 146.424 ;
     RECT  44.965 129.936 45.013 129.96 ;
     RECT  45.013 66.72 45.065 66.744 ;
     RECT  45.013 129.552 45.137 129.96 ;
     RECT  40.504 4.512 45.608 4.536 ;
     RECT  43.573 22.464 45.608 22.488 ;
     RECT  45.277 66.948 45.608 67.32 ;
     RECT  45.137 129.588 45.608 129.96 ;
     RECT  40.504 131.904 45.608 131.928 ;
     RECT  40.504 133.152 45.608 133.176 ;
     RECT  40.504 134.784 45.608 134.808 ;
     RECT  44.597 143.952 45.608 146.232 ;
     RECT  44.273 147.504 45.608 151.128 ;
     RECT  45.608 2.148 45.712 22.488 ;
     RECT  45.608 66.948 45.712 84.252 ;
     RECT  45.608 129.588 45.712 151.128 ;
     RECT  45.712 2.418 45.904 21.342 ;
     RECT  45.712 67.218 45.904 83.982 ;
     RECT  45.712 129.858 45.904 151.128 ;
     RECT  45.904 147.504 45.965 151.128 ;
     RECT  45.904 129.858 46.361 130.632 ;
     RECT  46.361 129.858 46.753 129.96 ;
     RECT  45.904 3.936 46.787 4.584 ;
     RECT  45.904 145.584 46.865 146.232 ;
     RECT  46.753 129.648 46.933 129.96 ;
     RECT  46.933 129.408 46.979 129.96 ;
     RECT  46.865 145.92 46.979 146.232 ;
     RECT  45.904 67.296 47.027 67.32 ;
     RECT  46.787 3.936 47.315 4.536 ;
     RECT  46.979 129.648 47.315 129.96 ;
     RECT  46.981 17.088 47.405 17.112 ;
     RECT  45.965 148.032 47.405 151.128 ;
     RECT  47.405 148.032 47.411 151.032 ;
     RECT  47.437 130.08 47.507 130.488 ;
     RECT  47.411 148.032 47.689 150.696 ;
     RECT  45.904 134.784 47.909 134.808 ;
     RECT  47.507 130.08 47.939 130.104 ;
     RECT  47.893 67.248 48.053 67.272 ;
     RECT  46.979 146.208 48.121 146.232 ;
     RECT  47.689 147.648 48.121 150.696 ;
     RECT  48.121 146.208 48.161 150.696 ;
     RECT  48.161 147.072 48.179 150.696 ;
     RECT  48.179 148.032 48.733 150.696 ;
     RECT  48.805 83.952 48.812 83.976 ;
     RECT  48.812 83.948 48.949 83.98 ;
     RECT  48.949 83.952 48.953 83.98 ;
     RECT  48.469 129.84 48.997 129.864 ;
     RECT  49.045 84.192 49.133 84.216 ;
     RECT  45.904 144.336 49.139 144.36 ;
     RECT  48.733 148.032 49.165 150.792 ;
     RECT  48.997 129.504 49.493 129.864 ;
     RECT  45.904 131.904 49.781 131.928 ;
     RECT  49.165 147.072 49.907 150.792 ;
     RECT  49.907 149.088 50.291 150.792 ;
     RECT  50.291 150.384 50.353 150.792 ;
     RECT  49.633 129.936 50.713 130.008 ;
     RECT  50.713 129.936 50.821 130.536 ;
     RECT  50.353 150.384 50.867 151.032 ;
     RECT  34.301 23.76 50.929 65.304 ;
     RECT  49.201 66.384 50.929 66.408 ;
     RECT  50.867 150.432 50.963 151.032 ;
     RECT  47.315 4.272 51.008 4.536 ;
     RECT  50.869 8.16 51.008 8.184 ;
     RECT  45.712 22.464 51.008 22.488 ;
     RECT  50.929 23.76 51.008 66.408 ;
     RECT  50.821 129.6 51.008 130.536 ;
     RECT  49.907 147.072 51.008 147.768 ;
     RECT  50.291 149.088 51.008 149.352 ;
     RECT  51.008 2.148 51.112 22.488 ;
     RECT  51.008 23.76 51.112 84.252 ;
     RECT  51.008 129.588 51.112 149.352 ;
     RECT  50.963 150.432 51.155 150.936 ;
     RECT  51.112 129.858 51.251 149.352 ;
     RECT  51.112 2.418 51.304 21.342 ;
     RECT  51.112 23.76 51.304 83.982 ;
     RECT  51.251 129.858 51.304 148.782 ;
     RECT  51.155 150.432 51.347 150.456 ;
     RECT  51.304 4.512 51.587 4.824 ;
     RECT  51.304 129.984 51.869 130.104 ;
     RECT  51.869 130.08 51.905 130.104 ;
     RECT  51.304 23.76 52.067 66.408 ;
     RECT  51.304 8.496 52.085 8.52 ;
     RECT  52.357 130.176 52.453 130.2 ;
     RECT  52.453 130.176 52.589 130.248 ;
     RECT  52.589 130.224 52.697 130.248 ;
     RECT  51.304 147.744 53.603 147.768 ;
     RECT  52.067 66.384 54.169 66.408 ;
     RECT  54.169 66.384 54.227 66.744 ;
     RECT  52.067 23.76 54.317 65.304 ;
     RECT  55.213 130.32 55.283 130.344 ;
     RECT  51.587 4.512 55.969 4.536 ;
     RECT  54.181 6 55.969 6.024 ;
     RECT  55.969 4.512 56.408 6.024 ;
     RECT  51.112 22.464 56.408 22.488 ;
     RECT  54.227 66.384 56.408 66.408 ;
     RECT  55.285 129.792 56.408 129.816 ;
     RECT  56.408 2.148 56.512 22.488 ;
     RECT  56.408 66.384 56.512 84.252 ;
     RECT  56.408 129.588 56.512 149.052 ;
     RECT  56.512 2.418 56.704 21.342 ;
     RECT  56.512 66.384 56.704 83.982 ;
     RECT  56.512 129.858 56.704 148.782 ;
     RECT  56.704 6 56.945 6.024 ;
     RECT  56.704 129.858 57.491 130.344 ;
     RECT  57.589 129.744 57.773 129.768 ;
     RECT  56.704 4.512 60.421 4.536 ;
     RECT  60.421 130.56 60.545 130.584 ;
     RECT  60.421 4.512 60.565 4.968 ;
     RECT  60.565 4.512 60.617 5.352 ;
     RECT  60.617 4.512 61.808 4.968 ;
     RECT  56.512 22.464 61.808 22.488 ;
     RECT  56.704 66.384 61.808 66.408 ;
     RECT  61.573 130.272 61.808 130.296 ;
     RECT  61.808 2.148 61.912 22.488 ;
     RECT  61.808 66.384 61.912 84.252 ;
     RECT  61.808 129.588 61.912 149.052 ;
     RECT  61.912 2.418 62.104 21.342 ;
     RECT  61.912 66.384 62.104 83.982 ;
     RECT  61.912 129.858 62.104 148.782 ;
     RECT  62.104 4.512 63.961 4.536 ;
     RECT  63.961 4.512 64.969 4.68 ;
     RECT  64.969 4.512 65.027 5.112 ;
     RECT  64.981 129.648 65.045 130.2 ;
     RECT  65.045 129.648 65.333 129.672 ;
     RECT  65.027 4.512 67.208 4.536 ;
     RECT  61.912 22.464 67.208 22.488 ;
     RECT  62.104 66.384 67.208 66.408 ;
     RECT  67.208 2.148 67.312 22.488 ;
     RECT  67.208 66.384 67.312 84.252 ;
     RECT  67.208 129.588 67.312 149.052 ;
     RECT  67.312 2.418 67.504 21.342 ;
     RECT  67.312 66.384 67.504 83.982 ;
     RECT  67.312 129.858 67.504 148.782 ;
     RECT  68.605 74.64 68.609 74.664 ;
     RECT  68.609 74.636 68.668 74.668 ;
     RECT  68.668 74.64 68.675 74.664 ;
     RECT  70.153 74.112 70.645 74.136 ;
     RECT  70.645 73.392 70.691 74.136 ;
     RECT  70.691 73.392 70.693 73.416 ;
     RECT  70.693 73.2 70.733 73.416 ;
     RECT  67.504 66.384 70.981 66.408 ;
     RECT  70.981 66.384 71.027 67.272 ;
     RECT  70.733 73.2 71.057 73.224 ;
     RECT  67.504 4.512 72.608 4.536 ;
     RECT  67.312 22.464 72.608 22.488 ;
     RECT  71.027 66.384 72.608 66.408 ;
     RECT  72.457 67.44 72.608 67.464 ;
     RECT  72.608 2.148 72.712 22.488 ;
     RECT  72.608 66.384 72.712 84.252 ;
     RECT  72.608 129.588 72.712 149.052 ;
     RECT  72.712 2.418 72.904 21.342 ;
     RECT  72.712 66.384 72.904 83.982 ;
     RECT  72.712 129.858 72.904 148.782 ;
     RECT  74.677 2.832 74.945 2.856 ;
     RECT  75.769 7.44 75.827 7.464 ;
     RECT  75.769 83.52 75.827 83.544 ;
     RECT  76.093 83.76 76.163 83.784 ;
     RECT  72.904 66.384 76.357 66.408 ;
     RECT  76.357 66.384 76.421 67.272 ;
     RECT  76.421 66.384 76.451 66.984 ;
     RECT  76.451 66.384 77.893 66.408 ;
     RECT  72.904 4.512 78.008 4.536 ;
     RECT  72.712 22.464 78.008 22.488 ;
     RECT  77.893 66.384 78.008 67.272 ;
     RECT  78.008 2.148 78.112 22.488 ;
     RECT  78.008 66.384 78.112 84.252 ;
     RECT  78.008 129.588 78.112 149.052 ;
     RECT  78.112 2.418 78.304 21.342 ;
     RECT  78.112 66.384 78.304 83.982 ;
     RECT  78.112 129.858 78.304 148.782 ;
     RECT  78.304 4.512 80.821 4.536 ;
     RECT  80.821 4.464 80.885 4.536 ;
     RECT  80.917 83.568 81.209 83.592 ;
     RECT  82.021 83.712 82.073 83.736 ;
     RECT  82.141 7.104 82.501 7.128 ;
     RECT  80.885 4.512 83.408 4.536 ;
     RECT  82.501 7.104 83.408 7.416 ;
     RECT  78.112 22.464 83.408 22.488 ;
     RECT  78.304 66.384 83.408 66.408 ;
     RECT  83.408 2.148 83.512 22.488 ;
     RECT  83.408 66.384 83.512 84.252 ;
     RECT  83.408 129.588 83.512 149.052 ;
     RECT  83.512 2.418 83.704 21.342 ;
     RECT  83.512 66.384 83.704 83.982 ;
     RECT  83.512 129.858 83.704 148.782 ;
     RECT  87.613 130.224 87.779 130.248 ;
     RECT  83.704 66.384 88.067 66.408 ;
     RECT  88.477 66.672 88.549 66.696 ;
     RECT  83.704 4.512 88.808 4.536 ;
     RECT  88.021 6.096 88.808 6.12 ;
     RECT  83.512 22.464 88.808 22.488 ;
     RECT  88.549 66.672 88.808 66.744 ;
     RECT  87.901 130.464 88.808 130.488 ;
     RECT  88.808 2.148 88.912 22.488 ;
     RECT  88.808 66.672 88.912 84.252 ;
     RECT  88.808 129.588 88.912 149.052 ;
     RECT  88.912 2.418 89.104 21.342 ;
     RECT  88.912 66.672 89.104 83.982 ;
     RECT  88.912 129.858 89.104 148.782 ;
     RECT  89.104 3.6 89.597 4.536 ;
     RECT  89.597 3.744 90.101 4.536 ;
     RECT  90.101 3.744 90.563 3.768 ;
     RECT  89.104 66.672 90.563 66.696 ;
     RECT  90.241 130.128 90.611 130.152 ;
     RECT  54.317 23.76 91.475 65.256 ;
     RECT  91.285 3.312 91.763 3.336 ;
     RECT  89.104 6.096 94.208 6.12 ;
     RECT  91.429 8.784 94.208 8.808 ;
     RECT  88.912 22.464 94.208 22.488 ;
     RECT  94.069 129.936 94.208 129.96 ;
     RECT  94.208 2.148 94.312 22.488 ;
     RECT  94.208 66.948 94.312 84.252 ;
     RECT  94.208 129.588 94.312 149.052 ;
     RECT  94.312 2.418 94.504 21.342 ;
     RECT  94.312 67.218 94.504 83.982 ;
     RECT  94.312 129.858 94.504 148.782 ;
     RECT  94.504 3.312 94.889 3.336 ;
     RECT  94.504 129.936 95.747 129.96 ;
     RECT  94.504 6.096 98.149 6.12 ;
     RECT  98.149 5.424 98.201 6.12 ;
     RECT  98.149 4.368 98.237 4.392 ;
     RECT  98.201 6.096 99.608 6.12 ;
     RECT  94.504 8.688 99.608 8.712 ;
     RECT  94.312 22.464 99.608 22.488 ;
     RECT  99.349 130.128 99.608 130.152 ;
     RECT  99.608 2.148 99.712 22.488 ;
     RECT  99.608 66.948 99.712 84.252 ;
     RECT  99.608 129.588 99.712 149.052 ;
     RECT  99.712 2.418 99.904 21.342 ;
     RECT  99.712 67.056 99.904 83.982 ;
     RECT  99.712 129.858 99.904 148.782 ;
     RECT  99.904 67.056 100.307 67.224 ;
     RECT  100.307 67.2 100.499 67.224 ;
     RECT  100.969 129.936 101.027 129.96 ;
     RECT  102.037 130.56 102.085 130.584 ;
     RECT  102.085 130.56 102.661 130.728 ;
     RECT  102.661 130.512 102.733 130.728 ;
     RECT  102.733 129.552 102.773 130.728 ;
     RECT  102.625 67.008 102.805 67.032 ;
     RECT  102.805 67.008 102.851 67.272 ;
     RECT  102.773 130.56 102.917 130.728 ;
     RECT  102.851 67.008 103.187 67.032 ;
     RECT  102.773 129.552 103.187 129.576 ;
     RECT  102.917 130.56 103.475 130.584 ;
     RECT  99.904 8.688 103.633 8.712 ;
     RECT  99.904 6.096 103.813 6.12 ;
     RECT  103.813 5.712 103.859 6.12 ;
     RECT  103.859 6.096 105.008 6.12 ;
     RECT  103.633 7.872 105.008 8.712 ;
     RECT  99.712 22.464 105.008 22.488 ;
     RECT  104.029 130.032 105.008 130.248 ;
     RECT  105.008 2.148 105.112 22.488 ;
     RECT  105.008 66.948 105.112 84.252 ;
     RECT  105.008 129.588 105.112 149.052 ;
     RECT  105.112 2.418 105.304 21.342 ;
     RECT  105.112 67.218 105.304 83.982 ;
     RECT  105.112 129.696 105.304 148.782 ;
     RECT  105.304 129.696 105.443 130.248 ;
     RECT  105.443 130.032 105.581 130.056 ;
     RECT  105.112 22.464 105.869 22.488 ;
     RECT  105.304 3.936 106.265 3.96 ;
     RECT  106.333 66.912 106.549 66.936 ;
     RECT  106.549 66.912 106.595 67.272 ;
     RECT  106.405 129.648 106.595 129.672 ;
     RECT  106.789 129.936 106.877 129.96 ;
     RECT  107.485 66.72 107.593 66.744 ;
     RECT  107.521 3.936 107.603 3.96 ;
     RECT  107.845 21.552 108.133 21.576 ;
     RECT  108.133 21.264 108.313 21.576 ;
     RECT  108.241 129.456 108.325 129.48 ;
     RECT  108.325 129.456 108.493 130.248 ;
     RECT  108.313 21.264 108.601 21.672 ;
     RECT  108.601 21.168 108.673 21.672 ;
     RECT  107.593 66.72 108.757 67.272 ;
     RECT  108.757 66.72 108.805 67.704 ;
     RECT  108.673 21.12 109.381 21.672 ;
     RECT  80.917 0.048 109.525 0.072 ;
     RECT  109.609 3.936 109.621 3.96 ;
     RECT  109.525 0.048 109.717 0.168 ;
     RECT  109.717 0.048 109.753 1.032 ;
     RECT  109.621 3.936 109.753 4.392 ;
     RECT  109.753 3.024 109.933 4.392 ;
     RECT  109.753 0.048 110.005 1.128 ;
     RECT  109.933 2.784 110.005 4.392 ;
     RECT  105.304 6.096 110.077 6.12 ;
     RECT  110.077 5.856 110.149 6.12 ;
     RECT  91.475 23.76 110.149 64.824 ;
     RECT  110.149 5.856 110.185 6.168 ;
     RECT  110.005 0.048 110.195 4.392 ;
     RECT  108.805 66.72 110.291 67.8 ;
     RECT  108.493 129.408 110.291 130.248 ;
     RECT  109.381 20.544 110.297 21.672 ;
     RECT  110.291 129.504 110.339 130.248 ;
     RECT  110.195 2.148 110.408 4.392 ;
     RECT  110.185 5.712 110.408 6.168 ;
     RECT  105.304 8.688 110.408 8.712 ;
     RECT  110.297 20.544 110.408 21.612 ;
     RECT  110.291 66.948 110.408 67.8 ;
     RECT  110.339 129.588 110.408 130.248 ;
     RECT  110.195 0.048 110.483 1.128 ;
     RECT  110.408 2.148 110.512 21.612 ;
     RECT  110.408 66.948 110.512 84.252 ;
     RECT  110.408 129.588 110.512 149.052 ;
     RECT  110.483 0.048 110.675 1.032 ;
     RECT  110.512 2.304 110.704 21.342 ;
     RECT  110.512 66.948 110.704 83.982 ;
     RECT  110.512 129.858 110.704 148.782 ;
     RECT  110.704 21.12 110.867 21.144 ;
     RECT  110.149 22.8 110.915 64.824 ;
     RECT  111.265 66.72 111.347 66.744 ;
     RECT  110.704 2.304 111.841 8.712 ;
     RECT  110.675 0.048 112.057 0.6 ;
     RECT  111.841 2.304 112.057 9.48 ;
     RECT  110.915 23.76 112.117 64.824 ;
     RECT  112.057 2.304 112.313 9.72 ;
     RECT  112.057 0.048 112.345 1.128 ;
     RECT  112.345 0.048 112.357 1.224 ;
     RECT  112.357 0.048 112.595 1.272 ;
     RECT  112.313 2.736 112.595 9.72 ;
     RECT  112.595 0.048 112.691 1.224 ;
     RECT  112.595 2.736 112.781 9.24 ;
     RECT  112.691 1.152 112.787 1.224 ;
     RECT  112.781 2.736 112.835 6.312 ;
     RECT  112.787 1.152 112.883 1.176 ;
     RECT  112.549 80.928 112.925 80.952 ;
     RECT  112.835 2.736 113.317 3.528 ;
     RECT  112.781 7.488 113.605 9.24 ;
     RECT  112.835 4.512 113.797 6.312 ;
     RECT  113.605 7.488 113.797 9.72 ;
     RECT  112.117 23.76 113.797 65.256 ;
     RECT  113.269 66.384 113.797 66.408 ;
     RECT  113.317 2.304 113.897 3.528 ;
     RECT  113.797 4.512 113.969 9.72 ;
     RECT  112.691 0.048 113.989 0.12 ;
     RECT  113.969 8.688 114.041 9.72 ;
     RECT  114.041 9.072 114.275 9.72 ;
     RECT  114.217 82.656 114.275 82.68 ;
     RECT  113.897 3.12 114.361 3.528 ;
     RECT  113.969 4.512 114.361 7.608 ;
     RECT  114.361 3.12 114.467 7.608 ;
     RECT  113.989 0.048 114.469 0.168 ;
     RECT  114.469 0.048 114.611 1.128 ;
     RECT  114.467 3.12 114.653 7.368 ;
     RECT  114.611 0.048 114.851 0.168 ;
     RECT  114.805 1.152 114.947 1.176 ;
     RECT  114.653 3.12 114.949 4.632 ;
     RECT  114.757 22.224 115.153 22.248 ;
     RECT  114.275 9.072 115.189 9.096 ;
     RECT  115.333 82.704 115.405 82.728 ;
     RECT  115.189 8.496 115.441 9.096 ;
     RECT  114.949 2.304 115.621 4.632 ;
     RECT  114.653 5.712 115.621 7.224 ;
     RECT  115.621 2.304 115.669 7.224 ;
     RECT  115.441 8.496 115.669 9.432 ;
     RECT  114.865 14.784 115.765 14.808 ;
     RECT  115.669 2.256 115.801 9.432 ;
     RECT  115.657 10.848 115.801 10.872 ;
     RECT  115.801 2.256 115.808 10.872 ;
     RECT  115.765 14.112 115.808 14.808 ;
     RECT  115.153 22.224 115.808 22.296 ;
     RECT  113.797 23.76 115.808 66.408 ;
     RECT  114.709 75.504 115.808 75.528 ;
     RECT  115.189 80.928 115.808 80.952 ;
     RECT  115.405 82.656 115.808 82.728 ;
     RECT  115.621 83.808 115.808 83.832 ;
     RECT  115.808 2.148 115.912 22.296 ;
     RECT  115.808 23.76 115.912 84.252 ;
     RECT  115.808 129.588 115.912 149.052 ;
     RECT  115.912 2.256 116.051 22.296 ;
     RECT  114.851 0.048 116.101 0.12 ;
     RECT  116.051 2.418 116.104 22.296 ;
     RECT  115.912 23.76 116.104 83.982 ;
     RECT  115.912 129.858 116.104 148.782 ;
     RECT  116.101 0.048 116.197 0.168 ;
     RECT  116.104 18.144 116.243 18.168 ;
     RECT  116.104 19.392 116.243 19.416 ;
     RECT  116.197 0.048 116.293 0.264 ;
     RECT  116.104 22.224 116.339 22.296 ;
     RECT  116.104 77.52 116.339 78.36 ;
     RECT  116.104 2.418 116.489 12.36 ;
     RECT  116.104 13.44 116.489 14.136 ;
     RECT  116.293 0.048 116.533 0.312 ;
     RECT  116.533 0.048 116.675 1.176 ;
     RECT  116.489 2.418 117.061 11.544 ;
     RECT  116.339 22.272 117.155 22.296 ;
     RECT  116.489 13.632 117.203 14.136 ;
     RECT  116.104 16.56 117.205 17.112 ;
     RECT  117.205 16.56 117.251 17.64 ;
     RECT  117.205 18.816 117.277 18.84 ;
     RECT  117.277 18.576 117.389 18.84 ;
     RECT  117.133 15.36 117.445 15.384 ;
     RECT  117.421 83.808 117.491 83.832 ;
     RECT  116.339 78.336 117.637 78.36 ;
     RECT  117.529 79.44 117.637 79.464 ;
     RECT  116.104 23.76 117.713 66.408 ;
     RECT  117.637 78.336 117.713 79.464 ;
     RECT  117.541 13.104 117.745 13.128 ;
     RECT  117.713 23.76 117.817 66.168 ;
     RECT  117.601 84.384 117.923 84.408 ;
     RECT  117.713 79.44 117.971 79.464 ;
     RECT  117.445 14.208 117.973 15.384 ;
     RECT  117.251 16.56 117.973 17.352 ;
     RECT  117.973 14.208 118.001 17.352 ;
     RECT  116.675 0.048 118.069 1.128 ;
     RECT  117.061 2.304 118.069 11.544 ;
     RECT  117.745 12.864 118.069 13.128 ;
     RECT  118.001 14.208 118.115 16.104 ;
     RECT  118.069 2.304 118.213 13.128 ;
     RECT  118.115 14.208 118.213 16.056 ;
     RECT  118.213 2.304 118.261 16.056 ;
     RECT  117.817 23.04 118.289 66.168 ;
     RECT  118.069 0.048 118.501 1.176 ;
     RECT  118.261 2.256 118.501 16.056 ;
     RECT  118.501 0.048 118.577 16.056 ;
     RECT  118.001 17.136 118.649 17.352 ;
     RECT  117.389 18.576 118.789 18.6 ;
     RECT  116.104 75.504 119.029 75.528 ;
     RECT  118.577 0.048 119.267 1.176 ;
     RECT  118.289 66.144 119.297 66.168 ;
     RECT  118.577 2.256 119.317 16.056 ;
     RECT  118.289 23.04 119.329 64.824 ;
     RECT  118.549 81.84 119.413 82.44 ;
     RECT  117.733 73.536 119.621 73.56 ;
     RECT  119.317 2.256 119.653 16.392 ;
     RECT  118.789 17.856 119.653 18.6 ;
     RECT  119.653 2.112 119.701 18.6 ;
     RECT  119.701 2.112 119.729 18.888 ;
     RECT  118.597 79.824 119.749 79.848 ;
     RECT  119.749 79.824 119.843 80.376 ;
     RECT  119.729 2.256 119.869 18.888 ;
     RECT  119.365 19.968 119.869 19.992 ;
     RECT  119.869 2.256 119.891 19.992 ;
     RECT  119.029 75.504 119.905 75.864 ;
     RECT  119.413 81.84 119.905 82.728 ;
     RECT  119.905 81.168 119.939 82.728 ;
     RECT  119.843 79.824 119.981 79.848 ;
     RECT  119.905 74.976 120.013 75.864 ;
     RECT  31.205 86.4 120.049 127.464 ;
     RECT  119.891 2.256 120.083 17.16 ;
     RECT  119.267 0.048 120.373 0.264 ;
     RECT  119.891 18.24 120.625 19.992 ;
     RECT  117.713 78.336 120.661 78.36 ;
     RECT  120.625 18.24 120.697 20.52 ;
     RECT  120.697 18.24 120.709 20.568 ;
     RECT  120.517 67.248 120.709 67.272 ;
     RECT  120.013 74.976 120.757 76.056 ;
     RECT  120.083 2.304 120.853 17.16 ;
     RECT  120.709 18.24 120.853 21.144 ;
     RECT  120.841 71.232 120.853 71.256 ;
     RECT  119.939 82.656 120.877 82.728 ;
     RECT  120.853 2.304 120.901 21.144 ;
     RECT  119.329 22.224 120.901 64.824 ;
     RECT  120.709 67.248 120.901 67.896 ;
     RECT  119.939 81.168 120.901 81.192 ;
     RECT  120.841 72.96 120.985 72.984 ;
     RECT  120.757 74.112 120.985 76.056 ;
     RECT  120.877 82.656 120.985 83.256 ;
     RECT  120.853 70.704 120.997 71.256 ;
     RECT  120.985 72.96 121.045 76.056 ;
     RECT  120.049 86.016 121.057 127.464 ;
     RECT  120.901 2.304 121.093 64.824 ;
     RECT  120.181 69.552 121.093 69.576 ;
     RECT  120.997 70.704 121.093 71.832 ;
     RECT  120.661 78.336 121.093 79.464 ;
     RECT  120.901 81.168 121.093 81.528 ;
     RECT  120.985 82.656 121.093 83.832 ;
     RECT  121.093 2.256 121.139 64.824 ;
     RECT  121.139 2.256 121.205 21.72 ;
     RECT  121.205 2.256 121.208 21.612 ;
     RECT  120.901 67.248 121.208 68.04 ;
     RECT  121.093 69.552 121.208 71.832 ;
     RECT  121.045 72.96 121.208 76.968 ;
     RECT  121.093 78.048 121.208 79.464 ;
     RECT  121.093 81.168 121.208 83.832 ;
     RECT  121.208 2.148 121.312 21.612 ;
     RECT  121.208 66.948 121.312 84.252 ;
     RECT  121.208 129.588 121.312 149.052 ;
     RECT  121.312 2.148 121.504 21.342 ;
     RECT  121.312 67.218 121.504 84.252 ;
     RECT  121.312 129.858 121.504 148.782 ;
     RECT  121.504 78.672 121.565 83.832 ;
     RECT  120.373 0.048 121.765 1.176 ;
     RECT  121.504 2.148 121.765 19.8 ;
     RECT  121.765 0.048 121.907 19.8 ;
     RECT  121.907 0.048 122.033 0.6 ;
     RECT  121.057 85.488 122.149 127.464 ;
     RECT  121.907 2.208 122.213 19.8 ;
     RECT  121.504 21.12 122.317 21.342 ;
     RECT  121.565 83.712 122.485 83.832 ;
     RECT  122.149 84.912 122.485 127.464 ;
     RECT  121.565 78.672 122.533 82.632 ;
     RECT  122.533 78.624 122.569 82.632 ;
     RECT  122.485 83.712 122.569 127.464 ;
     RECT  121.504 67.296 122.573 77.496 ;
     RECT  122.569 78.624 122.605 127.464 ;
     RECT  122.317 21.12 122.629 21.576 ;
     RECT  122.213 2.304 122.641 19.8 ;
     RECT  122.573 67.296 122.641 76.632 ;
     RECT  122.641 2.304 122.677 19.944 ;
     RECT  122.629 21.12 122.677 21.96 ;
     RECT  121.139 23.04 122.832 64.824 ;
     RECT  122.605 78.576 122.832 127.464 ;
     RECT  122.677 2.304 122.897 21.96 ;
     RECT  122.641 67.248 122.897 76.632 ;
     RECT  122.897 2.352 122.969 21.96 ;
     RECT  122.897 67.248 123.011 76.488 ;
     RECT  122.969 2.592 123.073 21.96 ;
     RECT  122.832 23.04 123.073 63.72 ;
     RECT  123.073 2.592 123.077 63.72 ;
     RECT  123.011 67.248 123.077 76.392 ;
     RECT  123.077 2.592 123.107 23.64 ;
     RECT  122.832 78.576 123.107 126.36 ;
     RECT  123.107 78.576 123.109 86.232 ;
     RECT  123.107 2.592 123.155 23.352 ;
     RECT  123.077 24.72 123.155 63.72 ;
     RECT  123.155 25.008 123.185 63.72 ;
     RECT  123.185 25.488 123.251 63.72 ;
     RECT  123.109 77.664 123.251 86.232 ;
     RECT  123.077 69.84 123.257 75.432 ;
     RECT  123.251 77.664 123.257 86.136 ;
     RECT  123.107 87.36 123.257 126.36 ;
     RECT  123.257 77.664 123.293 85.656 ;
     RECT  123.073 64.944 123.347 64.968 ;
     RECT  122.033 0.048 123.397 0.168 ;
     RECT  123.077 67.248 123.397 68.856 ;
     RECT  123.155 2.592 123.473 23.208 ;
     RECT  123.293 77.664 123.509 77.688 ;
     RECT  123.293 78.72 123.509 85.656 ;
     RECT  123.397 66.72 123.539 68.856 ;
     RECT  123.509 78.72 123.539 85.368 ;
     RECT  123.251 25.68 123.635 63.72 ;
     RECT  123.539 79.44 123.635 85.368 ;
     RECT  123.257 87.36 123.653 126.168 ;
     RECT  123.635 27.504 123.683 63.72 ;
     RECT  123.635 81.024 123.683 85.368 ;
     RECT  123.397 0.048 123.731 0.312 ;
     RECT  123.653 87.36 123.731 88.92 ;
     RECT  123.683 81.168 123.761 85.368 ;
     RECT  123.653 90.528 123.761 126.168 ;
     RECT  123.635 25.68 123.797 26.472 ;
     RECT  123.761 81.168 123.827 83.208 ;
     RECT  123.731 87.36 123.827 87.384 ;
     RECT  123.761 90.528 123.833 125.784 ;
     RECT  123.539 67.248 123.875 68.856 ;
     RECT  123.683 27.504 123.905 27.816 ;
     RECT  123.833 90.528 123.941 91.128 ;
     RECT  123.731 88.896 123.977 88.92 ;
     RECT  123.257 73.104 124.067 75.432 ;
     RECT  123.905 27.792 124.085 27.816 ;
     RECT  123.875 67.344 124.085 68.856 ;
     RECT  123.833 92.16 124.085 125.784 ;
     RECT  124.085 92.16 124.121 92.328 ;
     RECT  123.683 29.136 124.157 63.72 ;
     RECT  124.085 93.408 124.157 125.784 ;
     RECT  123.473 2.592 124.165 17.112 ;
     RECT  124.157 93.408 124.193 113.976 ;
     RECT  124.157 56.88 124.229 61.128 ;
     RECT  124.157 115.104 124.229 125.688 ;
     RECT  123.797 25.68 124.261 26.232 ;
     RECT  124.157 29.136 124.265 55.656 ;
     RECT  124.229 56.88 124.265 61.032 ;
     RECT  124.193 93.408 124.265 108.408 ;
     RECT  124.193 109.632 124.265 113.976 ;
     RECT  124.229 115.104 124.265 125.592 ;
     RECT  123.941 90.528 124.301 90.744 ;
     RECT  124.265 99.936 124.301 101.304 ;
     RECT  124.165 2.304 124.307 17.112 ;
     RECT  123.827 81.168 124.307 82.44 ;
     RECT  124.085 67.44 124.333 68.856 ;
     RECT  123.257 69.84 124.333 71.832 ;
     RECT  124.307 81.168 124.355 81.192 ;
     RECT  123.473 18.192 124.373 23.208 ;
     RECT  124.157 62.16 124.373 63.24 ;
     RECT  124.373 21.648 124.405 23.208 ;
     RECT  124.261 25.104 124.405 26.232 ;
     RECT  124.333 67.44 124.517 71.832 ;
     RECT  124.517 68.88 124.547 71.832 ;
     RECT  124.405 21.648 124.549 23.688 ;
     RECT  124.373 62.352 124.553 63.24 ;
     RECT  124.301 90.72 124.553 90.744 ;
     RECT  124.405 1.152 124.595 1.176 ;
     RECT  124.553 62.352 124.697 63.048 ;
     RECT  124.547 68.88 124.697 71.592 ;
     RECT  124.067 74.976 124.739 75.432 ;
     RECT  124.549 21.648 124.741 23.928 ;
     RECT  124.405 24.96 124.741 26.232 ;
     RECT  124.307 2.304 124.789 15.432 ;
     RECT  123.731 0.048 124.837 0.168 ;
     RECT  124.265 29.136 124.837 41.448 ;
     RECT  124.301 100.128 124.841 101.304 ;
     RECT  124.697 71.568 124.931 71.592 ;
     RECT  123.635 79.44 125.029 79.992 ;
     RECT  124.837 28.464 125.057 41.448 ;
     RECT  124.517 67.44 125.075 67.752 ;
     RECT  124.307 16.56 125.077 17.112 ;
     RECT  124.373 18.192 125.077 19.992 ;
     RECT  124.741 21.648 125.077 26.232 ;
     RECT  124.121 92.304 125.089 92.328 ;
     RECT  125.089 86.064 125.161 86.088 ;
     RECT  125.089 92.304 125.161 92.376 ;
     RECT  124.265 93.408 125.161 98.616 ;
     RECT  125.077 21.648 125.165 26.712 ;
     RECT  125.057 36.48 125.165 41.448 ;
     RECT  124.265 56.88 125.165 60.936 ;
     RECT  125.077 16.56 125.171 19.992 ;
     RECT  125.057 28.464 125.171 35.352 ;
     RECT  125.161 85.536 125.171 86.088 ;
     RECT  124.307 82.176 125.173 82.44 ;
     RECT  124.789 2.256 125.233 15.432 ;
     RECT  124.697 62.544 125.237 63.048 ;
     RECT  125.171 85.536 125.305 85.752 ;
     RECT  125.161 88.416 125.305 88.44 ;
     RECT  125.165 21.648 125.309 26.28 ;
     RECT  125.171 28.464 125.309 35.16 ;
     RECT  125.161 92.304 125.309 98.616 ;
     RECT  125.029 79.44 125.315 80.952 ;
     RECT  125.173 82.176 125.315 82.68 ;
     RECT  125.305 85.488 125.315 85.752 ;
     RECT  125.309 92.352 125.315 98.616 ;
     RECT  125.305 88.368 125.363 88.44 ;
     RECT  125.315 92.88 125.363 98.616 ;
     RECT  125.237 62.544 125.381 62.856 ;
     RECT  125.309 21.648 125.411 24.312 ;
     RECT  125.309 28.656 125.411 35.16 ;
     RECT  125.315 85.488 125.411 85.656 ;
     RECT  125.411 21.648 125.413 23.112 ;
     RECT  125.165 36.48 125.417 38.184 ;
     RECT  125.165 59.952 125.417 60.936 ;
     RECT  125.171 19.488 125.453 19.992 ;
     RECT  125.165 56.88 125.453 58.824 ;
     RECT  124.265 113.856 125.453 113.976 ;
     RECT  124.265 119.52 125.453 119.64 ;
     RECT  125.413 21.072 125.461 23.112 ;
     RECT  125.411 24.288 125.489 24.312 ;
     RECT  125.411 28.656 125.489 34.776 ;
     RECT  125.363 92.928 125.489 98.616 ;
     RECT  124.067 73.104 125.507 73.8 ;
     RECT  125.233 1.68 125.509 15.432 ;
     RECT  125.509 1.68 125.521 15.48 ;
     RECT  125.171 16.56 125.521 18.264 ;
     RECT  125.489 28.656 125.525 34.728 ;
     RECT  124.265 43.152 125.525 43.848 ;
     RECT  124.265 51.6 125.525 55.656 ;
     RECT  125.453 57.936 125.525 58.824 ;
     RECT  124.265 115.584 125.525 116.184 ;
     RECT  125.521 1.68 125.555 18.264 ;
     RECT  125.315 79.44 125.555 79.992 ;
     RECT  124.837 0.048 125.557 0.312 ;
     RECT  125.269 83.664 125.557 83.688 ;
     RECT  125.417 37.584 125.561 38.184 ;
     RECT  125.165 39.504 125.561 41.448 ;
     RECT  124.265 46.128 125.561 47.592 ;
     RECT  125.525 51.6 125.561 55.08 ;
     RECT  125.453 56.88 125.561 56.904 ;
     RECT  125.525 58.608 125.561 58.824 ;
     RECT  125.417 59.952 125.561 60.072 ;
     RECT  124.697 68.88 125.561 69.864 ;
     RECT  124.841 100.992 125.561 101.304 ;
     RECT  125.453 113.856 125.561 113.88 ;
     RECT  124.265 117.216 125.561 118.488 ;
     RECT  125.453 119.52 125.561 119.544 ;
     RECT  124.265 120.672 125.561 121.848 ;
     RECT  124.265 124.128 125.561 124.152 ;
     RECT  125.561 37.584 125.597 37.608 ;
     RECT  125.525 43.152 125.597 43.176 ;
     RECT  124.265 44.88 125.597 44.904 ;
     RECT  125.561 46.128 125.597 46.632 ;
     RECT  124.265 50.16 125.597 50.376 ;
     RECT  125.561 54.096 125.597 54.504 ;
     RECT  125.561 58.608 125.597 58.632 ;
     RECT  125.561 101.28 125.597 101.304 ;
     RECT  124.265 102.816 125.597 102.84 ;
     RECT  124.265 107.04 125.597 107.736 ;
     RECT  124.265 110.4 125.597 111.096 ;
     RECT  124.265 112.8 125.597 112.824 ;
     RECT  125.561 118.464 125.597 118.488 ;
     RECT  125.555 2.544 125.603 18.264 ;
     RECT  125.461 20.976 125.603 23.112 ;
     RECT  125.363 88.368 125.603 88.392 ;
     RECT  125.597 54.48 125.633 54.504 ;
     RECT  125.557 0.048 126.275 1.176 ;
     RECT  125.603 2.544 126.608 15.48 ;
     RECT  125.603 16.656 126.608 18.264 ;
     RECT  125.453 19.488 126.608 19.512 ;
     RECT  125.603 21.072 126.608 23.112 ;
     RECT  125.309 25.536 126.608 26.28 ;
     RECT  125.953 27.312 126.608 27.336 ;
     RECT  125.525 28.896 126.608 34.728 ;
     RECT  125.417 36.48 126.608 36.504 ;
     RECT  125.561 40.944 126.608 40.968 ;
     RECT  124.265 48.912 126.608 48.936 ;
     RECT  125.597 50.352 126.608 50.376 ;
     RECT  125.561 51.6 126.608 51.624 ;
     RECT  125.561 60.048 126.608 60.072 ;
     RECT  125.381 62.832 126.608 62.856 ;
     RECT  125.075 67.44 126.608 67.464 ;
     RECT  125.561 69.84 126.608 69.864 ;
     RECT  125.701 71.232 126.608 71.256 ;
     RECT  125.507 73.776 126.608 73.8 ;
     RECT  124.739 75.408 126.608 75.432 ;
     RECT  125.555 79.44 126.608 79.464 ;
     RECT  125.315 82.176 126.608 82.2 ;
     RECT  125.557 83.232 126.608 83.688 ;
     RECT  125.411 85.488 126.608 85.512 ;
     RECT  126.325 90.624 126.608 90.648 ;
     RECT  125.489 92.928 126.608 98.472 ;
     RECT  124.265 104.64 126.608 104.664 ;
     RECT  125.525 116.16 126.608 116.184 ;
     RECT  125.561 117.216 126.608 117.24 ;
     RECT  125.561 121.248 126.608 121.272 ;
     RECT  126.608 2.148 126.712 149.052 ;
     RECT  126.712 2.148 126.904 148.782 ;
     RECT  126.904 29.28 127.043 36.024 ;
     RECT  126.904 73.776 127.043 73.8 ;
     RECT  127.043 29.28 127.073 35.928 ;
     RECT  126.904 82.176 127.139 82.2 ;
     RECT  126.904 2.148 127.181 13.56 ;
     RECT  126.904 92.256 127.217 93.432 ;
     RECT  126.275 0.048 127.237 0.408 ;
     RECT  127.181 2.148 127.237 13.128 ;
     RECT  127.237 0.048 127.283 13.128 ;
     RECT  126.904 15.984 127.325 16.92 ;
     RECT  127.283 0.048 127.379 1.368 ;
     RECT  126.904 87.936 127.379 87.96 ;
     RECT  126.904 84.816 127.397 84.936 ;
     RECT  127.325 16.56 127.433 16.92 ;
     RECT  127.073 29.28 127.433 35.16 ;
     RECT  127.433 29.28 127.469 33.912 ;
     RECT  127.433 16.56 127.475 16.584 ;
     RECT  127.433 35.136 127.505 35.16 ;
     RECT  126.904 90.624 127.619 90.648 ;
     RECT  127.217 92.256 127.649 93.048 ;
     RECT  126.904 94.56 127.667 98.472 ;
     RECT  127.469 29.28 127.685 33.864 ;
     RECT  126.904 45.936 127.763 45.96 ;
     RECT  127.283 2.88 127.793 13.128 ;
     RECT  127.685 29.28 127.865 32.52 ;
     RECT  127.685 33.504 127.937 33.864 ;
     RECT  126.904 66.72 127.937 66.744 ;
     RECT  127.649 92.976 128.185 93.048 ;
     RECT  127.379 1.152 128.293 1.368 ;
     RECT  127.793 2.88 128.293 4.152 ;
     RECT  128.245 23.28 128.297 23.304 ;
     RECT  127.793 5.136 128.341 13.128 ;
     RECT  128.341 5.136 128.405 13.224 ;
     RECT  128.509 52.608 128.579 52.632 ;
     RECT  126.904 42.144 128.581 42.168 ;
     RECT  128.405 5.136 128.729 13.128 ;
     RECT  128.293 1.152 128.761 4.152 ;
     RECT  128.729 5.136 128.761 9.288 ;
     RECT  126.904 25.536 128.761 25.56 ;
     RECT  128.761 25.536 128.819 25.704 ;
     RECT  127.379 0.048 128.821 0.168 ;
     RECT  128.761 1.152 128.821 9.288 ;
     RECT  128.821 0.048 128.909 9.288 ;
     RECT  127.667 94.8 129.017 98.472 ;
     RECT  128.819 25.536 129.089 25.56 ;
     RECT  128.729 10.56 129.197 13.128 ;
     RECT  129.197 10.56 129.233 12.456 ;
     RECT  128.185 92.976 129.253 93.384 ;
     RECT  128.909 0.048 129.299 1.368 ;
     RECT  129.253 92.928 129.305 93.384 ;
     RECT  128.909 2.352 129.377 9.288 ;
     RECT  128.581 41.616 129.377 42.168 ;
     RECT  129.017 96.768 129.377 98.472 ;
     RECT  129.049 81.792 129.443 81.816 ;
     RECT  129.409 51.888 129.491 51.912 ;
     RECT  129.397 83.04 129.493 83.064 ;
     RECT  129.493 82.656 129.517 83.064 ;
     RECT  129.017 94.8 129.517 95.784 ;
     RECT  129.481 38.64 129.539 38.664 ;
     RECT  129.377 41.616 129.539 41.64 ;
     RECT  129.517 82.656 129.557 83.16 ;
     RECT  129.517 64.08 129.587 64.104 ;
     RECT  129.557 83.136 129.587 83.16 ;
     RECT  129.493 47.28 129.589 47.304 ;
     RECT  129.541 66.432 129.589 66.456 ;
     RECT  129.493 78.672 129.625 78.696 ;
     RECT  129.589 66.432 129.629 66.744 ;
     RECT  129.629 66.72 129.635 66.744 ;
     RECT  129.589 72.384 129.635 72.408 ;
     RECT  129.493 86.592 129.635 86.616 ;
     RECT  129.589 46.896 129.665 47.304 ;
     RECT  129.377 2.592 129.733 9.288 ;
     RECT  129.233 10.56 129.733 11.832 ;
     RECT  127.865 29.28 129.733 32.088 ;
     RECT  129.733 29.28 129.809 32.52 ;
     RECT  129.299 1.152 129.875 1.368 ;
     RECT  129.733 2.592 129.875 11.832 ;
     RECT  129.305 92.928 129.875 92.952 ;
     RECT  129.841 37.056 129.923 37.08 ;
     RECT  129.625 78.672 129.949 79.608 ;
     RECT  129.875 2.592 129.971 10.344 ;
     RECT  129.949 78.672 129.973 80.424 ;
     RECT  129.973 78.672 130.019 81.672 ;
     RECT  129.517 94.032 130.019 95.784 ;
     RECT  129.625 14.832 130.021 14.856 ;
     RECT  130.019 80.352 130.025 81.672 ;
     RECT  126.904 69.84 130.067 69.864 ;
     RECT  130.025 81.648 130.115 81.672 ;
     RECT  129.973 90.624 130.115 90.648 ;
     RECT  130.019 78.672 130.133 79.08 ;
     RECT  130.021 14.784 130.163 14.856 ;
     RECT  130.165 86.64 130.241 86.76 ;
     RECT  129.809 29.28 130.313 32.472 ;
     RECT  130.163 14.832 130.355 14.856 ;
     RECT  130.313 29.28 130.355 32.184 ;
     RECT  129.299 0.048 130.357 0.12 ;
     RECT  129.875 1.152 130.357 1.176 ;
     RECT  130.133 78.672 130.403 78.696 ;
     RECT  129.875 11.424 130.417 11.832 ;
     RECT  129.665 47.28 130.493 47.304 ;
     RECT  130.019 94.608 130.501 95.784 ;
     RECT  129.377 97.104 130.501 98.472 ;
     RECT  127.397 84.816 130.525 84.84 ;
     RECT  130.501 94.608 130.529 98.472 ;
     RECT  130.529 94.608 130.547 96.888 ;
     RECT  130.025 80.352 130.565 80.424 ;
     RECT  130.525 84.672 130.565 84.84 ;
     RECT  130.525 83.184 130.595 83.208 ;
     RECT  130.241 86.64 130.595 86.712 ;
     RECT  129.971 2.592 130.633 9.72 ;
     RECT  130.355 29.28 130.633 32.088 ;
     RECT  130.547 96.288 130.637 96.888 ;
     RECT  130.549 87.792 130.669 87.816 ;
     RECT  130.637 96.336 130.673 96.888 ;
     RECT  130.669 87.792 130.739 88.536 ;
     RECT  130.673 96.336 130.739 96.36 ;
     RECT  130.739 87.792 130.781 87.816 ;
     RECT  130.547 94.608 130.787 95.208 ;
     RECT  130.565 80.4 130.835 80.424 ;
     RECT  130.597 77.52 130.997 77.544 ;
     RECT  130.595 86.64 131.027 86.664 ;
     RECT  130.357 0.048 131.077 1.176 ;
     RECT  130.633 2.304 131.077 9.72 ;
     RECT  130.417 11.424 131.209 11.88 ;
     RECT  130.633 29.088 131.221 32.088 ;
     RECT  131.209 11.424 131.245 11.976 ;
     RECT  131.077 0.048 131.317 9.72 ;
     RECT  131.245 10.848 131.317 11.976 ;
     RECT  130.489 25.68 131.353 25.704 ;
     RECT  131.221 28.512 131.653 32.088 ;
     RECT  131.317 0.048 132.008 11.976 ;
     RECT  131.353 25.68 132.008 25.8 ;
     RECT  131.653 28.512 132.008 32.232 ;
     RECT  130.565 84.672 132.008 84.696 ;
     RECT  130.787 95.184 132.008 95.208 ;
     RECT  130.529 97.872 132.008 98.472 ;
     RECT  132.008 0.048 132.112 149.052 ;
     RECT  132.112 0.048 132.304 148.782 ;
     RECT  132.304 0.048 132.437 10.92 ;
     RECT  132.304 41.904 132.509 41.928 ;
     RECT  132.437 0.048 132.611 1.176 ;
     RECT  132.437 2.16 132.803 10.92 ;
     RECT  132.304 29.664 132.803 32.088 ;
     RECT  132.304 84.672 132.851 84.696 ;
     RECT  132.803 29.664 132.899 31.464 ;
     RECT  132.803 9.456 132.905 10.92 ;
     RECT  132.905 9.456 132.995 10.824 ;
     RECT  132.304 28.608 133.091 28.632 ;
     RECT  132.611 0.048 133.121 0.6 ;
     RECT  132.803 2.16 133.235 8.472 ;
     RECT  132.304 48.96 133.265 48.984 ;
     RECT  133.121 0.048 133.373 0.168 ;
     RECT  132.304 97.872 133.373 98.184 ;
     RECT  132.995 9.456 133.379 9.912 ;
     RECT  132.899 29.664 133.405 31.176 ;
     RECT  133.477 42.72 133.523 42.744 ;
     RECT  133.441 96.336 133.523 96.36 ;
     RECT  133.379 9.456 133.625 9.72 ;
     RECT  133.235 8.448 133.661 8.472 ;
     RECT  133.585 35.904 133.667 35.928 ;
     RECT  133.657 20.976 133.763 21 ;
     RECT  132.304 25.776 133.763 25.8 ;
     RECT  133.837 56.976 133.907 57 ;
     RECT  133.405 29.616 133.945 31.176 ;
     RECT  133.235 2.16 133.955 7.464 ;
     RECT  133.945 29.616 134.003 31.368 ;
     RECT  133.957 8.88 134.051 9.144 ;
     RECT  134.003 30.816 134.051 31.368 ;
     RECT  133.955 2.16 134.053 4.584 ;
     RECT  134.051 8.88 134.057 8.904 ;
     RECT  134.005 29.04 134.057 29.064 ;
     RECT  134.053 10.848 134.099 10.872 ;
     RECT  133.955 5.616 134.201 7.464 ;
     RECT  134.201 6.816 134.237 7.464 ;
     RECT  134.053 1.968 134.243 4.584 ;
     RECT  134.089 98.64 134.243 98.664 ;
     RECT  134.197 96.864 134.273 96.888 ;
     RECT  134.243 2.304 134.345 4.584 ;
     RECT  134.051 30.816 134.381 30.84 ;
     RECT  134.201 5.616 134.417 5.64 ;
     RECT  133.373 0.048 134.533 0.12 ;
     RECT  134.533 0.048 134.597 0.6 ;
     RECT  134.237 6.864 134.633 7.464 ;
     RECT  134.633 7.44 134.675 7.464 ;
     RECT  134.345 2.304 134.777 4.248 ;
     RECT  134.777 2.304 134.921 3.336 ;
     RECT  134.597 0.048 135.029 0.168 ;
     RECT  135.029 0.144 135.059 0.168 ;
     RECT  134.921 2.304 135.101 3.192 ;
     RECT  135.101 3.168 135.461 3.192 ;
     RECT  137.408 2.148 137.512 149.052 ;
     RECT  137.512 2.418 137.704 148.782 ;
     RECT  142.808 2.148 142.912 149.052 ;
     RECT  142.912 2.418 143.104 148.782 ;
     RECT  148.208 2.148 148.312 149.052 ;
     RECT  148.312 2.418 148.504 148.782 ;
    LAYER M5 ;
     RECT  109.008 0.016 135.048 0.131 ;
     RECT  116.016 0.131 135.048 0.179 ;
     RECT  109.008 0.131 114.984 2.137 ;
     RECT  116.016 0.179 134.952 2.137 ;
     RECT  2.4 2.137 2.52 2.407 ;
     RECT  34.8 2.137 34.92 2.407 ;
     RECT  40.2 2.137 40.32 2.407 ;
     RECT  45.6 2.137 45.72 2.407 ;
     RECT  51 2.137 51.12 2.407 ;
     RECT  56.4 2.137 56.52 2.407 ;
     RECT  61.8 2.137 61.92 2.407 ;
     RECT  67.2 2.137 67.32 2.407 ;
     RECT  72.6 2.137 72.72 2.407 ;
     RECT  78 2.137 78.12 2.407 ;
     RECT  83.4 2.137 83.52 2.407 ;
     RECT  88.8 2.137 88.92 2.407 ;
     RECT  94.2 2.137 94.32 2.407 ;
     RECT  99.6 2.137 99.72 2.407 ;
     RECT  105 2.137 105.12 2.407 ;
     RECT  137.4 2.137 137.52 2.407 ;
     RECT  142.8 2.137 142.92 2.407 ;
     RECT  148.2 2.137 148.32 2.407 ;
     RECT  109.008 2.137 134.952 2.731 ;
     RECT  6.864 0.016 32.136 2.869 ;
     RECT  6.816 2.869 32.136 3.253 ;
     RECT  94.2 2.407 94.512 3.301 ;
     RECT  6.768 3.253 32.136 3.347 ;
     RECT  91.728 3.301 91.752 3.371 ;
     RECT  94.2 3.301 94.872 3.371 ;
     RECT  6.816 3.347 32.136 3.443 ;
     RECT  88.8 2.407 89.112 3.573 ;
     RECT  88.8 3.573 89.544 3.635 ;
     RECT  74.688 2.821 74.712 3.755 ;
     RECT  45.6 2.407 45.912 3.925 ;
     RECT  105 2.407 105.312 3.925 ;
     RECT  109.008 2.731 134.76 4.259 ;
     RECT  51 2.407 51.312 4.261 ;
     RECT  45.6 3.925 47.304 4.307 ;
     RECT  45.6 4.307 46.776 4.595 ;
     RECT  50.256 4.261 51.312 4.789 ;
     RECT  50.256 4.789 51.576 4.843 ;
     RECT  80.832 4.453 80.856 4.843 ;
     RECT  61.8 2.407 62.112 4.917 ;
     RECT  63.984 3.701 64.008 4.971 ;
     RECT  60.432 4.917 62.112 4.979 ;
     RECT  6.912 3.443 32.136 5.171 ;
     RECT  64.992 5.077 65.016 5.227 ;
     RECT  7.344 5.171 32.136 5.363 ;
     RECT  56.4 2.407 56.712 5.461 ;
     RECT  98.16 3.317 98.184 5.483 ;
     RECT  50.256 4.843 51.312 5.547 ;
     RECT  56.016 5.461 56.712 5.547 ;
     RECT  60.576 4.979 60.6 5.547 ;
     RECT  105 3.925 106.056 5.675 ;
     RECT  7.392 5.363 32.136 5.747 ;
     RECT  40.2 2.407 40.512 6.085 ;
     RECT  88.8 3.635 89.112 6.085 ;
     RECT  109.008 4.259 134.664 6.323 ;
     RECT  7.584 5.747 32.136 6.443 ;
     RECT  7.584 6.443 19.176 6.757 ;
     RECT  6.816 6.757 19.176 6.827 ;
     RECT  7.8 6.827 19.176 7.043 ;
     RECT  83.4 2.407 83.712 7.093 ;
     RECT  82.608 7.093 83.712 7.381 ;
     RECT  109.008 6.323 112.488 7.413 ;
     RECT  113.808 6.323 134.664 7.413 ;
     RECT  7.8 7.043 8.568 7.475 ;
     RECT  75.792 7.413 75.816 7.475 ;
     RECT  109.008 7.413 134.664 7.475 ;
     RECT  103.824 5.429 103.848 7.861 ;
     RECT  105 5.675 105.312 7.861 ;
     RECT  103.728 7.861 105.312 7.915 ;
     RECT  109.008 7.475 134.088 8.051 ;
     RECT  50.88 5.547 51.312 8.195 ;
     RECT  104.256 7.915 105.312 8.299 ;
     RECT  9.936 7.043 19.176 8.427 ;
     RECT  15.408 8.427 19.176 8.485 ;
     RECT  20.448 6.443 32.136 8.485 ;
     RECT  51 8.195 51.312 8.485 ;
     RECT  7.8 7.475 8.328 8.579 ;
     RECT  90.528 3.733 90.552 8.773 ;
     RECT  109.008 8.051 111.96 9.061 ;
     RECT  112.944 8.051 134.088 9.061 ;
     RECT  9.936 8.427 14.424 9.155 ;
     RECT  15.408 8.485 32.136 9.155 ;
     RECT  22.032 9.155 32.136 9.203 ;
     RECT  15.408 9.155 21 9.731 ;
     RECT  9.936 9.155 14.328 9.779 ;
     RECT  109.008 9.061 134.088 10.883 ;
     RECT  22.176 9.203 32.136 11.459 ;
     RECT  16.08 9.731 21 12.277 ;
     RECT  22.368 11.459 32.136 12.533 ;
     RECT  15.264 12.277 21 12.843 ;
     RECT  20.544 12.843 21 13.621 ;
     RECT  22.176 12.533 32.136 13.621 ;
     RECT  20.544 13.621 32.136 14.387 ;
     RECT  22.176 14.387 32.136 16.259 ;
     RECT  9.936 9.779 14.184 16.933 ;
     RECT  22.416 16.259 32.136 19.909 ;
     RECT  109.008 10.883 133.368 20.965 ;
     RECT  22.32 19.909 32.136 21.013 ;
     RECT  22.32 21.013 32.856 21.061 ;
     RECT  109.008 20.965 133.752 21.109 ;
     RECT  22.32 21.061 33.336 21.155 ;
     RECT  107.568 3.925 107.592 21.237 ;
     RECT  108.816 21.109 133.752 21.237 ;
     RECT  9.792 16.933 14.184 21.301 ;
     RECT  15.264 12.843 19.176 21.301 ;
     RECT  9.792 21.301 19.176 21.355 ;
     RECT  34.8 2.407 35.112 21.541 ;
     RECT  22.416 21.155 33.336 21.637 ;
     RECT  34.704 21.541 35.112 21.637 ;
     RECT  36.48 20.581 36.504 21.637 ;
     RECT  9.936 21.355 19.176 23.029 ;
     RECT  20.544 14.387 21 23.029 ;
     RECT  9.936 23.029 21 23.125 ;
     RECT  22.416 21.637 36.504 23.125 ;
     RECT  9.936 23.125 36.504 23.171 ;
     RECT  15.264 23.171 36.504 23.363 ;
     RECT  9.936 23.171 14.28 25.003 ;
     RECT  15.264 23.363 29.832 26.475 ;
     RECT  9.936 25.003 14.184 26.819 ;
     RECT  10.032 26.819 14.184 27.317 ;
     RECT  15.264 26.475 29.712 27.317 ;
     RECT  10.032 27.317 29.712 28.117 ;
     RECT  107.568 21.237 133.752 28.533 ;
     RECT  9.648 28.117 29.712 28.595 ;
     RECT  107.568 28.533 133.992 29.029 ;
     RECT  107.568 29.029 134.04 29.803 ;
     RECT  9.648 28.595 10.056 31.141 ;
     RECT  132 29.803 134.04 31.379 ;
     RECT  9.6 31.141 10.056 31.381 ;
     RECT  11.136 28.595 29.712 32.181 ;
     RECT  30.864 23.363 36.504 32.181 ;
     RECT  107.568 29.803 131.016 32.181 ;
     RECT  132 31.379 133.656 32.181 ;
     RECT  107.568 32.181 133.656 32.243 ;
     RECT  132 32.243 133.656 35.939 ;
     RECT  9.552 31.381 10.056 38.917 ;
     RECT  7.8 8.579 8.112 39.205 ;
     RECT  9.504 38.917 10.056 39.205 ;
     RECT  132 35.939 132.84 42.709 ;
     RECT  7.8 39.205 10.056 48.277 ;
     RECT  7.8 48.277 10.152 48.373 ;
     RECT  11.136 32.181 36.504 48.373 ;
     RECT  132 42.709 133.512 56.965 ;
     RECT  107.568 32.243 131.016 62.379 ;
     RECT  82.512 7.381 83.712 62.699 ;
     RECT  132 56.965 133.896 64.107 ;
     RECT  43.584 22.453 43.608 65.123 ;
     RECT  45.6 4.595 45.912 65.141 ;
     RECT  90.528 8.773 91.464 65.267 ;
     RECT  107.856 62.379 131.016 65.267 ;
     RECT  51 8.485 52.056 65.555 ;
     RECT  88.032 6.085 89.112 66.419 ;
     RECT  112.56 65.267 131.016 66.419 ;
     RECT  107.856 65.267 111.336 66.677 ;
     RECT  90.528 65.267 90.552 66.707 ;
     RECT  54.192 5.989 54.216 66.755 ;
     RECT  88.56 66.419 89.112 66.755 ;
     RECT  107.712 66.677 111.336 66.755 ;
     RECT  78 2.407 78.312 66.933 ;
     RECT  112.56 66.419 113.112 66.987 ;
     RECT  39.744 6.085 40.512 67.045 ;
     RECT  99.6 2.407 99.912 67.045 ;
     RECT  103.152 66.997 103.176 67.051 ;
     RECT  46.992 17.077 47.016 67.061 ;
     RECT  39.552 67.045 40.512 67.115 ;
     RECT  99.6 67.045 100.296 67.189 ;
     RECT  76.416 66.933 76.44 67.237 ;
     RECT  107.712 66.755 110.712 67.237 ;
     RECT  76.368 67.237 76.44 67.253 ;
     RECT  44.016 67.237 44.04 67.283 ;
     RECT  46.992 67.061 47.928 67.283 ;
     RECT  77.904 66.933 78.312 67.283 ;
     RECT  45.024 65.141 45.912 67.307 ;
     RECT  70.992 67.237 71.016 67.307 ;
     RECT  76.368 67.253 76.488 67.307 ;
     RECT  46.992 67.283 47.016 67.331 ;
     RECT  72.6 2.407 72.912 67.381 ;
     RECT  76.464 67.307 76.488 67.435 ;
     RECT  72.48 67.381 72.912 67.475 ;
     RECT  114.24 66.419 131.016 69.587 ;
     RECT  44.019 67.283 44.037 73.205 ;
     RECT  48.816 73.205 48.84 73.216 ;
     RECT  44.016 73.205 44.04 73.259 ;
     RECT  70.704 73.189 70.728 73.259 ;
     RECT  7.8 48.373 36.504 73.525 ;
     RECT  7.632 73.525 36.504 73.571 ;
     RECT  70.656 73.381 70.68 74.147 ;
     RECT  120.768 69.587 131.016 74.147 ;
     RECT  68.64 74.629 68.664 74.636 ;
     RECT  7.635 73.571 36.504 76.981 ;
     RECT  5.664 76.981 5.688 77.035 ;
     RECT  7.632 76.981 36.504 77.035 ;
     RECT  68.636 74.636 68.668 77.344 ;
     RECT  68.64 77.344 68.664 77.355 ;
     RECT  3.84 77.301 3.864 77.363 ;
     RECT  114.24 69.587 119.448 78.371 ;
     RECT  117.648 78.371 119.448 79.283 ;
     RECT  117.936 79.283 119.448 79.413 ;
     RECT  117.936 79.413 119.784 79.475 ;
     RECT  118.608 79.475 119.784 79.477 ;
     RECT  2.4 2.407 2.712 79.717 ;
     RECT  2.304 79.717 2.712 79.765 ;
     RECT  118.608 79.477 119.832 79.859 ;
     RECT  5.088 79.765 5.112 80.051 ;
     RECT  2.304 79.765 2.856 80.099 ;
     RECT  119.232 79.859 119.832 80.291 ;
     RECT  2.304 80.099 2.712 80.341 ;
     RECT  0.192 77.301 0.216 80.373 ;
     RECT  0.192 80.373 0.36 80.757 ;
     RECT  0.144 80.757 0.36 80.915 ;
     RECT  112.56 66.987 112.584 80.963 ;
     RECT  114.24 78.371 116.112 80.963 ;
     RECT  120.912 74.147 131.016 81.203 ;
     RECT  0.144 80.915 0.264 81.323 ;
     RECT  2.256 80.341 2.712 81.397 ;
     RECT  0.192 81.323 0.264 81.451 ;
     RECT  0.192 81.451 0.216 81.515 ;
     RECT  120.912 81.203 124.296 81.539 ;
     RECT  2.208 81.397 2.712 81.731 ;
     RECT  119.232 80.291 119.784 81.781 ;
     RECT  118.896 81.781 119.784 81.829 ;
     RECT  102.816 67.237 102.84 81.845 ;
     RECT  2.256 81.731 2.712 82.115 ;
     RECT  115.44 80.963 116.112 82.421 ;
     RECT  118.56 81.829 119.928 82.475 ;
     RECT  121.104 81.539 124.296 82.475 ;
     RECT  125.28 81.203 131.016 82.549 ;
     RECT  2.304 82.115 2.712 82.691 ;
     RECT  114.24 80.963 114.264 82.691 ;
     RECT  119.424 82.475 119.928 82.691 ;
     RECT  121.104 82.475 123.816 82.691 ;
     RECT  115.344 82.421 116.112 82.739 ;
     RECT  119.424 82.691 119.448 82.739 ;
     RECT  48.812 73.216 48.844 83.509 ;
     RECT  75.792 83.509 75.816 83.563 ;
     RECT  80.928 83.509 80.952 83.603 ;
     RECT  82.032 83.701 82.056 83.755 ;
     RECT  121.2 82.691 123.816 83.797 ;
     RECT  115.632 82.739 116.112 83.843 ;
     RECT  48.812 83.509 49.08 83.98 ;
     RECT  48.816 83.98 49.08 83.987 ;
     RECT  117.456 83.797 117.48 84.373 ;
     RECT  132 64.107 133.512 84.707 ;
     RECT  121.104 83.797 123.816 86.005 ;
     RECT  125.136 82.549 131.016 86.099 ;
     RECT  49.056 83.987 49.08 86.507 ;
     RECT  125.28 86.099 131.016 86.675 ;
     RECT  117.456 84.373 117.912 87.349 ;
     RECT  120.816 86.005 123.816 87.467 ;
     RECT  117.456 87.349 118.584 87.531 ;
     RECT  117.888 87.531 117.912 88.363 ;
     RECT  121.104 87.467 123.816 88.747 ;
     RECT  121.2 88.747 123.816 89.515 ;
     RECT  122.592 89.515 123.816 89.963 ;
     RECT  122.688 89.963 123.816 90.027 ;
     RECT  122.688 90.027 123.672 90.347 ;
     RECT  125.28 86.675 130.776 92.293 ;
     RECT  124.848 92.293 130.776 93.059 ;
     RECT  128.4 93.059 130.776 93.099 ;
     RECT  124.848 93.059 127.176 93.443 ;
     RECT  122.784 90.347 123.672 93.611 ;
     RECT  122.976 93.611 123.672 94.307 ;
     RECT  124.944 93.443 127.176 94.549 ;
     RECT  128.544 93.099 130.776 94.549 ;
     RECT  124.944 94.549 130.776 94.581 ;
     RECT  132 84.707 132.312 94.581 ;
     RECT  124.944 94.581 132.312 94.595 ;
     RECT  126.6 94.595 132.312 94.635 ;
     RECT  124.944 94.595 125.4 94.645 ;
     RECT  126.6 94.635 127.176 94.699 ;
     RECT  124.848 94.645 125.4 94.739 ;
     RECT  128.544 94.635 132.312 94.739 ;
     RECT  124.848 94.739 124.968 94.979 ;
     RECT  122.976 94.307 123.048 95.019 ;
     RECT  124.944 94.979 124.968 95.019 ;
     RECT  130.704 94.739 132.312 95.219 ;
     RECT  128.544 94.739 129.528 95.267 ;
     RECT  128.544 95.267 129 95.723 ;
     RECT  122.976 95.019 123 95.747 ;
     RECT  130.704 95.219 130.728 95.749 ;
     RECT  130.512 95.749 130.728 96.323 ;
     RECT  128.544 95.723 128.856 96.371 ;
     RECT  130.608 96.323 130.728 96.371 ;
     RECT  133.488 84.707 133.512 96.371 ;
     RECT  126.6 94.699 126.912 96.805 ;
     RECT  126.48 96.805 126.912 97.043 ;
     RECT  123.648 97.093 123.672 97.141 ;
     RECT  122.976 97.141 123.672 97.195 ;
     RECT  126.6 97.043 126.912 97.269 ;
     RECT  130.608 96.371 130.632 97.323 ;
     RECT  126.6 97.269 127.08 97.331 ;
     RECT  128.544 96.371 128.808 97.429 ;
     RECT  128.544 97.429 128.856 97.571 ;
     RECT  40.2 67.115 40.512 97.781 ;
     RECT  122.976 97.195 123 97.899 ;
     RECT  128.832 97.571 128.856 97.899 ;
     RECT  7.8 77.035 36.504 98.037 ;
     RECT  124.224 98.341 124.248 98.483 ;
     RECT  134.208 96.853 134.232 98.675 ;
     RECT  42.432 95.669 42.456 99.125 ;
     RECT  7.8 98.037 36.792 102.133 ;
     RECT  37.776 100.789 37.8 102.133 ;
     RECT  51 65.555 51.312 103.413 ;
     RECT  7.8 102.133 37.8 103.669 ;
     RECT  39.072 98.869 39.096 103.669 ;
     RECT  76.128 83.749 76.152 106.923 ;
     RECT  7.8 103.669 39.096 108.021 ;
     RECT  40.2 97.781 41.304 108.021 ;
     RECT  42.432 99.125 42.504 125.749 ;
     RECT  43.824 106.677 43.848 125.749 ;
     RECT  47.472 106.869 47.496 126.069 ;
     RECT  7.8 108.021 41.304 126.453 ;
     RECT  42.432 125.749 43.848 126.453 ;
     RECT  105 8.299 105.312 129.397 ;
     RECT  107.616 67.237 110.712 129.443 ;
     RECT  107.616 129.443 108.936 129.451 ;
     RECT  45.6 67.307 45.912 129.525 ;
     RECT  49.008 129.461 49.032 129.539 ;
     RECT  110.304 129.443 110.712 129.539 ;
     RECT  106.56 66.869 106.584 129.707 ;
     RECT  108.096 129.451 108.792 129.707 ;
     RECT  56.4 5.547 56.712 129.717 ;
     RECT  56.4 129.717 57.624 129.779 ;
     RECT  108.336 129.707 108.792 129.779 ;
     RECT  55.296 129.781 55.32 129.835 ;
     RECT  48.48 129.829 48.504 129.899 ;
     RECT  45.024 129.525 45.912 129.909 ;
     RECT  46.944 126.069 47.496 129.909 ;
     RECT  45.024 129.909 47.496 129.925 ;
     RECT  94.2 3.371 94.512 129.925 ;
     RECT  99.6 67.189 100.488 129.925 ;
     RECT  102.816 81.845 103.464 129.963 ;
     RECT  95.712 129.909 95.736 129.971 ;
     RECT  99.6 129.925 101.016 129.973 ;
     RECT  44.976 129.925 47.496 130.027 ;
     RECT  99.36 129.973 101.016 130.027 ;
     RECT  45.6 130.027 47.496 130.037 ;
     RECT  99.36 130.027 100.488 130.155 ;
     RECT  90.576 130.101 90.6 130.163 ;
     RECT  61.8 4.979 62.112 130.165 ;
     RECT  52.368 130.165 52.392 130.213 ;
     RECT  52.368 130.213 52.488 130.219 ;
     RECT  64.992 129.637 65.016 130.219 ;
     RECT  94.08 129.925 94.728 130.219 ;
     RECT  99.36 130.155 99.912 130.219 ;
     RECT  61.68 130.165 62.112 130.229 ;
     RECT  52.464 130.219 52.488 130.283 ;
     RECT  87.744 130.213 87.768 130.283 ;
     RECT  94.08 130.219 94.512 130.283 ;
     RECT  105 129.397 105.432 130.283 ;
     RECT  106.8 129.925 106.824 130.283 ;
     RECT  108.336 129.779 108.36 130.283 ;
     RECT  50.16 103.413 51.312 130.293 ;
     RECT  61.584 130.229 62.112 130.307 ;
     RECT  7.8 126.453 43.848 130.347 ;
     RECT  55.248 130.293 55.272 130.355 ;
     RECT  56.4 129.779 57.48 130.355 ;
     RECT  38.448 130.347 43.848 130.539 ;
     RECT  60.432 130.485 60.456 130.595 ;
     RECT  102.048 129.973 102.072 130.595 ;
     RECT  103.44 129.963 103.464 130.595 ;
     RECT  45.6 130.037 48.168 130.643 ;
     RECT  7.8 130.347 37.272 130.859 ;
     RECT  7.8 130.859 36.936 133.187 ;
     RECT  38.448 130.539 42.504 134.819 ;
     RECT  38.448 134.819 40.512 141.237 ;
     RECT  1.296 139.621 1.32 141.253 ;
     RECT  1.2 141.253 1.32 143.029 ;
     RECT  38.448 141.237 40.776 143.987 ;
     RECT  1.104 143.029 1.32 144.229 ;
     RECT  41.904 134.819 42.504 144.275 ;
     RECT  5.088 144.229 5.112 144.299 ;
     RECT  46.944 130.643 48.168 144.325 ;
     RECT  49.68 130.293 51.312 144.325 ;
     RECT  0.72 144.229 1.32 144.757 ;
     RECT  2.4 82.691 2.712 144.757 ;
     RECT  7.8 133.187 36.84 144.803 ;
     RECT  0.72 144.757 1.416 144.805 ;
     RECT  2.4 144.757 2.856 144.805 ;
     RECT  3.936 145.269 3.96 145.331 ;
     RECT  42.432 144.275 42.504 145.909 ;
     RECT  42.432 145.909 42.552 145.955 ;
     RECT  43.632 130.539 43.848 145.955 ;
     RECT  46.944 144.325 51.312 145.955 ;
     RECT  42.48 145.955 42.552 146.243 ;
     RECT  0.72 144.805 2.856 146.293 ;
     RECT  38.544 143.987 40.776 146.531 ;
     RECT  0.72 146.293 3.144 146.965 ;
     RECT  4.368 146.917 4.392 147.013 ;
     RECT  47.184 145.955 51.312 147.107 ;
     RECT  6.672 147.253 6.696 147.493 ;
     RECT  7.8 144.803 35.928 147.493 ;
     RECT  4.272 147.013 4.392 147.589 ;
     RECT  4.272 147.589 4.488 147.637 ;
     RECT  47.184 147.107 47.736 147.683 ;
     RECT  49.104 147.107 51.312 147.683 ;
     RECT  53.568 107.957 53.592 147.779 ;
     RECT  42.48 146.243 42.504 148.067 ;
     RECT  49.104 147.683 49.416 148.165 ;
     RECT  43.824 145.955 43.848 148.213 ;
     RECT  47.184 147.683 47.208 148.259 ;
     RECT  0.72 146.965 3.24 148.453 ;
     RECT  4.272 147.637 4.872 148.453 ;
     RECT  38.544 146.531 40.512 148.501 ;
     RECT  0.72 148.453 4.968 148.549 ;
     RECT  6.672 147.493 35.928 148.549 ;
     RECT  0.72 148.549 5.256 148.597 ;
     RECT  6.576 148.549 35.928 148.597 ;
     RECT  48.432 148.165 49.416 148.693 ;
     RECT  43.248 148.213 43.848 148.741 ;
     RECT  51 147.683 51.312 148.793 ;
     RECT  56.4 130.355 56.712 148.793 ;
     RECT  61.8 130.307 62.112 148.793 ;
     RECT  67.2 2.407 67.512 148.793 ;
     RECT  72.6 67.475 72.912 148.793 ;
     RECT  78 67.283 78.312 148.793 ;
     RECT  83.4 62.699 83.712 148.793 ;
     RECT  88.8 66.755 89.112 148.793 ;
     RECT  94.2 130.283 94.512 148.793 ;
     RECT  99.6 130.219 99.912 148.793 ;
     RECT  105 130.283 105.312 148.793 ;
     RECT  110.4 129.539 110.712 148.793 ;
     RECT  115.8 83.843 116.112 148.793 ;
     RECT  121.2 89.515 121.512 148.793 ;
     RECT  126.6 97.331 126.912 148.793 ;
     RECT  132 95.219 132.312 148.793 ;
     RECT  137.4 2.407 137.712 148.793 ;
     RECT  142.8 2.407 143.112 148.793 ;
     RECT  148.2 2.407 148.512 148.793 ;
     RECT  38.16 148.501 40.512 148.933 ;
     RECT  56.4 148.793 56.52 149.063 ;
     RECT  61.8 148.793 61.92 149.063 ;
     RECT  67.2 148.793 67.32 149.063 ;
     RECT  72.6 148.793 72.72 149.063 ;
     RECT  78 148.793 78.12 149.063 ;
     RECT  83.4 148.793 83.52 149.063 ;
     RECT  88.8 148.793 88.92 149.063 ;
     RECT  94.2 148.793 94.32 149.063 ;
     RECT  99.6 148.793 99.72 149.063 ;
     RECT  105 148.793 105.12 149.063 ;
     RECT  110.4 148.793 110.52 149.063 ;
     RECT  115.8 148.793 115.92 149.063 ;
     RECT  121.2 148.793 121.32 149.063 ;
     RECT  126.6 148.793 126.72 149.063 ;
     RECT  132 148.793 132.12 149.063 ;
     RECT  137.4 148.793 137.52 149.063 ;
     RECT  142.8 148.793 142.92 149.063 ;
     RECT  148.2 148.793 148.32 149.063 ;
     RECT  48.432 148.693 49.896 149.077 ;
     RECT  51 148.793 51.24 149.077 ;
     RECT  42.096 148.741 42.12 149.173 ;
     RECT  43.248 148.741 43.944 149.173 ;
     RECT  38.064 148.933 40.512 149.317 ;
     RECT  41.904 149.173 42.12 149.317 ;
     RECT  43.248 149.173 44.136 149.317 ;
     RECT  45.6 130.643 45.912 149.317 ;
     RECT  47.28 149.125 47.304 149.317 ;
     RECT  48.432 149.077 51.24 149.317 ;
     RECT  36.912 149.317 46.248 149.365 ;
     RECT  47.28 149.317 51.24 149.365 ;
     RECT  0.72 148.597 35.928 149.893 ;
     RECT  36.912 149.365 51.24 149.893 ;
     RECT  0.72 149.893 51.24 150.421 ;
     RECT  0.72 150.421 51.336 151.184 ;
    LAYER M6 ;
     RECT  0.133 80.768 0.181 81.312 ;
     RECT  0.181 77.312 0.227 77.344 ;
     RECT  0.181 80.768 0.277 81.504 ;
     RECT  0.277 80.64 0.325 81.504 ;
     RECT  0.325 80.384 2.16 81.504 ;
     RECT  2.16 79.616 2.291 81.504 ;
     RECT  2.291 79.616 2.339 81.056 ;
     RECT  2.677 150.976 2.867 151.008 ;
     RECT  0.227 77.316 3.829 77.34 ;
     RECT  2.16 144.416 3.925 145.088 ;
     RECT  3.925 144.416 5.077 145.312 ;
     RECT  3.829 77.312 5.653 77.344 ;
     RECT  5.653 76.992 5.699 77.344 ;
     RECT  2.16 4.016 6.757 4.688 ;
     RECT  6.757 3.264 6.805 4.688 ;
     RECT  6.805 2.88 7.333 4.688 ;
     RECT  7.333 2.88 7.381 5.28 ;
     RECT  6.805 6.784 7.381 6.816 ;
     RECT  5.699 76.999 7.621 77.344 ;
     RECT  7.621 76.992 7.667 77.344 ;
     RECT  9.253 72.96 9.299 72.992 ;
     RECT  9.061 150.72 9.541 150.752 ;
     RECT  7.381 2.88 9.637 6.816 ;
     RECT  9.541 149.504 9.637 150.752 ;
     RECT  9.637 149.504 9.731 150.88 ;
     RECT  2.16 90.416 9.925 91.088 ;
     RECT  9.637 2.88 10.117 6.88 ;
     RECT  10.117 2.688 10.213 6.88 ;
     RECT  7.717 0.192 10.307 0.224 ;
     RECT  2.16 25.616 10.741 26.288 ;
     RECT  9.731 149.632 10.741 150.88 ;
     RECT  2.16 101.216 10.789 101.888 ;
     RECT  10.741 149.632 10.837 151.008 ;
     RECT  10.213 2.688 10.883 7.008 ;
     RECT  10.883 3.264 10.931 5.088 ;
     RECT  10.931 3.776 11.315 5.088 ;
     RECT  9.299 72.967 11.365 72.985 ;
     RECT  11.365 72.96 11.411 72.992 ;
     RECT  10.261 105.856 11.507 105.888 ;
     RECT  10.883 6.976 11.749 7.008 ;
     RECT  11.365 52.416 12.131 52.448 ;
     RECT  11.315 3.776 12.469 4.688 ;
     RECT  9.781 21.312 12.469 21.344 ;
     RECT  12.469 3.584 12.517 4.688 ;
     RECT  10.741 24.96 12.613 26.288 ;
     RECT  2.16 112.016 12.661 112.688 ;
     RECT  12.709 106.624 12.851 106.656 ;
     RECT  12.517 3.456 12.949 4.688 ;
     RECT  11.749 6.976 12.949 7.136 ;
     RECT  5.077 144.256 12.995 145.312 ;
     RECT  12.949 3.456 13.045 7.136 ;
     RECT  12.037 56.064 13.045 56.096 ;
     RECT  2.16 68.816 13.093 69.488 ;
     RECT  13.093 68.816 13.139 69.856 ;
     RECT  13.045 2.816 13.573 7.136 ;
     RECT  13.045 55.424 13.573 56.224 ;
     RECT  2.16 58.016 13.573 58.688 ;
     RECT  12.613 24.96 14.291 27.36 ;
     RECT  12.469 21.12 14.435 21.344 ;
     RECT  14.291 25.616 14.435 27.36 ;
     RECT  13.573 2.816 14.581 8.224 ;
     RECT  14.581 2.816 14.867 8.416 ;
     RECT  13.139 68.816 15.157 69.849 ;
     RECT  15.157 68.816 15.203 69.856 ;
     RECT  13.045 116.16 15.587 116.192 ;
     RECT  2.16 47.216 15.877 47.888 ;
     RECT  14.773 114.496 15.877 114.528 ;
     RECT  14.867 4.016 15.925 8.416 ;
     RECT  15.829 117.504 15.925 117.536 ;
     RECT  15.925 4.016 16.213 8.608 ;
     RECT  16.213 3.072 16.259 8.608 ;
     RECT  15.877 49.984 16.501 50.016 ;
     RECT  13.717 51.392 16.501 51.424 ;
     RECT  16.309 148.288 16.501 148.32 ;
     RECT  10.837 149.632 16.501 151.072 ;
     RECT  16.933 66.112 16.979 66.144 ;
     RECT  16.979 66.112 16.981 66.137 ;
     RECT  13.573 55.424 17.027 58.688 ;
     RECT  16.259 3.072 17.029 7.136 ;
     RECT  15.925 116.992 17.029 117.536 ;
     RECT  16.259 8.576 17.077 8.608 ;
     RECT  17.029 2.816 17.123 7.136 ;
     RECT  17.077 8.576 17.123 9.184 ;
     RECT  17.029 116.928 17.269 117.536 ;
     RECT  15.877 114.496 17.317 115.104 ;
     RECT  17.269 116.928 17.317 118.304 ;
     RECT  17.123 6.08 17.557 7.136 ;
     RECT  17.317 114.496 17.605 118.304 ;
     RECT  14.197 45.12 17.651 45.152 ;
     RECT  17.123 2.816 17.699 4.688 ;
     RECT  16.885 52.928 17.747 53.28 ;
     RECT  17.557 6.08 17.843 7.392 ;
     RECT  17.123 9.152 17.891 9.184 ;
     RECT  17.027 57.28 17.987 58.688 ;
     RECT  17.699 2.88 18.083 4.688 ;
     RECT  12.661 112.016 18.277 112.8 ;
     RECT  11.557 29.312 18.469 29.344 ;
     RECT  13.045 108.8 18.515 108.832 ;
     RECT  14.435 21.12 18.997 21.152 ;
     RECT  18.997 21.12 19.043 21.408 ;
     RECT  17.605 114.496 19.043 118.496 ;
     RECT  16.981 65.152 19.141 66.137 ;
     RECT  19.045 0.128 19.187 0.16 ;
     RECT  19.141 65.152 19.187 66.144 ;
     RECT  2.16 36.416 19.333 37.088 ;
     RECT  18.277 112.016 19.333 112.864 ;
     RECT  15.877 46.528 19.427 47.888 ;
     RECT  19.381 23.168 19.525 23.2 ;
     RECT  17.843 7.36 19.573 7.392 ;
     RECT  18.083 4.016 19.621 4.688 ;
     RECT  16.501 49.984 19.667 51.424 ;
     RECT  19.621 4.016 19.717 4.896 ;
     RECT  19.717 3.648 19.765 4.896 ;
     RECT  18.277 12.8 19.765 12.832 ;
     RECT  19.765 12.544 19.811 12.832 ;
     RECT  19.765 3.648 19.813 5.024 ;
     RECT  19.573 6.4 19.813 7.392 ;
     RECT  19.333 2.304 19.909 2.336 ;
     RECT  19.813 3.648 19.909 7.392 ;
     RECT  19.573 40.128 19.909 40.16 ;
     RECT  14.101 110.272 19.909 110.304 ;
     RECT  17.605 107.136 19.955 107.168 ;
     RECT  19.909 2.304 20.051 7.392 ;
     RECT  19.525 23.104 20.101 23.2 ;
     RECT  20.051 3.328 20.485 7.392 ;
     RECT  19.909 39.936 20.485 40.16 ;
     RECT  20.485 62.72 20.531 62.752 ;
     RECT  19.333 111.808 20.581 112.864 ;
     RECT  19.043 114.496 20.581 114.528 ;
     RECT  19.909 34.176 20.627 34.208 ;
     RECT  20.485 3.328 20.675 8.032 ;
     RECT  17.987 57.856 20.965 58.688 ;
     RECT  20.485 39.36 21.059 40.16 ;
     RECT  19.427 47.216 21.061 47.888 ;
     RECT  19.043 116.928 21.061 118.496 ;
     RECT  20.773 120.128 21.061 120.16 ;
     RECT  9.925 89.728 21.155 91.088 ;
     RECT  19.573 104.256 21.155 104.288 ;
     RECT  20.581 111.808 21.157 114.528 ;
     RECT  2.16 122.816 21.157 123.488 ;
     RECT  20.675 3.84 21.251 8.032 ;
     RECT  19.909 109.696 21.301 110.304 ;
     RECT  21.061 116.928 21.301 120.16 ;
     RECT  21.157 122.56 21.301 123.488 ;
     RECT  21.251 4.016 21.589 8.032 ;
     RECT  21.061 47.104 21.637 47.888 ;
     RECT  19.667 49.984 21.637 50.016 ;
     RECT  20.531 62.72 21.685 62.745 ;
     RECT  19.093 86.592 21.733 86.624 ;
     RECT  21.733 86.464 21.779 86.624 ;
     RECT  21.637 47.104 21.781 50.016 ;
     RECT  19.667 51.392 21.781 51.424 ;
     RECT  21.157 111.68 21.781 114.528 ;
     RECT  18.469 29.312 21.875 30.624 ;
     RECT  21.301 116.928 21.925 120.288 ;
     RECT  21.301 122.112 21.925 123.488 ;
     RECT  19.187 65.152 22.069 65.184 ;
     RECT  19.333 36.416 22.165 37.344 ;
     RECT  16.501 148.288 22.165 151.072 ;
     RECT  19.811 12.544 22.211 12.576 ;
     RECT  19.909 10.816 22.213 10.848 ;
     RECT  21.059 39.36 22.259 39.392 ;
     RECT  21.781 47.104 22.259 51.424 ;
     RECT  21.685 62.208 22.309 62.745 ;
     RECT  21.925 116.928 22.405 123.488 ;
     RECT  22.213 124.8 22.405 124.832 ;
     RECT  20.965 56.896 22.453 58.688 ;
     RECT  22.259 47.216 22.499 51.424 ;
     RECT  21.301 108.736 22.549 110.304 ;
     RECT  22.309 60.928 22.597 62.745 ;
     RECT  22.597 60.928 22.643 62.752 ;
     RECT  22.453 56.896 22.645 58.848 ;
     RECT  22.405 116.928 22.693 124.832 ;
     RECT  22.405 104.896 22.739 104.928 ;
     RECT  17.747 53.248 22.741 53.28 ;
     RECT  21.061 41.088 22.787 41.12 ;
     RECT  21.589 4.016 22.789 8.16 ;
     RECT  22.741 53.056 22.789 54.048 ;
     RECT  17.027 55.424 22.789 55.456 ;
     RECT  19.043 21.376 22.837 21.408 ;
     RECT  21.781 111.68 22.837 115.36 ;
     RECT  22.693 116.928 22.837 125.344 ;
     RECT  22.837 21.056 22.883 21.408 ;
     RECT  10.213 94.848 22.883 94.88 ;
     RECT  22.213 10.816 22.885 11.104 ;
     RECT  22.789 53.056 22.885 55.456 ;
     RECT  22.789 4.016 22.931 9.056 ;
     RECT  21.541 93.12 22.979 93.152 ;
     RECT  22.931 4.016 22.981 7.392 ;
     RECT  22.643 60.928 23.029 62.624 ;
     RECT  22.645 56.768 23.077 58.848 ;
     RECT  23.029 60.16 23.077 62.624 ;
     RECT  22.981 2.88 23.123 7.392 ;
     RECT  22.165 147.648 23.123 151.072 ;
     RECT  22.165 36.224 23.171 37.344 ;
     RECT  22.549 108.544 23.173 110.304 ;
     RECT  22.837 111.68 23.173 125.344 ;
     RECT  22.931 8.704 23.269 9.056 ;
     RECT  22.885 10.816 23.269 11.168 ;
     RECT  23.221 28.48 23.269 28.512 ;
     RECT  21.973 96.576 23.269 96.608 ;
     RECT  23.077 56.768 23.315 62.624 ;
     RECT  21.875 30.592 23.411 30.624 ;
     RECT  23.269 28.48 23.413 28.96 ;
     RECT  23.413 28.48 23.557 30.24 ;
     RECT  2.339 79.616 23.605 80.288 ;
     RECT  23.173 108.544 23.651 125.344 ;
     RECT  10.789 99.392 23.653 101.888 ;
     RECT  23.651 111.616 23.795 125.344 ;
     RECT  12.995 144.256 23.797 145.088 ;
     RECT  23.797 33.024 23.845 33.056 ;
     RECT  23.077 34.624 23.845 34.656 ;
     RECT  22.885 52.48 23.845 55.456 ;
     RECT  23.315 56.768 23.845 60.448 ;
     RECT  20.101 23.04 23.893 23.2 ;
     RECT  21.301 106.88 23.893 106.912 ;
     RECT  23.269 8.704 24.373 11.168 ;
     RECT  23.605 79.488 24.373 80.288 ;
     RECT  23.029 40.96 24.419 40.992 ;
     RECT  23.653 99.136 24.419 101.888 ;
     RECT  23.651 108.544 24.419 109.728 ;
     RECT  23.315 62.208 24.421 62.624 ;
     RECT  22.069 64.128 24.421 65.184 ;
     RECT  14.435 25.616 24.469 26.288 ;
     RECT  23.557 27.904 24.469 30.24 ;
     RECT  24.419 99.136 24.563 99.168 ;
     RECT  24.373 8.704 24.611 11.36 ;
     RECT  23.269 96.576 24.613 96.928 ;
     RECT  23.893 23.04 24.661 23.392 ;
     RECT  23.893 105.664 24.661 106.912 ;
     RECT  24.517 45.248 24.709 45.28 ;
     RECT  24.613 95.744 24.851 96.928 ;
     RECT  24.709 93.12 24.899 93.152 ;
     RECT  21.155 90.416 24.949 91.088 ;
     RECT  24.851 96.576 24.949 96.928 ;
     RECT  24.805 98.88 24.949 99.104 ;
     RECT  23.795 111.616 24.995 125.088 ;
     RECT  22.883 21.056 24.997 21.088 ;
     RECT  24.709 45.248 24.997 45.408 ;
     RECT  24.421 62.208 24.997 65.184 ;
     RECT  15.203 68.816 24.997 69.488 ;
     RECT  23.123 4.016 25.045 7.392 ;
     RECT  24.611 8.704 25.045 8.928 ;
     RECT  23.845 33.024 25.045 34.656 ;
     RECT  24.469 126.528 25.045 126.56 ;
     RECT  23.845 52.48 25.093 60.448 ;
     RECT  24.997 62.016 25.093 66.144 ;
     RECT  24.949 90.416 25.093 93.088 ;
     RECT  25.045 4.016 25.139 8.928 ;
     RECT  24.469 13.056 25.139 13.088 ;
     RECT  25.045 31.872 25.141 34.656 ;
     RECT  25.139 4.016 25.187 8.736 ;
     RECT  24.469 25.616 25.189 30.24 ;
     RECT  25.141 31.872 25.189 35.04 ;
     RECT  25.045 126.528 25.427 127.712 ;
     RECT  24.373 79.488 25.475 80.8 ;
     RECT  25.093 52.48 25.523 66.976 ;
     RECT  23.029 17.6 25.571 17.632 ;
     RECT  25.381 40.64 25.573 40.672 ;
     RECT  25.187 4.016 25.621 8.608 ;
     RECT  24.661 23.04 25.621 24.224 ;
     RECT  25.189 25.616 25.621 35.04 ;
     RECT  24.997 44.416 25.621 45.408 ;
     RECT  22.499 47.216 25.621 50.4 ;
     RECT  24.419 108.544 25.621 109.408 ;
     RECT  24.661 104.704 25.669 106.912 ;
     RECT  25.621 2.88 25.715 8.608 ;
     RECT  25.427 126.656 25.715 127.712 ;
     RECT  25.093 89.024 25.717 93.088 ;
     RECT  24.995 111.744 25.763 125.088 ;
     RECT  25.477 0.192 25.765 0.224 ;
     RECT  25.715 8.576 25.811 8.608 ;
     RECT  25.621 44.416 25.811 51.36 ;
     RECT  24.901 42.688 25.859 42.72 ;
     RECT  24.565 74.496 25.859 74.528 ;
     RECT  25.715 127.104 25.861 127.712 ;
     RECT  25.621 108.288 25.907 109.408 ;
     RECT  25.861 127.104 25.907 127.776 ;
     RECT  25.811 44.416 25.909 45.92 ;
     RECT  25.717 88.96 26.003 93.088 ;
     RECT  25.523 53.376 26.051 66.976 ;
     RECT  21.779 86.464 26.101 86.496 ;
     RECT  26.003 89.216 26.147 93.088 ;
     RECT  25.715 2.88 26.149 6.304 ;
     RECT  25.621 23.04 26.149 35.04 ;
     RECT  23.171 36.416 26.149 37.344 ;
     RECT  25.573 38.784 26.149 40.672 ;
     RECT  24.949 96.576 26.149 99.104 ;
     RECT  26.149 95.68 26.197 99.104 ;
     RECT  24.419 101.216 26.197 101.888 ;
     RECT  25.669 104.448 26.197 106.912 ;
     RECT  25.765 0.192 26.243 0.352 ;
     RECT  24.997 21.056 26.243 21.216 ;
     RECT  26.051 53.632 26.291 66.976 ;
     RECT  26.149 2.688 26.387 6.304 ;
     RECT  24.997 68.816 26.387 70.752 ;
     RECT  25.763 111.744 26.483 115.424 ;
     RECT  23.797 144.256 26.483 145.248 ;
     RECT  25.907 108.864 26.485 109.408 ;
     RECT  25.763 116.864 26.531 125.088 ;
     RECT  26.197 95.68 26.533 102.112 ;
     RECT  26.101 86.464 26.675 87.52 ;
     RECT  26.387 2.688 26.771 5.728 ;
     RECT  26.243 0.32 26.819 0.352 ;
     RECT  26.149 36.416 26.867 40.672 ;
     RECT  26.533 95.68 26.869 102.176 ;
     RECT  26.197 103.68 26.869 106.912 ;
     RECT  26.867 38.912 26.915 40.672 ;
     RECT  26.771 2.688 27.155 5.216 ;
     RECT  26.869 95.68 27.253 106.912 ;
     RECT  26.485 108.864 27.253 109.6 ;
     RECT  25.811 47.216 27.349 51.36 ;
     RECT  27.155 3.456 27.395 5.216 ;
     RECT  25.909 42.112 27.491 42.272 ;
     RECT  25.907 127.232 27.541 127.776 ;
     RECT  26.531 116.928 27.685 125.088 ;
     RECT  27.541 126.4 27.685 127.776 ;
     RECT  26.149 23.04 27.779 35.104 ;
     RECT  27.779 31.04 27.827 35.104 ;
     RECT  26.291 55.424 27.875 66.976 ;
     RECT  26.243 21.184 27.877 21.216 ;
     RECT  27.253 95.68 27.877 109.6 ;
     RECT  26.483 111.808 27.877 115.424 ;
     RECT  27.877 95.68 27.925 115.424 ;
     RECT  26.867 36.416 27.971 37.344 ;
     RECT  27.491 42.24 27.971 42.272 ;
     RECT  27.349 47.216 27.971 51.872 ;
     RECT  27.875 57.472 27.971 66.976 ;
     RECT  27.971 51.84 27.973 51.872 ;
     RECT  26.291 53.632 27.973 54.112 ;
     RECT  26.675 86.464 27.973 86.688 ;
     RECT  26.147 89.216 27.973 93.024 ;
     RECT  27.875 55.424 28.019 55.456 ;
     RECT  27.971 58.016 28.019 61.024 ;
     RECT  27.971 62.336 28.019 66.976 ;
     RECT  27.685 116.928 28.019 127.776 ;
     RECT  28.019 116.928 28.021 123.488 ;
     RECT  28.019 60.48 28.067 61.024 ;
     RECT  27.925 95.68 28.067 115.552 ;
     RECT  25.909 43.904 28.115 45.92 ;
     RECT  27.973 51.84 28.115 54.112 ;
     RECT  28.067 95.68 28.115 114.464 ;
     RECT  28.019 124.8 28.211 127.52 ;
     RECT  27.877 21.184 28.213 21.344 ;
     RECT  28.067 60.992 28.259 61.024 ;
     RECT  28.021 116.864 28.259 123.488 ;
     RECT  26.915 39.936 28.307 40.672 ;
     RECT  27.971 47.216 28.307 50.336 ;
     RECT  28.259 119.936 28.307 123.488 ;
     RECT  27.973 86.464 28.355 93.024 ;
     RECT  28.259 116.864 28.355 118.112 ;
     RECT  28.307 119.936 28.355 120.16 ;
     RECT  28.355 86.464 28.499 87.904 ;
     RECT  28.211 125.12 28.547 127.52 ;
     RECT  28.115 51.84 28.643 51.872 ;
     RECT  27.827 31.68 28.691 35.104 ;
     RECT  27.779 23.04 28.739 29.28 ;
     RECT  28.499 86.464 28.739 86.624 ;
     RECT  28.739 23.04 28.787 23.52 ;
     RECT  28.787 23.04 28.883 23.392 ;
     RECT  27.253 129.92 28.931 129.952 ;
     RECT  28.019 62.336 28.979 65.184 ;
     RECT  27.395 4.016 28.981 5.216 ;
     RECT  28.307 40.64 29.029 40.672 ;
     RECT  28.691 32.192 29.075 35.104 ;
     RECT  29.029 40.64 29.075 40.864 ;
     RECT  24.611 10.496 29.123 11.36 ;
     RECT  28.355 89.216 29.171 93.024 ;
     RECT  29.171 89.408 29.267 93.024 ;
     RECT  28.115 95.68 29.315 113.952 ;
     RECT  28.213 136.576 29.315 136.608 ;
     RECT  28.213 20.544 29.843 21.344 ;
     RECT  24.469 131.904 29.843 131.936 ;
     RECT  28.547 125.12 29.893 127.392 ;
     RECT  29.075 32.192 29.939 32.48 ;
     RECT  29.315 95.68 29.987 113.248 ;
     RECT  29.843 20.544 30.083 20.576 ;
     RECT  28.115 43.904 30.083 43.936 ;
     RECT  29.939 32.192 30.323 32.224 ;
     RECT  29.267 90.416 30.371 93.024 ;
     RECT  28.355 117.248 30.371 118.112 ;
     RECT  29.075 33.792 30.707 35.104 ;
     RECT  28.307 47.216 30.899 48.544 ;
     RECT  29.987 105.6 30.899 113.248 ;
     RECT  28.981 3.712 30.947 5.216 ;
     RECT  28.307 121.856 30.947 123.488 ;
     RECT  29.893 125.12 30.949 127.456 ;
     RECT  28.115 45.888 31.043 45.92 ;
     RECT  30.371 92.416 31.091 93.024 ;
     RECT  28.307 50.304 31.139 50.336 ;
     RECT  29.123 10.496 31.187 10.528 ;
     RECT  30.707 33.792 31.187 35.04 ;
     RECT  28.739 24.96 31.283 29.28 ;
     RECT  23.123 148.288 31.283 151.072 ;
     RECT  31.091 92.992 31.331 93.024 ;
     RECT  28.501 18.816 31.379 18.848 ;
     RECT  30.899 105.6 31.379 109.536 ;
     RECT  31.283 25.216 31.475 29.28 ;
     RECT  28.883 23.04 31.667 23.2 ;
     RECT  29.075 40.832 31.667 40.864 ;
     RECT  28.115 54.08 31.763 54.112 ;
     RECT  31.475 25.616 31.955 29.28 ;
     RECT  31.283 148.288 31.955 149.088 ;
     RECT  28.019 66.496 32.147 66.976 ;
     RECT  25.475 79.616 32.291 80.8 ;
     RECT  31.667 23.04 32.531 23.136 ;
     RECT  31.955 148.288 32.819 148.512 ;
     RECT  31.283 150.72 33.203 151.072 ;
     RECT  33.203 150.848 33.395 151.072 ;
     RECT  30.949 125.12 33.491 127.584 ;
     RECT  31.379 105.6 33.587 109.152 ;
     RECT  31.861 129.92 33.589 129.952 ;
     RECT  31.955 25.616 33.683 26.784 ;
     RECT  33.589 129.664 33.683 129.952 ;
     RECT  30.899 112.016 33.971 113.248 ;
     RECT  33.395 150.912 34.067 151.072 ;
     RECT  34.067 150.912 34.163 150.944 ;
     RECT  31.955 28.16 34.259 29.28 ;
     RECT  32.531 23.04 34.307 23.072 ;
     RECT  34.259 29.248 34.643 29.28 ;
     RECT  33.683 129.664 35.173 129.76 ;
     RECT  33.491 125.312 35.267 127.584 ;
     RECT  35.267 125.312 35.315 127.392 ;
     RECT  31.187 35.008 35.363 35.04 ;
     RECT  35.173 129.664 35.845 130.4 ;
     RECT  29.987 95.68 36.179 103.712 ;
     RECT  36.179 97.28 36.323 103.712 ;
     RECT  35.845 129.408 36.421 130.4 ;
     RECT  36.323 97.792 36.755 103.712 ;
     RECT  33.587 105.6 36.851 108.064 ;
     RECT  36.755 100.8 36.947 103.712 ;
     RECT  36.947 100.8 37.811 101.888 ;
     RECT  36.947 103.424 38.483 103.712 ;
     RECT  35.315 125.312 38.723 126.496 ;
     RECT  33.971 112.016 39.011 112.928 ;
     RECT  36.755 97.792 39.107 99.168 ;
     RECT  36.851 106.688 39.395 108.064 ;
     RECT  30.371 118.08 39.491 118.112 ;
     RECT  28.355 119.936 40.115 119.968 ;
     RECT  35.269 141.248 40.787 141.28 ;
     RECT  39.107 97.792 41.315 97.824 ;
     RECT  38.723 125.76 42.131 126.496 ;
     RECT  36.179 95.68 42.467 95.712 ;
     RECT  39.107 99.136 42.515 99.168 ;
     RECT  36.421 129.408 42.899 130.912 ;
     RECT  42.131 125.76 43.091 126.112 ;
     RECT  32.819 148.288 43.379 148.32 ;
     RECT  39.395 106.688 43.859 108 ;
     RECT  44.005 73.216 44.051 73.248 ;
     RECT  32.293 67.072 45.013 67.104 ;
     RECT  28.979 65.152 45.059 65.184 ;
     RECT  43.091 126.08 46.979 126.112 ;
     RECT  42.899 129.472 46.979 130.912 ;
     RECT  45.013 67.072 47.939 67.296 ;
     RECT  46.979 129.472 48.179 130.848 ;
     RECT  44.051 73.223 48.805 73.241 ;
     RECT  48.805 73.216 48.851 73.248 ;
     RECT  48.179 129.472 49.043 130.528 ;
     RECT  28.739 86.464 49.091 86.496 ;
     RECT  38.483 103.424 50.195 103.456 ;
     RECT  30.947 4.016 50.245 5.216 ;
     RECT  26.483 144.256 50.675 145.088 ;
     RECT  49.043 129.6 50.867 130.528 ;
     RECT  43.859 106.88 53.603 108 ;
     RECT  50.867 129.664 60.467 130.528 ;
     RECT  50.245 4.016 60.611 5.536 ;
     RECT  60.467 129.664 61.619 130.272 ;
     RECT  60.611 4.016 63.973 5.216 ;
     RECT  63.973 3.712 65.027 5.216 ;
     RECT  61.619 129.664 65.027 130.208 ;
     RECT  7.667 77.312 68.675 77.344 ;
     RECT  48.851 73.223 70.693 73.241 ;
     RECT  70.693 73.216 70.739 73.248 ;
     RECT  47.939 67.264 72.469 67.296 ;
     RECT  65.027 3.712 74.677 4.832 ;
     RECT  53.603 106.88 76.163 106.912 ;
     RECT  72.469 67.264 76.405 67.424 ;
     RECT  76.405 66.944 76.499 67.424 ;
     RECT  74.677 3.584 80.867 4.832 ;
     RECT  49.045 83.52 80.963 83.552 ;
     RECT  75.781 7.424 82.597 7.456 ;
     RECT  28.979 62.336 88.595 63.52 ;
     RECT  80.867 3.584 89.555 4.688 ;
     RECT  87.733 130.24 90.565 130.272 ;
     RECT  89.555 4.016 91.717 4.688 ;
     RECT  90.565 130.112 94.115 130.272 ;
     RECT  94.115 130.112 95.701 130.208 ;
     RECT  91.717 3.328 98.149 4.688 ;
     RECT  98.149 3.328 98.195 5.472 ;
     RECT  95.701 129.92 99.395 130.208 ;
     RECT  99.395 129.92 100.499 130.144 ;
     RECT  100.499 129.92 102.083 130.016 ;
     RECT  102.083 129.92 102.851 129.952 ;
     RECT  82.021 83.712 103.475 83.744 ;
     RECT  82.597 7.104 103.717 7.456 ;
     RECT  98.195 4.016 103.813 5.472 ;
     RECT  103.717 7.104 104.245 7.904 ;
     RECT  103.141 129.536 105.397 129.568 ;
     RECT  103.813 4.016 106.067 5.664 ;
     RECT  76.499 66.944 106.549 67.296 ;
     RECT  88.595 62.336 107.603 62.368 ;
     RECT  106.549 66.88 107.701 67.296 ;
     RECT  105.397 129.408 108.371 130.272 ;
     RECT  108.277 21.248 108.805 21.28 ;
     RECT  107.701 66.688 108.899 67.296 ;
     RECT  108.371 129.408 108.947 129.44 ;
     RECT  108.805 21.12 109.811 21.28 ;
     RECT  109.811 21.248 109.859 21.28 ;
     RECT  106.067 4.016 110.197 4.688 ;
     RECT  104.245 7.104 110.197 8.288 ;
     RECT  110.197 4.016 110.819 8.288 ;
     RECT  27.971 36.416 110.821 37.088 ;
     RECT  110.821 35.136 110.869 37.088 ;
     RECT  110.819 4.016 111.637 5.92 ;
     RECT  111.637 3.84 111.827 5.92 ;
     RECT  110.819 7.424 111.877 8.288 ;
     RECT  111.877 7.424 112.261 9.44 ;
     RECT  111.827 3.84 112.499 4.688 ;
     RECT  112.261 7.36 113.123 9.44 ;
     RECT  108.899 66.944 113.123 67.296 ;
     RECT  112.499 3.904 113.507 4.688 ;
     RECT  113.123 7.36 114.611 8.288 ;
     RECT  103.429 81.856 115.333 81.888 ;
     RECT  114.611 7.552 115.669 8.288 ;
     RECT  115.669 7.552 116.197 8.544 ;
     RECT  115.669 10.688 116.197 10.72 ;
     RECT  113.507 4.016 116.293 4.688 ;
     RECT  116.197 7.552 116.389 10.72 ;
     RECT  116.293 4.016 116.677 5.216 ;
     RECT  116.389 7.552 116.677 10.848 ;
     RECT  116.677 7.552 116.821 11.168 ;
     RECT  116.245 2.688 117.155 2.72 ;
     RECT  2.16 14.816 117.157 15.488 ;
     RECT  116.677 4.016 117.301 5.92 ;
     RECT  116.821 7.424 117.301 11.168 ;
     RECT  117.157 13.632 117.493 15.488 ;
     RECT  117.445 87.488 117.877 87.52 ;
     RECT  117.301 4.016 117.925 11.168 ;
     RECT  117.493 13.12 117.925 15.488 ;
     RECT  32.291 79.616 117.925 80.288 ;
     RECT  113.077 17.856 118.117 17.888 ;
     RECT  116.293 19.2 118.117 19.232 ;
     RECT  117.973 64.704 118.165 64.736 ;
     RECT  117.925 4.016 118.405 15.488 ;
     RECT  118.405 4.016 118.453 15.84 ;
     RECT  118.117 17.856 118.501 19.232 ;
     RECT  117.877 87.488 118.549 88.352 ;
     RECT  115.333 81.856 118.595 82.464 ;
     RECT  118.165 64.704 118.885 64.8 ;
     RECT  113.123 67.264 118.933 67.296 ;
     RECT  26.387 68.816 118.933 69.488 ;
     RECT  118.453 2.752 119.077 15.84 ;
     RECT  119.077 2.752 119.171 16.032 ;
     RECT  118.885 64.704 119.557 65.056 ;
     RECT  119.557 64.576 119.749 65.056 ;
     RECT  117.925 79.424 119.795 80.288 ;
     RECT  33.683 25.616 119.941 26.288 ;
     RECT  118.501 17.344 120.229 19.232 ;
     RECT  119.171 3.456 120.323 13.152 ;
     RECT  120.323 6.784 120.517 13.152 ;
     RECT  119.171 14.464 120.517 16.032 ;
     RECT  115.093 23.04 120.661 23.072 ;
     RECT  119.749 64.448 120.709 65.056 ;
     RECT  120.229 17.344 120.755 19.296 ;
     RECT  120.517 6.784 120.805 16.032 ;
     RECT  120.755 17.344 120.805 17.888 ;
     RECT  120.755 19.2 120.947 19.296 ;
     RECT  120.661 23.04 120.949 23.136 ;
     RECT  120.949 22.4 121.045 23.136 ;
     RECT  120.709 64.32 121.091 65.056 ;
     RECT  118.933 67.264 121.091 69.488 ;
     RECT  120.323 3.456 121.093 5.216 ;
     RECT  121.091 67.264 121.093 67.296 ;
     RECT  121.091 68.816 121.093 69.488 ;
     RECT  118.885 81.792 121.093 81.824 ;
     RECT  118.549 87.36 121.093 88.352 ;
     RECT  121.093 66.752 121.139 67.296 ;
     RECT  121.093 75.904 121.573 75.936 ;
     RECT  121.091 64.704 121.763 65.056 ;
     RECT  121.045 22.4 121.765 23.52 ;
     RECT  121.763 65.024 121.811 65.056 ;
     RECT  119.795 79.488 121.861 80.288 ;
     RECT  121.093 87.36 121.861 88.736 ;
     RECT  30.371 90.416 121.861 91.088 ;
     RECT  121.093 2.88 121.957 5.216 ;
     RECT  120.805 6.784 121.957 17.888 ;
     RECT  121.765 21.696 122.005 23.52 ;
     RECT  119.941 25.088 122.005 26.288 ;
     RECT  121.957 2.688 122.051 17.888 ;
     RECT  122.005 21.696 122.053 26.288 ;
     RECT  121.139 66.752 122.485 66.784 ;
     RECT  121.573 75.2 122.485 75.936 ;
     RECT  122.053 21.696 122.533 27.36 ;
     RECT  122.485 74.432 122.579 75.936 ;
     RECT  120.947 19.2 122.677 19.232 ;
     RECT  122.051 4.016 122.773 17.888 ;
     RECT  122.677 19.2 122.773 19.936 ;
     RECT  122.533 21.696 122.773 28 ;
     RECT  121.861 79.168 122.821 80.288 ;
     RECT  121.093 81.792 122.821 82.464 ;
     RECT  122.773 21.696 122.869 28.128 ;
     RECT  121.861 87.36 122.869 91.088 ;
     RECT  122.869 21.696 122.917 28.576 ;
     RECT  122.917 21.696 122.965 29.088 ;
     RECT  110.869 33.92 122.965 37.088 ;
     RECT  122.773 93.568 122.965 93.6 ;
     RECT  122.869 87.36 123.011 91.232 ;
     RECT  122.773 4.016 123.013 19.936 ;
     RECT  122.965 21.696 123.013 37.088 ;
     RECT  122.821 79.168 123.013 82.592 ;
     RECT  122.579 74.432 123.061 74.464 ;
     RECT  123.011 87.36 123.061 91.088 ;
     RECT  123.061 87.232 123.107 91.088 ;
     RECT  123.013 4.016 123.155 37.088 ;
     RECT  122.051 2.688 123.203 2.72 ;
     RECT  121.093 68.816 123.299 70.496 ;
     RECT  123.061 72.96 123.491 74.464 ;
     RECT  123.301 85.056 123.635 85.088 ;
     RECT  122.965 97.152 123.683 97.888 ;
     RECT  123.013 78.912 123.731 82.592 ;
     RECT  123.107 87.232 123.731 88.16 ;
     RECT  123.491 72.96 123.779 74.144 ;
     RECT  123.731 79.616 123.779 82.592 ;
     RECT  123.107 89.664 123.779 91.088 ;
     RECT  123.731 87.232 123.827 87.264 ;
     RECT  123.779 89.984 123.827 91.088 ;
     RECT  123.155 4.016 123.875 23.136 ;
     RECT  122.579 75.84 124.115 75.936 ;
     RECT  123.779 74.112 124.259 74.144 ;
     RECT  122.485 66.752 124.357 67.36 ;
     RECT  123.299 68.816 124.357 69.488 ;
     RECT  123.875 18.048 124.403 23.136 ;
     RECT  123.155 24.96 124.643 35.04 ;
     RECT  123.875 4.016 124.691 16.736 ;
     RECT  124.403 18.048 124.691 22.496 ;
     RECT  124.691 19.2 124.787 22.496 ;
     RECT  124.691 6.976 124.883 16.736 ;
     RECT  124.787 19.2 124.883 20.768 ;
     RECT  124.643 31.936 124.883 35.04 ;
     RECT  124.643 24.96 125.027 29.6 ;
     RECT  125.027 24.96 125.125 27.168 ;
     RECT  123.779 81.792 125.171 82.592 ;
     RECT  124.691 4.016 125.317 5.664 ;
     RECT  125.125 23.872 125.363 27.168 ;
     RECT  124.883 34.112 125.365 35.04 ;
     RECT  123.155 36.416 125.365 37.088 ;
     RECT  30.899 47.216 125.365 47.888 ;
     RECT  124.787 22.464 125.411 22.496 ;
     RECT  125.363 23.872 125.459 27.04 ;
     RECT  125.027 28.736 125.459 29.6 ;
     RECT  124.883 19.2 125.699 20.384 ;
     RECT  125.459 23.872 125.701 23.904 ;
     RECT  124.883 14.816 125.749 16.736 ;
     RECT  125.749 14.816 125.795 17.056 ;
     RECT  122.965 92.928 125.891 95.712 ;
     RECT  124.115 75.904 125.987 75.936 ;
     RECT  125.701 23.296 126.131 23.904 ;
     RECT  124.883 7.104 126.323 13.152 ;
     RECT  125.459 25.616 126.371 27.04 ;
     RECT  125.317 2.88 126.373 5.664 ;
     RECT  126.323 7.104 126.373 11.424 ;
     RECT  126.373 2.88 126.419 11.424 ;
     RECT  125.365 34.112 126.469 37.088 ;
     RECT  123.683 97.856 127.045 97.888 ;
     RECT  126.419 3.712 127.139 11.424 ;
     RECT  126.323 12.736 127.187 13.152 ;
     RECT  126.469 33.536 127.187 37.088 ;
     RECT  127.187 33.536 127.283 34.72 ;
     RECT  125.317 88.384 127.283 88.416 ;
     RECT  126.949 1.728 127.331 1.76 ;
     RECT  125.365 85.504 127.333 85.536 ;
     RECT  127.333 85.504 127.379 86.752 ;
     RECT  127.139 3.712 127.427 10.592 ;
     RECT  124.883 31.936 127.621 32.224 ;
     RECT  127.283 33.536 127.621 34.144 ;
     RECT  125.891 94.656 127.621 95.712 ;
     RECT  127.427 3.712 127.763 5.152 ;
     RECT  127.621 31.936 128.099 34.144 ;
     RECT  128.099 31.936 128.197 32.672 ;
     RECT  127.763 3.712 128.243 4.96 ;
     RECT  126.131 23.296 128.291 23.328 ;
     RECT  125.891 92.928 128.435 93.088 ;
     RECT  125.699 19.2 128.531 19.232 ;
     RECT  124.357 66.752 128.627 69.488 ;
     RECT  125.795 17.024 128.819 17.056 ;
     RECT  127.045 97.28 128.867 97.888 ;
     RECT  127.187 12.736 129.011 12.768 ;
     RECT  127.621 94.592 129.011 95.712 ;
     RECT  127.427 6.784 129.157 10.592 ;
     RECT  129.157 6.272 129.349 10.592 ;
     RECT  123.779 79.616 129.397 80.288 ;
     RECT  125.171 81.792 129.397 81.824 ;
     RECT  125.365 46.976 129.445 47.888 ;
     RECT  125.459 29.568 129.539 29.6 ;
     RECT  128.099 34.112 129.539 34.144 ;
     RECT  129.397 79.616 129.539 81.824 ;
     RECT  128.243 4.016 129.541 4.96 ;
     RECT  129.349 6.272 129.541 11.424 ;
     RECT  129.445 46.976 129.635 48.992 ;
     RECT  128.627 67.84 129.635 69.488 ;
     RECT  128.435 92.928 129.731 92.96 ;
     RECT  129.301 2.304 129.781 2.336 ;
     RECT  129.541 4.016 129.781 11.424 ;
     RECT  129.781 2.304 129.925 11.424 ;
     RECT  129.539 79.616 130.019 81.568 ;
     RECT  129.925 2.304 130.067 11.744 ;
     RECT  127.379 86.72 130.499 86.752 ;
     RECT  130.067 2.688 130.501 11.744 ;
     RECT  128.197 31.424 130.547 32.672 ;
     RECT  128.867 97.28 130.643 97.312 ;
     RECT  130.501 2.688 130.883 11.872 ;
     RECT  129.011 94.592 131.123 94.624 ;
     RECT  130.883 2.688 131.171 10.336 ;
     RECT  130.883 11.712 131.843 11.872 ;
     RECT  131.843 11.84 131.891 11.872 ;
     RECT  129.925 29.76 131.939 29.792 ;
     RECT  131.171 2.688 132.419 9.44 ;
     RECT  130.547 31.424 132.419 32.544 ;
     RECT  129.493 41.92 132.419 41.952 ;
     RECT  132.419 2.688 132.659 7.456 ;
     RECT  132.419 31.424 132.899 32.096 ;
     RECT  129.635 47.216 132.899 48.992 ;
     RECT  132.659 2.688 133.043 6.88 ;
     RECT  132.419 9.408 133.333 9.44 ;
     RECT  132.899 32.064 133.667 32.096 ;
     RECT  129.541 64.064 133.907 64.096 ;
     RECT  133.333 9.408 133.955 9.76 ;
     RECT  133.955 9.728 134.003 9.76 ;
     RECT  133.045 28.544 134.003 28.576 ;
     RECT  133.043 2.688 134.051 6.816 ;
     RECT  134.051 2.688 134.435 6.304 ;
     RECT  134.435 2.688 134.579 5.92 ;
     RECT  134.579 2.688 134.963 2.72 ;
     RECT  134.579 4.016 149.04 4.688 ;
     RECT  125.795 14.816 149.04 15.488 ;
     RECT  126.371 25.616 149.04 26.288 ;
     RECT  127.187 36.416 149.04 37.088 ;
     RECT  132.899 47.216 149.04 47.888 ;
     RECT  28.019 58.016 149.04 58.688 ;
     RECT  129.635 68.816 149.04 69.488 ;
     RECT  130.019 79.616 149.04 80.288 ;
     RECT  123.827 90.416 149.04 91.088 ;
     RECT  37.811 101.216 149.04 101.888 ;
     RECT  39.011 112.016 149.04 112.688 ;
     RECT  30.947 122.816 149.04 123.488 ;
     RECT  2.16 133.616 149.04 134.288 ;
     RECT  50.675 144.416 149.04 145.088 ;
  END
END ot_nhb_pbst
END LIBRARY
